VERSION 5.8 ;
BUSBITCHARS "[]" ;
DIVIDERCHAR "/" ;
UNITS
    DATABASE MICRONS 1000 ;
END UNITS

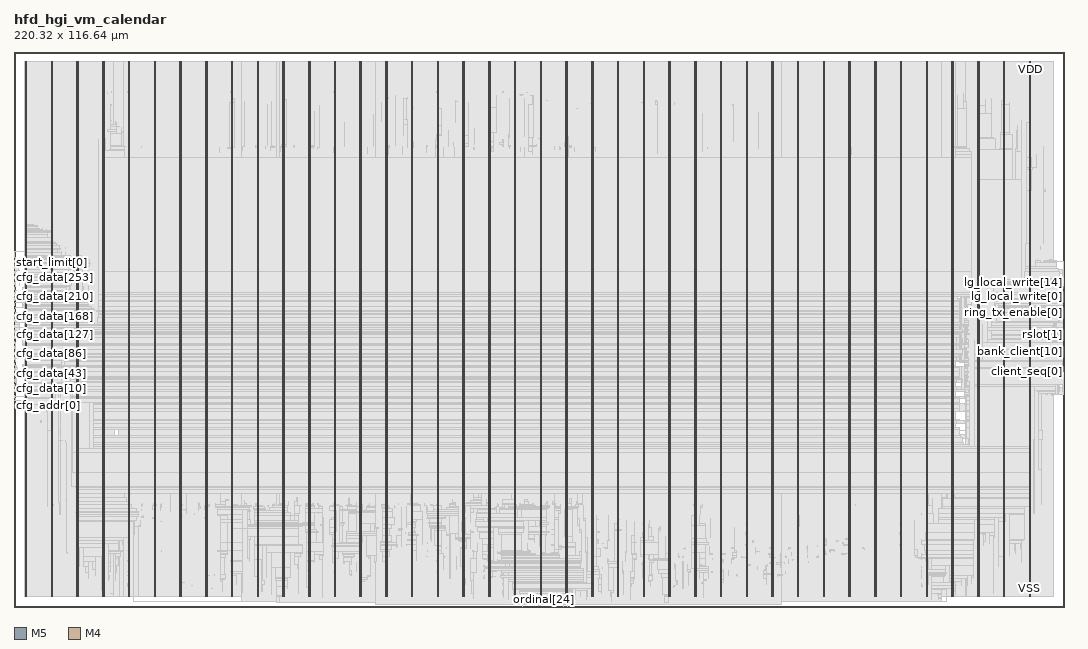
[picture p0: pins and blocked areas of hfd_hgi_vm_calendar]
MACRO hfd_hgi_vm_calendar
  FOREIGN hfd_hgi_vm_calendar 0 0 ;
  CLASS BLOCK ;
  SIZE 220.32 BY 116.64 ;
  PIN active
    DIRECTION OUTPUT ;
    USE SIGNAL ;
    PORT
      LAYER M5 ;
        RECT  108.576 0 108.6 0.084 ;
    END
  END active
  PIN bank_client[0]
    DIRECTION OUTPUT ;
    USE SIGNAL ;
    PORT
      LAYER M4 ;
        RECT  220.236 52.56 220.32 52.584 ;
    END
  END bank_client[0]
  PIN bank_client[10]
    DIRECTION OUTPUT ;
    USE SIGNAL ;
    PORT
      LAYER M4 ;
        RECT  220.236 53.52 220.32 53.544 ;
    END
  END bank_client[10]
  PIN bank_client[11]
    DIRECTION OUTPUT ;
    USE SIGNAL ;
    PORT
      LAYER M4 ;
        RECT  220.236 53.616 220.32 53.64 ;
    END
  END bank_client[11]
  PIN bank_client[12]
    DIRECTION OUTPUT ;
    USE SIGNAL ;
    PORT
      LAYER M4 ;
        RECT  220.236 53.712 220.32 53.736 ;
    END
  END bank_client[12]
  PIN bank_client[13]
    DIRECTION OUTPUT ;
    USE SIGNAL ;
    PORT
      LAYER M4 ;
        RECT  220.236 53.808 220.32 53.832 ;
    END
  END bank_client[13]
  PIN bank_client[14]
    DIRECTION OUTPUT ;
    USE SIGNAL ;
    PORT
      LAYER M4 ;
        RECT  220.236 53.904 220.32 53.928 ;
    END
  END bank_client[14]
  PIN bank_client[15]
    DIRECTION OUTPUT ;
    USE SIGNAL ;
    PORT
      LAYER M4 ;
        RECT  220.236 54 220.32 54.024 ;
    END
  END bank_client[15]
  PIN bank_client[16]
    DIRECTION OUTPUT ;
    USE SIGNAL ;
    PORT
      LAYER M4 ;
        RECT  220.236 54.096 220.32 54.12 ;
    END
  END bank_client[16]
  PIN bank_client[17]
    DIRECTION OUTPUT ;
    USE SIGNAL ;
    PORT
      LAYER M4 ;
        RECT  220.236 54.192 220.32 54.216 ;
    END
  END bank_client[17]
  PIN bank_client[18]
    DIRECTION OUTPUT ;
    USE SIGNAL ;
    PORT
      LAYER M4 ;
        RECT  220.236 54.288 220.32 54.312 ;
    END
  END bank_client[18]
  PIN bank_client[19]
    DIRECTION OUTPUT ;
    USE SIGNAL ;
    PORT
      LAYER M4 ;
        RECT  220.236 54.384 220.32 54.408 ;
    END
  END bank_client[19]
  PIN bank_client[1]
    DIRECTION OUTPUT ;
    USE SIGNAL ;
    PORT
      LAYER M4 ;
        RECT  220.236 52.656 220.32 52.68 ;
    END
  END bank_client[1]
  PIN bank_client[20]
    DIRECTION OUTPUT ;
    USE SIGNAL ;
    PORT
      LAYER M4 ;
        RECT  220.236 54.48 220.32 54.504 ;
    END
  END bank_client[20]
  PIN bank_client[21]
    DIRECTION OUTPUT ;
    USE SIGNAL ;
    PORT
      LAYER M4 ;
        RECT  220.236 54.576 220.32 54.6 ;
    END
  END bank_client[21]
  PIN bank_client[22]
    DIRECTION OUTPUT ;
    USE SIGNAL ;
    PORT
      LAYER M4 ;
        RECT  220.236 54.672 220.32 54.696 ;
    END
  END bank_client[22]
  PIN bank_client[23]
    DIRECTION OUTPUT ;
    USE SIGNAL ;
    PORT
      LAYER M4 ;
        RECT  220.236 54.768 220.32 54.792 ;
    END
  END bank_client[23]
  PIN bank_client[2]
    DIRECTION OUTPUT ;
    USE SIGNAL ;
    PORT
      LAYER M4 ;
        RECT  220.236 52.752 220.32 52.776 ;
    END
  END bank_client[2]
  PIN bank_client[3]
    DIRECTION OUTPUT ;
    USE SIGNAL ;
    PORT
      LAYER M4 ;
        RECT  220.236 52.848 220.32 52.872 ;
    END
  END bank_client[3]
  PIN bank_client[4]
    DIRECTION OUTPUT ;
    USE SIGNAL ;
    PORT
      LAYER M4 ;
        RECT  220.236 52.944 220.32 52.968 ;
    END
  END bank_client[4]
  PIN bank_client[5]
    DIRECTION OUTPUT ;
    USE SIGNAL ;
    PORT
      LAYER M4 ;
        RECT  220.236 53.04 220.32 53.064 ;
    END
  END bank_client[5]
  PIN bank_client[6]
    DIRECTION OUTPUT ;
    USE SIGNAL ;
    PORT
      LAYER M4 ;
        RECT  220.236 53.136 220.32 53.16 ;
    END
  END bank_client[6]
  PIN bank_client[7]
    DIRECTION OUTPUT ;
    USE SIGNAL ;
    PORT
      LAYER M4 ;
        RECT  220.236 53.232 220.32 53.256 ;
    END
  END bank_client[7]
  PIN bank_client[8]
    DIRECTION OUTPUT ;
    USE SIGNAL ;
    PORT
      LAYER M4 ;
        RECT  220.236 53.328 220.32 53.352 ;
    END
  END bank_client[8]
  PIN bank_client[9]
    DIRECTION OUTPUT ;
    USE SIGNAL ;
    PORT
      LAYER M4 ;
        RECT  220.236 53.424 220.32 53.448 ;
    END
  END bank_client[9]
  PIN bank_enable[0]
    DIRECTION OUTPUT ;
    USE SIGNAL ;
    PORT
      LAYER M4 ;
        RECT  220.236 51.792 220.32 51.816 ;
    END
  END bank_enable[0]
  PIN bank_enable[1]
    DIRECTION OUTPUT ;
    USE SIGNAL ;
    PORT
      LAYER M4 ;
        RECT  220.236 51.888 220.32 51.912 ;
    END
  END bank_enable[1]
  PIN bank_enable[2]
    DIRECTION OUTPUT ;
    USE SIGNAL ;
    PORT
      LAYER M4 ;
        RECT  220.236 51.984 220.32 52.008 ;
    END
  END bank_enable[2]
  PIN bank_enable[3]
    DIRECTION OUTPUT ;
    USE SIGNAL ;
    PORT
      LAYER M4 ;
        RECT  220.236 52.08 220.32 52.104 ;
    END
  END bank_enable[3]
  PIN bank_enable[4]
    DIRECTION OUTPUT ;
    USE SIGNAL ;
    PORT
      LAYER M4 ;
        RECT  220.236 52.176 220.32 52.2 ;
    END
  END bank_enable[4]
  PIN bank_enable[5]
    DIRECTION OUTPUT ;
    USE SIGNAL ;
    PORT
      LAYER M4 ;
        RECT  220.236 52.272 220.32 52.296 ;
    END
  END bank_enable[5]
  PIN bank_enable[6]
    DIRECTION OUTPUT ;
    USE SIGNAL ;
    PORT
      LAYER M4 ;
        RECT  220.236 52.368 220.32 52.392 ;
    END
  END bank_enable[6]
  PIN bank_enable[7]
    DIRECTION OUTPUT ;
    USE SIGNAL ;
    PORT
      LAYER M4 ;
        RECT  220.236 52.464 220.32 52.488 ;
    END
  END bank_enable[7]
  PIN calendar_v
    DIRECTION OUTPUT ;
    USE SIGNAL ;
    PORT
      LAYER M5 ;
        RECT  108.48 0 108.504 0.084 ;
    END
  END calendar_v
  PIN cfg_addr[0]
    DIRECTION INPUT ;
    USE SIGNAL ;
    PORT
      LAYER M4 ;
        RECT  0 43.92 0.084 43.944 ;
    END
  END cfg_addr[0]
  PIN cfg_addr[1]
    DIRECTION INPUT ;
    USE SIGNAL ;
    PORT
      LAYER M4 ;
        RECT  0 44.016 0.084 44.04 ;
    END
  END cfg_addr[1]
  PIN cfg_addr[2]
    DIRECTION INPUT ;
    USE SIGNAL ;
    PORT
      LAYER M4 ;
        RECT  0 44.112 0.084 44.136 ;
    END
  END cfg_addr[2]
  PIN cfg_addr[3]
    DIRECTION INPUT ;
    USE SIGNAL ;
    PORT
      LAYER M4 ;
        RECT  0 44.208 0.084 44.232 ;
    END
  END cfg_addr[3]
  PIN cfg_addr[4]
    DIRECTION INPUT ;
    USE SIGNAL ;
    PORT
      LAYER M4 ;
        RECT  0 44.304 0.084 44.328 ;
    END
  END cfg_addr[4]
  PIN cfg_addr[5]
    DIRECTION INPUT ;
    USE SIGNAL ;
    PORT
      LAYER M4 ;
        RECT  0 44.4 0.084 44.424 ;
    END
  END cfg_addr[5]
  PIN cfg_addr[6]
    DIRECTION INPUT ;
    USE SIGNAL ;
    PORT
      LAYER M4 ;
        RECT  0 44.496 0.084 44.52 ;
    END
  END cfg_addr[6]
  PIN cfg_addr[7]
    DIRECTION INPUT ;
    USE SIGNAL ;
    PORT
      LAYER M4 ;
        RECT  0 44.592 0.084 44.616 ;
    END
  END cfg_addr[7]
  PIN cfg_addr[8]
    DIRECTION INPUT ;
    USE SIGNAL ;
    PORT
      LAYER M4 ;
        RECT  0 44.688 0.084 44.712 ;
    END
  END cfg_addr[8]
  PIN cfg_addr[9]
    DIRECTION INPUT ;
    USE SIGNAL ;
    PORT
      LAYER M4 ;
        RECT  0 44.784 0.084 44.808 ;
    END
  END cfg_addr[9]
  PIN cfg_data[0]
    DIRECTION INPUT ;
    USE SIGNAL ;
    PORT
      LAYER M4 ;
        RECT  0 44.88 0.084 44.904 ;
    END
  END cfg_data[0]
  PIN cfg_data[100]
    DIRECTION INPUT ;
    USE SIGNAL ;
    PORT
      LAYER M4 ;
        RECT  0 54.48 0.084 54.504 ;
    END
  END cfg_data[100]
  PIN cfg_data[101]
    DIRECTION INPUT ;
    USE SIGNAL ;
    PORT
      LAYER M4 ;
        RECT  0 54.576 0.084 54.6 ;
    END
  END cfg_data[101]
  PIN cfg_data[102]
    DIRECTION INPUT ;
    USE SIGNAL ;
    PORT
      LAYER M4 ;
        RECT  0 54.672 0.084 54.696 ;
    END
  END cfg_data[102]
  PIN cfg_data[103]
    DIRECTION INPUT ;
    USE SIGNAL ;
    PORT
      LAYER M4 ;
        RECT  0 54.768 0.084 54.792 ;
    END
  END cfg_data[103]
  PIN cfg_data[104]
    DIRECTION INPUT ;
    USE SIGNAL ;
    PORT
      LAYER M4 ;
        RECT  0 54.864 0.084 54.888 ;
    END
  END cfg_data[104]
  PIN cfg_data[105]
    DIRECTION INPUT ;
    USE SIGNAL ;
    PORT
      LAYER M4 ;
        RECT  0 54.96 0.084 54.984 ;
    END
  END cfg_data[105]
  PIN cfg_data[106]
    DIRECTION INPUT ;
    USE SIGNAL ;
    PORT
      LAYER M4 ;
        RECT  0 55.056 0.084 55.08 ;
    END
  END cfg_data[106]
  PIN cfg_data[107]
    DIRECTION INPUT ;
    USE SIGNAL ;
    PORT
      LAYER M4 ;
        RECT  0 55.152 0.084 55.176 ;
    END
  END cfg_data[107]
  PIN cfg_data[108]
    DIRECTION INPUT ;
    USE SIGNAL ;
    PORT
      LAYER M4 ;
        RECT  0 55.248 0.084 55.272 ;
    END
  END cfg_data[108]
  PIN cfg_data[109]
    DIRECTION INPUT ;
    USE SIGNAL ;
    PORT
      LAYER M4 ;
        RECT  0 55.344 0.084 55.368 ;
    END
  END cfg_data[109]
  PIN cfg_data[10]
    DIRECTION INPUT ;
    USE SIGNAL ;
    PORT
      LAYER M4 ;
        RECT  0 45.84 0.084 45.864 ;
    END
  END cfg_data[10]
  PIN cfg_data[110]
    DIRECTION INPUT ;
    USE SIGNAL ;
    PORT
      LAYER M4 ;
        RECT  0 55.44 0.084 55.464 ;
    END
  END cfg_data[110]
  PIN cfg_data[111]
    DIRECTION INPUT ;
    USE SIGNAL ;
    PORT
      LAYER M4 ;
        RECT  0 55.536 0.084 55.56 ;
    END
  END cfg_data[111]
  PIN cfg_data[112]
    DIRECTION INPUT ;
    USE SIGNAL ;
    PORT
      LAYER M4 ;
        RECT  0 55.632 0.084 55.656 ;
    END
  END cfg_data[112]
  PIN cfg_data[113]
    DIRECTION INPUT ;
    USE SIGNAL ;
    PORT
      LAYER M4 ;
        RECT  0 55.728 0.084 55.752 ;
    END
  END cfg_data[113]
  PIN cfg_data[114]
    DIRECTION INPUT ;
    USE SIGNAL ;
    PORT
      LAYER M4 ;
        RECT  0 55.824 0.084 55.848 ;
    END
  END cfg_data[114]
  PIN cfg_data[115]
    DIRECTION INPUT ;
    USE SIGNAL ;
    PORT
      LAYER M4 ;
        RECT  0 55.92 0.084 55.944 ;
    END
  END cfg_data[115]
  PIN cfg_data[116]
    DIRECTION INPUT ;
    USE SIGNAL ;
    PORT
      LAYER M4 ;
        RECT  0 56.016 0.084 56.04 ;
    END
  END cfg_data[116]
  PIN cfg_data[117]
    DIRECTION INPUT ;
    USE SIGNAL ;
    PORT
      LAYER M4 ;
        RECT  0 56.112 0.084 56.136 ;
    END
  END cfg_data[117]
  PIN cfg_data[118]
    DIRECTION INPUT ;
    USE SIGNAL ;
    PORT
      LAYER M4 ;
        RECT  0 56.208 0.084 56.232 ;
    END
  END cfg_data[118]
  PIN cfg_data[119]
    DIRECTION INPUT ;
    USE SIGNAL ;
    PORT
      LAYER M4 ;
        RECT  0 56.304 0.084 56.328 ;
    END
  END cfg_data[119]
  PIN cfg_data[11]
    DIRECTION INPUT ;
    USE SIGNAL ;
    PORT
      LAYER M4 ;
        RECT  0 45.936 0.084 45.96 ;
    END
  END cfg_data[11]
  PIN cfg_data[120]
    DIRECTION INPUT ;
    USE SIGNAL ;
    PORT
      LAYER M4 ;
        RECT  0 56.4 0.084 56.424 ;
    END
  END cfg_data[120]
  PIN cfg_data[121]
    DIRECTION INPUT ;
    USE SIGNAL ;
    PORT
      LAYER M4 ;
        RECT  0 56.496 0.084 56.52 ;
    END
  END cfg_data[121]
  PIN cfg_data[122]
    DIRECTION INPUT ;
    USE SIGNAL ;
    PORT
      LAYER M4 ;
        RECT  0 56.592 0.084 56.616 ;
    END
  END cfg_data[122]
  PIN cfg_data[123]
    DIRECTION INPUT ;
    USE SIGNAL ;
    PORT
      LAYER M4 ;
        RECT  0 56.688 0.084 56.712 ;
    END
  END cfg_data[123]
  PIN cfg_data[124]
    DIRECTION INPUT ;
    USE SIGNAL ;
    PORT
      LAYER M4 ;
        RECT  0 56.784 0.084 56.808 ;
    END
  END cfg_data[124]
  PIN cfg_data[125]
    DIRECTION INPUT ;
    USE SIGNAL ;
    PORT
      LAYER M4 ;
        RECT  0 56.88 0.084 56.904 ;
    END
  END cfg_data[125]
  PIN cfg_data[126]
    DIRECTION INPUT ;
    USE SIGNAL ;
    PORT
      LAYER M4 ;
        RECT  0 56.976 0.084 57 ;
    END
  END cfg_data[126]
  PIN cfg_data[127]
    DIRECTION INPUT ;
    USE SIGNAL ;
    PORT
      LAYER M4 ;
        RECT  0 57.072 0.084 57.096 ;
    END
  END cfg_data[127]
  PIN cfg_data[128]
    DIRECTION INPUT ;
    USE SIGNAL ;
    PORT
      LAYER M4 ;
        RECT  0 57.168 0.084 57.192 ;
    END
  END cfg_data[128]
  PIN cfg_data[129]
    DIRECTION INPUT ;
    USE SIGNAL ;
    PORT
      LAYER M4 ;
        RECT  0 57.264 0.084 57.288 ;
    END
  END cfg_data[129]
  PIN cfg_data[12]
    DIRECTION INPUT ;
    USE SIGNAL ;
    PORT
      LAYER M4 ;
        RECT  0 46.032 0.084 46.056 ;
    END
  END cfg_data[12]
  PIN cfg_data[130]
    DIRECTION INPUT ;
    USE SIGNAL ;
    PORT
      LAYER M4 ;
        RECT  0 57.36 0.084 57.384 ;
    END
  END cfg_data[130]
  PIN cfg_data[131]
    DIRECTION INPUT ;
    USE SIGNAL ;
    PORT
      LAYER M4 ;
        RECT  0 57.456 0.084 57.48 ;
    END
  END cfg_data[131]
  PIN cfg_data[132]
    DIRECTION INPUT ;
    USE SIGNAL ;
    PORT
      LAYER M4 ;
        RECT  0 57.552 0.084 57.576 ;
    END
  END cfg_data[132]
  PIN cfg_data[133]
    DIRECTION INPUT ;
    USE SIGNAL ;
    PORT
      LAYER M4 ;
        RECT  0 57.648 0.084 57.672 ;
    END
  END cfg_data[133]
  PIN cfg_data[134]
    DIRECTION INPUT ;
    USE SIGNAL ;
    PORT
      LAYER M4 ;
        RECT  0 57.744 0.084 57.768 ;
    END
  END cfg_data[134]
  PIN cfg_data[135]
    DIRECTION INPUT ;
    USE SIGNAL ;
    PORT
      LAYER M4 ;
        RECT  0 57.84 0.084 57.864 ;
    END
  END cfg_data[135]
  PIN cfg_data[136]
    DIRECTION INPUT ;
    USE SIGNAL ;
    PORT
      LAYER M4 ;
        RECT  0 57.936 0.084 57.96 ;
    END
  END cfg_data[136]
  PIN cfg_data[137]
    DIRECTION INPUT ;
    USE SIGNAL ;
    PORT
      LAYER M4 ;
        RECT  0 58.032 0.084 58.056 ;
    END
  END cfg_data[137]
  PIN cfg_data[138]
    DIRECTION INPUT ;
    USE SIGNAL ;
    PORT
      LAYER M4 ;
        RECT  0 58.128 0.084 58.152 ;
    END
  END cfg_data[138]
  PIN cfg_data[139]
    DIRECTION INPUT ;
    USE SIGNAL ;
    PORT
      LAYER M4 ;
        RECT  0 58.224 0.084 58.248 ;
    END
  END cfg_data[139]
  PIN cfg_data[13]
    DIRECTION INPUT ;
    USE SIGNAL ;
    PORT
      LAYER M4 ;
        RECT  0 46.128 0.084 46.152 ;
    END
  END cfg_data[13]
  PIN cfg_data[140]
    DIRECTION INPUT ;
    USE SIGNAL ;
    PORT
      LAYER M4 ;
        RECT  0 58.32 0.084 58.344 ;
    END
  END cfg_data[140]
  PIN cfg_data[141]
    DIRECTION INPUT ;
    USE SIGNAL ;
    PORT
      LAYER M4 ;
        RECT  0 58.416 0.084 58.44 ;
    END
  END cfg_data[141]
  PIN cfg_data[142]
    DIRECTION INPUT ;
    USE SIGNAL ;
    PORT
      LAYER M4 ;
        RECT  0 58.512 0.084 58.536 ;
    END
  END cfg_data[142]
  PIN cfg_data[143]
    DIRECTION INPUT ;
    USE SIGNAL ;
    PORT
      LAYER M4 ;
        RECT  0 58.608 0.084 58.632 ;
    END
  END cfg_data[143]
  PIN cfg_data[144]
    DIRECTION INPUT ;
    USE SIGNAL ;
    PORT
      LAYER M4 ;
        RECT  0 58.704 0.084 58.728 ;
    END
  END cfg_data[144]
  PIN cfg_data[145]
    DIRECTION INPUT ;
    USE SIGNAL ;
    PORT
      LAYER M4 ;
        RECT  0 58.8 0.084 58.824 ;
    END
  END cfg_data[145]
  PIN cfg_data[146]
    DIRECTION INPUT ;
    USE SIGNAL ;
    PORT
      LAYER M4 ;
        RECT  0 58.896 0.084 58.92 ;
    END
  END cfg_data[146]
  PIN cfg_data[147]
    DIRECTION INPUT ;
    USE SIGNAL ;
    PORT
      LAYER M4 ;
        RECT  0 58.992 0.084 59.016 ;
    END
  END cfg_data[147]
  PIN cfg_data[148]
    DIRECTION INPUT ;
    USE SIGNAL ;
    PORT
      LAYER M4 ;
        RECT  0 59.088 0.084 59.112 ;
    END
  END cfg_data[148]
  PIN cfg_data[149]
    DIRECTION INPUT ;
    USE SIGNAL ;
    PORT
      LAYER M4 ;
        RECT  0 59.184 0.084 59.208 ;
    END
  END cfg_data[149]
  PIN cfg_data[14]
    DIRECTION INPUT ;
    USE SIGNAL ;
    PORT
      LAYER M4 ;
        RECT  0 46.224 0.084 46.248 ;
    END
  END cfg_data[14]
  PIN cfg_data[150]
    DIRECTION INPUT ;
    USE SIGNAL ;
    PORT
      LAYER M4 ;
        RECT  0 59.28 0.084 59.304 ;
    END
  END cfg_data[150]
  PIN cfg_data[151]
    DIRECTION INPUT ;
    USE SIGNAL ;
    PORT
      LAYER M4 ;
        RECT  0 59.376 0.084 59.4 ;
    END
  END cfg_data[151]
  PIN cfg_data[152]
    DIRECTION INPUT ;
    USE SIGNAL ;
    PORT
      LAYER M4 ;
        RECT  0 59.472 0.084 59.496 ;
    END
  END cfg_data[152]
  PIN cfg_data[153]
    DIRECTION INPUT ;
    USE SIGNAL ;
    PORT
      LAYER M4 ;
        RECT  0 59.568 0.084 59.592 ;
    END
  END cfg_data[153]
  PIN cfg_data[154]
    DIRECTION INPUT ;
    USE SIGNAL ;
    PORT
      LAYER M4 ;
        RECT  0 59.664 0.084 59.688 ;
    END
  END cfg_data[154]
  PIN cfg_data[155]
    DIRECTION INPUT ;
    USE SIGNAL ;
    PORT
      LAYER M4 ;
        RECT  0 59.76 0.084 59.784 ;
    END
  END cfg_data[155]
  PIN cfg_data[156]
    DIRECTION INPUT ;
    USE SIGNAL ;
    PORT
      LAYER M4 ;
        RECT  0 59.856 0.084 59.88 ;
    END
  END cfg_data[156]
  PIN cfg_data[157]
    DIRECTION INPUT ;
    USE SIGNAL ;
    PORT
      LAYER M4 ;
        RECT  0 59.952 0.084 59.976 ;
    END
  END cfg_data[157]
  PIN cfg_data[158]
    DIRECTION INPUT ;
    USE SIGNAL ;
    PORT
      LAYER M4 ;
        RECT  0 60.048 0.084 60.072 ;
    END
  END cfg_data[158]
  PIN cfg_data[159]
    DIRECTION INPUT ;
    USE SIGNAL ;
    PORT
      LAYER M4 ;
        RECT  0 60.144 0.084 60.168 ;
    END
  END cfg_data[159]
  PIN cfg_data[15]
    DIRECTION INPUT ;
    USE SIGNAL ;
    PORT
      LAYER M4 ;
        RECT  0 46.32 0.084 46.344 ;
    END
  END cfg_data[15]
  PIN cfg_data[160]
    DIRECTION INPUT ;
    USE SIGNAL ;
    PORT
      LAYER M4 ;
        RECT  0 60.24 0.084 60.264 ;
    END
  END cfg_data[160]
  PIN cfg_data[161]
    DIRECTION INPUT ;
    USE SIGNAL ;
    PORT
      LAYER M4 ;
        RECT  0 60.336 0.084 60.36 ;
    END
  END cfg_data[161]
  PIN cfg_data[162]
    DIRECTION INPUT ;
    USE SIGNAL ;
    PORT
      LAYER M4 ;
        RECT  0 60.432 0.084 60.456 ;
    END
  END cfg_data[162]
  PIN cfg_data[163]
    DIRECTION INPUT ;
    USE SIGNAL ;
    PORT
      LAYER M4 ;
        RECT  0 60.528 0.084 60.552 ;
    END
  END cfg_data[163]
  PIN cfg_data[164]
    DIRECTION INPUT ;
    USE SIGNAL ;
    PORT
      LAYER M4 ;
        RECT  0 60.624 0.084 60.648 ;
    END
  END cfg_data[164]
  PIN cfg_data[165]
    DIRECTION INPUT ;
    USE SIGNAL ;
    PORT
      LAYER M4 ;
        RECT  0 60.72 0.084 60.744 ;
    END
  END cfg_data[165]
  PIN cfg_data[166]
    DIRECTION INPUT ;
    USE SIGNAL ;
    PORT
      LAYER M4 ;
        RECT  0 60.816 0.084 60.84 ;
    END
  END cfg_data[166]
  PIN cfg_data[167]
    DIRECTION INPUT ;
    USE SIGNAL ;
    PORT
      LAYER M4 ;
        RECT  0 60.912 0.084 60.936 ;
    END
  END cfg_data[167]
  PIN cfg_data[168]
    DIRECTION INPUT ;
    USE SIGNAL ;
    PORT
      LAYER M4 ;
        RECT  0 61.008 0.084 61.032 ;
    END
  END cfg_data[168]
  PIN cfg_data[169]
    DIRECTION INPUT ;
    USE SIGNAL ;
    PORT
      LAYER M4 ;
        RECT  0 61.104 0.084 61.128 ;
    END
  END cfg_data[169]
  PIN cfg_data[16]
    DIRECTION INPUT ;
    USE SIGNAL ;
    PORT
      LAYER M4 ;
        RECT  0 46.416 0.084 46.44 ;
    END
  END cfg_data[16]
  PIN cfg_data[170]
    DIRECTION INPUT ;
    USE SIGNAL ;
    PORT
      LAYER M4 ;
        RECT  0 61.2 0.084 61.224 ;
    END
  END cfg_data[170]
  PIN cfg_data[171]
    DIRECTION INPUT ;
    USE SIGNAL ;
    PORT
      LAYER M4 ;
        RECT  0 61.296 0.084 61.32 ;
    END
  END cfg_data[171]
  PIN cfg_data[172]
    DIRECTION INPUT ;
    USE SIGNAL ;
    PORT
      LAYER M4 ;
        RECT  0 61.392 0.084 61.416 ;
    END
  END cfg_data[172]
  PIN cfg_data[173]
    DIRECTION INPUT ;
    USE SIGNAL ;
    PORT
      LAYER M4 ;
        RECT  0 61.488 0.084 61.512 ;
    END
  END cfg_data[173]
  PIN cfg_data[174]
    DIRECTION INPUT ;
    USE SIGNAL ;
    PORT
      LAYER M4 ;
        RECT  0 61.584 0.084 61.608 ;
    END
  END cfg_data[174]
  PIN cfg_data[175]
    DIRECTION INPUT ;
    USE SIGNAL ;
    PORT
      LAYER M4 ;
        RECT  0 61.68 0.084 61.704 ;
    END
  END cfg_data[175]
  PIN cfg_data[176]
    DIRECTION INPUT ;
    USE SIGNAL ;
    PORT
      LAYER M4 ;
        RECT  0 61.776 0.084 61.8 ;
    END
  END cfg_data[176]
  PIN cfg_data[177]
    DIRECTION INPUT ;
    USE SIGNAL ;
    PORT
      LAYER M4 ;
        RECT  0 61.872 0.084 61.896 ;
    END
  END cfg_data[177]
  PIN cfg_data[178]
    DIRECTION INPUT ;
    USE SIGNAL ;
    PORT
      LAYER M4 ;
        RECT  0 61.968 0.084 61.992 ;
    END
  END cfg_data[178]
  PIN cfg_data[179]
    DIRECTION INPUT ;
    USE SIGNAL ;
    PORT
      LAYER M4 ;
        RECT  0 62.064 0.084 62.088 ;
    END
  END cfg_data[179]
  PIN cfg_data[17]
    DIRECTION INPUT ;
    USE SIGNAL ;
    PORT
      LAYER M4 ;
        RECT  0 46.512 0.084 46.536 ;
    END
  END cfg_data[17]
  PIN cfg_data[180]
    DIRECTION INPUT ;
    USE SIGNAL ;
    PORT
      LAYER M4 ;
        RECT  0 62.16 0.084 62.184 ;
    END
  END cfg_data[180]
  PIN cfg_data[181]
    DIRECTION INPUT ;
    USE SIGNAL ;
    PORT
      LAYER M4 ;
        RECT  0 62.256 0.084 62.28 ;
    END
  END cfg_data[181]
  PIN cfg_data[182]
    DIRECTION INPUT ;
    USE SIGNAL ;
    PORT
      LAYER M4 ;
        RECT  0 62.352 0.084 62.376 ;
    END
  END cfg_data[182]
  PIN cfg_data[183]
    DIRECTION INPUT ;
    USE SIGNAL ;
    PORT
      LAYER M4 ;
        RECT  0 62.448 0.084 62.472 ;
    END
  END cfg_data[183]
  PIN cfg_data[184]
    DIRECTION INPUT ;
    USE SIGNAL ;
    PORT
      LAYER M4 ;
        RECT  0 62.544 0.084 62.568 ;
    END
  END cfg_data[184]
  PIN cfg_data[185]
    DIRECTION INPUT ;
    USE SIGNAL ;
    PORT
      LAYER M4 ;
        RECT  0 62.64 0.084 62.664 ;
    END
  END cfg_data[185]
  PIN cfg_data[186]
    DIRECTION INPUT ;
    USE SIGNAL ;
    PORT
      LAYER M4 ;
        RECT  0 62.736 0.084 62.76 ;
    END
  END cfg_data[186]
  PIN cfg_data[187]
    DIRECTION INPUT ;
    USE SIGNAL ;
    PORT
      LAYER M4 ;
        RECT  0 62.832 0.084 62.856 ;
    END
  END cfg_data[187]
  PIN cfg_data[188]
    DIRECTION INPUT ;
    USE SIGNAL ;
    PORT
      LAYER M4 ;
        RECT  0 62.928 0.084 62.952 ;
    END
  END cfg_data[188]
  PIN cfg_data[189]
    DIRECTION INPUT ;
    USE SIGNAL ;
    PORT
      LAYER M4 ;
        RECT  0 63.024 0.084 63.048 ;
    END
  END cfg_data[189]
  PIN cfg_data[18]
    DIRECTION INPUT ;
    USE SIGNAL ;
    PORT
      LAYER M4 ;
        RECT  0 46.608 0.084 46.632 ;
    END
  END cfg_data[18]
  PIN cfg_data[190]
    DIRECTION INPUT ;
    USE SIGNAL ;
    PORT
      LAYER M4 ;
        RECT  0 63.12 0.084 63.144 ;
    END
  END cfg_data[190]
  PIN cfg_data[191]
    DIRECTION INPUT ;
    USE SIGNAL ;
    PORT
      LAYER M4 ;
        RECT  0 63.216 0.084 63.24 ;
    END
  END cfg_data[191]
  PIN cfg_data[192]
    DIRECTION INPUT ;
    USE SIGNAL ;
    PORT
      LAYER M4 ;
        RECT  0 63.312 0.084 63.336 ;
    END
  END cfg_data[192]
  PIN cfg_data[193]
    DIRECTION INPUT ;
    USE SIGNAL ;
    PORT
      LAYER M4 ;
        RECT  0 63.408 0.084 63.432 ;
    END
  END cfg_data[193]
  PIN cfg_data[194]
    DIRECTION INPUT ;
    USE SIGNAL ;
    PORT
      LAYER M4 ;
        RECT  0 63.504 0.084 63.528 ;
    END
  END cfg_data[194]
  PIN cfg_data[195]
    DIRECTION INPUT ;
    USE SIGNAL ;
    PORT
      LAYER M4 ;
        RECT  0 63.6 0.084 63.624 ;
    END
  END cfg_data[195]
  PIN cfg_data[196]
    DIRECTION INPUT ;
    USE SIGNAL ;
    PORT
      LAYER M4 ;
        RECT  0 63.696 0.084 63.72 ;
    END
  END cfg_data[196]
  PIN cfg_data[197]
    DIRECTION INPUT ;
    USE SIGNAL ;
    PORT
      LAYER M4 ;
        RECT  0 63.792 0.084 63.816 ;
    END
  END cfg_data[197]
  PIN cfg_data[198]
    DIRECTION INPUT ;
    USE SIGNAL ;
    PORT
      LAYER M4 ;
        RECT  0 63.888 0.084 63.912 ;
    END
  END cfg_data[198]
  PIN cfg_data[199]
    DIRECTION INPUT ;
    USE SIGNAL ;
    PORT
      LAYER M4 ;
        RECT  0 63.984 0.084 64.008 ;
    END
  END cfg_data[199]
  PIN cfg_data[19]
    DIRECTION INPUT ;
    USE SIGNAL ;
    PORT
      LAYER M4 ;
        RECT  0 46.704 0.084 46.728 ;
    END
  END cfg_data[19]
  PIN cfg_data[1]
    DIRECTION INPUT ;
    USE SIGNAL ;
    PORT
      LAYER M4 ;
        RECT  0 44.976 0.084 45 ;
    END
  END cfg_data[1]
  PIN cfg_data[200]
    DIRECTION INPUT ;
    USE SIGNAL ;
    PORT
      LAYER M4 ;
        RECT  0 64.08 0.084 64.104 ;
    END
  END cfg_data[200]
  PIN cfg_data[201]
    DIRECTION INPUT ;
    USE SIGNAL ;
    PORT
      LAYER M4 ;
        RECT  0 64.176 0.084 64.2 ;
    END
  END cfg_data[201]
  PIN cfg_data[202]
    DIRECTION INPUT ;
    USE SIGNAL ;
    PORT
      LAYER M4 ;
        RECT  0 64.272 0.084 64.296 ;
    END
  END cfg_data[202]
  PIN cfg_data[203]
    DIRECTION INPUT ;
    USE SIGNAL ;
    PORT
      LAYER M4 ;
        RECT  0 64.368 0.084 64.392 ;
    END
  END cfg_data[203]
  PIN cfg_data[204]
    DIRECTION INPUT ;
    USE SIGNAL ;
    PORT
      LAYER M4 ;
        RECT  0 64.464 0.084 64.488 ;
    END
  END cfg_data[204]
  PIN cfg_data[205]
    DIRECTION INPUT ;
    USE SIGNAL ;
    PORT
      LAYER M4 ;
        RECT  0 64.56 0.084 64.584 ;
    END
  END cfg_data[205]
  PIN cfg_data[206]
    DIRECTION INPUT ;
    USE SIGNAL ;
    PORT
      LAYER M4 ;
        RECT  0 64.656 0.084 64.68 ;
    END
  END cfg_data[206]
  PIN cfg_data[207]
    DIRECTION INPUT ;
    USE SIGNAL ;
    PORT
      LAYER M4 ;
        RECT  0 64.752 0.084 64.776 ;
    END
  END cfg_data[207]
  PIN cfg_data[208]
    DIRECTION INPUT ;
    USE SIGNAL ;
    PORT
      LAYER M4 ;
        RECT  0 64.848 0.084 64.872 ;
    END
  END cfg_data[208]
  PIN cfg_data[209]
    DIRECTION INPUT ;
    USE SIGNAL ;
    PORT
      LAYER M4 ;
        RECT  0 64.944 0.084 64.968 ;
    END
  END cfg_data[209]
  PIN cfg_data[20]
    DIRECTION INPUT ;
    USE SIGNAL ;
    PORT
      LAYER M4 ;
        RECT  0 46.8 0.084 46.824 ;
    END
  END cfg_data[20]
  PIN cfg_data[210]
    DIRECTION INPUT ;
    USE SIGNAL ;
    PORT
      LAYER M4 ;
        RECT  0 65.04 0.084 65.064 ;
    END
  END cfg_data[210]
  PIN cfg_data[211]
    DIRECTION INPUT ;
    USE SIGNAL ;
    PORT
      LAYER M4 ;
        RECT  0 65.136 0.084 65.16 ;
    END
  END cfg_data[211]
  PIN cfg_data[212]
    DIRECTION INPUT ;
    USE SIGNAL ;
    PORT
      LAYER M4 ;
        RECT  0 65.232 0.084 65.256 ;
    END
  END cfg_data[212]
  PIN cfg_data[213]
    DIRECTION INPUT ;
    USE SIGNAL ;
    PORT
      LAYER M4 ;
        RECT  0 65.328 0.084 65.352 ;
    END
  END cfg_data[213]
  PIN cfg_data[214]
    DIRECTION INPUT ;
    USE SIGNAL ;
    PORT
      LAYER M4 ;
        RECT  0 65.424 0.084 65.448 ;
    END
  END cfg_data[214]
  PIN cfg_data[215]
    DIRECTION INPUT ;
    USE SIGNAL ;
    PORT
      LAYER M4 ;
        RECT  0 65.52 0.084 65.544 ;
    END
  END cfg_data[215]
  PIN cfg_data[216]
    DIRECTION INPUT ;
    USE SIGNAL ;
    PORT
      LAYER M4 ;
        RECT  0 65.616 0.084 65.64 ;
    END
  END cfg_data[216]
  PIN cfg_data[217]
    DIRECTION INPUT ;
    USE SIGNAL ;
    PORT
      LAYER M4 ;
        RECT  0 65.712 0.084 65.736 ;
    END
  END cfg_data[217]
  PIN cfg_data[218]
    DIRECTION INPUT ;
    USE SIGNAL ;
    PORT
      LAYER M4 ;
        RECT  0 65.808 0.084 65.832 ;
    END
  END cfg_data[218]
  PIN cfg_data[219]
    DIRECTION INPUT ;
    USE SIGNAL ;
    PORT
      LAYER M4 ;
        RECT  0 65.904 0.084 65.928 ;
    END
  END cfg_data[219]
  PIN cfg_data[21]
    DIRECTION INPUT ;
    USE SIGNAL ;
    PORT
      LAYER M4 ;
        RECT  0 46.896 0.084 46.92 ;
    END
  END cfg_data[21]
  PIN cfg_data[220]
    DIRECTION INPUT ;
    USE SIGNAL ;
    PORT
      LAYER M4 ;
        RECT  0 66 0.084 66.024 ;
    END
  END cfg_data[220]
  PIN cfg_data[221]
    DIRECTION INPUT ;
    USE SIGNAL ;
    PORT
      LAYER M4 ;
        RECT  0 66.096 0.084 66.12 ;
    END
  END cfg_data[221]
  PIN cfg_data[222]
    DIRECTION INPUT ;
    USE SIGNAL ;
    PORT
      LAYER M4 ;
        RECT  0 66.192 0.084 66.216 ;
    END
  END cfg_data[222]
  PIN cfg_data[223]
    DIRECTION INPUT ;
    USE SIGNAL ;
    PORT
      LAYER M4 ;
        RECT  0 66.288 0.084 66.312 ;
    END
  END cfg_data[223]
  PIN cfg_data[224]
    DIRECTION INPUT ;
    USE SIGNAL ;
    PORT
      LAYER M4 ;
        RECT  0 66.384 0.084 66.408 ;
    END
  END cfg_data[224]
  PIN cfg_data[225]
    DIRECTION INPUT ;
    USE SIGNAL ;
    PORT
      LAYER M4 ;
        RECT  0 66.48 0.084 66.504 ;
    END
  END cfg_data[225]
  PIN cfg_data[226]
    DIRECTION INPUT ;
    USE SIGNAL ;
    PORT
      LAYER M4 ;
        RECT  0 66.576 0.084 66.6 ;
    END
  END cfg_data[226]
  PIN cfg_data[227]
    DIRECTION INPUT ;
    USE SIGNAL ;
    PORT
      LAYER M4 ;
        RECT  0 66.672 0.084 66.696 ;
    END
  END cfg_data[227]
  PIN cfg_data[228]
    DIRECTION INPUT ;
    USE SIGNAL ;
    PORT
      LAYER M4 ;
        RECT  0 66.768 0.084 66.792 ;
    END
  END cfg_data[228]
  PIN cfg_data[229]
    DIRECTION INPUT ;
    USE SIGNAL ;
    PORT
      LAYER M4 ;
        RECT  0 66.864 0.084 66.888 ;
    END
  END cfg_data[229]
  PIN cfg_data[22]
    DIRECTION INPUT ;
    USE SIGNAL ;
    PORT
      LAYER M4 ;
        RECT  0 46.992 0.084 47.016 ;
    END
  END cfg_data[22]
  PIN cfg_data[230]
    DIRECTION INPUT ;
    USE SIGNAL ;
    PORT
      LAYER M4 ;
        RECT  0 66.96 0.084 66.984 ;
    END
  END cfg_data[230]
  PIN cfg_data[231]
    DIRECTION INPUT ;
    USE SIGNAL ;
    PORT
      LAYER M4 ;
        RECT  0 67.056 0.084 67.08 ;
    END
  END cfg_data[231]
  PIN cfg_data[232]
    DIRECTION INPUT ;
    USE SIGNAL ;
    PORT
      LAYER M4 ;
        RECT  0 67.152 0.084 67.176 ;
    END
  END cfg_data[232]
  PIN cfg_data[233]
    DIRECTION INPUT ;
    USE SIGNAL ;
    PORT
      LAYER M4 ;
        RECT  0 67.248 0.084 67.272 ;
    END
  END cfg_data[233]
  PIN cfg_data[234]
    DIRECTION INPUT ;
    USE SIGNAL ;
    PORT
      LAYER M4 ;
        RECT  0 67.344 0.084 67.368 ;
    END
  END cfg_data[234]
  PIN cfg_data[235]
    DIRECTION INPUT ;
    USE SIGNAL ;
    PORT
      LAYER M4 ;
        RECT  0 67.44 0.084 67.464 ;
    END
  END cfg_data[235]
  PIN cfg_data[236]
    DIRECTION INPUT ;
    USE SIGNAL ;
    PORT
      LAYER M4 ;
        RECT  0 67.536 0.084 67.56 ;
    END
  END cfg_data[236]
  PIN cfg_data[237]
    DIRECTION INPUT ;
    USE SIGNAL ;
    PORT
      LAYER M4 ;
        RECT  0 67.632 0.084 67.656 ;
    END
  END cfg_data[237]
  PIN cfg_data[238]
    DIRECTION INPUT ;
    USE SIGNAL ;
    PORT
      LAYER M4 ;
        RECT  0 67.728 0.084 67.752 ;
    END
  END cfg_data[238]
  PIN cfg_data[239]
    DIRECTION INPUT ;
    USE SIGNAL ;
    PORT
      LAYER M4 ;
        RECT  0 67.824 0.084 67.848 ;
    END
  END cfg_data[239]
  PIN cfg_data[23]
    DIRECTION INPUT ;
    USE SIGNAL ;
    PORT
      LAYER M4 ;
        RECT  0 47.088 0.084 47.112 ;
    END
  END cfg_data[23]
  PIN cfg_data[240]
    DIRECTION INPUT ;
    USE SIGNAL ;
    PORT
      LAYER M4 ;
        RECT  0 67.92 0.084 67.944 ;
    END
  END cfg_data[240]
  PIN cfg_data[241]
    DIRECTION INPUT ;
    USE SIGNAL ;
    PORT
      LAYER M4 ;
        RECT  0 68.016 0.084 68.04 ;
    END
  END cfg_data[241]
  PIN cfg_data[242]
    DIRECTION INPUT ;
    USE SIGNAL ;
    PORT
      LAYER M4 ;
        RECT  0 68.112 0.084 68.136 ;
    END
  END cfg_data[242]
  PIN cfg_data[243]
    DIRECTION INPUT ;
    USE SIGNAL ;
    PORT
      LAYER M4 ;
        RECT  0 68.208 0.084 68.232 ;
    END
  END cfg_data[243]
  PIN cfg_data[244]
    DIRECTION INPUT ;
    USE SIGNAL ;
    PORT
      LAYER M4 ;
        RECT  0 68.304 0.084 68.328 ;
    END
  END cfg_data[244]
  PIN cfg_data[245]
    DIRECTION INPUT ;
    USE SIGNAL ;
    PORT
      LAYER M4 ;
        RECT  0 68.4 0.084 68.424 ;
    END
  END cfg_data[245]
  PIN cfg_data[246]
    DIRECTION INPUT ;
    USE SIGNAL ;
    PORT
      LAYER M4 ;
        RECT  0 68.496 0.084 68.52 ;
    END
  END cfg_data[246]
  PIN cfg_data[247]
    DIRECTION INPUT ;
    USE SIGNAL ;
    PORT
      LAYER M4 ;
        RECT  0 68.592 0.084 68.616 ;
    END
  END cfg_data[247]
  PIN cfg_data[248]
    DIRECTION INPUT ;
    USE SIGNAL ;
    PORT
      LAYER M4 ;
        RECT  0 68.688 0.084 68.712 ;
    END
  END cfg_data[248]
  PIN cfg_data[249]
    DIRECTION INPUT ;
    USE SIGNAL ;
    PORT
      LAYER M4 ;
        RECT  0 68.784 0.084 68.808 ;
    END
  END cfg_data[249]
  PIN cfg_data[24]
    DIRECTION INPUT ;
    USE SIGNAL ;
    PORT
      LAYER M4 ;
        RECT  0 47.184 0.084 47.208 ;
    END
  END cfg_data[24]
  PIN cfg_data[250]
    DIRECTION INPUT ;
    USE SIGNAL ;
    PORT
      LAYER M4 ;
        RECT  0 68.88 0.084 68.904 ;
    END
  END cfg_data[250]
  PIN cfg_data[251]
    DIRECTION INPUT ;
    USE SIGNAL ;
    PORT
      LAYER M4 ;
        RECT  0 68.976 0.084 69 ;
    END
  END cfg_data[251]
  PIN cfg_data[252]
    DIRECTION INPUT ;
    USE SIGNAL ;
    PORT
      LAYER M4 ;
        RECT  0 69.072 0.084 69.096 ;
    END
  END cfg_data[252]
  PIN cfg_data[253]
    DIRECTION INPUT ;
    USE SIGNAL ;
    PORT
      LAYER M4 ;
        RECT  0 69.168 0.084 69.192 ;
    END
  END cfg_data[253]
  PIN cfg_data[254]
    DIRECTION INPUT ;
    USE SIGNAL ;
    PORT
      LAYER M4 ;
        RECT  0 69.264 0.084 69.288 ;
    END
  END cfg_data[254]
  PIN cfg_data[255]
    DIRECTION INPUT ;
    USE SIGNAL ;
    PORT
      LAYER M4 ;
        RECT  0 69.36 0.084 69.384 ;
    END
  END cfg_data[255]
  PIN cfg_data[25]
    DIRECTION INPUT ;
    USE SIGNAL ;
    PORT
      LAYER M4 ;
        RECT  0 47.28 0.084 47.304 ;
    END
  END cfg_data[25]
  PIN cfg_data[26]
    DIRECTION INPUT ;
    USE SIGNAL ;
    PORT
      LAYER M4 ;
        RECT  0 47.376 0.084 47.4 ;
    END
  END cfg_data[26]
  PIN cfg_data[27]
    DIRECTION INPUT ;
    USE SIGNAL ;
    PORT
      LAYER M4 ;
        RECT  0 47.472 0.084 47.496 ;
    END
  END cfg_data[27]
  PIN cfg_data[28]
    DIRECTION INPUT ;
    USE SIGNAL ;
    PORT
      LAYER M4 ;
        RECT  0 47.568 0.084 47.592 ;
    END
  END cfg_data[28]
  PIN cfg_data[29]
    DIRECTION INPUT ;
    USE SIGNAL ;
    PORT
      LAYER M4 ;
        RECT  0 47.664 0.084 47.688 ;
    END
  END cfg_data[29]
  PIN cfg_data[2]
    DIRECTION INPUT ;
    USE SIGNAL ;
    PORT
      LAYER M4 ;
        RECT  0 45.072 0.084 45.096 ;
    END
  END cfg_data[2]
  PIN cfg_data[30]
    DIRECTION INPUT ;
    USE SIGNAL ;
    PORT
      LAYER M4 ;
        RECT  0 47.76 0.084 47.784 ;
    END
  END cfg_data[30]
  PIN cfg_data[31]
    DIRECTION INPUT ;
    USE SIGNAL ;
    PORT
      LAYER M4 ;
        RECT  0 47.856 0.084 47.88 ;
    END
  END cfg_data[31]
  PIN cfg_data[32]
    DIRECTION INPUT ;
    USE SIGNAL ;
    PORT
      LAYER M4 ;
        RECT  0 47.952 0.084 47.976 ;
    END
  END cfg_data[32]
  PIN cfg_data[33]
    DIRECTION INPUT ;
    USE SIGNAL ;
    PORT
      LAYER M4 ;
        RECT  0 48.048 0.084 48.072 ;
    END
  END cfg_data[33]
  PIN cfg_data[34]
    DIRECTION INPUT ;
    USE SIGNAL ;
    PORT
      LAYER M4 ;
        RECT  0 48.144 0.084 48.168 ;
    END
  END cfg_data[34]
  PIN cfg_data[35]
    DIRECTION INPUT ;
    USE SIGNAL ;
    PORT
      LAYER M4 ;
        RECT  0 48.24 0.084 48.264 ;
    END
  END cfg_data[35]
  PIN cfg_data[36]
    DIRECTION INPUT ;
    USE SIGNAL ;
    PORT
      LAYER M4 ;
        RECT  0 48.336 0.084 48.36 ;
    END
  END cfg_data[36]
  PIN cfg_data[37]
    DIRECTION INPUT ;
    USE SIGNAL ;
    PORT
      LAYER M4 ;
        RECT  0 48.432 0.084 48.456 ;
    END
  END cfg_data[37]
  PIN cfg_data[38]
    DIRECTION INPUT ;
    USE SIGNAL ;
    PORT
      LAYER M4 ;
        RECT  0 48.528 0.084 48.552 ;
    END
  END cfg_data[38]
  PIN cfg_data[39]
    DIRECTION INPUT ;
    USE SIGNAL ;
    PORT
      LAYER M4 ;
        RECT  0 48.624 0.084 48.648 ;
    END
  END cfg_data[39]
  PIN cfg_data[3]
    DIRECTION INPUT ;
    USE SIGNAL ;
    PORT
      LAYER M4 ;
        RECT  0 45.168 0.084 45.192 ;
    END
  END cfg_data[3]
  PIN cfg_data[40]
    DIRECTION INPUT ;
    USE SIGNAL ;
    PORT
      LAYER M4 ;
        RECT  0 48.72 0.084 48.744 ;
    END
  END cfg_data[40]
  PIN cfg_data[41]
    DIRECTION INPUT ;
    USE SIGNAL ;
    PORT
      LAYER M4 ;
        RECT  0 48.816 0.084 48.84 ;
    END
  END cfg_data[41]
  PIN cfg_data[42]
    DIRECTION INPUT ;
    USE SIGNAL ;
    PORT
      LAYER M4 ;
        RECT  0 48.912 0.084 48.936 ;
    END
  END cfg_data[42]
  PIN cfg_data[43]
    DIRECTION INPUT ;
    USE SIGNAL ;
    PORT
      LAYER M4 ;
        RECT  0 49.008 0.084 49.032 ;
    END
  END cfg_data[43]
  PIN cfg_data[44]
    DIRECTION INPUT ;
    USE SIGNAL ;
    PORT
      LAYER M4 ;
        RECT  0 49.104 0.084 49.128 ;
    END
  END cfg_data[44]
  PIN cfg_data[45]
    DIRECTION INPUT ;
    USE SIGNAL ;
    PORT
      LAYER M4 ;
        RECT  0 49.2 0.084 49.224 ;
    END
  END cfg_data[45]
  PIN cfg_data[46]
    DIRECTION INPUT ;
    USE SIGNAL ;
    PORT
      LAYER M4 ;
        RECT  0 49.296 0.084 49.32 ;
    END
  END cfg_data[46]
  PIN cfg_data[47]
    DIRECTION INPUT ;
    USE SIGNAL ;
    PORT
      LAYER M4 ;
        RECT  0 49.392 0.084 49.416 ;
    END
  END cfg_data[47]
  PIN cfg_data[48]
    DIRECTION INPUT ;
    USE SIGNAL ;
    PORT
      LAYER M4 ;
        RECT  0 49.488 0.084 49.512 ;
    END
  END cfg_data[48]
  PIN cfg_data[49]
    DIRECTION INPUT ;
    USE SIGNAL ;
    PORT
      LAYER M4 ;
        RECT  0 49.584 0.084 49.608 ;
    END
  END cfg_data[49]
  PIN cfg_data[4]
    DIRECTION INPUT ;
    USE SIGNAL ;
    PORT
      LAYER M4 ;
        RECT  0 45.264 0.084 45.288 ;
    END
  END cfg_data[4]
  PIN cfg_data[50]
    DIRECTION INPUT ;
    USE SIGNAL ;
    PORT
      LAYER M4 ;
        RECT  0 49.68 0.084 49.704 ;
    END
  END cfg_data[50]
  PIN cfg_data[51]
    DIRECTION INPUT ;
    USE SIGNAL ;
    PORT
      LAYER M4 ;
        RECT  0 49.776 0.084 49.8 ;
    END
  END cfg_data[51]
  PIN cfg_data[52]
    DIRECTION INPUT ;
    USE SIGNAL ;
    PORT
      LAYER M4 ;
        RECT  0 49.872 0.084 49.896 ;
    END
  END cfg_data[52]
  PIN cfg_data[53]
    DIRECTION INPUT ;
    USE SIGNAL ;
    PORT
      LAYER M4 ;
        RECT  0 49.968 0.084 49.992 ;
    END
  END cfg_data[53]
  PIN cfg_data[54]
    DIRECTION INPUT ;
    USE SIGNAL ;
    PORT
      LAYER M4 ;
        RECT  0 50.064 0.084 50.088 ;
    END
  END cfg_data[54]
  PIN cfg_data[55]
    DIRECTION INPUT ;
    USE SIGNAL ;
    PORT
      LAYER M4 ;
        RECT  0 50.16 0.084 50.184 ;
    END
  END cfg_data[55]
  PIN cfg_data[56]
    DIRECTION INPUT ;
    USE SIGNAL ;
    PORT
      LAYER M4 ;
        RECT  0 50.256 0.084 50.28 ;
    END
  END cfg_data[56]
  PIN cfg_data[57]
    DIRECTION INPUT ;
    USE SIGNAL ;
    PORT
      LAYER M4 ;
        RECT  0 50.352 0.084 50.376 ;
    END
  END cfg_data[57]
  PIN cfg_data[58]
    DIRECTION INPUT ;
    USE SIGNAL ;
    PORT
      LAYER M4 ;
        RECT  0 50.448 0.084 50.472 ;
    END
  END cfg_data[58]
  PIN cfg_data[59]
    DIRECTION INPUT ;
    USE SIGNAL ;
    PORT
      LAYER M4 ;
        RECT  0 50.544 0.084 50.568 ;
    END
  END cfg_data[59]
  PIN cfg_data[5]
    DIRECTION INPUT ;
    USE SIGNAL ;
    PORT
      LAYER M4 ;
        RECT  0 45.36 0.084 45.384 ;
    END
  END cfg_data[5]
  PIN cfg_data[60]
    DIRECTION INPUT ;
    USE SIGNAL ;
    PORT
      LAYER M4 ;
        RECT  0 50.64 0.084 50.664 ;
    END
  END cfg_data[60]
  PIN cfg_data[61]
    DIRECTION INPUT ;
    USE SIGNAL ;
    PORT
      LAYER M4 ;
        RECT  0 50.736 0.084 50.76 ;
    END
  END cfg_data[61]
  PIN cfg_data[62]
    DIRECTION INPUT ;
    USE SIGNAL ;
    PORT
      LAYER M4 ;
        RECT  0 50.832 0.084 50.856 ;
    END
  END cfg_data[62]
  PIN cfg_data[63]
    DIRECTION INPUT ;
    USE SIGNAL ;
    PORT
      LAYER M4 ;
        RECT  0 50.928 0.084 50.952 ;
    END
  END cfg_data[63]
  PIN cfg_data[64]
    DIRECTION INPUT ;
    USE SIGNAL ;
    PORT
      LAYER M4 ;
        RECT  0 51.024 0.084 51.048 ;
    END
  END cfg_data[64]
  PIN cfg_data[65]
    DIRECTION INPUT ;
    USE SIGNAL ;
    PORT
      LAYER M4 ;
        RECT  0 51.12 0.084 51.144 ;
    END
  END cfg_data[65]
  PIN cfg_data[66]
    DIRECTION INPUT ;
    USE SIGNAL ;
    PORT
      LAYER M4 ;
        RECT  0 51.216 0.084 51.24 ;
    END
  END cfg_data[66]
  PIN cfg_data[67]
    DIRECTION INPUT ;
    USE SIGNAL ;
    PORT
      LAYER M4 ;
        RECT  0 51.312 0.084 51.336 ;
    END
  END cfg_data[67]
  PIN cfg_data[68]
    DIRECTION INPUT ;
    USE SIGNAL ;
    PORT
      LAYER M4 ;
        RECT  0 51.408 0.084 51.432 ;
    END
  END cfg_data[68]
  PIN cfg_data[69]
    DIRECTION INPUT ;
    USE SIGNAL ;
    PORT
      LAYER M4 ;
        RECT  0 51.504 0.084 51.528 ;
    END
  END cfg_data[69]
  PIN cfg_data[6]
    DIRECTION INPUT ;
    USE SIGNAL ;
    PORT
      LAYER M4 ;
        RECT  0 45.456 0.084 45.48 ;
    END
  END cfg_data[6]
  PIN cfg_data[70]
    DIRECTION INPUT ;
    USE SIGNAL ;
    PORT
      LAYER M4 ;
        RECT  0 51.6 0.084 51.624 ;
    END
  END cfg_data[70]
  PIN cfg_data[71]
    DIRECTION INPUT ;
    USE SIGNAL ;
    PORT
      LAYER M4 ;
        RECT  0 51.696 0.084 51.72 ;
    END
  END cfg_data[71]
  PIN cfg_data[72]
    DIRECTION INPUT ;
    USE SIGNAL ;
    PORT
      LAYER M4 ;
        RECT  0 51.792 0.084 51.816 ;
    END
  END cfg_data[72]
  PIN cfg_data[73]
    DIRECTION INPUT ;
    USE SIGNAL ;
    PORT
      LAYER M4 ;
        RECT  0 51.888 0.084 51.912 ;
    END
  END cfg_data[73]
  PIN cfg_data[74]
    DIRECTION INPUT ;
    USE SIGNAL ;
    PORT
      LAYER M4 ;
        RECT  0 51.984 0.084 52.008 ;
    END
  END cfg_data[74]
  PIN cfg_data[75]
    DIRECTION INPUT ;
    USE SIGNAL ;
    PORT
      LAYER M4 ;
        RECT  0 52.08 0.084 52.104 ;
    END
  END cfg_data[75]
  PIN cfg_data[76]
    DIRECTION INPUT ;
    USE SIGNAL ;
    PORT
      LAYER M4 ;
        RECT  0 52.176 0.084 52.2 ;
    END
  END cfg_data[76]
  PIN cfg_data[77]
    DIRECTION INPUT ;
    USE SIGNAL ;
    PORT
      LAYER M4 ;
        RECT  0 52.272 0.084 52.296 ;
    END
  END cfg_data[77]
  PIN cfg_data[78]
    DIRECTION INPUT ;
    USE SIGNAL ;
    PORT
      LAYER M4 ;
        RECT  0 52.368 0.084 52.392 ;
    END
  END cfg_data[78]
  PIN cfg_data[79]
    DIRECTION INPUT ;
    USE SIGNAL ;
    PORT
      LAYER M4 ;
        RECT  0 52.464 0.084 52.488 ;
    END
  END cfg_data[79]
  PIN cfg_data[7]
    DIRECTION INPUT ;
    USE SIGNAL ;
    PORT
      LAYER M4 ;
        RECT  0 45.552 0.084 45.576 ;
    END
  END cfg_data[7]
  PIN cfg_data[80]
    DIRECTION INPUT ;
    USE SIGNAL ;
    PORT
      LAYER M4 ;
        RECT  0 52.56 0.084 52.584 ;
    END
  END cfg_data[80]
  PIN cfg_data[81]
    DIRECTION INPUT ;
    USE SIGNAL ;
    PORT
      LAYER M4 ;
        RECT  0 52.656 0.084 52.68 ;
    END
  END cfg_data[81]
  PIN cfg_data[82]
    DIRECTION INPUT ;
    USE SIGNAL ;
    PORT
      LAYER M4 ;
        RECT  0 52.752 0.084 52.776 ;
    END
  END cfg_data[82]
  PIN cfg_data[83]
    DIRECTION INPUT ;
    USE SIGNAL ;
    PORT
      LAYER M4 ;
        RECT  0 52.848 0.084 52.872 ;
    END
  END cfg_data[83]
  PIN cfg_data[84]
    DIRECTION INPUT ;
    USE SIGNAL ;
    PORT
      LAYER M4 ;
        RECT  0 52.944 0.084 52.968 ;
    END
  END cfg_data[84]
  PIN cfg_data[85]
    DIRECTION INPUT ;
    USE SIGNAL ;
    PORT
      LAYER M4 ;
        RECT  0 53.04 0.084 53.064 ;
    END
  END cfg_data[85]
  PIN cfg_data[86]
    DIRECTION INPUT ;
    USE SIGNAL ;
    PORT
      LAYER M4 ;
        RECT  0 53.136 0.084 53.16 ;
    END
  END cfg_data[86]
  PIN cfg_data[87]
    DIRECTION INPUT ;
    USE SIGNAL ;
    PORT
      LAYER M4 ;
        RECT  0 53.232 0.084 53.256 ;
    END
  END cfg_data[87]
  PIN cfg_data[88]
    DIRECTION INPUT ;
    USE SIGNAL ;
    PORT
      LAYER M4 ;
        RECT  0 53.328 0.084 53.352 ;
    END
  END cfg_data[88]
  PIN cfg_data[89]
    DIRECTION INPUT ;
    USE SIGNAL ;
    PORT
      LAYER M4 ;
        RECT  0 53.424 0.084 53.448 ;
    END
  END cfg_data[89]
  PIN cfg_data[8]
    DIRECTION INPUT ;
    USE SIGNAL ;
    PORT
      LAYER M4 ;
        RECT  0 45.648 0.084 45.672 ;
    END
  END cfg_data[8]
  PIN cfg_data[90]
    DIRECTION INPUT ;
    USE SIGNAL ;
    PORT
      LAYER M4 ;
        RECT  0 53.52 0.084 53.544 ;
    END
  END cfg_data[90]
  PIN cfg_data[91]
    DIRECTION INPUT ;
    USE SIGNAL ;
    PORT
      LAYER M4 ;
        RECT  0 53.616 0.084 53.64 ;
    END
  END cfg_data[91]
  PIN cfg_data[92]
    DIRECTION INPUT ;
    USE SIGNAL ;
    PORT
      LAYER M4 ;
        RECT  0 53.712 0.084 53.736 ;
    END
  END cfg_data[92]
  PIN cfg_data[93]
    DIRECTION INPUT ;
    USE SIGNAL ;
    PORT
      LAYER M4 ;
        RECT  0 53.808 0.084 53.832 ;
    END
  END cfg_data[93]
  PIN cfg_data[94]
    DIRECTION INPUT ;
    USE SIGNAL ;
    PORT
      LAYER M4 ;
        RECT  0 53.904 0.084 53.928 ;
    END
  END cfg_data[94]
  PIN cfg_data[95]
    DIRECTION INPUT ;
    USE SIGNAL ;
    PORT
      LAYER M4 ;
        RECT  0 54 0.084 54.024 ;
    END
  END cfg_data[95]
  PIN cfg_data[96]
    DIRECTION INPUT ;
    USE SIGNAL ;
    PORT
      LAYER M4 ;
        RECT  0 54.096 0.084 54.12 ;
    END
  END cfg_data[96]
  PIN cfg_data[97]
    DIRECTION INPUT ;
    USE SIGNAL ;
    PORT
      LAYER M4 ;
        RECT  0 54.192 0.084 54.216 ;
    END
  END cfg_data[97]
  PIN cfg_data[98]
    DIRECTION INPUT ;
    USE SIGNAL ;
    PORT
      LAYER M4 ;
        RECT  0 54.288 0.084 54.312 ;
    END
  END cfg_data[98]
  PIN cfg_data[99]
    DIRECTION INPUT ;
    USE SIGNAL ;
    PORT
      LAYER M4 ;
        RECT  0 54.384 0.084 54.408 ;
    END
  END cfg_data[99]
  PIN cfg_data[9]
    DIRECTION INPUT ;
    USE SIGNAL ;
    PORT
      LAYER M4 ;
        RECT  0 45.744 0.084 45.768 ;
    END
  END cfg_data[9]
  PIN cfg_we
    DIRECTION INPUT ;
    USE SIGNAL ;
    PORT
      LAYER M4 ;
        RECT  0 43.824 0.084 43.848 ;
    END
  END cfg_we
  PIN client_seq[0]
    DIRECTION OUTPUT ;
    USE SIGNAL ;
    PORT
      LAYER M4 ;
        RECT  220.236 49.392 220.32 49.416 ;
    END
  END client_seq[0]
  PIN client_seq[1]
    DIRECTION OUTPUT ;
    USE SIGNAL ;
    PORT
      LAYER M4 ;
        RECT  220.236 49.488 220.32 49.512 ;
    END
  END client_seq[1]
  PIN client_seq[2]
    DIRECTION OUTPUT ;
    USE SIGNAL ;
    PORT
      LAYER M4 ;
        RECT  220.236 49.584 220.32 49.608 ;
    END
  END client_seq[2]
  PIN client_seq[3]
    DIRECTION OUTPUT ;
    USE SIGNAL ;
    PORT
      LAYER M4 ;
        RECT  220.236 49.68 220.32 49.704 ;
    END
  END client_seq[3]
  PIN client_seq[4]
    DIRECTION OUTPUT ;
    USE SIGNAL ;
    PORT
      LAYER M4 ;
        RECT  220.236 49.776 220.32 49.8 ;
    END
  END client_seq[4]
  PIN client_seq[5]
    DIRECTION OUTPUT ;
    USE SIGNAL ;
    PORT
      LAYER M4 ;
        RECT  220.236 49.872 220.32 49.896 ;
    END
  END client_seq[5]
  PIN client_seq[6]
    DIRECTION OUTPUT ;
    USE SIGNAL ;
    PORT
      LAYER M4 ;
        RECT  220.236 49.968 220.32 49.992 ;
    END
  END client_seq[6]
  PIN client_seq[7]
    DIRECTION OUTPUT ;
    USE SIGNAL ;
    PORT
      LAYER M4 ;
        RECT  220.236 50.064 220.32 50.088 ;
    END
  END client_seq[7]
  PIN client_seq[8]
    DIRECTION OUTPUT ;
    USE SIGNAL ;
    PORT
      LAYER M4 ;
        RECT  220.236 50.16 220.32 50.184 ;
    END
  END client_seq[8]
  PIN client_seq[9]
    DIRECTION OUTPUT ;
    USE SIGNAL ;
    PORT
      LAYER M4 ;
        RECT  220.236 50.256 220.32 50.28 ;
    END
  END client_seq[9]
  PIN clk
    DIRECTION INPUT ;
    USE SIGNAL ;
    PORT
      LAYER M4 ;
        RECT  0 43.632 0.084 43.656 ;
    END
  END clk
  PIN done
    DIRECTION OUTPUT ;
    USE SIGNAL ;
    PORT
      LAYER M5 ;
        RECT  108.672 0 108.696 0.084 ;
    END
  END done
  PIN fault
    DIRECTION OUTPUT ;
    USE SIGNAL ;
    PORT
      LAYER M5 ;
        RECT  108.768 0 108.792 0.084 ;
    END
  END fault
  PIN hub_ring_client[0]
    DIRECTION OUTPUT ;
    USE SIGNAL ;
    PORT
      LAYER M4 ;
        RECT  220.236 55.056 220.32 55.08 ;
    END
  END hub_ring_client[0]
  PIN hub_ring_client[1]
    DIRECTION OUTPUT ;
    USE SIGNAL ;
    PORT
      LAYER M4 ;
        RECT  220.236 55.152 220.32 55.176 ;
    END
  END hub_ring_client[1]
  PIN hub_ring_client[2]
    DIRECTION OUTPUT ;
    USE SIGNAL ;
    PORT
      LAYER M4 ;
        RECT  220.236 55.248 220.32 55.272 ;
    END
  END hub_ring_client[2]
  PIN hub_ring_client[3]
    DIRECTION OUTPUT ;
    USE SIGNAL ;
    PORT
      LAYER M4 ;
        RECT  220.236 55.344 220.32 55.368 ;
    END
  END hub_ring_client[3]
  PIN hub_ring_client[4]
    DIRECTION OUTPUT ;
    USE SIGNAL ;
    PORT
      LAYER M4 ;
        RECT  220.236 55.44 220.32 55.464 ;
    END
  END hub_ring_client[4]
  PIN hub_ring_client[5]
    DIRECTION OUTPUT ;
    USE SIGNAL ;
    PORT
      LAYER M4 ;
        RECT  220.236 55.536 220.32 55.56 ;
    END
  END hub_ring_client[5]
  PIN hub_ring_enable[0]
    DIRECTION OUTPUT ;
    USE SIGNAL ;
    PORT
      LAYER M4 ;
        RECT  220.236 54.864 220.32 54.888 ;
    END
  END hub_ring_enable[0]
  PIN hub_ring_enable[1]
    DIRECTION OUTPUT ;
    USE SIGNAL ;
    PORT
      LAYER M4 ;
        RECT  220.236 54.96 220.32 54.984 ;
    END
  END hub_ring_enable[1]
  PIN lg_local_read[0]
    DIRECTION OUTPUT ;
    USE SIGNAL ;
    PORT
      LAYER M4 ;
        RECT  220.236 62.736 220.32 62.76 ;
    END
  END lg_local_read[0]
  PIN lg_local_read[10]
    DIRECTION OUTPUT ;
    USE SIGNAL ;
    PORT
      LAYER M4 ;
        RECT  220.236 63.696 220.32 63.72 ;
    END
  END lg_local_read[10]
  PIN lg_local_read[11]
    DIRECTION OUTPUT ;
    USE SIGNAL ;
    PORT
      LAYER M4 ;
        RECT  220.236 63.792 220.32 63.816 ;
    END
  END lg_local_read[11]
  PIN lg_local_read[12]
    DIRECTION OUTPUT ;
    USE SIGNAL ;
    PORT
      LAYER M4 ;
        RECT  220.236 63.888 220.32 63.912 ;
    END
  END lg_local_read[12]
  PIN lg_local_read[13]
    DIRECTION OUTPUT ;
    USE SIGNAL ;
    PORT
      LAYER M4 ;
        RECT  220.236 63.984 220.32 64.008 ;
    END
  END lg_local_read[13]
  PIN lg_local_read[14]
    DIRECTION OUTPUT ;
    USE SIGNAL ;
    PORT
      LAYER M4 ;
        RECT  220.236 64.08 220.32 64.104 ;
    END
  END lg_local_read[14]
  PIN lg_local_read[15]
    DIRECTION OUTPUT ;
    USE SIGNAL ;
    PORT
      LAYER M4 ;
        RECT  220.236 64.176 220.32 64.2 ;
    END
  END lg_local_read[15]
  PIN lg_local_read[16]
    DIRECTION OUTPUT ;
    USE SIGNAL ;
    PORT
      LAYER M4 ;
        RECT  220.236 64.272 220.32 64.296 ;
    END
  END lg_local_read[16]
  PIN lg_local_read[17]
    DIRECTION OUTPUT ;
    USE SIGNAL ;
    PORT
      LAYER M4 ;
        RECT  220.236 64.368 220.32 64.392 ;
    END
  END lg_local_read[17]
  PIN lg_local_read[18]
    DIRECTION OUTPUT ;
    USE SIGNAL ;
    PORT
      LAYER M4 ;
        RECT  220.236 64.464 220.32 64.488 ;
    END
  END lg_local_read[18]
  PIN lg_local_read[19]
    DIRECTION OUTPUT ;
    USE SIGNAL ;
    PORT
      LAYER M4 ;
        RECT  220.236 64.56 220.32 64.584 ;
    END
  END lg_local_read[19]
  PIN lg_local_read[1]
    DIRECTION OUTPUT ;
    USE SIGNAL ;
    PORT
      LAYER M4 ;
        RECT  220.236 62.832 220.32 62.856 ;
    END
  END lg_local_read[1]
  PIN lg_local_read[20]
    DIRECTION OUTPUT ;
    USE SIGNAL ;
    PORT
      LAYER M4 ;
        RECT  220.236 64.656 220.32 64.68 ;
    END
  END lg_local_read[20]
  PIN lg_local_read[21]
    DIRECTION OUTPUT ;
    USE SIGNAL ;
    PORT
      LAYER M4 ;
        RECT  220.236 64.752 220.32 64.776 ;
    END
  END lg_local_read[21]
  PIN lg_local_read[22]
    DIRECTION OUTPUT ;
    USE SIGNAL ;
    PORT
      LAYER M4 ;
        RECT  220.236 64.848 220.32 64.872 ;
    END
  END lg_local_read[22]
  PIN lg_local_read[23]
    DIRECTION OUTPUT ;
    USE SIGNAL ;
    PORT
      LAYER M4 ;
        RECT  220.236 64.944 220.32 64.968 ;
    END
  END lg_local_read[23]
  PIN lg_local_read[2]
    DIRECTION OUTPUT ;
    USE SIGNAL ;
    PORT
      LAYER M4 ;
        RECT  220.236 62.928 220.32 62.952 ;
    END
  END lg_local_read[2]
  PIN lg_local_read[3]
    DIRECTION OUTPUT ;
    USE SIGNAL ;
    PORT
      LAYER M4 ;
        RECT  220.236 63.024 220.32 63.048 ;
    END
  END lg_local_read[3]
  PIN lg_local_read[4]
    DIRECTION OUTPUT ;
    USE SIGNAL ;
    PORT
      LAYER M4 ;
        RECT  220.236 63.12 220.32 63.144 ;
    END
  END lg_local_read[4]
  PIN lg_local_read[5]
    DIRECTION OUTPUT ;
    USE SIGNAL ;
    PORT
      LAYER M4 ;
        RECT  220.236 63.216 220.32 63.24 ;
    END
  END lg_local_read[5]
  PIN lg_local_read[6]
    DIRECTION OUTPUT ;
    USE SIGNAL ;
    PORT
      LAYER M4 ;
        RECT  220.236 63.312 220.32 63.336 ;
    END
  END lg_local_read[6]
  PIN lg_local_read[7]
    DIRECTION OUTPUT ;
    USE SIGNAL ;
    PORT
      LAYER M4 ;
        RECT  220.236 63.408 220.32 63.432 ;
    END
  END lg_local_read[7]
  PIN lg_local_read[8]
    DIRECTION OUTPUT ;
    USE SIGNAL ;
    PORT
      LAYER M4 ;
        RECT  220.236 63.504 220.32 63.528 ;
    END
  END lg_local_read[8]
  PIN lg_local_read[9]
    DIRECTION OUTPUT ;
    USE SIGNAL ;
    PORT
      LAYER M4 ;
        RECT  220.236 63.6 220.32 63.624 ;
    END
  END lg_local_read[9]
  PIN lg_local_write[0]
    DIRECTION OUTPUT ;
    USE SIGNAL ;
    PORT
      LAYER M4 ;
        RECT  220.236 65.04 220.32 65.064 ;
    END
  END lg_local_write[0]
  PIN lg_local_write[10]
    DIRECTION OUTPUT ;
    USE SIGNAL ;
    PORT
      LAYER M4 ;
        RECT  220.236 66 220.32 66.024 ;
    END
  END lg_local_write[10]
  PIN lg_local_write[11]
    DIRECTION OUTPUT ;
    USE SIGNAL ;
    PORT
      LAYER M4 ;
        RECT  220.236 66.096 220.32 66.12 ;
    END
  END lg_local_write[11]
  PIN lg_local_write[12]
    DIRECTION OUTPUT ;
    USE SIGNAL ;
    PORT
      LAYER M4 ;
        RECT  220.236 66.192 220.32 66.216 ;
    END
  END lg_local_write[12]
  PIN lg_local_write[13]
    DIRECTION OUTPUT ;
    USE SIGNAL ;
    PORT
      LAYER M4 ;
        RECT  220.236 66.288 220.32 66.312 ;
    END
  END lg_local_write[13]
  PIN lg_local_write[14]
    DIRECTION OUTPUT ;
    USE SIGNAL ;
    PORT
      LAYER M4 ;
        RECT  220.236 66.384 220.32 66.408 ;
    END
  END lg_local_write[14]
  PIN lg_local_write[15]
    DIRECTION OUTPUT ;
    USE SIGNAL ;
    PORT
      LAYER M4 ;
        RECT  220.236 66.48 220.32 66.504 ;
    END
  END lg_local_write[15]
  PIN lg_local_write[16]
    DIRECTION OUTPUT ;
    USE SIGNAL ;
    PORT
      LAYER M4 ;
        RECT  220.236 66.576 220.32 66.6 ;
    END
  END lg_local_write[16]
  PIN lg_local_write[17]
    DIRECTION OUTPUT ;
    USE SIGNAL ;
    PORT
      LAYER M4 ;
        RECT  220.236 66.672 220.32 66.696 ;
    END
  END lg_local_write[17]
  PIN lg_local_write[18]
    DIRECTION OUTPUT ;
    USE SIGNAL ;
    PORT
      LAYER M4 ;
        RECT  220.236 66.768 220.32 66.792 ;
    END
  END lg_local_write[18]
  PIN lg_local_write[19]
    DIRECTION OUTPUT ;
    USE SIGNAL ;
    PORT
      LAYER M4 ;
        RECT  220.236 66.864 220.32 66.888 ;
    END
  END lg_local_write[19]
  PIN lg_local_write[1]
    DIRECTION OUTPUT ;
    USE SIGNAL ;
    PORT
      LAYER M4 ;
        RECT  220.236 65.136 220.32 65.16 ;
    END
  END lg_local_write[1]
  PIN lg_local_write[20]
    DIRECTION OUTPUT ;
    USE SIGNAL ;
    PORT
      LAYER M4 ;
        RECT  220.236 66.96 220.32 66.984 ;
    END
  END lg_local_write[20]
  PIN lg_local_write[21]
    DIRECTION OUTPUT ;
    USE SIGNAL ;
    PORT
      LAYER M4 ;
        RECT  220.236 67.056 220.32 67.08 ;
    END
  END lg_local_write[21]
  PIN lg_local_write[22]
    DIRECTION OUTPUT ;
    USE SIGNAL ;
    PORT
      LAYER M4 ;
        RECT  220.236 67.152 220.32 67.176 ;
    END
  END lg_local_write[22]
  PIN lg_local_write[23]
    DIRECTION OUTPUT ;
    USE SIGNAL ;
    PORT
      LAYER M4 ;
        RECT  220.236 67.248 220.32 67.272 ;
    END
  END lg_local_write[23]
  PIN lg_local_write[2]
    DIRECTION OUTPUT ;
    USE SIGNAL ;
    PORT
      LAYER M4 ;
        RECT  220.236 65.232 220.32 65.256 ;
    END
  END lg_local_write[2]
  PIN lg_local_write[3]
    DIRECTION OUTPUT ;
    USE SIGNAL ;
    PORT
      LAYER M4 ;
        RECT  220.236 65.328 220.32 65.352 ;
    END
  END lg_local_write[3]
  PIN lg_local_write[4]
    DIRECTION OUTPUT ;
    USE SIGNAL ;
    PORT
      LAYER M4 ;
        RECT  220.236 65.424 220.32 65.448 ;
    END
  END lg_local_write[4]
  PIN lg_local_write[5]
    DIRECTION OUTPUT ;
    USE SIGNAL ;
    PORT
      LAYER M4 ;
        RECT  220.236 65.52 220.32 65.544 ;
    END
  END lg_local_write[5]
  PIN lg_local_write[6]
    DIRECTION OUTPUT ;
    USE SIGNAL ;
    PORT
      LAYER M4 ;
        RECT  220.236 65.616 220.32 65.64 ;
    END
  END lg_local_write[6]
  PIN lg_local_write[7]
    DIRECTION OUTPUT ;
    USE SIGNAL ;
    PORT
      LAYER M4 ;
        RECT  220.236 65.712 220.32 65.736 ;
    END
  END lg_local_write[7]
  PIN lg_local_write[8]
    DIRECTION OUTPUT ;
    USE SIGNAL ;
    PORT
      LAYER M4 ;
        RECT  220.236 65.808 220.32 65.832 ;
    END
  END lg_local_write[8]
  PIN lg_local_write[9]
    DIRECTION OUTPUT ;
    USE SIGNAL ;
    PORT
      LAYER M4 ;
        RECT  220.236 65.904 220.32 65.928 ;
    END
  END lg_local_write[9]
  PIN ordinal[0]
    DIRECTION OUTPUT ;
    USE SIGNAL ;
    PORT
      LAYER M5 ;
        RECT  108.864 0 108.888 0.084 ;
    END
  END ordinal[0]
  PIN ordinal[10]
    DIRECTION OUTPUT ;
    USE SIGNAL ;
    PORT
      LAYER M5 ;
        RECT  109.824 0 109.848 0.084 ;
    END
  END ordinal[10]
  PIN ordinal[11]
    DIRECTION OUTPUT ;
    USE SIGNAL ;
    PORT
      LAYER M5 ;
        RECT  109.92 0 109.944 0.084 ;
    END
  END ordinal[11]
  PIN ordinal[12]
    DIRECTION OUTPUT ;
    USE SIGNAL ;
    PORT
      LAYER M5 ;
        RECT  110.016 0 110.04 0.084 ;
    END
  END ordinal[12]
  PIN ordinal[13]
    DIRECTION OUTPUT ;
    USE SIGNAL ;
    PORT
      LAYER M5 ;
        RECT  110.112 0 110.136 0.084 ;
    END
  END ordinal[13]
  PIN ordinal[14]
    DIRECTION OUTPUT ;
    USE SIGNAL ;
    PORT
      LAYER M5 ;
        RECT  110.208 0 110.232 0.084 ;
    END
  END ordinal[14]
  PIN ordinal[15]
    DIRECTION OUTPUT ;
    USE SIGNAL ;
    PORT
      LAYER M5 ;
        RECT  110.304 0 110.328 0.084 ;
    END
  END ordinal[15]
  PIN ordinal[16]
    DIRECTION OUTPUT ;
    USE SIGNAL ;
    PORT
      LAYER M5 ;
        RECT  110.4 0 110.424 0.084 ;
    END
  END ordinal[16]
  PIN ordinal[17]
    DIRECTION OUTPUT ;
    USE SIGNAL ;
    PORT
      LAYER M5 ;
        RECT  110.496 0 110.52 0.084 ;
    END
  END ordinal[17]
  PIN ordinal[18]
    DIRECTION OUTPUT ;
    USE SIGNAL ;
    PORT
      LAYER M5 ;
        RECT  110.592 0 110.616 0.084 ;
    END
  END ordinal[18]
  PIN ordinal[19]
    DIRECTION OUTPUT ;
    USE SIGNAL ;
    PORT
      LAYER M5 ;
        RECT  110.688 0 110.712 0.084 ;
    END
  END ordinal[19]
  PIN ordinal[1]
    DIRECTION OUTPUT ;
    USE SIGNAL ;
    PORT
      LAYER M5 ;
        RECT  108.96 0 108.984 0.084 ;
    END
  END ordinal[1]
  PIN ordinal[20]
    DIRECTION OUTPUT ;
    USE SIGNAL ;
    PORT
      LAYER M5 ;
        RECT  110.784 0 110.808 0.084 ;
    END
  END ordinal[20]
  PIN ordinal[21]
    DIRECTION OUTPUT ;
    USE SIGNAL ;
    PORT
      LAYER M5 ;
        RECT  110.88 0 110.904 0.084 ;
    END
  END ordinal[21]
  PIN ordinal[22]
    DIRECTION OUTPUT ;
    USE SIGNAL ;
    PORT
      LAYER M5 ;
        RECT  110.976 0 111 0.084 ;
    END
  END ordinal[22]
  PIN ordinal[23]
    DIRECTION OUTPUT ;
    USE SIGNAL ;
    PORT
      LAYER M5 ;
        RECT  111.072 0 111.096 0.084 ;
    END
  END ordinal[23]
  PIN ordinal[24]
    DIRECTION OUTPUT ;
    USE SIGNAL ;
    PORT
      LAYER M5 ;
        RECT  111.168 0 111.192 0.084 ;
    END
  END ordinal[24]
  PIN ordinal[25]
    DIRECTION OUTPUT ;
    USE SIGNAL ;
    PORT
      LAYER M5 ;
        RECT  111.264 0 111.288 0.084 ;
    END
  END ordinal[25]
  PIN ordinal[26]
    DIRECTION OUTPUT ;
    USE SIGNAL ;
    PORT
      LAYER M5 ;
        RECT  111.36 0 111.384 0.084 ;
    END
  END ordinal[26]
  PIN ordinal[27]
    DIRECTION OUTPUT ;
    USE SIGNAL ;
    PORT
      LAYER M5 ;
        RECT  111.456 0 111.48 0.084 ;
    END
  END ordinal[27]
  PIN ordinal[28]
    DIRECTION OUTPUT ;
    USE SIGNAL ;
    PORT
      LAYER M5 ;
        RECT  111.552 0 111.576 0.084 ;
    END
  END ordinal[28]
  PIN ordinal[29]
    DIRECTION OUTPUT ;
    USE SIGNAL ;
    PORT
      LAYER M5 ;
        RECT  111.648 0 111.672 0.084 ;
    END
  END ordinal[29]
  PIN ordinal[2]
    DIRECTION OUTPUT ;
    USE SIGNAL ;
    PORT
      LAYER M5 ;
        RECT  109.056 0 109.08 0.084 ;
    END
  END ordinal[2]
  PIN ordinal[30]
    DIRECTION OUTPUT ;
    USE SIGNAL ;
    PORT
      LAYER M5 ;
        RECT  111.744 0 111.768 0.084 ;
    END
  END ordinal[30]
  PIN ordinal[31]
    DIRECTION OUTPUT ;
    USE SIGNAL ;
    PORT
      LAYER M5 ;
        RECT  111.84 0 111.864 0.084 ;
    END
  END ordinal[31]
  PIN ordinal[3]
    DIRECTION OUTPUT ;
    USE SIGNAL ;
    PORT
      LAYER M5 ;
        RECT  109.152 0 109.176 0.084 ;
    END
  END ordinal[3]
  PIN ordinal[4]
    DIRECTION OUTPUT ;
    USE SIGNAL ;
    PORT
      LAYER M5 ;
        RECT  109.248 0 109.272 0.084 ;
    END
  END ordinal[4]
  PIN ordinal[5]
    DIRECTION OUTPUT ;
    USE SIGNAL ;
    PORT
      LAYER M5 ;
        RECT  109.344 0 109.368 0.084 ;
    END
  END ordinal[5]
  PIN ordinal[6]
    DIRECTION OUTPUT ;
    USE SIGNAL ;
    PORT
      LAYER M5 ;
        RECT  109.44 0 109.464 0.084 ;
    END
  END ordinal[6]
  PIN ordinal[7]
    DIRECTION OUTPUT ;
    USE SIGNAL ;
    PORT
      LAYER M5 ;
        RECT  109.536 0 109.56 0.084 ;
    END
  END ordinal[7]
  PIN ordinal[8]
    DIRECTION OUTPUT ;
    USE SIGNAL ;
    PORT
      LAYER M5 ;
        RECT  109.632 0 109.656 0.084 ;
    END
  END ordinal[8]
  PIN ordinal[9]
    DIRECTION OUTPUT ;
    USE SIGNAL ;
    PORT
      LAYER M5 ;
        RECT  109.728 0 109.752 0.084 ;
    END
  END ordinal[9]
  PIN replay_enable
    DIRECTION OUTPUT ;
    USE SIGNAL ;
    PORT
      LAYER M4 ;
        RECT  220.236 62.544 220.32 62.568 ;
    END
  END replay_enable
  PIN replay_source
    DIRECTION OUTPUT ;
    USE SIGNAL ;
    PORT
      LAYER M4 ;
        RECT  220.236 62.64 220.32 62.664 ;
    END
  END replay_source
  PIN response_enable[0]
    DIRECTION OUTPUT ;
    USE SIGNAL ;
    PORT
      LAYER M4 ;
        RECT  220.236 50.352 220.32 50.376 ;
    END
  END response_enable[0]
  PIN response_enable[1]
    DIRECTION OUTPUT ;
    USE SIGNAL ;
    PORT
      LAYER M4 ;
        RECT  220.236 50.448 220.32 50.472 ;
    END
  END response_enable[1]
  PIN response_enable[2]
    DIRECTION OUTPUT ;
    USE SIGNAL ;
    PORT
      LAYER M4 ;
        RECT  220.236 50.544 220.32 50.568 ;
    END
  END response_enable[2]
  PIN response_enable[3]
    DIRECTION OUTPUT ;
    USE SIGNAL ;
    PORT
      LAYER M4 ;
        RECT  220.236 50.64 220.32 50.664 ;
    END
  END response_enable[3]
  PIN response_enable[4]
    DIRECTION OUTPUT ;
    USE SIGNAL ;
    PORT
      LAYER M4 ;
        RECT  220.236 50.736 220.32 50.76 ;
    END
  END response_enable[4]
  PIN response_seq[0]
    DIRECTION OUTPUT ;
    USE SIGNAL ;
    PORT
      LAYER M4 ;
        RECT  220.236 50.832 220.32 50.856 ;
    END
  END response_seq[0]
  PIN response_seq[1]
    DIRECTION OUTPUT ;
    USE SIGNAL ;
    PORT
      LAYER M4 ;
        RECT  220.236 50.928 220.32 50.952 ;
    END
  END response_seq[1]
  PIN response_seq[2]
    DIRECTION OUTPUT ;
    USE SIGNAL ;
    PORT
      LAYER M4 ;
        RECT  220.236 51.024 220.32 51.048 ;
    END
  END response_seq[2]
  PIN response_seq[3]
    DIRECTION OUTPUT ;
    USE SIGNAL ;
    PORT
      LAYER M4 ;
        RECT  220.236 51.12 220.32 51.144 ;
    END
  END response_seq[3]
  PIN response_seq[4]
    DIRECTION OUTPUT ;
    USE SIGNAL ;
    PORT
      LAYER M4 ;
        RECT  220.236 51.216 220.32 51.24 ;
    END
  END response_seq[4]
  PIN response_seq[5]
    DIRECTION OUTPUT ;
    USE SIGNAL ;
    PORT
      LAYER M4 ;
        RECT  220.236 51.312 220.32 51.336 ;
    END
  END response_seq[5]
  PIN response_seq[6]
    DIRECTION OUTPUT ;
    USE SIGNAL ;
    PORT
      LAYER M4 ;
        RECT  220.236 51.408 220.32 51.432 ;
    END
  END response_seq[6]
  PIN response_seq[7]
    DIRECTION OUTPUT ;
    USE SIGNAL ;
    PORT
      LAYER M4 ;
        RECT  220.236 51.504 220.32 51.528 ;
    END
  END response_seq[7]
  PIN response_seq[8]
    DIRECTION OUTPUT ;
    USE SIGNAL ;
    PORT
      LAYER M4 ;
        RECT  220.236 51.6 220.32 51.624 ;
    END
  END response_seq[8]
  PIN response_seq[9]
    DIRECTION OUTPUT ;
    USE SIGNAL ;
    PORT
      LAYER M4 ;
        RECT  220.236 51.696 220.32 51.72 ;
    END
  END response_seq[9]
  PIN ring_tx_enable[0]
    DIRECTION OUTPUT ;
    USE SIGNAL ;
    PORT
      LAYER M4 ;
        RECT  220.236 61.776 220.32 61.8 ;
    END
  END ring_tx_enable[0]
  PIN ring_tx_enable[1]
    DIRECTION OUTPUT ;
    USE SIGNAL ;
    PORT
      LAYER M4 ;
        RECT  220.236 61.872 220.32 61.896 ;
    END
  END ring_tx_enable[1]
  PIN ring_tx_source[0]
    DIRECTION OUTPUT ;
    USE SIGNAL ;
    PORT
      LAYER M4 ;
        RECT  220.236 61.968 220.32 61.992 ;
    END
  END ring_tx_source[0]
  PIN ring_tx_source[1]
    DIRECTION OUTPUT ;
    USE SIGNAL ;
    PORT
      LAYER M4 ;
        RECT  220.236 62.064 220.32 62.088 ;
    END
  END ring_tx_source[1]
  PIN ring_tx_source[2]
    DIRECTION OUTPUT ;
    USE SIGNAL ;
    PORT
      LAYER M4 ;
        RECT  220.236 62.16 220.32 62.184 ;
    END
  END ring_tx_source[2]
  PIN ring_tx_source[3]
    DIRECTION OUTPUT ;
    USE SIGNAL ;
    PORT
      LAYER M4 ;
        RECT  220.236 62.256 220.32 62.28 ;
    END
  END ring_tx_source[3]
  PIN ring_tx_source[4]
    DIRECTION OUTPUT ;
    USE SIGNAL ;
    PORT
      LAYER M4 ;
        RECT  220.236 62.352 220.32 62.376 ;
    END
  END ring_tx_source[4]
  PIN ring_tx_source[5]
    DIRECTION OUTPUT ;
    USE SIGNAL ;
    PORT
      LAYER M4 ;
        RECT  220.236 62.448 220.32 62.472 ;
    END
  END ring_tx_source[5]
  PIN rslot[0]
    DIRECTION OUTPUT ;
    USE SIGNAL ;
    PORT
      LAYER M4 ;
        RECT  220.236 57.168 220.32 57.192 ;
    END
  END rslot[0]
  PIN rslot[10]
    DIRECTION OUTPUT ;
    USE SIGNAL ;
    PORT
      LAYER M4 ;
        RECT  220.236 58.128 220.32 58.152 ;
    END
  END rslot[10]
  PIN rslot[11]
    DIRECTION OUTPUT ;
    USE SIGNAL ;
    PORT
      LAYER M4 ;
        RECT  220.236 58.224 220.32 58.248 ;
    END
  END rslot[11]
  PIN rslot[12]
    DIRECTION OUTPUT ;
    USE SIGNAL ;
    PORT
      LAYER M4 ;
        RECT  220.236 58.32 220.32 58.344 ;
    END
  END rslot[12]
  PIN rslot[13]
    DIRECTION OUTPUT ;
    USE SIGNAL ;
    PORT
      LAYER M4 ;
        RECT  220.236 58.416 220.32 58.44 ;
    END
  END rslot[13]
  PIN rslot[14]
    DIRECTION OUTPUT ;
    USE SIGNAL ;
    PORT
      LAYER M4 ;
        RECT  220.236 58.512 220.32 58.536 ;
    END
  END rslot[14]
  PIN rslot[15]
    DIRECTION OUTPUT ;
    USE SIGNAL ;
    PORT
      LAYER M4 ;
        RECT  220.236 58.608 220.32 58.632 ;
    END
  END rslot[15]
  PIN rslot[16]
    DIRECTION OUTPUT ;
    USE SIGNAL ;
    PORT
      LAYER M4 ;
        RECT  220.236 58.704 220.32 58.728 ;
    END
  END rslot[16]
  PIN rslot[17]
    DIRECTION OUTPUT ;
    USE SIGNAL ;
    PORT
      LAYER M4 ;
        RECT  220.236 58.8 220.32 58.824 ;
    END
  END rslot[17]
  PIN rslot[18]
    DIRECTION OUTPUT ;
    USE SIGNAL ;
    PORT
      LAYER M4 ;
        RECT  220.236 58.896 220.32 58.92 ;
    END
  END rslot[18]
  PIN rslot[19]
    DIRECTION OUTPUT ;
    USE SIGNAL ;
    PORT
      LAYER M4 ;
        RECT  220.236 58.992 220.32 59.016 ;
    END
  END rslot[19]
  PIN rslot[1]
    DIRECTION OUTPUT ;
    USE SIGNAL ;
    PORT
      LAYER M4 ;
        RECT  220.236 57.264 220.32 57.288 ;
    END
  END rslot[1]
  PIN rslot[20]
    DIRECTION OUTPUT ;
    USE SIGNAL ;
    PORT
      LAYER M4 ;
        RECT  220.236 59.088 220.32 59.112 ;
    END
  END rslot[20]
  PIN rslot[21]
    DIRECTION OUTPUT ;
    USE SIGNAL ;
    PORT
      LAYER M4 ;
        RECT  220.236 59.184 220.32 59.208 ;
    END
  END rslot[21]
  PIN rslot[22]
    DIRECTION OUTPUT ;
    USE SIGNAL ;
    PORT
      LAYER M4 ;
        RECT  220.236 59.28 220.32 59.304 ;
    END
  END rslot[22]
  PIN rslot[23]
    DIRECTION OUTPUT ;
    USE SIGNAL ;
    PORT
      LAYER M4 ;
        RECT  220.236 59.376 220.32 59.4 ;
    END
  END rslot[23]
  PIN rslot[2]
    DIRECTION OUTPUT ;
    USE SIGNAL ;
    PORT
      LAYER M4 ;
        RECT  220.236 57.36 220.32 57.384 ;
    END
  END rslot[2]
  PIN rslot[3]
    DIRECTION OUTPUT ;
    USE SIGNAL ;
    PORT
      LAYER M4 ;
        RECT  220.236 57.456 220.32 57.48 ;
    END
  END rslot[3]
  PIN rslot[4]
    DIRECTION OUTPUT ;
    USE SIGNAL ;
    PORT
      LAYER M4 ;
        RECT  220.236 57.552 220.32 57.576 ;
    END
  END rslot[4]
  PIN rslot[5]
    DIRECTION OUTPUT ;
    USE SIGNAL ;
    PORT
      LAYER M4 ;
        RECT  220.236 57.648 220.32 57.672 ;
    END
  END rslot[5]
  PIN rslot[6]
    DIRECTION OUTPUT ;
    USE SIGNAL ;
    PORT
      LAYER M4 ;
        RECT  220.236 57.744 220.32 57.768 ;
    END
  END rslot[6]
  PIN rslot[7]
    DIRECTION OUTPUT ;
    USE SIGNAL ;
    PORT
      LAYER M4 ;
        RECT  220.236 57.84 220.32 57.864 ;
    END
  END rslot[7]
  PIN rslot[8]
    DIRECTION OUTPUT ;
    USE SIGNAL ;
    PORT
      LAYER M4 ;
        RECT  220.236 57.936 220.32 57.96 ;
    END
  END rslot[8]
  PIN rslot[9]
    DIRECTION OUTPUT ;
    USE SIGNAL ;
    PORT
      LAYER M4 ;
        RECT  220.236 58.032 220.32 58.056 ;
    END
  END rslot[9]
  PIN rslot_v[0]
    DIRECTION OUTPUT ;
    USE SIGNAL ;
    PORT
      LAYER M4 ;
        RECT  220.236 55.632 220.32 55.656 ;
    END
  END rslot_v[0]
  PIN rslot_v[1]
    DIRECTION OUTPUT ;
    USE SIGNAL ;
    PORT
      LAYER M4 ;
        RECT  220.236 55.728 220.32 55.752 ;
    END
  END rslot_v[1]
  PIN rslot_v[2]
    DIRECTION OUTPUT ;
    USE SIGNAL ;
    PORT
      LAYER M4 ;
        RECT  220.236 55.824 220.32 55.848 ;
    END
  END rslot_v[2]
  PIN rslot_v[3]
    DIRECTION OUTPUT ;
    USE SIGNAL ;
    PORT
      LAYER M4 ;
        RECT  220.236 55.92 220.32 55.944 ;
    END
  END rslot_v[3]
  PIN rslot_v[4]
    DIRECTION OUTPUT ;
    USE SIGNAL ;
    PORT
      LAYER M4 ;
        RECT  220.236 56.016 220.32 56.04 ;
    END
  END rslot_v[4]
  PIN rslot_v[5]
    DIRECTION OUTPUT ;
    USE SIGNAL ;
    PORT
      LAYER M4 ;
        RECT  220.236 56.112 220.32 56.136 ;
    END
  END rslot_v[5]
  PIN rslot_v[6]
    DIRECTION OUTPUT ;
    USE SIGNAL ;
    PORT
      LAYER M4 ;
        RECT  220.236 56.208 220.32 56.232 ;
    END
  END rslot_v[6]
  PIN rslot_v[7]
    DIRECTION OUTPUT ;
    USE SIGNAL ;
    PORT
      LAYER M4 ;
        RECT  220.236 56.304 220.32 56.328 ;
    END
  END rslot_v[7]
  PIN rst_n
    DIRECTION INPUT ;
    USE SIGNAL ;
    PORT
      LAYER M4 ;
        RECT  0 43.728 0.084 43.752 ;
    END
  END rst_n
  PIN start_base[0]
    DIRECTION INPUT ;
    USE SIGNAL ;
    PORT
      LAYER M4 ;
        RECT  0 69.552 0.084 69.576 ;
    END
  END start_base[0]
  PIN start_base[1]
    DIRECTION INPUT ;
    USE SIGNAL ;
    PORT
      LAYER M4 ;
        RECT  0 69.648 0.084 69.672 ;
    END
  END start_base[1]
  PIN start_base[2]
    DIRECTION INPUT ;
    USE SIGNAL ;
    PORT
      LAYER M4 ;
        RECT  0 69.744 0.084 69.768 ;
    END
  END start_base[2]
  PIN start_base[3]
    DIRECTION INPUT ;
    USE SIGNAL ;
    PORT
      LAYER M4 ;
        RECT  0 69.84 0.084 69.864 ;
    END
  END start_base[3]
  PIN start_base[4]
    DIRECTION INPUT ;
    USE SIGNAL ;
    PORT
      LAYER M4 ;
        RECT  0 69.936 0.084 69.96 ;
    END
  END start_base[4]
  PIN start_base[5]
    DIRECTION INPUT ;
    USE SIGNAL ;
    PORT
      LAYER M4 ;
        RECT  0 70.032 0.084 70.056 ;
    END
  END start_base[5]
  PIN start_base[6]
    DIRECTION INPUT ;
    USE SIGNAL ;
    PORT
      LAYER M4 ;
        RECT  0 70.128 0.084 70.152 ;
    END
  END start_base[6]
  PIN start_base[7]
    DIRECTION INPUT ;
    USE SIGNAL ;
    PORT
      LAYER M4 ;
        RECT  0 70.224 0.084 70.248 ;
    END
  END start_base[7]
  PIN start_base[8]
    DIRECTION INPUT ;
    USE SIGNAL ;
    PORT
      LAYER M4 ;
        RECT  0 70.32 0.084 70.344 ;
    END
  END start_base[8]
  PIN start_base[9]
    DIRECTION INPUT ;
    USE SIGNAL ;
    PORT
      LAYER M4 ;
        RECT  0 70.416 0.084 70.44 ;
    END
  END start_base[9]
  PIN start_limit[0]
    DIRECTION INPUT ;
    USE SIGNAL ;
    PORT
      LAYER M4 ;
        RECT  0 70.512 0.084 70.536 ;
    END
  END start_limit[0]
  PIN start_limit[10]
    DIRECTION INPUT ;
    USE SIGNAL ;
    PORT
      LAYER M4 ;
        RECT  0 71.472 0.084 71.496 ;
    END
  END start_limit[10]
  PIN start_limit[1]
    DIRECTION INPUT ;
    USE SIGNAL ;
    PORT
      LAYER M4 ;
        RECT  0 70.608 0.084 70.632 ;
    END
  END start_limit[1]
  PIN start_limit[2]
    DIRECTION INPUT ;
    USE SIGNAL ;
    PORT
      LAYER M4 ;
        RECT  0 70.704 0.084 70.728 ;
    END
  END start_limit[2]
  PIN start_limit[3]
    DIRECTION INPUT ;
    USE SIGNAL ;
    PORT
      LAYER M4 ;
        RECT  0 70.8 0.084 70.824 ;
    END
  END start_limit[3]
  PIN start_limit[4]
    DIRECTION INPUT ;
    USE SIGNAL ;
    PORT
      LAYER M4 ;
        RECT  0 70.896 0.084 70.92 ;
    END
  END start_limit[4]
  PIN start_limit[5]
    DIRECTION INPUT ;
    USE SIGNAL ;
    PORT
      LAYER M4 ;
        RECT  0 70.992 0.084 71.016 ;
    END
  END start_limit[5]
  PIN start_limit[6]
    DIRECTION INPUT ;
    USE SIGNAL ;
    PORT
      LAYER M4 ;
        RECT  0 71.088 0.084 71.112 ;
    END
  END start_limit[6]
  PIN start_limit[7]
    DIRECTION INPUT ;
    USE SIGNAL ;
    PORT
      LAYER M4 ;
        RECT  0 71.184 0.084 71.208 ;
    END
  END start_limit[7]
  PIN start_limit[8]
    DIRECTION INPUT ;
    USE SIGNAL ;
    PORT
      LAYER M4 ;
        RECT  0 71.28 0.084 71.304 ;
    END
  END start_limit[8]
  PIN start_limit[9]
    DIRECTION INPUT ;
    USE SIGNAL ;
    PORT
      LAYER M4 ;
        RECT  0 71.376 0.084 71.4 ;
    END
  END start_limit[9]
  PIN start_loops[0]
    DIRECTION INPUT ;
    USE SIGNAL ;
    PORT
      LAYER M4 ;
        RECT  0 71.568 0.084 71.592 ;
    END
  END start_loops[0]
  PIN start_loops[10]
    DIRECTION INPUT ;
    USE SIGNAL ;
    PORT
      LAYER M4 ;
        RECT  0 72.528 0.084 72.552 ;
    END
  END start_loops[10]
  PIN start_loops[11]
    DIRECTION INPUT ;
    USE SIGNAL ;
    PORT
      LAYER M4 ;
        RECT  0 72.624 0.084 72.648 ;
    END
  END start_loops[11]
  PIN start_loops[12]
    DIRECTION INPUT ;
    USE SIGNAL ;
    PORT
      LAYER M4 ;
        RECT  0 72.72 0.084 72.744 ;
    END
  END start_loops[12]
  PIN start_loops[13]
    DIRECTION INPUT ;
    USE SIGNAL ;
    PORT
      LAYER M4 ;
        RECT  0 72.816 0.084 72.84 ;
    END
  END start_loops[13]
  PIN start_loops[14]
    DIRECTION INPUT ;
    USE SIGNAL ;
    PORT
      LAYER M4 ;
        RECT  0 72.912 0.084 72.936 ;
    END
  END start_loops[14]
  PIN start_loops[15]
    DIRECTION INPUT ;
    USE SIGNAL ;
    PORT
      LAYER M4 ;
        RECT  0 73.008 0.084 73.032 ;
    END
  END start_loops[15]
  PIN start_loops[1]
    DIRECTION INPUT ;
    USE SIGNAL ;
    PORT
      LAYER M4 ;
        RECT  0 71.664 0.084 71.688 ;
    END
  END start_loops[1]
  PIN start_loops[2]
    DIRECTION INPUT ;
    USE SIGNAL ;
    PORT
      LAYER M4 ;
        RECT  0 71.76 0.084 71.784 ;
    END
  END start_loops[2]
  PIN start_loops[3]
    DIRECTION INPUT ;
    USE SIGNAL ;
    PORT
      LAYER M4 ;
        RECT  0 71.856 0.084 71.88 ;
    END
  END start_loops[3]
  PIN start_loops[4]
    DIRECTION INPUT ;
    USE SIGNAL ;
    PORT
      LAYER M4 ;
        RECT  0 71.952 0.084 71.976 ;
    END
  END start_loops[4]
  PIN start_loops[5]
    DIRECTION INPUT ;
    USE SIGNAL ;
    PORT
      LAYER M4 ;
        RECT  0 72.048 0.084 72.072 ;
    END
  END start_loops[5]
  PIN start_loops[6]
    DIRECTION INPUT ;
    USE SIGNAL ;
    PORT
      LAYER M4 ;
        RECT  0 72.144 0.084 72.168 ;
    END
  END start_loops[6]
  PIN start_loops[7]
    DIRECTION INPUT ;
    USE SIGNAL ;
    PORT
      LAYER M4 ;
        RECT  0 72.24 0.084 72.264 ;
    END
  END start_loops[7]
  PIN start_loops[8]
    DIRECTION INPUT ;
    USE SIGNAL ;
    PORT
      LAYER M4 ;
        RECT  0 72.336 0.084 72.36 ;
    END
  END start_loops[8]
  PIN start_loops[9]
    DIRECTION INPUT ;
    USE SIGNAL ;
    PORT
      LAYER M4 ;
        RECT  0 72.432 0.084 72.456 ;
    END
  END start_loops[9]
  PIN start_v
    DIRECTION INPUT ;
    USE SIGNAL ;
    PORT
      LAYER M4 ;
        RECT  0 69.456 0.084 69.48 ;
    END
  END start_v
  PIN wslot[0]
    DIRECTION OUTPUT ;
    USE SIGNAL ;
    PORT
      LAYER M4 ;
        RECT  220.236 59.472 220.32 59.496 ;
    END
  END wslot[0]
  PIN wslot[10]
    DIRECTION OUTPUT ;
    USE SIGNAL ;
    PORT
      LAYER M4 ;
        RECT  220.236 60.432 220.32 60.456 ;
    END
  END wslot[10]
  PIN wslot[11]
    DIRECTION OUTPUT ;
    USE SIGNAL ;
    PORT
      LAYER M4 ;
        RECT  220.236 60.528 220.32 60.552 ;
    END
  END wslot[11]
  PIN wslot[12]
    DIRECTION OUTPUT ;
    USE SIGNAL ;
    PORT
      LAYER M4 ;
        RECT  220.236 60.624 220.32 60.648 ;
    END
  END wslot[12]
  PIN wslot[13]
    DIRECTION OUTPUT ;
    USE SIGNAL ;
    PORT
      LAYER M4 ;
        RECT  220.236 60.72 220.32 60.744 ;
    END
  END wslot[13]
  PIN wslot[14]
    DIRECTION OUTPUT ;
    USE SIGNAL ;
    PORT
      LAYER M4 ;
        RECT  220.236 60.816 220.32 60.84 ;
    END
  END wslot[14]
  PIN wslot[15]
    DIRECTION OUTPUT ;
    USE SIGNAL ;
    PORT
      LAYER M4 ;
        RECT  220.236 60.912 220.32 60.936 ;
    END
  END wslot[15]
  PIN wslot[16]
    DIRECTION OUTPUT ;
    USE SIGNAL ;
    PORT
      LAYER M4 ;
        RECT  220.236 61.008 220.32 61.032 ;
    END
  END wslot[16]
  PIN wslot[17]
    DIRECTION OUTPUT ;
    USE SIGNAL ;
    PORT
      LAYER M4 ;
        RECT  220.236 61.104 220.32 61.128 ;
    END
  END wslot[17]
  PIN wslot[18]
    DIRECTION OUTPUT ;
    USE SIGNAL ;
    PORT
      LAYER M4 ;
        RECT  220.236 61.2 220.32 61.224 ;
    END
  END wslot[18]
  PIN wslot[19]
    DIRECTION OUTPUT ;
    USE SIGNAL ;
    PORT
      LAYER M4 ;
        RECT  220.236 61.296 220.32 61.32 ;
    END
  END wslot[19]
  PIN wslot[1]
    DIRECTION OUTPUT ;
    USE SIGNAL ;
    PORT
      LAYER M4 ;
        RECT  220.236 59.568 220.32 59.592 ;
    END
  END wslot[1]
  PIN wslot[20]
    DIRECTION OUTPUT ;
    USE SIGNAL ;
    PORT
      LAYER M4 ;
        RECT  220.236 61.392 220.32 61.416 ;
    END
  END wslot[20]
  PIN wslot[21]
    DIRECTION OUTPUT ;
    USE SIGNAL ;
    PORT
      LAYER M4 ;
        RECT  220.236 61.488 220.32 61.512 ;
    END
  END wslot[21]
  PIN wslot[22]
    DIRECTION OUTPUT ;
    USE SIGNAL ;
    PORT
      LAYER M4 ;
        RECT  220.236 61.584 220.32 61.608 ;
    END
  END wslot[22]
  PIN wslot[23]
    DIRECTION OUTPUT ;
    USE SIGNAL ;
    PORT
      LAYER M4 ;
        RECT  220.236 61.68 220.32 61.704 ;
    END
  END wslot[23]
  PIN wslot[2]
    DIRECTION OUTPUT ;
    USE SIGNAL ;
    PORT
      LAYER M4 ;
        RECT  220.236 59.664 220.32 59.688 ;
    END
  END wslot[2]
  PIN wslot[3]
    DIRECTION OUTPUT ;
    USE SIGNAL ;
    PORT
      LAYER M4 ;
        RECT  220.236 59.76 220.32 59.784 ;
    END
  END wslot[3]
  PIN wslot[4]
    DIRECTION OUTPUT ;
    USE SIGNAL ;
    PORT
      LAYER M4 ;
        RECT  220.236 59.856 220.32 59.88 ;
    END
  END wslot[4]
  PIN wslot[5]
    DIRECTION OUTPUT ;
    USE SIGNAL ;
    PORT
      LAYER M4 ;
        RECT  220.236 59.952 220.32 59.976 ;
    END
  END wslot[5]
  PIN wslot[6]
    DIRECTION OUTPUT ;
    USE SIGNAL ;
    PORT
      LAYER M4 ;
        RECT  220.236 60.048 220.32 60.072 ;
    END
  END wslot[6]
  PIN wslot[7]
    DIRECTION OUTPUT ;
    USE SIGNAL ;
    PORT
      LAYER M4 ;
        RECT  220.236 60.144 220.32 60.168 ;
    END
  END wslot[7]
  PIN wslot[8]
    DIRECTION OUTPUT ;
    USE SIGNAL ;
    PORT
      LAYER M4 ;
        RECT  220.236 60.24 220.32 60.264 ;
    END
  END wslot[8]
  PIN wslot[9]
    DIRECTION OUTPUT ;
    USE SIGNAL ;
    PORT
      LAYER M4 ;
        RECT  220.236 60.336 220.32 60.36 ;
    END
  END wslot[9]
  PIN wslot_v[0]
    DIRECTION OUTPUT ;
    USE SIGNAL ;
    PORT
      LAYER M4 ;
        RECT  220.236 56.4 220.32 56.424 ;
    END
  END wslot_v[0]
  PIN wslot_v[1]
    DIRECTION OUTPUT ;
    USE SIGNAL ;
    PORT
      LAYER M4 ;
        RECT  220.236 56.496 220.32 56.52 ;
    END
  END wslot_v[1]
  PIN wslot_v[2]
    DIRECTION OUTPUT ;
    USE SIGNAL ;
    PORT
      LAYER M4 ;
        RECT  220.236 56.592 220.32 56.616 ;
    END
  END wslot_v[2]
  PIN wslot_v[3]
    DIRECTION OUTPUT ;
    USE SIGNAL ;
    PORT
      LAYER M4 ;
        RECT  220.236 56.688 220.32 56.712 ;
    END
  END wslot_v[3]
  PIN wslot_v[4]
    DIRECTION OUTPUT ;
    USE SIGNAL ;
    PORT
      LAYER M4 ;
        RECT  220.236 56.784 220.32 56.808 ;
    END
  END wslot_v[4]
  PIN wslot_v[5]
    DIRECTION OUTPUT ;
    USE SIGNAL ;
    PORT
      LAYER M4 ;
        RECT  220.236 56.88 220.32 56.904 ;
    END
  END wslot_v[5]
  PIN wslot_v[6]
    DIRECTION OUTPUT ;
    USE SIGNAL ;
    PORT
      LAYER M4 ;
        RECT  220.236 56.976 220.32 57 ;
    END
  END wslot_v[6]
  PIN wslot_v[7]
    DIRECTION OUTPUT ;
    USE SIGNAL ;
    PORT
      LAYER M4 ;
        RECT  220.236 57.072 220.32 57.096 ;
    END
  END wslot_v[7]
  PIN VDD
    DIRECTION INOUT ;
    USE POWER ;
    PORT
      LAYER M5 ;
        RECT  213.192 2.151 213.312 114.489 ;
        RECT  207.792 2.151 207.912 114.489 ;
        RECT  202.392 2.151 202.512 114.489 ;
        RECT  196.992 2.151 197.112 114.489 ;
        RECT  191.592 2.151 191.712 114.489 ;
        RECT  186.192 2.151 186.312 114.489 ;
        RECT  180.792 2.151 180.912 114.489 ;
        RECT  175.392 2.151 175.512 114.489 ;
        RECT  169.992 2.151 170.112 114.489 ;
        RECT  164.592 2.151 164.712 114.489 ;
        RECT  159.192 2.151 159.312 114.489 ;
        RECT  153.792 2.151 153.912 114.489 ;
        RECT  148.392 2.151 148.512 114.489 ;
        RECT  142.992 2.151 143.112 114.489 ;
        RECT  137.592 2.151 137.712 114.489 ;
        RECT  132.192 2.151 132.312 114.489 ;
        RECT  126.792 2.151 126.912 114.489 ;
        RECT  121.392 2.151 121.512 114.489 ;
        RECT  115.992 2.151 116.112 114.489 ;
        RECT  110.592 2.151 110.712 114.489 ;
        RECT  105.192 2.151 105.312 114.489 ;
        RECT  99.792 2.151 99.912 114.489 ;
        RECT  94.392 2.151 94.512 114.489 ;
        RECT  88.992 2.151 89.112 114.489 ;
        RECT  83.592 2.151 83.712 114.489 ;
        RECT  78.192 2.151 78.312 114.489 ;
        RECT  72.792 2.151 72.912 114.489 ;
        RECT  67.392 2.151 67.512 114.489 ;
        RECT  61.992 2.151 62.112 114.489 ;
        RECT  56.592 2.151 56.712 114.489 ;
        RECT  51.192 2.151 51.312 114.489 ;
        RECT  45.792 2.151 45.912 114.489 ;
        RECT  40.392 2.151 40.512 114.489 ;
        RECT  34.992 2.151 35.112 114.489 ;
        RECT  29.592 2.151 29.712 114.489 ;
        RECT  24.192 2.151 24.312 114.489 ;
        RECT  18.792 2.151 18.912 114.489 ;
        RECT  13.392 2.151 13.512 114.489 ;
        RECT  7.992 2.151 8.112 114.489 ;
        RECT  2.592 2.151 2.712 114.489 ;
    END
  END VDD
  PIN VSS
    DIRECTION INOUT ;
    USE GROUND ;
    PORT
      LAYER M5 ;
        RECT  213 2.137 213.12 114.503 ;
        RECT  207.6 2.137 207.72 114.503 ;
        RECT  202.2 2.137 202.32 114.503 ;
        RECT  196.8 2.137 196.92 114.503 ;
        RECT  191.4 2.137 191.52 114.503 ;
        RECT  186 2.137 186.12 114.503 ;
        RECT  180.6 2.137 180.72 114.503 ;
        RECT  175.2 2.137 175.32 114.503 ;
        RECT  169.8 2.137 169.92 114.503 ;
        RECT  164.4 2.137 164.52 114.503 ;
        RECT  159 2.137 159.12 114.503 ;
        RECT  153.6 2.137 153.72 114.503 ;
        RECT  148.2 2.137 148.32 114.503 ;
        RECT  142.8 2.137 142.92 114.503 ;
        RECT  137.4 2.137 137.52 114.503 ;
        RECT  132 2.137 132.12 114.503 ;
        RECT  126.6 2.137 126.72 114.503 ;
        RECT  121.2 2.137 121.32 114.503 ;
        RECT  115.8 2.137 115.92 114.503 ;
        RECT  110.4 2.137 110.52 114.503 ;
        RECT  105 2.137 105.12 114.503 ;
        RECT  99.6 2.137 99.72 114.503 ;
        RECT  94.2 2.137 94.32 114.503 ;
        RECT  88.8 2.137 88.92 114.503 ;
        RECT  83.4 2.137 83.52 114.503 ;
        RECT  78 2.137 78.12 114.503 ;
        RECT  72.6 2.137 72.72 114.503 ;
        RECT  67.2 2.137 67.32 114.503 ;
        RECT  61.8 2.137 61.92 114.503 ;
        RECT  56.4 2.137 56.52 114.503 ;
        RECT  51 2.137 51.12 114.503 ;
        RECT  45.6 2.137 45.72 114.503 ;
        RECT  40.2 2.137 40.32 114.503 ;
        RECT  34.8 2.137 34.92 114.503 ;
        RECT  29.4 2.137 29.52 114.503 ;
        RECT  24 2.137 24.12 114.503 ;
        RECT  18.6 2.137 18.72 114.503 ;
        RECT  13.2 2.137 13.32 114.503 ;
        RECT  7.8 2.137 7.92 114.503 ;
        RECT  2.4 2.137 2.52 114.503 ;
    END
  END VSS
  # OT_OBS_CLOSED layer=M5 d_um=1.536 added=171
  OBS
    LAYER RVTN ;
     RECT  2.16 2.16 218.16 2.295 ;
     RECT  2.16 2.565 218.16 2.835 ;
     RECT  2.16 3.105 218.16 3.375 ;
     RECT  2.16 3.645 218.16 3.915 ;
     RECT  2.16 4.185 218.16 4.455 ;
     RECT  2.16 4.725 218.16 4.995 ;
     RECT  2.16 5.265 218.16 5.535 ;
     RECT  2.16 5.805 218.16 6.075 ;
     RECT  2.16 6.345 218.16 6.615 ;
     RECT  2.16 6.885 218.16 7.155 ;
     RECT  2.16 7.425 218.16 7.695 ;
     RECT  2.16 7.965 218.16 8.235 ;
     RECT  2.16 8.505 218.16 8.775 ;
     RECT  2.16 9.045 218.16 9.315 ;
     RECT  2.16 9.585 218.16 9.855 ;
     RECT  2.16 10.125 218.16 10.395 ;
     RECT  2.16 10.665 218.16 10.935 ;
     RECT  2.16 11.205 218.16 11.475 ;
     RECT  2.16 11.745 218.16 12.015 ;
     RECT  2.16 12.285 218.16 12.555 ;
     RECT  2.16 12.825 218.16 13.095 ;
     RECT  2.16 13.365 218.16 13.635 ;
     RECT  2.16 13.905 218.16 14.175 ;
     RECT  2.16 14.445 218.16 14.715 ;
     RECT  2.16 14.985 218.16 15.255 ;
     RECT  2.16 15.525 218.16 15.795 ;
     RECT  2.16 16.065 218.16 16.335 ;
     RECT  2.16 16.605 218.16 16.875 ;
     RECT  2.16 17.145 218.16 17.415 ;
     RECT  2.16 17.685 218.16 17.955 ;
     RECT  2.16 18.225 218.16 18.495 ;
     RECT  2.16 18.765 218.16 19.035 ;
     RECT  2.16 19.305 218.16 19.575 ;
     RECT  2.16 19.845 218.16 20.115 ;
     RECT  2.16 20.385 218.16 20.655 ;
     RECT  2.16 20.925 218.16 21.195 ;
     RECT  2.16 21.465 218.16 21.6 ;
     RECT  2.16 21.6 20.844 21.735 ;
     RECT  199.692 21.6 218.16 21.735 ;
     RECT  2.16 22.005 20.844 22.275 ;
     RECT  199.692 22.005 218.16 22.275 ;
     RECT  2.16 22.545 20.844 22.815 ;
     RECT  199.692 22.545 218.16 22.815 ;
     RECT  2.16 23.085 20.844 23.355 ;
     RECT  199.692 23.085 218.16 23.355 ;
     RECT  2.16 23.625 20.844 23.895 ;
     RECT  199.692 23.625 218.16 23.895 ;
     RECT  2.16 24.165 20.844 24.435 ;
     RECT  199.692 24.165 218.16 24.435 ;
     RECT  2.16 24.705 20.844 24.975 ;
     RECT  199.692 24.705 218.16 24.975 ;
     RECT  2.16 25.245 20.844 25.515 ;
     RECT  199.692 25.245 218.16 25.515 ;
     RECT  2.16 25.785 20.844 26.055 ;
     RECT  199.692 25.785 218.16 26.055 ;
     RECT  2.16 26.325 20.844 26.595 ;
     RECT  199.692 26.325 218.16 26.595 ;
     RECT  2.16 26.865 20.844 27.135 ;
     RECT  199.692 26.865 218.16 27.135 ;
     RECT  2.16 27.405 20.844 27.675 ;
     RECT  199.692 27.405 218.16 27.675 ;
     RECT  2.16 27.945 20.844 28.215 ;
     RECT  199.692 27.945 218.16 28.215 ;
     RECT  2.16 28.485 20.844 28.755 ;
     RECT  199.692 28.485 218.16 28.755 ;
     RECT  2.16 29.025 20.844 29.295 ;
     RECT  199.692 29.025 218.16 29.295 ;
     RECT  2.16 29.565 20.844 29.835 ;
     RECT  199.692 29.565 218.16 29.835 ;
     RECT  2.16 30.105 20.844 30.375 ;
     RECT  199.692 30.105 218.16 30.375 ;
     RECT  2.16 30.645 20.844 30.915 ;
     RECT  199.692 30.645 218.16 30.915 ;
     RECT  2.16 31.185 20.844 31.455 ;
     RECT  199.692 31.185 218.16 31.455 ;
     RECT  2.16 31.725 20.844 31.995 ;
     RECT  199.692 31.725 218.16 31.995 ;
     RECT  2.16 32.265 20.844 32.535 ;
     RECT  199.692 32.265 218.16 32.535 ;
     RECT  2.16 32.805 20.844 33.075 ;
     RECT  199.692 32.805 218.16 33.075 ;
     RECT  2.16 33.345 20.844 33.615 ;
     RECT  199.692 33.345 218.16 33.615 ;
     RECT  2.16 33.885 20.844 34.155 ;
     RECT  199.692 33.885 218.16 34.155 ;
     RECT  2.16 34.425 20.844 34.695 ;
     RECT  199.692 34.425 218.16 34.695 ;
     RECT  2.16 34.965 20.844 35.235 ;
     RECT  199.692 34.965 218.16 35.235 ;
     RECT  2.16 35.505 20.844 35.775 ;
     RECT  199.692 35.505 218.16 35.775 ;
     RECT  2.16 36.045 20.844 36.315 ;
     RECT  199.692 36.045 218.16 36.315 ;
     RECT  2.16 36.585 20.844 36.855 ;
     RECT  199.692 36.585 218.16 36.855 ;
     RECT  2.16 37.125 20.844 37.395 ;
     RECT  199.692 37.125 218.16 37.395 ;
     RECT  2.16 37.665 20.844 37.935 ;
     RECT  199.692 37.665 218.16 37.935 ;
     RECT  2.16 38.205 20.844 38.475 ;
     RECT  199.692 38.205 218.16 38.475 ;
     RECT  2.16 38.745 20.844 39.015 ;
     RECT  199.692 38.745 218.16 39.015 ;
     RECT  2.16 39.285 20.844 39.555 ;
     RECT  199.692 39.285 218.16 39.555 ;
     RECT  2.16 39.825 20.844 40.095 ;
     RECT  199.692 39.825 218.16 40.095 ;
     RECT  2.16 40.365 20.844 40.635 ;
     RECT  199.692 40.365 218.16 40.635 ;
     RECT  2.16 40.905 20.844 41.175 ;
     RECT  199.692 40.905 218.16 41.175 ;
     RECT  2.16 41.445 20.844 41.715 ;
     RECT  199.692 41.445 218.16 41.715 ;
     RECT  2.16 41.985 20.844 42.255 ;
     RECT  199.692 41.985 218.16 42.255 ;
     RECT  2.16 42.525 20.844 42.795 ;
     RECT  199.692 42.525 218.16 42.795 ;
     RECT  2.16 43.065 20.844 43.335 ;
     RECT  199.692 43.065 218.16 43.335 ;
     RECT  2.16 43.605 20.844 43.875 ;
     RECT  199.692 43.605 218.16 43.875 ;
     RECT  2.16 44.145 20.844 44.415 ;
     RECT  199.692 44.145 218.16 44.415 ;
     RECT  2.16 44.685 20.844 44.955 ;
     RECT  199.692 44.685 218.16 44.955 ;
     RECT  2.16 45.225 20.844 45.495 ;
     RECT  199.692 45.225 218.16 45.495 ;
     RECT  2.16 45.765 20.844 46.035 ;
     RECT  199.692 45.765 218.16 46.035 ;
     RECT  2.16 46.305 20.844 46.575 ;
     RECT  199.692 46.305 218.16 46.575 ;
     RECT  2.16 46.845 20.844 47.115 ;
     RECT  199.692 46.845 218.16 47.115 ;
     RECT  2.16 47.385 20.844 47.655 ;
     RECT  199.692 47.385 218.16 47.655 ;
     RECT  2.16 47.925 20.844 48.195 ;
     RECT  199.692 47.925 218.16 48.195 ;
     RECT  2.16 48.465 20.844 48.735 ;
     RECT  199.692 48.465 218.16 48.735 ;
     RECT  2.16 49.005 20.844 49.275 ;
     RECT  199.692 49.005 218.16 49.275 ;
     RECT  2.16 49.545 20.844 49.815 ;
     RECT  199.692 49.545 218.16 49.815 ;
     RECT  2.16 50.085 20.844 50.355 ;
     RECT  199.692 50.085 218.16 50.355 ;
     RECT  2.16 50.625 20.844 50.895 ;
     RECT  199.692 50.625 218.16 50.895 ;
     RECT  2.16 51.165 20.844 51.435 ;
     RECT  199.692 51.165 218.16 51.435 ;
     RECT  2.16 51.705 20.844 51.975 ;
     RECT  199.692 51.705 218.16 51.975 ;
     RECT  2.16 52.245 20.844 52.515 ;
     RECT  199.692 52.245 218.16 52.515 ;
     RECT  2.16 52.785 20.844 53.055 ;
     RECT  199.692 52.785 218.16 53.055 ;
     RECT  2.16 53.325 20.844 53.595 ;
     RECT  199.692 53.325 218.16 53.595 ;
     RECT  2.16 53.865 20.844 54.135 ;
     RECT  199.692 53.865 218.16 54.135 ;
     RECT  2.16 54.405 20.844 54.675 ;
     RECT  199.692 54.405 218.16 54.675 ;
     RECT  2.16 54.945 20.844 55.215 ;
     RECT  199.692 54.945 218.16 55.215 ;
     RECT  2.16 55.485 20.844 55.755 ;
     RECT  199.692 55.485 218.16 55.755 ;
     RECT  2.16 56.025 20.844 56.295 ;
     RECT  199.692 56.025 218.16 56.295 ;
     RECT  2.16 56.565 20.844 56.835 ;
     RECT  199.692 56.565 218.16 56.835 ;
     RECT  2.16 57.105 20.844 57.375 ;
     RECT  199.692 57.105 218.16 57.375 ;
     RECT  2.16 57.645 20.844 57.915 ;
     RECT  199.692 57.645 218.16 57.915 ;
     RECT  2.16 58.185 20.844 58.455 ;
     RECT  199.692 58.185 218.16 58.455 ;
     RECT  2.16 58.725 20.844 58.995 ;
     RECT  199.692 58.725 218.16 58.995 ;
     RECT  2.16 59.265 20.844 59.535 ;
     RECT  199.692 59.265 218.16 59.535 ;
     RECT  2.16 59.805 20.844 60.075 ;
     RECT  199.692 59.805 218.16 60.075 ;
     RECT  2.16 60.345 20.844 60.615 ;
     RECT  199.692 60.345 218.16 60.615 ;
     RECT  2.16 60.885 20.844 61.155 ;
     RECT  199.692 60.885 218.16 61.155 ;
     RECT  2.16 61.425 20.844 61.695 ;
     RECT  199.692 61.425 218.16 61.695 ;
     RECT  2.16 61.965 20.844 62.235 ;
     RECT  199.692 61.965 218.16 62.235 ;
     RECT  2.16 62.505 20.844 62.775 ;
     RECT  199.692 62.505 218.16 62.775 ;
     RECT  2.16 63.045 20.844 63.315 ;
     RECT  199.692 63.045 218.16 63.315 ;
     RECT  2.16 63.585 20.844 63.855 ;
     RECT  199.692 63.585 218.16 63.855 ;
     RECT  2.16 64.125 20.844 64.395 ;
     RECT  199.692 64.125 218.16 64.395 ;
     RECT  2.16 64.665 20.844 64.935 ;
     RECT  199.692 64.665 218.16 64.935 ;
     RECT  2.16 65.205 20.844 65.475 ;
     RECT  199.692 65.205 218.16 65.475 ;
     RECT  2.16 65.745 20.844 66.015 ;
     RECT  199.692 65.745 218.16 66.015 ;
     RECT  2.16 66.285 20.844 66.555 ;
     RECT  199.692 66.285 218.16 66.555 ;
     RECT  2.16 66.825 20.844 67.095 ;
     RECT  199.692 66.825 218.16 67.095 ;
     RECT  2.16 67.365 20.844 67.635 ;
     RECT  199.692 67.365 218.16 67.635 ;
     RECT  2.16 67.905 20.844 68.175 ;
     RECT  199.692 67.905 218.16 68.175 ;
     RECT  2.16 68.445 20.844 68.715 ;
     RECT  199.692 68.445 218.16 68.715 ;
     RECT  2.16 68.985 20.844 69.255 ;
     RECT  199.692 68.985 218.16 69.255 ;
     RECT  2.16 69.525 20.844 69.795 ;
     RECT  199.692 69.525 218.16 69.795 ;
     RECT  2.16 70.065 20.844 70.335 ;
     RECT  199.692 70.065 218.16 70.335 ;
     RECT  2.16 70.605 20.844 70.875 ;
     RECT  199.692 70.605 218.16 70.875 ;
     RECT  2.16 71.145 20.844 71.415 ;
     RECT  199.692 71.145 218.16 71.415 ;
     RECT  2.16 71.685 20.844 71.955 ;
     RECT  199.692 71.685 218.16 71.955 ;
     RECT  2.16 72.225 20.844 72.495 ;
     RECT  199.692 72.225 218.16 72.495 ;
     RECT  2.16 72.765 20.844 73.035 ;
     RECT  199.692 72.765 218.16 73.035 ;
     RECT  2.16 73.305 20.844 73.575 ;
     RECT  199.692 73.305 218.16 73.575 ;
     RECT  2.16 73.845 20.844 74.115 ;
     RECT  199.692 73.845 218.16 74.115 ;
     RECT  2.16 74.385 20.844 74.655 ;
     RECT  199.692 74.385 218.16 74.655 ;
     RECT  2.16 74.925 20.844 75.195 ;
     RECT  199.692 74.925 218.16 75.195 ;
     RECT  2.16 75.465 20.844 75.735 ;
     RECT  199.692 75.465 218.16 75.735 ;
     RECT  2.16 76.005 20.844 76.275 ;
     RECT  199.692 76.005 218.16 76.275 ;
     RECT  2.16 76.545 20.844 76.815 ;
     RECT  199.692 76.545 218.16 76.815 ;
     RECT  2.16 77.085 20.844 77.355 ;
     RECT  199.692 77.085 218.16 77.355 ;
     RECT  2.16 77.625 20.844 77.895 ;
     RECT  199.692 77.625 218.16 77.895 ;
     RECT  2.16 78.165 20.844 78.435 ;
     RECT  199.692 78.165 218.16 78.435 ;
     RECT  2.16 78.705 20.844 78.975 ;
     RECT  199.692 78.705 218.16 78.975 ;
     RECT  2.16 79.245 20.844 79.515 ;
     RECT  199.692 79.245 218.16 79.515 ;
     RECT  2.16 79.785 20.844 80.055 ;
     RECT  199.692 79.785 218.16 80.055 ;
     RECT  2.16 80.325 20.844 80.595 ;
     RECT  199.692 80.325 218.16 80.595 ;
     RECT  2.16 80.865 20.844 81.135 ;
     RECT  199.692 80.865 218.16 81.135 ;
     RECT  2.16 81.405 20.844 81.675 ;
     RECT  199.692 81.405 218.16 81.675 ;
     RECT  2.16 81.945 20.844 82.215 ;
     RECT  199.692 81.945 218.16 82.215 ;
     RECT  2.16 82.485 20.844 82.755 ;
     RECT  199.692 82.485 218.16 82.755 ;
     RECT  2.16 83.025 20.844 83.295 ;
     RECT  199.692 83.025 218.16 83.295 ;
     RECT  2.16 83.565 20.844 83.835 ;
     RECT  199.692 83.565 218.16 83.835 ;
     RECT  2.16 84.105 20.844 84.375 ;
     RECT  199.692 84.105 218.16 84.375 ;
     RECT  2.16 84.645 20.844 84.915 ;
     RECT  199.692 84.645 218.16 84.915 ;
     RECT  2.16 85.185 20.844 85.455 ;
     RECT  199.692 85.185 218.16 85.455 ;
     RECT  2.16 85.725 20.844 85.995 ;
     RECT  199.692 85.725 218.16 85.995 ;
     RECT  2.16 86.265 20.844 86.535 ;
     RECT  199.692 86.265 218.16 86.535 ;
     RECT  2.16 86.805 20.844 87.075 ;
     RECT  199.692 86.805 218.16 87.075 ;
     RECT  2.16 87.345 20.844 87.615 ;
     RECT  199.692 87.345 218.16 87.615 ;
     RECT  2.16 87.885 20.844 88.155 ;
     RECT  199.692 87.885 218.16 88.155 ;
     RECT  2.16 88.425 20.844 88.695 ;
     RECT  199.692 88.425 218.16 88.695 ;
     RECT  2.16 88.965 20.844 89.235 ;
     RECT  199.692 88.965 218.16 89.235 ;
     RECT  2.16 89.505 20.844 89.775 ;
     RECT  199.692 89.505 218.16 89.775 ;
     RECT  2.16 90.045 20.844 90.315 ;
     RECT  199.692 90.045 218.16 90.315 ;
     RECT  2.16 90.585 20.844 90.855 ;
     RECT  199.692 90.585 218.16 90.855 ;
     RECT  2.16 91.125 20.844 91.395 ;
     RECT  199.692 91.125 218.16 91.395 ;
     RECT  2.16 91.665 20.844 91.935 ;
     RECT  199.692 91.665 218.16 91.935 ;
     RECT  2.16 92.205 20.844 92.475 ;
     RECT  199.692 92.205 218.16 92.475 ;
     RECT  2.16 92.745 20.844 93.015 ;
     RECT  199.692 92.745 218.16 93.015 ;
     RECT  2.16 93.285 20.844 93.555 ;
     RECT  199.692 93.285 218.16 93.555 ;
     RECT  2.16 93.825 20.844 94.095 ;
     RECT  199.692 93.825 218.16 94.095 ;
     RECT  2.16 94.365 20.844 94.635 ;
     RECT  199.692 94.365 218.16 94.635 ;
     RECT  2.16 94.905 20.844 95.175 ;
     RECT  199.692 94.905 218.16 95.175 ;
     RECT  2.16 95.445 20.844 95.715 ;
     RECT  199.692 95.445 218.16 95.715 ;
     RECT  2.16 95.985 20.844 96.255 ;
     RECT  199.692 95.985 218.16 96.255 ;
     RECT  2.16 96.525 218.16 96.795 ;
     RECT  2.16 97.065 218.16 97.335 ;
     RECT  2.16 97.605 218.16 97.875 ;
     RECT  2.16 98.145 218.16 98.415 ;
     RECT  2.16 98.685 218.16 98.955 ;
     RECT  2.16 99.225 218.16 99.495 ;
     RECT  2.16 99.765 218.16 100.035 ;
     RECT  2.16 100.305 218.16 100.575 ;
     RECT  2.16 100.845 218.16 101.115 ;
     RECT  2.16 101.385 218.16 101.655 ;
     RECT  2.16 101.925 218.16 102.195 ;
     RECT  2.16 102.465 218.16 102.735 ;
     RECT  2.16 103.005 218.16 103.275 ;
     RECT  2.16 103.545 218.16 103.815 ;
     RECT  2.16 104.085 218.16 104.355 ;
     RECT  2.16 104.625 218.16 104.895 ;
     RECT  2.16 105.165 218.16 105.435 ;
     RECT  2.16 105.705 218.16 105.975 ;
     RECT  2.16 106.245 218.16 106.515 ;
     RECT  2.16 106.785 218.16 107.055 ;
     RECT  2.16 107.325 218.16 107.595 ;
     RECT  2.16 107.865 218.16 108.135 ;
     RECT  2.16 108.405 218.16 108.675 ;
     RECT  2.16 108.945 218.16 109.215 ;
     RECT  2.16 109.485 218.16 109.755 ;
     RECT  2.16 110.025 218.16 110.295 ;
     RECT  2.16 110.565 218.16 110.835 ;
     RECT  2.16 111.105 218.16 111.375 ;
     RECT  2.16 111.645 218.16 111.915 ;
     RECT  2.16 112.185 218.16 112.455 ;
     RECT  2.16 112.725 218.16 112.995 ;
     RECT  2.16 113.265 218.16 113.535 ;
     RECT  2.16 113.805 218.16 114.075 ;
     RECT  2.16 114.345 218.16 114.48 ;
    LAYER RVTP ;
     RECT  2.16 2.295 218.16 2.565 ;
     RECT  2.16 2.835 218.16 3.105 ;
     RECT  2.16 3.375 218.16 3.645 ;
     RECT  2.16 3.915 218.16 4.185 ;
     RECT  2.16 4.455 218.16 4.725 ;
     RECT  2.16 4.995 218.16 5.265 ;
     RECT  2.16 5.535 218.16 5.805 ;
     RECT  2.16 6.075 218.16 6.345 ;
     RECT  2.16 6.615 218.16 6.885 ;
     RECT  2.16 7.155 218.16 7.425 ;
     RECT  2.16 7.695 218.16 7.965 ;
     RECT  2.16 8.235 218.16 8.505 ;
     RECT  2.16 8.775 218.16 9.045 ;
     RECT  2.16 9.315 218.16 9.585 ;
     RECT  2.16 9.855 218.16 10.125 ;
     RECT  2.16 10.395 218.16 10.665 ;
     RECT  2.16 10.935 218.16 11.205 ;
     RECT  2.16 11.475 218.16 11.745 ;
     RECT  2.16 12.015 218.16 12.285 ;
     RECT  2.16 12.555 218.16 12.825 ;
     RECT  2.16 13.095 218.16 13.365 ;
     RECT  2.16 13.635 218.16 13.905 ;
     RECT  2.16 14.175 218.16 14.445 ;
     RECT  2.16 14.715 218.16 14.985 ;
     RECT  2.16 15.255 218.16 15.525 ;
     RECT  2.16 15.795 218.16 16.065 ;
     RECT  2.16 16.335 218.16 16.605 ;
     RECT  2.16 16.875 218.16 17.145 ;
     RECT  2.16 17.415 218.16 17.685 ;
     RECT  2.16 17.955 218.16 18.225 ;
     RECT  2.16 18.495 218.16 18.765 ;
     RECT  2.16 19.035 218.16 19.305 ;
     RECT  2.16 19.575 218.16 19.845 ;
     RECT  2.16 20.115 218.16 20.385 ;
     RECT  2.16 20.655 218.16 20.925 ;
     RECT  2.16 21.195 218.16 21.465 ;
     RECT  2.16 21.735 20.844 22.005 ;
     RECT  199.692 21.735 218.16 22.005 ;
     RECT  2.16 22.275 20.844 22.545 ;
     RECT  199.692 22.275 218.16 22.545 ;
     RECT  2.16 22.815 20.844 23.085 ;
     RECT  199.692 22.815 218.16 23.085 ;
     RECT  2.16 23.355 20.844 23.625 ;
     RECT  199.692 23.355 218.16 23.625 ;
     RECT  2.16 23.895 20.844 24.165 ;
     RECT  199.692 23.895 218.16 24.165 ;
     RECT  2.16 24.435 20.844 24.705 ;
     RECT  199.692 24.435 218.16 24.705 ;
     RECT  2.16 24.975 20.844 25.245 ;
     RECT  199.692 24.975 218.16 25.245 ;
     RECT  2.16 25.515 20.844 25.785 ;
     RECT  199.692 25.515 218.16 25.785 ;
     RECT  2.16 26.055 20.844 26.325 ;
     RECT  199.692 26.055 218.16 26.325 ;
     RECT  2.16 26.595 20.844 26.865 ;
     RECT  199.692 26.595 218.16 26.865 ;
     RECT  2.16 27.135 20.844 27.405 ;
     RECT  199.692 27.135 218.16 27.405 ;
     RECT  2.16 27.675 20.844 27.945 ;
     RECT  199.692 27.675 218.16 27.945 ;
     RECT  2.16 28.215 20.844 28.485 ;
     RECT  199.692 28.215 218.16 28.485 ;
     RECT  2.16 28.755 20.844 29.025 ;
     RECT  199.692 28.755 218.16 29.025 ;
     RECT  2.16 29.295 20.844 29.565 ;
     RECT  199.692 29.295 218.16 29.565 ;
     RECT  2.16 29.835 20.844 30.105 ;
     RECT  199.692 29.835 218.16 30.105 ;
     RECT  2.16 30.375 20.844 30.645 ;
     RECT  199.692 30.375 218.16 30.645 ;
     RECT  2.16 30.915 20.844 31.185 ;
     RECT  199.692 30.915 218.16 31.185 ;
     RECT  2.16 31.455 20.844 31.725 ;
     RECT  199.692 31.455 218.16 31.725 ;
     RECT  2.16 31.995 20.844 32.265 ;
     RECT  199.692 31.995 218.16 32.265 ;
     RECT  2.16 32.535 20.844 32.805 ;
     RECT  199.692 32.535 218.16 32.805 ;
     RECT  2.16 33.075 20.844 33.345 ;
     RECT  199.692 33.075 218.16 33.345 ;
     RECT  2.16 33.615 20.844 33.885 ;
     RECT  199.692 33.615 218.16 33.885 ;
     RECT  2.16 34.155 20.844 34.425 ;
     RECT  199.692 34.155 218.16 34.425 ;
     RECT  2.16 34.695 20.844 34.965 ;
     RECT  199.692 34.695 218.16 34.965 ;
     RECT  2.16 35.235 20.844 35.505 ;
     RECT  199.692 35.235 218.16 35.505 ;
     RECT  2.16 35.775 20.844 36.045 ;
     RECT  199.692 35.775 218.16 36.045 ;
     RECT  2.16 36.315 20.844 36.585 ;
     RECT  199.692 36.315 218.16 36.585 ;
     RECT  2.16 36.855 20.844 37.125 ;
     RECT  199.692 36.855 218.16 37.125 ;
     RECT  2.16 37.395 20.844 37.665 ;
     RECT  199.692 37.395 218.16 37.665 ;
     RECT  2.16 37.935 20.844 38.205 ;
     RECT  199.692 37.935 218.16 38.205 ;
     RECT  2.16 38.475 20.844 38.745 ;
     RECT  199.692 38.475 218.16 38.745 ;
     RECT  2.16 39.015 20.844 39.285 ;
     RECT  199.692 39.015 218.16 39.285 ;
     RECT  2.16 39.555 20.844 39.825 ;
     RECT  199.692 39.555 218.16 39.825 ;
     RECT  2.16 40.095 20.844 40.365 ;
     RECT  199.692 40.095 218.16 40.365 ;
     RECT  2.16 40.635 20.844 40.905 ;
     RECT  199.692 40.635 218.16 40.905 ;
     RECT  2.16 41.175 20.844 41.445 ;
     RECT  199.692 41.175 218.16 41.445 ;
     RECT  2.16 41.715 20.844 41.985 ;
     RECT  199.692 41.715 218.16 41.985 ;
     RECT  2.16 42.255 20.844 42.525 ;
     RECT  199.692 42.255 218.16 42.525 ;
     RECT  2.16 42.795 20.844 43.065 ;
     RECT  199.692 42.795 218.16 43.065 ;
     RECT  2.16 43.335 20.844 43.605 ;
     RECT  199.692 43.335 218.16 43.605 ;
     RECT  2.16 43.875 20.844 44.145 ;
     RECT  199.692 43.875 218.16 44.145 ;
     RECT  2.16 44.415 20.844 44.685 ;
     RECT  199.692 44.415 218.16 44.685 ;
     RECT  2.16 44.955 20.844 45.225 ;
     RECT  199.692 44.955 218.16 45.225 ;
     RECT  2.16 45.495 20.844 45.765 ;
     RECT  199.692 45.495 218.16 45.765 ;
     RECT  2.16 46.035 20.844 46.305 ;
     RECT  199.692 46.035 218.16 46.305 ;
     RECT  2.16 46.575 20.844 46.845 ;
     RECT  199.692 46.575 218.16 46.845 ;
     RECT  2.16 47.115 20.844 47.385 ;
     RECT  199.692 47.115 218.16 47.385 ;
     RECT  2.16 47.655 20.844 47.925 ;
     RECT  199.692 47.655 218.16 47.925 ;
     RECT  2.16 48.195 20.844 48.465 ;
     RECT  199.692 48.195 218.16 48.465 ;
     RECT  2.16 48.735 20.844 49.005 ;
     RECT  199.692 48.735 218.16 49.005 ;
     RECT  2.16 49.275 20.844 49.545 ;
     RECT  199.692 49.275 218.16 49.545 ;
     RECT  2.16 49.815 20.844 50.085 ;
     RECT  199.692 49.815 218.16 50.085 ;
     RECT  2.16 50.355 20.844 50.625 ;
     RECT  199.692 50.355 218.16 50.625 ;
     RECT  2.16 50.895 20.844 51.165 ;
     RECT  199.692 50.895 218.16 51.165 ;
     RECT  2.16 51.435 20.844 51.705 ;
     RECT  199.692 51.435 218.16 51.705 ;
     RECT  2.16 51.975 20.844 52.245 ;
     RECT  199.692 51.975 218.16 52.245 ;
     RECT  2.16 52.515 20.844 52.785 ;
     RECT  199.692 52.515 218.16 52.785 ;
     RECT  2.16 53.055 20.844 53.325 ;
     RECT  199.692 53.055 218.16 53.325 ;
     RECT  2.16 53.595 20.844 53.865 ;
     RECT  199.692 53.595 218.16 53.865 ;
     RECT  2.16 54.135 20.844 54.405 ;
     RECT  199.692 54.135 218.16 54.405 ;
     RECT  2.16 54.675 20.844 54.945 ;
     RECT  199.692 54.675 218.16 54.945 ;
     RECT  2.16 55.215 20.844 55.485 ;
     RECT  199.692 55.215 218.16 55.485 ;
     RECT  2.16 55.755 20.844 56.025 ;
     RECT  199.692 55.755 218.16 56.025 ;
     RECT  2.16 56.295 20.844 56.565 ;
     RECT  199.692 56.295 218.16 56.565 ;
     RECT  2.16 56.835 20.844 57.105 ;
     RECT  199.692 56.835 218.16 57.105 ;
     RECT  2.16 57.375 20.844 57.645 ;
     RECT  199.692 57.375 218.16 57.645 ;
     RECT  2.16 57.915 20.844 58.185 ;
     RECT  199.692 57.915 218.16 58.185 ;
     RECT  2.16 58.455 20.844 58.725 ;
     RECT  199.692 58.455 218.16 58.725 ;
     RECT  2.16 58.995 20.844 59.265 ;
     RECT  199.692 58.995 218.16 59.265 ;
     RECT  2.16 59.535 20.844 59.805 ;
     RECT  199.692 59.535 218.16 59.805 ;
     RECT  2.16 60.075 20.844 60.345 ;
     RECT  199.692 60.075 218.16 60.345 ;
     RECT  2.16 60.615 20.844 60.885 ;
     RECT  199.692 60.615 218.16 60.885 ;
     RECT  2.16 61.155 20.844 61.425 ;
     RECT  199.692 61.155 218.16 61.425 ;
     RECT  2.16 61.695 20.844 61.965 ;
     RECT  199.692 61.695 218.16 61.965 ;
     RECT  2.16 62.235 20.844 62.505 ;
     RECT  199.692 62.235 218.16 62.505 ;
     RECT  2.16 62.775 20.844 63.045 ;
     RECT  199.692 62.775 218.16 63.045 ;
     RECT  2.16 63.315 20.844 63.585 ;
     RECT  199.692 63.315 218.16 63.585 ;
     RECT  2.16 63.855 20.844 64.125 ;
     RECT  199.692 63.855 218.16 64.125 ;
     RECT  2.16 64.395 20.844 64.665 ;
     RECT  199.692 64.395 218.16 64.665 ;
     RECT  2.16 64.935 20.844 65.205 ;
     RECT  199.692 64.935 218.16 65.205 ;
     RECT  2.16 65.475 20.844 65.745 ;
     RECT  199.692 65.475 218.16 65.745 ;
     RECT  2.16 66.015 20.844 66.285 ;
     RECT  199.692 66.015 218.16 66.285 ;
     RECT  2.16 66.555 20.844 66.825 ;
     RECT  199.692 66.555 218.16 66.825 ;
     RECT  2.16 67.095 20.844 67.365 ;
     RECT  199.692 67.095 218.16 67.365 ;
     RECT  2.16 67.635 20.844 67.905 ;
     RECT  199.692 67.635 218.16 67.905 ;
     RECT  2.16 68.175 20.844 68.445 ;
     RECT  199.692 68.175 218.16 68.445 ;
     RECT  2.16 68.715 20.844 68.985 ;
     RECT  199.692 68.715 218.16 68.985 ;
     RECT  2.16 69.255 20.844 69.525 ;
     RECT  199.692 69.255 218.16 69.525 ;
     RECT  2.16 69.795 20.844 70.065 ;
     RECT  199.692 69.795 218.16 70.065 ;
     RECT  2.16 70.335 20.844 70.605 ;
     RECT  199.692 70.335 218.16 70.605 ;
     RECT  2.16 70.875 20.844 71.145 ;
     RECT  199.692 70.875 218.16 71.145 ;
     RECT  2.16 71.415 20.844 71.685 ;
     RECT  199.692 71.415 218.16 71.685 ;
     RECT  2.16 71.955 20.844 72.225 ;
     RECT  199.692 71.955 218.16 72.225 ;
     RECT  2.16 72.495 20.844 72.765 ;
     RECT  199.692 72.495 218.16 72.765 ;
     RECT  2.16 73.035 20.844 73.305 ;
     RECT  199.692 73.035 218.16 73.305 ;
     RECT  2.16 73.575 20.844 73.845 ;
     RECT  199.692 73.575 218.16 73.845 ;
     RECT  2.16 74.115 20.844 74.385 ;
     RECT  199.692 74.115 218.16 74.385 ;
     RECT  2.16 74.655 20.844 74.925 ;
     RECT  199.692 74.655 218.16 74.925 ;
     RECT  2.16 75.195 20.844 75.465 ;
     RECT  199.692 75.195 218.16 75.465 ;
     RECT  2.16 75.735 20.844 76.005 ;
     RECT  199.692 75.735 218.16 76.005 ;
     RECT  2.16 76.275 20.844 76.545 ;
     RECT  199.692 76.275 218.16 76.545 ;
     RECT  2.16 76.815 20.844 77.085 ;
     RECT  199.692 76.815 218.16 77.085 ;
     RECT  2.16 77.355 20.844 77.625 ;
     RECT  199.692 77.355 218.16 77.625 ;
     RECT  2.16 77.895 20.844 78.165 ;
     RECT  199.692 77.895 218.16 78.165 ;
     RECT  2.16 78.435 20.844 78.705 ;
     RECT  199.692 78.435 218.16 78.705 ;
     RECT  2.16 78.975 20.844 79.245 ;
     RECT  199.692 78.975 218.16 79.245 ;
     RECT  2.16 79.515 20.844 79.785 ;
     RECT  199.692 79.515 218.16 79.785 ;
     RECT  2.16 80.055 20.844 80.325 ;
     RECT  199.692 80.055 218.16 80.325 ;
     RECT  2.16 80.595 20.844 80.865 ;
     RECT  199.692 80.595 218.16 80.865 ;
     RECT  2.16 81.135 20.844 81.405 ;
     RECT  199.692 81.135 218.16 81.405 ;
     RECT  2.16 81.675 20.844 81.945 ;
     RECT  199.692 81.675 218.16 81.945 ;
     RECT  2.16 82.215 20.844 82.485 ;
     RECT  199.692 82.215 218.16 82.485 ;
     RECT  2.16 82.755 20.844 83.025 ;
     RECT  199.692 82.755 218.16 83.025 ;
     RECT  2.16 83.295 20.844 83.565 ;
     RECT  199.692 83.295 218.16 83.565 ;
     RECT  2.16 83.835 20.844 84.105 ;
     RECT  199.692 83.835 218.16 84.105 ;
     RECT  2.16 84.375 20.844 84.645 ;
     RECT  199.692 84.375 218.16 84.645 ;
     RECT  2.16 84.915 20.844 85.185 ;
     RECT  199.692 84.915 218.16 85.185 ;
     RECT  2.16 85.455 20.844 85.725 ;
     RECT  199.692 85.455 218.16 85.725 ;
     RECT  2.16 85.995 20.844 86.265 ;
     RECT  199.692 85.995 218.16 86.265 ;
     RECT  2.16 86.535 20.844 86.805 ;
     RECT  199.692 86.535 218.16 86.805 ;
     RECT  2.16 87.075 20.844 87.345 ;
     RECT  199.692 87.075 218.16 87.345 ;
     RECT  2.16 87.615 20.844 87.885 ;
     RECT  199.692 87.615 218.16 87.885 ;
     RECT  2.16 88.155 20.844 88.425 ;
     RECT  199.692 88.155 218.16 88.425 ;
     RECT  2.16 88.695 20.844 88.965 ;
     RECT  199.692 88.695 218.16 88.965 ;
     RECT  2.16 89.235 20.844 89.505 ;
     RECT  199.692 89.235 218.16 89.505 ;
     RECT  2.16 89.775 20.844 90.045 ;
     RECT  199.692 89.775 218.16 90.045 ;
     RECT  2.16 90.315 20.844 90.585 ;
     RECT  199.692 90.315 218.16 90.585 ;
     RECT  2.16 90.855 20.844 91.125 ;
     RECT  199.692 90.855 218.16 91.125 ;
     RECT  2.16 91.395 20.844 91.665 ;
     RECT  199.692 91.395 218.16 91.665 ;
     RECT  2.16 91.935 20.844 92.205 ;
     RECT  199.692 91.935 218.16 92.205 ;
     RECT  2.16 92.475 20.844 92.745 ;
     RECT  199.692 92.475 218.16 92.745 ;
     RECT  2.16 93.015 20.844 93.285 ;
     RECT  199.692 93.015 218.16 93.285 ;
     RECT  2.16 93.555 20.844 93.825 ;
     RECT  199.692 93.555 218.16 93.825 ;
     RECT  2.16 94.095 20.844 94.365 ;
     RECT  199.692 94.095 218.16 94.365 ;
     RECT  2.16 94.635 20.844 94.905 ;
     RECT  199.692 94.635 218.16 94.905 ;
     RECT  2.16 95.175 20.844 95.445 ;
     RECT  199.692 95.175 218.16 95.445 ;
     RECT  2.16 95.715 20.844 95.985 ;
     RECT  199.692 95.715 218.16 95.985 ;
     RECT  2.16 96.255 20.844 96.39 ;
     RECT  199.692 96.255 218.16 96.39 ;
     RECT  2.16 96.39 218.16 96.525 ;
     RECT  2.16 96.795 218.16 97.065 ;
     RECT  2.16 97.335 218.16 97.605 ;
     RECT  2.16 97.875 218.16 98.145 ;
     RECT  2.16 98.415 218.16 98.685 ;
     RECT  2.16 98.955 218.16 99.225 ;
     RECT  2.16 99.495 218.16 99.765 ;
     RECT  2.16 100.035 218.16 100.305 ;
     RECT  2.16 100.575 218.16 100.845 ;
     RECT  2.16 101.115 218.16 101.385 ;
     RECT  2.16 101.655 218.16 101.925 ;
     RECT  2.16 102.195 218.16 102.465 ;
     RECT  2.16 102.735 218.16 103.005 ;
     RECT  2.16 103.275 218.16 103.545 ;
     RECT  2.16 103.815 218.16 104.085 ;
     RECT  2.16 104.355 218.16 104.625 ;
     RECT  2.16 104.895 218.16 105.165 ;
     RECT  2.16 105.435 218.16 105.705 ;
     RECT  2.16 105.975 218.16 106.245 ;
     RECT  2.16 106.515 218.16 106.785 ;
     RECT  2.16 107.055 218.16 107.325 ;
     RECT  2.16 107.595 218.16 107.865 ;
     RECT  2.16 108.135 218.16 108.405 ;
     RECT  2.16 108.675 218.16 108.945 ;
     RECT  2.16 109.215 218.16 109.485 ;
     RECT  2.16 109.755 218.16 110.025 ;
     RECT  2.16 110.295 218.16 110.565 ;
     RECT  2.16 110.835 218.16 111.105 ;
     RECT  2.16 111.375 218.16 111.645 ;
     RECT  2.16 111.915 218.16 112.185 ;
     RECT  2.16 112.455 218.16 112.725 ;
     RECT  2.16 112.995 218.16 113.265 ;
     RECT  2.16 113.535 218.16 113.805 ;
     RECT  2.16 114.075 218.16 114.345 ;
    LAYER M1 ;
     RECT  2.16 2.151 218.16 21.609 ;
     RECT  22.896 23.76 197.64 94.248 ;
     RECT  2.16 21.609 20.844 96.381 ;
     RECT  199.692 21.609 218.16 96.381 ;
     RECT  2.16 96.381 218.16 114.489 ;
    LAYER M2 ;
     RECT  0.103 45.54 0.139 45.828 ;
     RECT  0.103 57.69 0.139 57.708 ;
     RECT  0.139 47.592 0.175 47.61 ;
     RECT  0.139 56.502 0.175 56.52 ;
     RECT  0.103 69.336 0.211 69.354 ;
     RECT  0.139 45.54 0.239 46.026 ;
     RECT  0.175 56.502 0.239 56.826 ;
     RECT  0.175 47.592 0.275 47.718 ;
     RECT  0.275 47.592 0.347 47.61 ;
     RECT  0.103 68.076 0.347 68.319 ;
     RECT  0.139 70.506 0.455 70.524 ;
     RECT  0.499 72 0.535 72.018 ;
     RECT  0.103 66.492 0.563 66.51 ;
     RECT  0.103 65.52 0.599 65.538 ;
     RECT  0.499 61.596 0.851 61.614 ;
     RECT  0.103 49.32 1.147 49.338 ;
     RECT  0.139 57.654 1.147 57.708 ;
     RECT  0.535 59.814 1.147 59.832 ;
     RECT  0.211 69.336 1.147 69.75 ;
     RECT  1.075 70.65 1.211 70.668 ;
     RECT  0.239 56.808 1.723 56.826 ;
     RECT  1.147 57.654 1.723 57.744 ;
     RECT  0.103 62.748 1.723 62.766 ;
     RECT  0.103 63.828 1.723 63.846 ;
     RECT  0.139 74.592 2.155 74.61 ;
     RECT  0.103 43.272 2.16 43.29 ;
     RECT  0.139 44.19 2.16 44.208 ;
     RECT  0.239 45.81 2.16 46.026 ;
     RECT  1.507 47.934 2.16 47.952 ;
     RECT  1.147 48.978 2.16 49.338 ;
     RECT  1.723 50.4 2.16 50.418 ;
     RECT  0.103 52.182 2.16 52.2 ;
     RECT  0.103 53.532 2.16 53.55 ;
     RECT  1.723 54.918 2.16 54.936 ;
     RECT  1.723 56.808 2.16 57.744 ;
     RECT  0.103 58.662 2.16 58.68 ;
     RECT  1.147 59.616 2.16 59.832 ;
     RECT  1.723 62.748 2.16 63.846 ;
     RECT  1.687 67.104 2.16 67.122 ;
     RECT  1.147 69.336 2.16 69.858 ;
     RECT  0.535 72 2.16 72.522 ;
     RECT  2.155 73.386 2.16 73.404 ;
     RECT  2.155 74.592 2.16 75.114 ;
     RECT  2.16 2.151 20.844 114.489 ;
     RECT  20.844 66.636 20.867 68.976 ;
     RECT  20.844 39.87 20.903 40.554 ;
     RECT  20.844 61.704 20.975 65.538 ;
     RECT  20.844 41.796 21.011 60.642 ;
     RECT  20.867 66.636 21.011 66.744 ;
     RECT  20.975 61.704 21.047 62.964 ;
     RECT  21.011 42.426 21.119 60.642 ;
     RECT  20.844 30.816 21.371 30.834 ;
     RECT  21.119 52.146 21.479 60.642 ;
     RECT  21.119 43.65 21.551 51.264 ;
     RECT  20.975 64.206 21.587 65.538 ;
     RECT  21.119 42.426 21.623 42.75 ;
     RECT  21.479 53.802 21.623 60.642 ;
     RECT  20.867 67.536 21.623 68.976 ;
     RECT  21.479 52.146 21.659 52.884 ;
     RECT  21.551 45.27 21.695 51.264 ;
     RECT  21.659 52.146 21.695 52.848 ;
     RECT  21.623 54.036 21.695 60.642 ;
     RECT  21.551 43.65 21.731 44.514 ;
     RECT  21.623 67.536 21.875 68.274 ;
     RECT  20.903 39.87 21.983 40.284 ;
     RECT  21.695 54.216 21.983 60.642 ;
     RECT  21.695 45.27 22.019 49.572 ;
     RECT  21.983 54.414 22.019 55.044 ;
     RECT  20.844 2.151 22.055 29.484 ;
     RECT  21.983 55.962 22.055 60.642 ;
     RECT  21.983 40.266 22.091 40.284 ;
     RECT  21.695 50.481 22.099 51.264 ;
     RECT  22.055 2.151 22.127 29.394 ;
     RECT  22.099 50.481 22.127 51.426 ;
     RECT  22.055 57.69 22.127 60.642 ;
     RECT  21.875 67.716 22.127 68.274 ;
     RECT  22.127 2.151 22.163 24.804 ;
     RECT  22.127 25.83 22.163 29.394 ;
     RECT  22.127 59.976 22.243 60.642 ;
     RECT  21.047 61.704 22.243 61.794 ;
     RECT  22.243 59.976 22.639 61.794 ;
     RECT  21.047 62.586 22.639 62.964 ;
     RECT  22.351 30.618 22.711 30.636 ;
     RECT  22.163 2.151 22.896 23.688 ;
     RECT  22.163 24.75 22.896 24.804 ;
     RECT  22.163 25.83 22.896 28.944 ;
     RECT  22.711 30.618 22.896 30.708 ;
     RECT  21.623 42.426 22.896 42.624 ;
     RECT  21.731 43.776 22.896 44.514 ;
     RECT  22.019 45.27 22.896 48.456 ;
     RECT  22.019 49.212 22.896 49.572 ;
     RECT  22.127 50.526 22.896 51.426 ;
     RECT  21.695 52.641 22.896 52.848 ;
     RECT  22.019 54.414 22.896 54.819 ;
     RECT  22.055 55.962 22.896 56.664 ;
     RECT  22.127 57.69 22.896 59.184 ;
     RECT  22.639 59.976 22.896 62.964 ;
     RECT  21.587 64.368 22.896 65.538 ;
     RECT  21.011 66.636 22.896 66.654 ;
     RECT  22.127 67.716 22.896 68.094 ;
     RECT  22.639 90.63 22.896 90.648 ;
     RECT  20.844 94.338 22.896 114.489 ;
     RECT  25.015 1.116 47.803 1.134 ;
     RECT  22.896 2.151 47.803 114.489 ;
     RECT  47.803 1.116 55.147 114.489 ;
     RECT  55.147 1.026 55.687 114.489 ;
     RECT  55.687 0.99 75.775 114.489 ;
     RECT  75.775 0.531 161.015 114.489 ;
     RECT  161.015 1.071 194.603 114.489 ;
     RECT  194.603 1.071 195.683 1.089 ;
     RECT  194.603 2.151 197.64 114.489 ;
     RECT  197.64 24.876 198.383 25.434 ;
     RECT  197.64 51.516 198.391 64.656 ;
     RECT  198.383 25.056 198.607 25.434 ;
     RECT  197.64 68.688 198.607 68.706 ;
     RECT  198.391 51.372 198.643 64.656 ;
     RECT  198.607 68.148 198.679 68.706 ;
     RECT  198.715 26.766 198.787 26.784 ;
     RECT  197.64 45.27 198.859 46.26 ;
     RECT  197.64 47.124 198.859 50.454 ;
     RECT  198.607 25.056 198.887 25.506 ;
     RECT  198.859 45.27 198.895 50.454 ;
     RECT  198.643 51.372 198.895 65.268 ;
     RECT  198.895 45.198 199.471 50.454 ;
     RECT  197.64 43.812 199.507 44.136 ;
     RECT  199.471 45.036 199.507 50.454 ;
     RECT  198.895 51.21 199.507 65.268 ;
     RECT  198.787 26.766 199.579 27.234 ;
     RECT  197.64 2.151 199.692 23.724 ;
     RECT  198.887 25.056 199.692 25.344 ;
     RECT  199.579 26.676 199.692 27.234 ;
     RECT  197.64 35.406 199.692 36.144 ;
     RECT  197.64 37.026 199.692 37.044 ;
     RECT  197.64 38.556 199.692 39.204 ;
     RECT  197.64 41.112 199.692 42.75 ;
     RECT  199.507 43.812 199.692 65.268 ;
     RECT  199.219 66.222 199.692 66.24 ;
     RECT  198.679 68.148 199.692 68.742 ;
     RECT  197.64 75.672 199.692 75.69 ;
     RECT  198.715 83.502 199.692 83.52 ;
     RECT  197.64 87.552 199.692 87.57 ;
     RECT  197.64 88.362 199.692 88.38 ;
     RECT  197.64 89.748 199.692 90 ;
     RECT  197.64 94.338 199.692 114.489 ;
     RECT  199.692 2.151 218.16 114.489 ;
     RECT  218.16 44.496 218.255 72.792 ;
     RECT  218.255 69.156 218.291 72.792 ;
     RECT  218.291 71.856 218.327 72.792 ;
     RECT  218.255 44.496 218.363 68.364 ;
     RECT  218.363 44.496 218.471 64.314 ;
     RECT  218.327 72.504 218.651 72.792 ;
     RECT  218.363 65.106 218.759 68.364 ;
     RECT  218.471 50.976 218.831 64.314 ;
     RECT  218.471 44.586 218.867 49.914 ;
     RECT  218.831 55.386 218.867 64.314 ;
     RECT  218.759 65.106 218.867 66.699 ;
     RECT  218.291 69.156 218.867 70.974 ;
     RECT  218.867 55.566 218.903 64.314 ;
     RECT  218.867 44.586 218.939 49.806 ;
     RECT  218.759 67.446 218.939 68.364 ;
     RECT  218.831 50.976 219.047 54.126 ;
     RECT  218.939 44.586 219.155 46.944 ;
     RECT  218.939 67.806 219.155 68.364 ;
     RECT  218.903 58.356 219.191 64.314 ;
     RECT  218.867 69.966 219.227 70.974 ;
     RECT  218.939 47.7 219.299 49.806 ;
     RECT  219.299 47.7 219.371 49.374 ;
     RECT  218.867 65.106 219.407 66.474 ;
     RECT  219.371 47.7 219.443 48.834 ;
     RECT  219.047 52.056 219.443 54.126 ;
     RECT  218.903 55.566 219.443 57.564 ;
     RECT  219.191 58.356 219.443 64.224 ;
     RECT  219.407 65.214 219.443 66.474 ;
     RECT  219.443 48.168 219.479 48.834 ;
     RECT  219.443 52.056 219.479 53.01 ;
     RECT  219.443 53.766 219.479 54.126 ;
     RECT  219.443 62.514 219.479 64.116 ;
     RECT  219.047 50.976 219.515 50.994 ;
     RECT  219.479 54.036 219.515 54.126 ;
     RECT  219.155 67.914 219.803 68.364 ;
     RECT  219.443 65.826 219.811 66.474 ;
     RECT  219.515 54.108 219.919 54.126 ;
     RECT  219.803 67.914 219.947 68.274 ;
     RECT  219.479 48.402 220.019 48.834 ;
     RECT  219.811 65.826 220.019 66.654 ;
     RECT  219.947 67.914 220.019 67.932 ;
     RECT  220.019 66.024 220.027 66.654 ;
     RECT  220.019 48.402 220.091 48.42 ;
     RECT  219.479 52.218 220.091 53.01 ;
     RECT  219.227 69.966 220.091 70.866 ;
     RECT  219.155 44.586 220.127 45.954 ;
     RECT  220.127 44.586 220.163 44.946 ;
     RECT  219.919 54.108 220.163 54.396 ;
     RECT  220.027 66.024 220.163 66.816 ;
     RECT  220.091 69.966 220.163 70.83 ;
     RECT  220.027 46.746 220.171 46.764 ;
     RECT  220.127 45.81 220.199 45.954 ;
     RECT  220.171 46.746 220.199 46.836 ;
     RECT  219.443 58.896 220.199 61.254 ;
     RECT  220.163 69.966 220.199 70.704 ;
     RECT  220.135 49.554 220.207 49.572 ;
     RECT  219.443 56.916 220.207 57.024 ;
     RECT  220.163 44.73 220.235 44.946 ;
     RECT  220.207 49.554 220.235 49.959 ;
     RECT  220.091 52.218 220.235 52.974 ;
     RECT  219.443 55.566 220.235 56.088 ;
     RECT  220.207 56.916 220.235 57.636 ;
     RECT  220.199 59.436 220.235 59.454 ;
     RECT  220.199 60.552 220.235 60.57 ;
     RECT  219.479 62.514 220.235 62.532 ;
     RECT  219.479 63.666 220.235 63.684 ;
     RECT  218.867 69.156 220.235 69.174 ;
     RECT  220.199 45.81 220.271 45.828 ;
     RECT  220.199 46.818 220.271 46.836 ;
     RECT  220.163 66.024 220.271 66.744 ;
     RECT  220.199 70.686 220.271 70.704 ;
     RECT  220.235 44.928 220.307 44.946 ;
     RECT  220.235 49.941 220.307 49.959 ;
     RECT  220.163 54.108 220.307 54.126 ;
     RECT  220.235 57.618 220.307 57.636 ;
     RECT  220.271 66.024 220.307 66.042 ;
     RECT  218.651 72.504 220.307 72.522 ;
    LAYER M3 ;
     RECT  110.628 0.043 110.646 0.091 ;
     RECT  110.052 0.091 110.646 0.173 ;
     RECT  106.668 0.091 106.686 0.523 ;
     RECT  110.052 0.173 110.394 0.523 ;
     RECT  106.668 0.523 107.046 0.571 ;
     RECT  55.692 0.985 55.71 1.021 ;
     RECT  136.584 0.985 136.602 1.021 ;
     RECT  106.668 0.571 107.19 1.066 ;
     RECT  108.288 0.619 108.306 1.147 ;
     RECT  109.548 0.523 110.394 1.147 ;
     RECT  106.668 1.066 107.37 1.195 ;
     RECT  108.288 1.147 110.394 1.195 ;
     RECT  114.012 1.147 114.03 1.195 ;
     RECT  114.012 1.195 114.102 1.243 ;
     RECT  106.668 1.195 110.394 1.531 ;
     RECT  116.172 0.091 116.19 1.579 ;
     RECT  194.004 1.606 194.022 1.687 ;
     RECT  114.012 1.243 114.498 1.723 ;
     RECT  113.292 1.723 114.498 1.771 ;
     RECT  115.38 0.043 115.398 1.831 ;
     RECT  116.172 1.579 116.298 1.831 ;
     RECT  115.38 1.831 116.298 1.876 ;
     RECT  113.22 1.771 114.498 1.921 ;
     RECT  115.272 1.876 116.298 1.921 ;
     RECT  106.668 1.531 110.754 1.993 ;
     RECT  111.888 1.876 111.906 1.993 ;
     RECT  194.004 1.687 194.598 2.029 ;
     RECT  102.744 2.029 102.762 2.101 ;
     RECT  55.152 1.021 55.71 2.143 ;
     RECT  136.584 1.021 137.322 2.143 ;
     RECT  24.015 2.143 24.105 2.191 ;
     RECT  23.904 2.191 24.21 2.237 ;
     RECT  32.688 2.191 33.03 2.237 ;
     RECT  125.424 1.111 125.442 2.251 ;
     RECT  106.668 1.993 111.906 2.263 ;
     RECT  112.68 1.921 116.298 2.263 ;
     RECT  120.024 1.627 120.042 2.263 ;
     RECT  2.415 2.143 2.505 2.413 ;
     RECT  7.815 2.143 7.905 2.413 ;
     RECT  13.215 2.143 13.305 2.413 ;
     RECT  18.615 2.143 18.705 2.413 ;
     RECT  24.015 2.237 24.21 2.413 ;
     RECT  29.415 2.143 29.505 2.413 ;
     RECT  34.815 2.143 34.905 2.413 ;
     RECT  40.215 2.143 40.305 2.413 ;
     RECT  45.615 2.143 45.705 2.413 ;
     RECT  51.015 2.143 51.105 2.413 ;
     RECT  55.152 2.143 56.505 2.413 ;
     RECT  61.815 2.143 61.905 2.413 ;
     RECT  67.215 2.143 67.305 2.413 ;
     RECT  72.615 2.143 72.705 2.413 ;
     RECT  78.015 2.143 78.105 2.413 ;
     RECT  83.415 2.143 83.505 2.413 ;
     RECT  88.815 2.143 88.905 2.413 ;
     RECT  94.215 2.143 94.305 2.413 ;
     RECT  99.615 2.143 99.705 2.413 ;
     RECT  105.015 2.143 105.105 2.413 ;
     RECT  121.215 2.143 121.305 2.413 ;
     RECT  126.615 2.143 126.705 2.413 ;
     RECT  132.015 2.143 132.105 2.413 ;
     RECT  136.584 2.143 137.505 2.413 ;
     RECT  142.815 2.143 142.905 2.413 ;
     RECT  148.215 2.143 148.305 2.413 ;
     RECT  153.615 2.143 153.705 2.413 ;
     RECT  159.015 2.143 159.105 2.413 ;
     RECT  164.415 2.143 164.505 2.413 ;
     RECT  169.815 2.143 169.905 2.413 ;
     RECT  175.215 2.143 175.305 2.413 ;
     RECT  180.615 2.143 180.705 2.413 ;
     RECT  186.015 2.143 186.105 2.413 ;
     RECT  191.415 2.143 191.505 2.413 ;
     RECT  196.815 2.143 196.905 2.413 ;
     RECT  202.215 2.143 202.305 2.413 ;
     RECT  207.615 2.143 207.705 2.413 ;
     RECT  213.015 2.143 213.105 2.413 ;
     RECT  106.56 2.263 116.298 2.497 ;
     RECT  105.015 2.413 105.297 2.569 ;
     RECT  136.584 2.413 137.697 2.605 ;
     RECT  102.672 2.101 102.762 2.641 ;
     RECT  193.932 2.029 194.598 2.641 ;
     RECT  192.6 1.651 192.618 2.731 ;
     RECT  193.716 2.641 194.598 2.731 ;
     RECT  20.592 2.731 20.61 2.803 ;
     RECT  142.815 2.413 143.097 2.803 ;
     RECT  96.444 1.687 96.462 2.827 ;
     RECT  20.268 2.803 20.61 2.861 ;
     RECT  106.344 2.497 116.298 2.875 ;
     RECT  47.808 1.561 47.826 3.145 ;
     RECT  117.036 2.875 117.054 3.145 ;
     RECT  125.244 2.251 125.442 3.145 ;
     RECT  104.904 2.569 105.297 3.181 ;
     RECT  123.3 2.731 123.318 3.181 ;
     RECT  106.128 2.875 116.298 3.271 ;
     RECT  117.036 3.145 117.09 3.271 ;
     RECT  196.815 2.413 197.097 3.271 ;
     RECT  122.544 3.181 123.318 3.335 ;
     RECT  18.615 2.413 18.897 3.343 ;
     RECT  102.6 2.641 102.762 3.371 ;
     RECT  117.864 1.675 117.882 3.379 ;
     RECT  118.836 2.263 118.854 3.379 ;
     RECT  125.244 3.145 125.802 3.379 ;
     RECT  196.815 3.271 197.514 3.379 ;
     RECT  106.128 3.271 117.09 3.415 ;
     RECT  18.576 3.343 18.897 3.451 ;
     RECT  117.864 3.379 118.854 3.451 ;
     RECT  120.024 2.263 120.294 3.451 ;
     RECT  106.092 3.415 117.09 3.613 ;
     RECT  104.724 3.181 105.297 3.649 ;
     RECT  106.02 3.613 117.09 3.649 ;
     RECT  104.724 3.649 117.09 3.721 ;
     RECT  192.6 2.731 194.598 3.721 ;
     RECT  195.66 1.066 195.678 3.721 ;
     RECT  192.6 3.721 195.678 3.811 ;
     RECT  196.815 3.379 197.586 3.811 ;
     RECT  41.544 3.883 41.562 3.92 ;
     RECT  104.652 3.721 117.09 3.931 ;
     RECT  117.864 3.451 120.294 3.931 ;
     RECT  104.652 3.931 120.294 3.955 ;
     RECT  121.215 2.413 121.497 3.955 ;
     RECT  61.815 2.413 62.097 3.991 ;
     RECT  55.152 2.413 56.697 4.261 ;
     RECT  57.42 3.883 57.438 4.261 ;
     RECT  24.015 2.413 24.297 4.351 ;
     RECT  34.815 2.413 35.097 4.351 ;
     RECT  129.312 1.561 129.33 4.351 ;
     RECT  138.42 3.991 138.438 4.387 ;
     RECT  190.404 4.261 190.422 4.387 ;
     RECT  190.404 4.387 190.53 4.388 ;
     RECT  138.42 4.387 138.654 4.415 ;
     RECT  199.836 2.263 199.854 4.423 ;
     RECT  37.332 4.411 37.35 4.451 ;
     RECT  192.6 3.811 197.586 4.459 ;
     RECT  190.44 4.388 190.53 4.487 ;
     RECT  138.564 4.415 138.654 4.507 ;
     RECT  37.692 4.459 37.71 4.559 ;
     RECT  138.564 4.507 138.726 4.559 ;
     RECT  192.6 4.459 197.73 4.559 ;
     RECT  198.828 4.459 198.846 4.621 ;
     RECT  122.688 3.335 123.318 4.649 ;
     RECT  52.02 3.181 52.038 4.765 ;
     RECT  94.215 2.413 94.497 4.801 ;
     RECT  102.744 3.371 102.762 4.801 ;
     RECT  191.415 2.413 191.697 4.801 ;
     RECT  102.6 4.801 102.762 4.919 ;
     RECT  104.652 3.955 121.497 4.919 ;
     RECT  34.704 4.351 35.097 4.925 ;
     RECT  144.756 2.065 144.774 4.927 ;
     RECT  23.904 4.351 24.297 4.928 ;
     RECT  104.652 4.919 120.474 4.955 ;
     RECT  129.312 4.351 129.582 4.963 ;
     RECT  199.836 4.423 200.106 4.963 ;
     RECT  190.44 4.487 190.458 5.027 ;
     RECT  34.815 4.925 35.097 5.071 ;
     RECT  72.615 2.413 72.897 5.071 ;
     RECT  157.896 4.657 157.914 5.071 ;
     RECT  34.815 5.071 35.73 5.117 ;
     RECT  148.215 2.413 148.497 5.161 ;
     RECT  200.952 4.891 200.97 5.161 ;
     RECT  104.652 4.955 120.294 5.189 ;
     RECT  144.216 4.927 144.774 5.189 ;
     RECT  192.6 4.559 197.658 5.189 ;
     RECT  104.652 5.189 120.186 5.225 ;
     RECT  72.615 5.071 72.99 5.269 ;
     RECT  103.788 1.651 103.806 5.305 ;
     RECT  104.652 5.225 119.394 5.305 ;
     RECT  133.524 4.261 133.542 5.341 ;
     RECT  43.812 3.271 43.83 5.431 ;
     RECT  196.344 5.189 197.658 5.431 ;
     RECT  198.792 4.621 198.846 5.431 ;
     RECT  52.02 4.765 52.47 5.459 ;
     RECT  139.104 4.621 139.122 5.467 ;
     RECT  157.86 5.071 157.914 5.531 ;
     RECT  96.084 2.827 96.462 5.539 ;
     RECT  126.615 2.413 126.897 5.539 ;
     RECT  129.312 4.963 129.978 5.539 ;
     RECT  133.092 5.341 133.542 5.539 ;
     RECT  138.78 5.467 139.122 5.567 ;
     RECT  55.152 4.261 57.438 5.611 ;
     RECT  144.756 5.189 144.774 5.611 ;
     RECT  126.54 5.539 126.897 5.639 ;
     RECT  144.756 5.611 145.386 5.729 ;
     RECT  103.788 5.305 119.394 5.737 ;
     RECT  148.215 5.161 148.806 5.737 ;
     RECT  102.744 4.919 102.762 5.773 ;
     RECT  72.615 5.269 73.566 5.809 ;
     RECT  43.272 5.431 43.83 5.845 ;
     RECT  43.272 5.845 44.19 5.881 ;
     RECT  122.688 4.649 123.246 5.881 ;
     RECT  132.015 2.413 132.297 5.881 ;
     RECT  19.8 5.563 19.818 6.007 ;
     RECT  122.436 5.881 123.246 6.035 ;
     RECT  129.312 5.539 130.05 6.043 ;
     RECT  157.86 5.531 157.878 6.043 ;
     RECT  94.215 4.801 94.662 6.071 ;
     RECT  54.828 5.611 57.438 6.079 ;
     RECT  196.344 5.431 198.846 6.079 ;
     RECT  199.836 4.963 200.142 6.079 ;
     RECT  72.615 5.809 74.142 6.107 ;
     RECT  54.828 6.079 57.474 6.115 ;
     RECT  102.6 5.773 102.762 6.115 ;
     RECT  103.716 5.737 119.394 6.115 ;
     RECT  120.168 5.225 120.186 6.115 ;
     RECT  121.215 4.919 121.497 6.115 ;
     RECT  98.604 6.043 98.622 6.143 ;
     RECT  129.312 6.043 130.122 6.151 ;
     RECT  190.404 6.007 190.422 6.151 ;
     RECT  200.952 5.161 201.006 6.151 ;
     RECT  99.615 2.413 99.897 6.241 ;
     RECT  102.6 6.115 119.394 6.241 ;
     RECT  136.116 2.605 137.697 6.277 ;
     RECT  192.6 5.189 195.138 6.349 ;
     RECT  99.615 6.241 100.458 6.376 ;
     RECT  74.124 6.107 74.142 6.385 ;
     RECT  99.615 6.376 100.962 6.413 ;
     RECT  51.015 2.413 51.297 6.421 ;
     RECT  24.015 4.928 24.297 6.511 ;
     RECT  34.815 5.117 35.097 6.511 ;
     RECT  102.096 6.241 119.394 6.539 ;
     RECT  45.615 2.413 45.897 6.547 ;
     RECT  46.62 4.729 46.638 6.547 ;
     RECT  160.992 0.526 161.01 6.547 ;
     RECT  190.404 6.151 190.458 6.547 ;
     RECT  196.344 6.079 200.142 6.547 ;
     RECT  200.952 6.151 201.402 6.547 ;
     RECT  23.904 6.511 24.297 6.557 ;
     RECT  34.704 6.511 35.097 6.557 ;
     RECT  19.8 6.007 19.962 6.575 ;
     RECT  74.124 6.385 74.79 6.575 ;
     RECT  102.096 6.539 102.762 6.575 ;
     RECT  133.092 5.539 134.01 6.575 ;
     RECT  138.78 5.567 138.798 6.583 ;
     RECT  103.644 6.539 119.394 6.611 ;
     RECT  40.215 2.413 40.497 6.619 ;
     RECT  98.676 6.385 98.694 6.647 ;
     RECT  190.404 6.547 190.494 6.647 ;
     RECT  38.772 6.523 38.79 6.653 ;
     RECT  192.6 6.349 195.21 6.655 ;
     RECT  40.215 6.619 41.058 6.656 ;
     RECT  151.812 6.313 151.83 6.691 ;
     RECT  160.2 6.385 160.218 6.691 ;
     RECT  160.992 6.547 161.262 6.691 ;
     RECT  191.415 4.801 191.79 6.691 ;
     RECT  192.6 6.655 195.354 6.691 ;
     RECT  191.415 6.691 195.354 6.763 ;
     RECT  122.796 6.035 123.246 6.809 ;
     RECT  133.344 6.575 134.01 6.809 ;
     RECT  151.56 6.691 151.83 6.809 ;
     RECT  160.2 6.691 161.262 6.809 ;
     RECT  42.084 6.691 42.102 6.845 ;
     RECT  43.272 5.881 44.478 6.845 ;
     RECT  74.7 6.575 74.79 6.845 ;
     RECT  102.204 6.575 102.762 6.845 ;
     RECT  122.796 6.809 122.994 6.845 ;
     RECT  151.56 6.809 151.578 6.845 ;
     RECT  160.2 6.809 160.218 6.845 ;
     RECT  160.992 6.809 161.082 6.845 ;
     RECT  70.704 6.691 70.722 6.853 ;
     RECT  120.168 6.115 121.497 6.853 ;
     RECT  122.796 6.845 122.814 6.853 ;
     RECT  157.32 6.043 157.878 6.853 ;
     RECT  159.015 2.413 159.297 6.853 ;
     RECT  157.32 6.853 159.297 6.953 ;
     RECT  161.064 6.845 161.082 6.953 ;
     RECT  45.615 6.547 46.638 6.961 ;
     RECT  47.808 3.145 48.042 6.961 ;
     RECT  135.936 6.277 137.697 7.051 ;
     RECT  191.415 6.763 195.462 7.051 ;
     RECT  191.415 7.051 195.498 7.087 ;
     RECT  127.944 2.641 127.962 7.123 ;
     RECT  15.66 6.043 15.678 7.159 ;
     RECT  191.415 7.087 195.57 7.229 ;
     RECT  141.588 4.423 141.606 7.231 ;
     RECT  144.756 5.729 144.774 7.231 ;
     RECT  145.656 6.043 145.674 7.231 ;
     RECT  21.384 5.539 21.402 7.321 ;
     RECT  95.832 5.539 96.462 7.321 ;
     RECT  102.24 6.845 102.762 7.321 ;
     RECT  143.892 6.079 143.91 7.321 ;
     RECT  144.756 7.231 145.674 7.321 ;
     RECT  102.24 7.321 102.978 7.339 ;
     RECT  103.824 6.611 119.394 7.339 ;
     RECT  120.168 6.853 122.814 7.349 ;
     RECT  146.448 7.231 146.466 7.349 ;
     RECT  99.615 6.413 100.458 7.357 ;
     RECT  129.312 6.151 130.266 7.385 ;
     RECT  141.588 7.231 142.002 7.429 ;
     RECT  98.604 7.429 98.622 7.465 ;
     RECT  148.215 5.737 148.842 7.465 ;
     RECT  19.8 6.575 19.818 7.483 ;
     RECT  24.015 6.557 24.297 7.483 ;
     RECT  34.815 6.557 35.097 7.483 ;
     RECT  45.615 6.961 48.042 7.483 ;
     RECT  67.215 2.413 67.497 7.483 ;
     RECT  78.015 2.413 78.297 7.483 ;
     RECT  88.815 2.413 89.097 7.483 ;
     RECT  99.615 7.357 100.71 7.501 ;
     RECT  23.904 7.483 24.297 7.529 ;
     RECT  34.704 7.483 35.097 7.529 ;
     RECT  45.504 7.483 48.042 7.529 ;
     RECT  67.104 7.483 67.497 7.529 ;
     RECT  77.904 7.483 78.297 7.529 ;
     RECT  88.704 7.483 89.097 7.529 ;
     RECT  161.892 7.123 161.91 7.529 ;
     RECT  98.604 7.465 98.694 7.619 ;
     RECT  127.656 7.123 127.962 7.619 ;
     RECT  99.615 7.501 101.25 7.627 ;
     RECT  102.24 7.339 119.394 7.627 ;
     RECT  142.776 2.803 143.097 7.627 ;
     RECT  143.892 7.321 145.674 7.627 ;
     RECT  98.64 7.619 98.694 7.661 ;
     RECT  61.416 3.991 62.097 7.675 ;
     RECT  70.38 6.853 70.722 7.691 ;
     RECT  140.364 3.883 140.382 7.699 ;
     RECT  149.904 6.619 149.922 7.727 ;
     RECT  98.676 7.661 98.694 7.763 ;
     RECT  157.32 6.953 157.878 7.763 ;
     RECT  127.656 7.619 127.71 7.799 ;
     RECT  191.415 7.229 195.498 7.799 ;
     RECT  121.215 7.349 122.814 7.889 ;
     RECT  148.14 7.465 148.842 7.889 ;
     RECT  190.404 6.647 190.422 7.889 ;
     RECT  141.336 7.429 142.002 7.925 ;
     RECT  148.14 7.889 148.554 7.925 ;
     RECT  157.536 7.763 157.878 7.925 ;
     RECT  17.1 6.547 17.118 7.933 ;
     RECT  135.216 7.051 137.697 7.933 ;
     RECT  59.688 2.803 59.706 8.005 ;
     RECT  142.776 7.627 145.674 8.041 ;
     RECT  99.615 7.627 119.394 8.069 ;
     RECT  98.784 7.963 98.802 8.155 ;
     RECT  99.615 8.069 118.962 8.155 ;
     RECT  142.128 8.041 145.674 8.159 ;
     RECT  138.78 6.583 138.906 8.167 ;
     RECT  123.408 8.041 123.426 8.195 ;
     RECT  124.704 3.379 125.802 8.239 ;
     RECT  126.615 5.639 126.897 8.239 ;
     RECT  54 2.605 54.018 8.311 ;
     RECT  54.828 6.115 58.086 8.311 ;
     RECT  98.784 8.155 118.962 8.339 ;
     RECT  121.215 7.889 122.562 8.429 ;
     RECT  143.892 8.159 145.674 8.429 ;
     RECT  190.44 8.239 190.494 8.429 ;
     RECT  94.215 6.071 94.497 8.437 ;
     RECT  143.892 8.429 145.422 8.465 ;
     RECT  155.988 7.969 156.006 8.465 ;
     RECT  15.048 7.159 15.678 8.473 ;
     RECT  35.928 8.437 35.946 8.477 ;
     RECT  37.116 8.437 37.134 8.477 ;
     RECT  98.784 8.339 118.89 8.477 ;
     RECT  94.068 8.437 94.59 8.491 ;
     RECT  13.215 2.413 13.497 8.509 ;
     RECT  98.784 8.477 103.194 8.537 ;
     RECT  103.968 8.477 118.89 8.537 ;
     RECT  190.44 8.429 190.458 8.537 ;
     RECT  19.8 7.483 20.214 8.545 ;
     RECT  21.384 7.321 21.474 8.671 ;
     RECT  157.788 7.925 157.878 8.671 ;
     RECT  157.788 8.671 158.13 8.699 ;
     RECT  153.615 2.413 153.897 8.707 ;
     RECT  157.86 8.699 158.13 8.707 ;
     RECT  192.6 7.799 195.498 8.707 ;
     RECT  196.344 6.547 201.402 8.707 ;
     RECT  157.86 8.707 158.202 8.735 ;
     RECT  98.604 8.545 98.622 8.771 ;
     RECT  158.112 8.735 158.202 8.771 ;
     RECT  143.892 8.465 145.062 8.807 ;
     RECT  59.58 8.005 59.706 8.851 ;
     RECT  143.892 8.807 144.234 8.879 ;
     RECT  153.615 8.707 154.566 8.879 ;
     RECT  158.184 8.771 158.202 8.879 ;
     RECT  131.868 5.881 132.297 8.941 ;
     RECT  138.636 8.167 138.906 8.969 ;
     RECT  141.336 7.925 141.354 8.969 ;
     RECT  70.38 7.691 70.398 8.977 ;
     RECT  138.636 8.969 138.762 9.005 ;
     RECT  160.74 8.239 160.758 9.013 ;
     RECT  18.288 3.451 18.897 9.049 ;
     RECT  124.704 8.239 126.897 9.067 ;
     RECT  131.652 8.941 132.297 9.077 ;
     RECT  138.564 9.013 138.582 9.113 ;
     RECT  140.364 7.699 140.526 9.121 ;
     RECT  159.015 6.953 159.297 9.121 ;
     RECT  99.54 8.537 103.194 9.211 ;
     RECT  103.968 8.537 118.854 9.211 ;
     RECT  158.472 9.121 159.297 9.239 ;
     RECT  161.604 9.121 161.622 9.239 ;
     RECT  160.02 9.013 160.758 9.247 ;
     RECT  133.344 6.809 133.794 9.283 ;
     RECT  75.78 0.526 75.798 9.307 ;
     RECT  160.02 9.247 161.298 9.341 ;
     RECT  71.82 7.465 71.838 9.383 ;
     RECT  160.02 9.341 160.758 9.383 ;
     RECT  19.8 8.545 20.25 9.391 ;
     RECT  67.176 7.529 67.497 9.391 ;
     RECT  99.54 9.211 118.854 9.391 ;
     RECT  148.215 7.925 148.497 9.391 ;
     RECT  78.015 7.529 78.297 9.481 ;
     RECT  99.54 9.391 119.178 9.509 ;
     RECT  127.656 7.799 127.674 9.509 ;
     RECT  131.868 9.077 132.297 9.509 ;
     RECT  140.256 9.121 140.526 9.509 ;
     RECT  166.716 9.391 166.734 9.509 ;
     RECT  14.544 8.473 15.678 9.517 ;
     RECT  16.488 7.933 17.118 9.517 ;
     RECT  75.744 9.307 75.798 9.517 ;
     RECT  124.452 9.067 126.897 9.545 ;
     RECT  140.256 9.509 140.274 9.545 ;
     RECT  61.308 7.675 62.097 9.553 ;
     RECT  63.036 9.355 63.054 9.553 ;
     RECT  69.228 9.085 69.246 9.553 ;
     RECT  70.38 8.977 70.794 9.553 ;
     RECT  24.015 7.529 24.297 9.625 ;
     RECT  34.815 7.529 35.097 9.625 ;
     RECT  45.615 7.529 48.042 9.625 ;
     RECT  166.464 9.517 166.482 9.629 ;
     RECT  88.815 7.529 89.097 9.643 ;
     RECT  99.54 9.509 100.638 9.643 ;
     RECT  61.308 9.553 63.054 9.653 ;
     RECT  101.484 9.509 119.178 9.653 ;
     RECT  148.215 9.391 148.842 9.661 ;
     RECT  23.904 9.625 24.297 9.677 ;
     RECT  34.704 9.625 35.097 9.677 ;
     RECT  45.504 9.625 48.042 9.677 ;
     RECT  88.704 9.643 89.097 9.689 ;
     RECT  99.288 9.643 100.638 9.689 ;
     RECT  101.484 9.653 119.106 9.779 ;
     RECT  133.344 9.283 134.226 9.787 ;
     RECT  135.072 7.933 137.697 9.787 ;
     RECT  191.415 7.799 191.826 9.787 ;
     RECT  150.552 9.049 150.57 9.815 ;
     RECT  191.268 9.787 191.826 9.859 ;
     RECT  64.764 2.065 64.782 9.895 ;
     RECT  99.288 9.689 99.897 9.895 ;
     RECT  129.78 7.385 130.266 9.895 ;
     RECT  133.344 9.787 137.697 9.895 ;
     RECT  50.4 6.421 51.297 9.931 ;
     RECT  52.02 5.459 52.038 9.931 ;
     RECT  129.78 9.895 130.554 9.931 ;
     RECT  163.332 9.859 163.35 9.931 ;
     RECT  148.176 9.661 148.842 9.959 ;
     RECT  163.332 9.931 163.458 9.959 ;
     RECT  101.484 9.779 101.502 9.965 ;
     RECT  124.452 9.545 124.722 10.049 ;
     RECT  133.056 9.895 137.697 10.049 ;
     RECT  148.176 9.959 148.806 10.049 ;
     RECT  162.468 9.121 162.486 10.049 ;
     RECT  163.44 9.959 163.458 10.049 ;
     RECT  146.484 9.931 146.502 10.057 ;
     RECT  98.604 9.895 99.897 10.075 ;
     RECT  190.44 9.895 190.458 10.084 ;
     RECT  95.832 7.321 96.966 10.085 ;
     RECT  124.452 10.049 124.47 10.085 ;
     RECT  129.78 9.931 130.626 10.085 ;
     RECT  134.208 10.049 137.697 10.085 ;
     RECT  148.176 10.049 148.554 10.085 ;
     RECT  146.484 10.057 146.574 10.093 ;
     RECT  102.348 9.779 119.106 10.109 ;
     RECT  115.308 10.109 119.106 10.121 ;
     RECT  49.428 9.625 49.446 10.123 ;
     RECT  21.384 8.671 21.906 10.129 ;
     RECT  74.7 6.845 74.718 10.129 ;
     RECT  190.404 10.084 190.458 10.129 ;
     RECT  191.196 9.859 191.826 10.129 ;
     RECT  192.6 8.707 201.402 10.129 ;
     RECT  98.316 10.075 99.897 10.157 ;
     RECT  134.208 10.085 135.702 10.157 ;
     RECT  150.588 10.057 151.002 10.165 ;
     RECT  74.7 10.129 74.898 10.171 ;
     RECT  146.484 10.093 146.646 10.193 ;
     RECT  66.816 9.391 67.497 10.201 ;
     RECT  143.892 8.879 143.91 10.201 ;
     RECT  145.044 8.807 145.062 10.201 ;
     RECT  150.588 10.165 151.182 10.205 ;
     RECT  102.348 10.109 114.57 10.229 ;
     RECT  136.476 10.085 137.697 10.229 ;
     RECT  153.615 8.879 153.897 10.291 ;
     RECT  159.015 9.239 159.297 10.291 ;
     RECT  150.84 10.205 151.182 10.327 ;
     RECT  152.928 10.291 153.897 10.327 ;
     RECT  162 10.291 162.018 10.327 ;
     RECT  102.348 10.229 114.426 10.355 ;
     RECT  43.272 6.845 44.262 10.363 ;
     RECT  168.408 10.327 168.426 10.363 ;
     RECT  189.828 10.129 201.402 10.391 ;
     RECT  90.144 7.933 90.162 10.399 ;
     RECT  152.748 10.327 153.897 10.427 ;
     RECT  158.508 10.291 159.858 10.463 ;
     RECT  69.228 9.553 70.794 10.471 ;
     RECT  139.572 10.399 139.59 10.471 ;
     RECT  92.916 7.969 92.934 10.499 ;
     RECT  139.5 10.471 139.59 10.499 ;
     RECT  152.748 10.427 152.766 10.499 ;
     RECT  161.928 10.327 162.018 10.499 ;
     RECT  168.408 10.363 168.786 10.499 ;
     RECT  77.292 9.481 78.297 10.561 ;
     RECT  132.015 9.509 132.297 10.561 ;
     RECT  166.572 10.471 166.59 10.561 ;
     RECT  168.516 10.499 168.786 10.561 ;
     RECT  206.604 8.545 206.622 10.561 ;
     RECT  207.615 2.413 207.897 10.561 ;
     RECT  166.5 10.561 166.59 10.589 ;
     RECT  168.516 10.561 168.858 10.589 ;
     RECT  14.544 9.517 17.118 10.597 ;
     RECT  18.288 9.049 18.99 10.597 ;
     RECT  69.228 10.471 71.19 10.597 ;
     RECT  90.144 10.399 90.414 10.597 ;
     RECT  121.215 8.429 122.166 10.597 ;
     RECT  21.348 10.129 21.906 10.651 ;
     RECT  74.376 10.171 74.898 10.669 ;
     RECT  121.215 10.597 122.31 10.669 ;
     RECT  121.215 10.669 122.994 10.685 ;
     RECT  86.652 10.597 86.67 10.697 ;
     RECT  90.144 10.597 90.486 10.697 ;
     RECT  140.364 10.459 140.382 10.697 ;
     RECT  58.932 8.851 59.706 10.699 ;
     RECT  73.944 10.669 74.898 10.705 ;
     RECT  75.744 9.517 76.086 10.705 ;
     RECT  161.928 10.499 161.946 10.733 ;
     RECT  166.5 10.589 166.518 10.733 ;
     RECT  168.84 10.589 168.858 10.733 ;
     RECT  150.84 10.327 151.686 10.769 ;
     RECT  102.348 10.355 114.39 10.829 ;
     RECT  64.116 9.895 64.782 10.831 ;
     RECT  102.348 10.829 109.458 10.859 ;
     RECT  148.176 10.085 148.497 10.859 ;
     RECT  189.252 10.399 189.522 10.867 ;
     RECT  110.304 10.829 114.39 10.895 ;
     RECT  115.668 10.121 119.106 10.895 ;
     RECT  98.316 10.157 98.334 10.939 ;
     RECT  99.288 10.157 99.897 10.939 ;
     RECT  43.272 10.363 44.478 10.975 ;
     RECT  131.544 10.561 132.297 10.975 ;
     RECT  133.056 10.049 133.362 10.975 ;
     RECT  158.508 10.463 159.297 10.975 ;
     RECT  163.116 10.867 163.134 10.975 ;
     RECT  110.415 10.895 114.39 11.003 ;
     RECT  63.036 9.653 63.054 11.011 ;
     RECT  64.116 10.831 64.854 11.011 ;
     RECT  69.228 10.597 71.478 11.011 ;
     RECT  129.78 10.085 130.554 11.011 ;
     RECT  131.544 10.975 133.362 11.011 ;
     RECT  134.208 10.157 135.234 11.011 ;
     RECT  146.484 10.939 146.502 11.011 ;
     RECT  148.215 10.859 148.497 11.011 ;
     RECT  149.256 10.939 149.274 11.011 ;
     RECT  169.815 2.413 170.097 11.011 ;
     RECT  148.215 11.011 149.274 11.039 ;
     RECT  163.044 10.975 163.134 11.039 ;
     RECT  166.428 10.903 166.446 11.039 ;
     RECT  190.404 10.391 201.402 11.039 ;
     RECT  102.348 10.859 109.386 11.101 ;
     RECT  146.484 11.011 146.574 11.101 ;
     RECT  110.415 11.003 114.318 11.129 ;
     RECT  129.636 11.011 130.626 11.129 ;
     RECT  136.62 10.229 137.697 11.129 ;
     RECT  145.944 11.101 146.574 11.129 ;
     RECT  148.215 11.039 149.202 11.129 ;
     RECT  173.7 11.011 174.438 11.129 ;
     RECT  43.272 10.975 44.694 11.137 ;
     RECT  169.815 11.011 170.514 11.137 ;
     RECT  174.42 11.129 174.438 11.137 ;
     RECT  175.215 2.413 175.497 11.137 ;
     RECT  160.74 9.383 160.758 11.165 ;
     RECT  19.764 9.391 20.25 11.173 ;
     RECT  21.348 10.651 22.266 11.173 ;
     RECT  58.932 10.699 60.138 11.173 ;
     RECT  174.42 11.137 175.497 11.201 ;
     RECT  61.308 9.653 62.097 11.209 ;
     RECT  102.168 11.101 109.386 11.213 ;
     RECT  102.168 11.213 109.314 11.237 ;
     RECT  112.284 11.129 114.318 11.237 ;
     RECT  190.404 11.039 190.458 11.237 ;
     RECT  88.815 9.689 89.097 11.245 ;
     RECT  90.036 10.867 90.054 11.245 ;
     RECT  120.168 7.349 120.366 11.272 ;
     RECT  88.815 11.245 90.054 11.273 ;
     RECT  112.68 11.237 114.318 11.273 ;
     RECT  139.5 10.499 139.518 11.273 ;
     RECT  120.168 11.272 120.474 11.275 ;
     RECT  68.868 11.011 71.478 11.281 ;
     RECT  72.615 6.107 72.99 11.281 ;
     RECT  102.168 11.237 108.954 11.281 ;
     RECT  101.556 11.281 108.954 11.309 ;
     RECT  120.096 11.275 120.474 11.309 ;
     RECT  158.292 10.975 159.297 11.309 ;
     RECT  169.815 11.137 170.586 11.309 ;
     RECT  174.492 11.201 175.497 11.309 ;
     RECT  190.44 11.237 190.458 11.309 ;
     RECT  101.556 11.309 108.594 11.315 ;
     RECT  52.992 6.151 53.01 11.371 ;
     RECT  54 8.311 58.086 11.371 ;
     RECT  58.932 11.173 60.462 11.371 ;
     RECT  142.128 8.159 143.097 11.371 ;
     RECT  143.892 10.201 145.062 11.371 ;
     RECT  11.232 11.245 11.25 11.399 ;
     RECT  101.556 11.315 108.45 11.399 ;
     RECT  110.415 11.129 111.438 11.399 ;
     RECT  112.716 11.273 114.318 11.399 ;
     RECT  163.044 11.039 163.062 11.399 ;
     RECT  120.096 11.309 120.366 11.407 ;
     RECT  150.84 10.769 151.65 11.507 ;
     RECT  128.268 9.553 128.286 11.515 ;
     RECT  102.168 11.399 108.45 11.543 ;
     RECT  101.376 11.509 101.394 11.549 ;
     RECT  66.816 10.201 68.094 11.551 ;
     RECT  68.868 11.281 72.99 11.551 ;
     RECT  155.628 11.209 155.646 11.551 ;
     RECT  96.444 10.085 96.966 11.641 ;
     RECT  98.316 10.939 99.897 11.669 ;
     RECT  119.952 11.407 120.366 11.669 ;
     RECT  128.268 11.515 128.538 11.669 ;
     RECT  155.628 11.551 156.402 11.669 ;
     RECT  77.292 10.561 78.894 11.677 ;
     RECT  96.444 11.641 97.218 11.705 ;
     RECT  102.348 11.543 108.45 11.705 ;
     RECT  155.628 11.669 156.15 11.705 ;
     RECT  118.62 10.895 119.106 11.741 ;
     RECT  19.764 11.173 22.266 11.749 ;
     RECT  43.272 11.137 44.802 11.749 ;
     RECT  61.308 11.209 62.154 11.749 ;
     RECT  63.036 11.011 64.854 11.749 ;
     RECT  171.36 11.443 171.378 11.749 ;
     RECT  210.204 11.137 210.222 11.785 ;
     RECT  24.015 9.677 24.297 11.803 ;
     RECT  34.815 9.677 35.097 11.803 ;
     RECT  42.804 11.749 44.802 11.803 ;
     RECT  45.615 9.677 48.042 11.803 ;
     RECT  88.815 11.273 89.622 11.803 ;
     RECT  148.215 11.129 148.497 11.821 ;
     RECT  171.108 11.749 171.378 11.821 ;
     RECT  172.152 11.749 172.17 11.821 ;
     RECT  191.196 11.039 201.402 11.821 ;
     RECT  96.3 11.749 96.318 11.837 ;
     RECT  19.764 11.749 22.878 11.849 ;
     RECT  23.904 11.803 24.297 11.849 ;
     RECT  30.852 11.749 30.87 11.849 ;
     RECT  34.704 11.803 35.097 11.849 ;
     RECT  42.804 11.803 48.042 11.849 ;
     RECT  86.688 11.749 86.706 11.849 ;
     RECT  88.704 11.803 89.622 11.849 ;
     RECT  107.748 11.705 108.45 11.849 ;
     RECT  151.164 11.507 151.65 11.849 ;
     RECT  83.415 2.413 83.697 11.911 ;
     RECT  84.492 9.661 84.51 11.911 ;
     RECT  19.764 11.849 22.266 11.933 ;
     RECT  102.348 11.705 106.686 11.939 ;
     RECT  107.748 11.849 108.378 11.939 ;
     RECT  169.815 11.309 170.19 11.939 ;
     RECT  113.364 11.399 114.318 11.975 ;
     RECT  148.14 11.821 148.497 11.975 ;
     RECT  166.464 11.515 166.59 11.975 ;
     RECT  171.108 11.821 172.17 11.975 ;
     RECT  107.748 11.939 107.982 11.984 ;
     RECT  114.264 11.975 114.318 12.019 ;
     RECT  76.932 11.677 78.894 12.055 ;
     RECT  172.152 11.975 172.17 12.083 ;
     RECT  188.928 10.867 189.522 12.083 ;
     RECT  140.688 12.091 140.706 12.187 ;
     RECT  122.256 10.685 122.994 12.209 ;
     RECT  178.38 12.091 178.398 12.209 ;
     RECT  159.015 11.309 159.297 12.217 ;
     RECT  166.464 11.975 166.518 12.217 ;
     RECT  140.436 12.187 140.706 12.245 ;
     RECT  122.256 12.209 122.742 12.269 ;
     RECT  151.164 11.849 151.182 12.289 ;
     RECT  211.356 9.355 211.374 12.289 ;
     RECT  155.628 11.705 155.646 12.317 ;
     RECT  93.672 8.491 94.59 12.361 ;
     RECT  124.56 12.331 124.578 12.361 ;
     RECT  150.588 12.289 151.182 12.361 ;
     RECT  162.576 12.055 162.594 12.361 ;
     RECT  166.428 12.217 166.518 12.361 ;
     RECT  114.264 12.019 114.894 12.451 ;
     RECT  115.668 10.895 117.81 12.451 ;
     RECT  124.056 12.361 124.578 12.475 ;
     RECT  90.648 12.361 90.666 12.479 ;
     RECT  123.768 12.475 124.578 12.479 ;
     RECT  150.552 12.361 151.182 12.479 ;
     RECT  155.556 12.361 155.574 12.479 ;
     RECT  162.576 12.361 162.918 12.479 ;
     RECT  93.672 12.361 94.95 12.487 ;
     RECT  93.672 12.487 95.022 12.515 ;
     RECT  158.472 12.217 159.297 12.515 ;
     RECT  162.576 12.479 162.594 12.515 ;
     RECT  166.356 12.361 166.518 12.515 ;
     RECT  178.128 12.325 178.146 12.515 ;
     RECT  13.215 8.509 13.77 12.523 ;
     RECT  14.544 10.597 18.99 12.523 ;
     RECT  99.288 11.669 99.897 12.523 ;
     RECT  100.62 9.689 100.638 12.523 ;
     RECT  150.588 12.479 151.182 12.551 ;
     RECT  123.768 12.479 123.786 12.587 ;
     RECT  140.796 12.361 140.814 12.587 ;
     RECT  114.264 12.451 117.81 12.623 ;
     RECT  145.944 11.129 145.962 12.623 ;
     RECT  80.28 12.487 80.298 12.631 ;
     RECT  110.415 11.399 110.697 12.631 ;
     RECT  168.588 12.631 168.606 12.749 ;
     RECT  176.976 12.595 176.994 12.749 ;
     RECT  88.815 11.849 89.622 12.757 ;
     RECT  66.816 11.551 72.99 12.793 ;
     RECT  114.264 12.623 114.894 12.845 ;
     RECT  50.4 9.931 52.038 12.865 ;
     RECT  52.992 11.371 60.462 12.865 ;
     RECT  66.708 12.793 72.99 12.893 ;
     RECT  166.5 12.515 166.518 12.893 ;
     RECT  168.66 12.757 168.678 12.893 ;
     RECT  88.815 12.757 89.766 12.901 ;
     RECT  169.815 11.939 170.097 12.901 ;
     RECT  94.215 12.515 95.022 12.929 ;
     RECT  76.932 12.055 79.254 12.991 ;
     RECT  80.28 12.631 80.442 12.991 ;
     RECT  113.364 11.975 113.418 12.991 ;
     RECT  114.264 12.845 114.282 12.991 ;
     RECT  121.215 10.685 121.497 12.991 ;
     RECT  153.615 10.427 153.897 12.991 ;
     RECT  174.168 12.901 174.438 12.991 ;
     RECT  174.096 12.991 174.438 13.003 ;
     RECT  175.215 11.309 175.497 13.003 ;
     RECT  186.015 2.413 186.297 13.003 ;
     RECT  50.4 12.865 60.462 13.019 ;
     RECT  76.932 12.991 80.442 13.019 ;
     RECT  169.815 12.901 170.514 13.019 ;
     RECT  121.104 12.991 121.497 13.037 ;
     RECT  153.504 12.991 153.897 13.037 ;
     RECT  82.44 12.901 82.458 13.051 ;
     RECT  83.415 11.911 84.51 13.051 ;
     RECT  82.44 13.051 84.51 13.055 ;
     RECT  174.096 13.003 175.497 13.055 ;
     RECT  185.904 13.003 186.297 13.055 ;
     RECT  114.192 12.991 114.282 13.085 ;
     RECT  82.692 13.055 84.51 13.091 ;
     RECT  174.096 13.055 174.438 13.091 ;
     RECT  98.316 11.669 98.334 13.099 ;
     RECT  99.288 12.523 100.638 13.099 ;
     RECT  190.944 11.821 201.402 13.099 ;
     RECT  142.128 11.371 145.062 13.171 ;
     RECT  112.86 12.991 113.418 13.199 ;
     RECT  174.096 13.091 174.114 13.261 ;
     RECT  66.816 12.893 72.99 13.289 ;
     RECT  97.2 11.705 97.218 13.325 ;
     RECT  209.916 11.785 210.222 13.333 ;
     RECT  211.284 12.289 211.374 13.333 ;
     RECT  22.824 13.027 22.842 13.369 ;
     RECT  122.256 12.269 122.274 13.369 ;
     RECT  208.944 10.903 208.962 13.369 ;
     RECT  209.916 13.333 211.374 13.369 ;
     RECT  123.588 13.297 123.606 13.373 ;
     RECT  107.748 11.984 107.766 13.397 ;
     RECT  13.215 12.523 18.99 13.405 ;
     RECT  19.764 11.933 21.906 13.405 ;
     RECT  24.015 11.849 24.297 13.432 ;
     RECT  34.815 11.849 35.097 13.432 ;
     RECT  43.272 11.849 44.802 13.432 ;
     RECT  45.615 11.849 48.042 13.432 ;
     RECT  68.328 13.289 72.99 13.433 ;
     RECT  129.636 11.129 130.266 13.435 ;
     RECT  131.544 11.011 135.234 13.469 ;
     RECT  142.128 13.171 145.71 13.559 ;
     RECT  34.704 13.432 35.097 13.565 ;
     RECT  23.904 13.432 24.297 13.568 ;
     RECT  43.272 13.432 48.042 13.568 ;
     RECT  61.308 11.749 64.854 13.595 ;
     RECT  76.932 13.019 80.298 13.595 ;
     RECT  86.688 13.261 86.706 13.595 ;
     RECT  142.128 13.559 145.458 13.595 ;
     RECT  173.844 13.261 174.114 13.595 ;
     RECT  69.804 13.433 72.99 13.603 ;
     RECT  129.636 13.435 130.554 13.613 ;
     RECT  115.668 12.623 117.81 13.631 ;
     RECT  174.096 13.595 174.114 13.631 ;
     RECT  94.215 12.929 94.878 13.639 ;
     RECT  76.932 13.595 79.254 13.661 ;
     RECT  203.436 12.829 203.454 13.675 ;
     RECT  122.256 13.369 122.562 13.801 ;
     RECT  169.815 13.019 170.442 13.837 ;
     RECT  172.512 13.711 172.782 13.837 ;
     RECT  172.512 13.837 172.854 13.865 ;
     RECT  169.815 13.837 170.514 13.873 ;
     RECT  172.836 13.865 172.854 13.873 ;
     RECT  122.256 13.801 122.634 13.901 ;
     RECT  13.215 13.405 21.906 13.909 ;
     RECT  22.824 13.369 22.95 13.909 ;
     RECT  93.492 13.639 94.878 13.909 ;
     RECT  172.836 13.873 172.926 13.937 ;
     RECT  124.56 12.479 124.578 13.945 ;
     RECT  208.944 13.369 211.374 13.945 ;
     RECT  124.56 13.945 124.902 13.973 ;
     RECT  131.544 13.469 134.226 13.973 ;
     RECT  155.052 13.603 155.07 13.973 ;
     RECT  83.34 13.091 84.51 13.981 ;
     RECT  175.215 13.055 175.497 13.981 ;
     RECT  169.815 13.873 170.586 14.009 ;
     RECT  172.908 13.937 172.926 14.009 ;
     RECT  190.404 13.099 201.402 14.009 ;
     RECT  82.656 13.981 84.51 14.099 ;
     RECT  122.256 13.901 122.562 14.099 ;
     RECT  124.812 13.973 124.902 14.099 ;
     RECT  175.215 13.981 175.626 14.099 ;
     RECT  190.404 14.009 190.422 14.099 ;
     RECT  66.816 13.289 67.497 14.107 ;
     RECT  93.168 13.909 94.878 14.107 ;
     RECT  191.196 14.009 201.402 14.107 ;
     RECT  87.552 13.801 87.57 14.143 ;
     RECT  48.996 10.123 49.446 14.179 ;
     RECT  108.072 14.071 108.09 14.179 ;
     RECT  66.744 14.107 67.497 14.207 ;
     RECT  108 14.179 108.09 14.215 ;
     RECT  109.116 13.531 109.134 14.215 ;
     RECT  175.215 14.099 175.497 14.215 ;
     RECT  208.944 13.945 211.77 14.215 ;
     RECT  83.304 14.099 84.51 14.237 ;
     RECT  108 14.215 109.134 14.341 ;
     RECT  69.804 13.603 73.098 14.369 ;
     RECT  142.128 13.595 145.278 14.369 ;
     RECT  169.815 14.009 170.442 14.369 ;
     RECT  174.492 14.215 175.497 14.369 ;
     RECT  98.316 13.099 100.638 14.413 ;
     RECT  92.592 14.107 94.878 14.449 ;
     RECT  95.76 12.181 95.778 14.449 ;
     RECT  13.215 13.909 22.95 14.485 ;
     RECT  24.015 13.568 24.297 14.485 ;
     RECT  131.544 13.973 132.297 14.513 ;
     RECT  205.452 2.827 205.47 14.521 ;
     RECT  92.592 14.449 95.778 14.525 ;
     RECT  119.952 11.669 120.33 14.639 ;
     RECT  133.056 13.973 134.226 14.711 ;
     RECT  136.62 11.129 136.638 14.711 ;
     RECT  48.996 14.179 49.626 14.719 ;
     RECT  50.4 13.019 59.778 14.719 ;
     RECT  64.836 13.595 64.854 14.719 ;
     RECT  115.668 13.631 117.27 14.791 ;
     RECT  80.28 13.595 80.298 14.917 ;
     RECT  81.216 12.793 81.234 14.917 ;
     RECT  111.42 11.399 111.438 14.923 ;
     RECT  80.28 14.917 81.234 14.945 ;
     RECT  80.532 14.945 81.234 14.957 ;
     RECT  83.34 14.237 84.51 14.989 ;
     RECT  129.636 13.613 130.266 15.053 ;
     RECT  69.84 14.369 73.098 15.061 ;
     RECT  73.944 10.705 76.086 15.061 ;
     RECT  83.34 14.989 84.618 15.061 ;
     RECT  91.476 6.043 91.494 15.061 ;
     RECT  204.588 13.405 204.606 15.061 ;
     RECT  205.452 14.521 205.65 15.061 ;
     RECT  77.292 13.661 79.254 15.089 ;
     RECT  108 14.341 109.206 15.151 ;
     RECT  110.268 12.631 110.697 15.151 ;
     RECT  111.42 14.923 111.726 15.151 ;
     RECT  121.215 13.037 121.497 15.151 ;
     RECT  153.615 13.037 153.897 15.151 ;
     RECT  164.415 2.413 164.697 15.151 ;
     RECT  175.215 14.369 175.497 15.151 ;
     RECT  186.015 13.055 186.297 15.151 ;
     RECT  82.728 15.061 84.942 15.179 ;
     RECT  94.215 14.525 95.778 15.179 ;
     RECT  203.436 13.675 203.778 15.187 ;
     RECT  82.836 15.179 84.87 15.197 ;
     RECT  113.4 13.199 113.418 15.211 ;
     RECT  82.836 15.197 84.618 15.215 ;
     RECT  90.756 15.061 91.494 15.223 ;
     RECT  112.824 15.211 113.418 15.251 ;
     RECT  25.02 1.111 25.038 15.259 ;
     RECT  66.816 14.207 67.497 15.259 ;
     RECT  102.348 11.939 106.506 15.259 ;
     RECT  90.684 15.223 91.494 15.287 ;
     RECT  94.215 15.179 94.95 15.359 ;
     RECT  91.476 15.287 91.494 15.457 ;
     RECT  92.592 14.525 93.186 15.457 ;
     RECT  202.215 2.413 202.497 15.457 ;
     RECT  203.22 15.187 203.778 15.457 ;
     RECT  69.84 15.061 76.086 15.521 ;
     RECT  101.736 15.259 106.506 15.529 ;
     RECT  82.836 15.215 84.258 15.557 ;
     RECT  95.76 15.179 95.778 15.565 ;
     RECT  122.256 14.099 122.274 15.565 ;
     RECT  97.74 14.413 100.638 15.593 ;
     RECT  61.308 13.595 63.558 15.601 ;
     RECT  82.08 15.331 82.098 15.629 ;
     RECT  191.196 14.107 201.438 15.629 ;
     RECT  61.308 15.601 63.846 15.691 ;
     RECT  108 15.151 111.726 15.691 ;
     RECT  66.132 15.259 67.497 15.719 ;
     RECT  119.088 11.741 119.106 15.727 ;
     RECT  122.256 15.565 122.562 15.727 ;
     RECT  202.215 15.457 203.778 15.727 ;
     RECT  204.588 15.061 205.65 15.727 ;
     RECT  121.104 15.151 121.497 15.728 ;
     RECT  131.904 14.513 132.297 15.728 ;
     RECT  153.504 15.151 153.897 15.728 ;
     RECT  164.304 15.151 164.697 15.728 ;
     RECT  175.104 15.151 175.497 15.728 ;
     RECT  185.904 15.151 186.297 15.728 ;
     RECT  83.34 15.557 84.258 15.755 ;
     RECT  95.76 15.565 96.426 15.755 ;
     RECT  94.215 15.359 94.698 15.763 ;
     RECT  90.684 15.287 90.738 15.827 ;
     RECT  94.176 15.763 94.698 15.827 ;
     RECT  108 15.691 112.374 15.827 ;
     RECT  122.256 15.727 122.778 15.827 ;
     RECT  67.176 15.719 67.497 15.835 ;
     RECT  94.176 15.827 94.662 15.835 ;
     RECT  69.84 15.521 71.874 15.863 ;
     RECT  97.74 15.593 100.602 15.871 ;
     RECT  61.236 15.691 63.846 15.899 ;
     RECT  72.615 15.521 76.086 15.899 ;
     RECT  90.684 15.827 90.702 15.899 ;
     RECT  72.615 15.899 74.79 15.917 ;
     RECT  135.216 13.469 135.234 15.961 ;
     RECT  81.216 14.957 81.234 15.997 ;
     RECT  127.728 15.961 127.746 16.013 ;
     RECT  86.616 15.961 86.634 16.061 ;
     RECT  135.216 15.961 135.666 16.061 ;
     RECT  88.308 12.901 89.766 16.141 ;
     RECT  125.928 9.545 126.897 16.141 ;
     RECT  61.236 15.899 63.558 16.169 ;
     RECT  125.928 16.141 127.422 16.205 ;
     RECT  118.62 15.727 119.106 16.295 ;
     RECT  113.4 15.251 113.418 16.303 ;
     RECT  95.76 15.755 95.778 16.331 ;
     RECT  112.824 16.303 113.418 16.349 ;
     RECT  80.748 15.997 81.234 16.363 ;
     RECT  45.615 13.568 48.042 16.375 ;
     RECT  48.996 14.719 59.778 16.375 ;
     RECT  77.292 15.089 78.894 16.375 ;
     RECT  101.736 15.529 106.866 16.375 ;
     RECT  87.48 14.143 87.57 16.411 ;
     RECT  88.308 16.141 90.558 16.411 ;
     RECT  75.564 15.899 76.086 16.501 ;
     RECT  80.748 16.363 81.486 16.529 ;
     RECT  80.748 16.529 81.234 16.541 ;
     RECT  45.615 16.375 59.778 16.565 ;
     RECT  135.216 16.061 135.558 16.565 ;
     RECT  151.164 12.551 151.182 16.601 ;
     RECT  133.056 14.711 133.722 16.637 ;
     RECT  135.396 16.565 135.558 16.637 ;
     RECT  83.34 15.755 84.078 16.645 ;
     RECT  75.564 16.501 76.41 16.673 ;
     RECT  26.064 2.263 26.082 16.681 ;
     RECT  66.132 15.719 66.15 16.681 ;
     RECT  67.176 15.835 67.59 16.681 ;
     RECT  97.164 15.871 100.602 16.681 ;
     RECT  101.736 16.375 107.19 16.681 ;
     RECT  87.48 16.411 90.558 16.771 ;
     RECT  25.02 15.259 25.254 16.807 ;
     RECT  26.064 16.681 26.226 16.807 ;
     RECT  48.996 16.565 59.778 16.807 ;
     RECT  164.415 15.728 164.697 16.807 ;
     RECT  108 15.827 111.834 16.835 ;
     RECT  135.396 16.637 135.486 16.835 ;
     RECT  25.02 16.807 26.226 16.843 ;
     RECT  135.396 16.835 135.414 16.871 ;
     RECT  25.02 16.843 26.55 16.877 ;
     RECT  87.264 16.771 90.558 16.891 ;
     RECT  97.164 16.681 107.19 16.907 ;
     RECT  97.164 16.907 106.866 16.951 ;
     RECT  25.02 16.877 25.326 17.069 ;
     RECT  26.064 16.877 26.55 17.069 ;
     RECT  118.62 16.295 118.638 17.077 ;
     RECT  87.264 16.891 90.63 17.078 ;
     RECT  26.136 17.069 26.55 17.105 ;
     RECT  87.264 17.078 90.594 17.117 ;
     RECT  142.128 14.369 145.062 17.141 ;
     RECT  48.996 16.807 60.462 17.149 ;
     RECT  61.236 16.169 63.054 17.149 ;
     RECT  64.656 14.719 64.854 17.185 ;
     RECT  68.328 13.433 68.886 17.185 ;
     RECT  48.996 17.149 63.054 17.213 ;
     RECT  77.292 16.375 79.146 17.221 ;
     RECT  133.056 16.637 133.362 17.249 ;
     RECT  34.815 13.565 35.097 17.311 ;
     RECT  77.292 17.221 79.254 17.311 ;
     RECT  82.26 16.645 82.278 17.311 ;
     RECT  83.34 16.645 84.258 17.311 ;
     RECT  110.268 16.835 111.834 17.311 ;
     RECT  113.4 16.349 113.418 17.311 ;
     RECT  121.215 15.728 121.497 17.311 ;
     RECT  132.015 15.728 132.297 17.311 ;
     RECT  153.615 15.728 153.897 17.311 ;
     RECT  164.415 16.807 164.754 17.311 ;
     RECT  175.215 15.728 175.497 17.311 ;
     RECT  186.015 15.728 186.297 17.311 ;
     RECT  113.256 17.311 113.418 17.357 ;
     RECT  121.104 17.311 121.497 17.357 ;
     RECT  131.904 17.311 132.297 17.357 ;
     RECT  153.504 17.311 153.897 17.357 ;
     RECT  164.304 17.311 164.754 17.357 ;
     RECT  175.104 17.311 175.497 17.357 ;
     RECT  185.904 17.311 186.297 17.357 ;
     RECT  64.332 17.185 64.854 17.375 ;
     RECT  202.215 15.727 205.65 17.383 ;
     RECT  87.264 17.117 89.766 17.419 ;
     RECT  125.928 16.205 126.897 17.447 ;
     RECT  191.415 15.629 201.438 17.453 ;
     RECT  143.892 17.141 145.062 17.483 ;
     RECT  68.328 17.185 69.21 17.491 ;
     RECT  72.615 15.917 74.718 17.491 ;
     RECT  75.564 16.673 75.798 17.491 ;
     RECT  143.892 17.483 144.486 17.519 ;
     RECT  50.4 17.213 63.054 17.609 ;
     RECT  50.4 17.609 59.778 17.645 ;
     RECT  60.516 17.609 63.054 17.645 ;
     RECT  68.328 17.491 69.282 17.645 ;
     RECT  82.26 17.311 84.258 17.645 ;
     RECT  87.012 17.419 89.766 17.645 ;
     RECT  110.268 17.311 112.158 17.645 ;
     RECT  68.328 17.645 69.03 17.681 ;
     RECT  43.272 13.568 44.802 17.752 ;
     RECT  45.615 16.565 48.042 17.752 ;
     RECT  13.215 14.485 24.297 17.851 ;
     RECT  13.104 17.851 24.297 17.888 ;
     RECT  13.215 17.888 24.297 17.923 ;
     RECT  25.02 17.069 25.254 17.923 ;
     RECT  30.852 17.851 30.87 17.923 ;
     RECT  34.704 17.311 35.097 17.923 ;
     RECT  206.604 10.561 207.897 17.923 ;
     RECT  30.78 17.923 30.87 17.951 ;
     RECT  93.996 15.835 94.662 17.951 ;
     RECT  96.912 16.951 106.866 17.951 ;
     RECT  30.78 17.951 30.798 18.023 ;
     RECT  130.248 15.053 130.266 18.023 ;
     RECT  83.34 17.645 84.258 18.031 ;
     RECT  50.4 17.645 59.706 18.059 ;
     RECT  128.52 11.669 128.538 18.059 ;
     RECT  133.344 17.249 133.362 18.059 ;
     RECT  13.215 17.923 25.254 18.091 ;
     RECT  13.215 18.091 25.542 18.121 ;
     RECT  99.432 17.951 106.866 18.121 ;
     RECT  108 16.835 109.494 18.121 ;
     RECT  26.532 17.105 26.55 18.149 ;
     RECT  188.928 12.083 188.946 18.149 ;
     RECT  119.952 14.639 119.97 18.187 ;
     RECT  99.432 18.121 109.494 18.193 ;
     RECT  110.268 17.645 111.834 18.193 ;
     RECT  113.4 17.357 113.418 18.265 ;
     RECT  114.264 13.085 114.282 18.265 ;
     RECT  66.132 16.681 67.59 18.293 ;
     RECT  122.256 15.827 122.274 18.301 ;
     RECT  126.615 17.447 126.897 18.301 ;
     RECT  34.704 17.923 35.154 18.329 ;
     RECT  43.272 17.752 48.042 18.329 ;
     RECT  96.912 17.951 98.442 18.329 ;
     RECT  83.34 18.031 84.546 18.391 ;
     RECT  85.752 13.027 85.77 18.391 ;
     RECT  122.256 18.301 122.562 18.419 ;
     RECT  126.615 18.301 126.954 18.419 ;
     RECT  48.996 17.213 49.626 18.455 ;
     RECT  194.076 17.453 201.438 18.463 ;
     RECT  202.215 17.383 205.83 18.463 ;
     RECT  87.264 17.645 89.766 18.499 ;
     RECT  146.196 14.647 146.214 18.509 ;
     RECT  118.26 17.077 118.638 18.563 ;
     RECT  86.652 18.499 89.766 18.571 ;
     RECT  90.54 18.499 90.558 18.571 ;
     RECT  86.652 18.571 90.558 18.599 ;
     RECT  119.448 18.187 119.97 18.599 ;
     RECT  29.415 2.413 29.697 18.619 ;
     RECT  34.815 18.329 35.154 18.619 ;
     RECT  40.215 6.656 40.497 18.619 ;
     RECT  29.088 18.619 29.79 18.689 ;
     RECT  39.924 18.619 40.59 18.689 ;
     RECT  66.672 18.293 67.59 18.689 ;
     RECT  94.215 17.951 94.662 18.689 ;
     RECT  113.4 18.265 114.282 18.725 ;
     RECT  97.02 18.329 98.442 18.733 ;
     RECT  99.432 18.193 111.834 18.733 ;
     RECT  194.076 18.463 205.83 18.733 ;
     RECT  206.604 17.923 208.098 18.733 ;
     RECT  64.656 17.375 64.854 18.761 ;
     RECT  77.292 17.311 79.83 18.761 ;
     RECT  86.724 18.599 90.558 18.761 ;
     RECT  97.02 18.733 111.834 18.833 ;
     RECT  26.784 18.811 27.27 18.941 ;
     RECT  26.784 18.941 27.162 18.989 ;
     RECT  13.215 18.121 25.686 19.039 ;
     RECT  50.4 18.059 58.086 19.099 ;
     RECT  58.932 18.059 59.706 19.099 ;
     RECT  122.256 18.419 122.274 19.103 ;
     RECT  124.812 14.099 124.83 19.103 ;
     RECT  43.272 18.329 44.802 19.111 ;
     RECT  86.76 18.761 90.558 19.111 ;
     RECT  91.476 15.457 93.186 19.111 ;
     RECT  164.415 17.357 164.754 19.139 ;
     RECT  34.815 18.619 35.19 19.201 ;
     RECT  40.215 18.689 40.59 19.201 ;
     RECT  27.144 18.989 27.162 19.265 ;
     RECT  142.128 17.141 143.097 19.265 ;
     RECT  50.4 19.099 59.706 19.277 ;
     RECT  34.815 19.201 35.262 19.301 ;
     RECT  38.772 19.201 38.79 19.301 ;
     RECT  40.215 19.201 40.662 19.301 ;
     RECT  143.892 17.519 143.91 19.301 ;
     RECT  208.944 14.215 211.986 19.345 ;
     RECT  34.815 19.301 35.19 19.381 ;
     RECT  13.215 19.039 26.226 19.471 ;
     RECT  37.944 19.381 37.962 19.471 ;
     RECT  34.776 19.381 35.19 19.483 ;
     RECT  42.768 19.111 44.802 19.483 ;
     RECT  45.615 18.329 48.042 19.483 ;
     RECT  37.836 19.471 37.962 19.499 ;
     RECT  70.272 15.863 71.874 19.543 ;
     RECT  37.836 19.499 37.854 19.571 ;
     RECT  97.02 18.833 105.75 19.571 ;
     RECT  190.44 19.471 190.458 19.571 ;
     RECT  86.76 19.111 93.186 19.579 ;
     RECT  58.932 19.277 59.706 19.615 ;
     RECT  114.264 18.725 114.282 19.615 ;
     RECT  194.076 18.733 208.098 19.615 ;
     RECT  208.944 19.345 212.13 19.615 ;
     RECT  101.16 19.571 105.75 19.643 ;
     RECT  191.415 17.453 192.978 19.679 ;
     RECT  50.4 19.277 58.086 19.769 ;
     RECT  97.02 19.571 100.026 19.769 ;
     RECT  94.215 18.689 94.497 19.777 ;
     RECT  13.104 19.471 26.226 19.813 ;
     RECT  70.092 19.543 71.874 19.849 ;
     RECT  72.615 17.491 75.798 19.849 ;
     RECT  12.888 19.813 26.226 19.853 ;
     RECT  61.236 17.645 63.054 19.921 ;
     RECT  63.864 19.543 63.882 19.921 ;
     RECT  64.656 18.761 64.782 19.921 ;
     RECT  95.76 17.761 95.778 19.921 ;
     RECT  70.092 19.849 75.798 19.949 ;
     RECT  48.996 18.455 49.446 19.963 ;
     RECT  67.176 18.689 67.59 20.011 ;
     RECT  86.652 19.579 93.186 20.011 ;
     RECT  13.215 19.853 26.226 20.039 ;
     RECT  83.34 18.391 85.77 20.039 ;
     RECT  86.616 20.011 93.186 20.039 ;
     RECT  77.292 18.761 79.506 20.111 ;
     RECT  67.104 20.011 67.59 20.155 ;
     RECT  68.328 17.681 68.886 20.155 ;
     RECT  70.092 19.949 71.838 20.155 ;
     RECT  94.215 19.777 94.77 20.219 ;
     RECT  66.708 20.155 67.59 20.299 ;
     RECT  48.996 19.963 49.662 20.309 ;
     RECT  50.4 19.769 57.474 20.309 ;
     RECT  66.132 20.299 67.59 20.309 ;
     RECT  72.615 19.949 75.798 20.309 ;
     RECT  66.132 20.309 67.497 20.345 ;
     RECT  36.18 19.615 36.198 20.353 ;
     RECT  113.4 18.725 113.418 20.353 ;
     RECT  114.264 19.615 114.642 20.353 ;
     RECT  72.615 20.309 73.206 20.381 ;
     RECT  42.768 19.483 48.042 20.389 ;
     RECT  48.996 20.309 49.446 20.389 ;
     RECT  115.416 14.791 117.27 20.417 ;
     RECT  29.415 18.689 29.79 20.443 ;
     RECT  34.704 19.483 35.19 20.443 ;
     RECT  35.964 20.353 36.198 20.443 ;
     RECT  40.215 19.301 40.59 20.443 ;
     RECT  26.784 20.353 26.802 20.489 ;
     RECT  34.704 20.443 36.198 20.489 ;
     RECT  68.328 20.155 71.838 20.489 ;
     RECT  87.948 20.039 93.186 20.489 ;
     RECT  50.4 20.309 52.794 20.539 ;
     RECT  97.164 19.769 100.026 20.539 ;
     RECT  101.16 19.643 101.178 20.539 ;
     RECT  101.916 19.643 105.75 20.551 ;
     RECT  106.488 18.833 111.834 20.551 ;
     RECT  61.236 19.921 64.782 20.579 ;
     RECT  95.76 19.921 96.354 20.587 ;
     RECT  97.164 20.539 101.178 20.587 ;
     RECT  38.772 20.353 38.79 20.635 ;
     RECT  95.76 20.587 101.178 20.651 ;
     RECT  113.4 20.353 114.642 20.659 ;
     RECT  13.215 20.039 25.686 20.687 ;
     RECT  50.184 20.539 52.794 20.687 ;
     RECT  101.916 20.551 111.834 20.695 ;
     RECT  194.076 19.615 212.13 20.717 ;
     RECT  25.668 20.687 25.686 20.723 ;
     RECT  101.916 20.695 112.05 20.723 ;
     RECT  82.26 17.645 82.278 20.731 ;
     RECT  115.704 20.417 117.27 20.731 ;
     RECT  118.26 18.563 118.278 20.731 ;
     RECT  77.292 20.111 79.398 20.759 ;
     RECT  42.768 20.389 49.446 20.821 ;
     RECT  103.716 20.723 112.05 20.821 ;
     RECT  113.364 20.659 114.642 20.821 ;
     RECT  115.704 20.731 118.278 20.821 ;
     RECT  144.072 19.309 144.09 20.821 ;
     RECT  74.052 20.309 75.798 20.849 ;
     RECT  77.292 20.759 78.714 20.849 ;
     RECT  81.216 16.541 81.234 20.849 ;
     RECT  86.616 20.039 86.814 20.849 ;
     RECT  77.292 20.849 78.678 20.857 ;
     RECT  103.716 20.821 112.086 20.857 ;
     RECT  90.684 20.489 93.186 20.885 ;
     RECT  101.916 20.723 102.834 20.885 ;
     RECT  42.192 20.821 49.446 20.909 ;
     RECT  77.076 20.857 78.678 20.909 ;
     RECT  90.9 20.885 93.186 20.921 ;
     RECT  100.872 20.651 101.178 20.921 ;
     RECT  30.78 20.353 30.798 20.929 ;
     RECT  53.676 20.309 57.474 20.957 ;
     RECT  79.812 20.92 80.118 20.957 ;
     RECT  113.364 20.821 114.75 20.957 ;
     RECT  30.78 20.929 30.906 20.971 ;
     RECT  61.236 20.579 63.054 21.001 ;
     RECT  194.724 20.717 212.13 21.001 ;
     RECT  213.015 2.413 213.297 21.001 ;
     RECT  38.772 20.635 39.078 21.005 ;
     RECT  50.184 20.687 52.542 21.029 ;
     RECT  101.16 20.921 101.178 21.029 ;
     RECT  103.716 20.857 112.302 21.029 ;
     RECT  113.364 20.957 114.714 21.029 ;
     RECT  38.772 21.005 39.006 21.053 ;
     RECT  61.092 21.001 63.054 21.053 ;
     RECT  91.296 20.921 93.186 21.053 ;
     RECT  115.704 20.821 118.35 21.053 ;
     RECT  69.948 20.489 71.838 21.067 ;
     RECT  72.615 20.381 73.098 21.067 ;
     RECT  42.336 20.909 49.446 21.115 ;
     RECT  42.336 21.115 49.842 21.119 ;
     RECT  50.724 21.029 52.542 21.119 ;
     RECT  63.864 20.579 64.782 21.119 ;
     RECT  66.24 20.345 67.497 21.119 ;
     RECT  68.328 20.489 68.886 21.119 ;
     RECT  69.948 21.067 73.098 21.119 ;
     RECT  74.052 20.849 75.582 21.119 ;
     RECT  82.26 20.731 82.422 21.119 ;
     RECT  103.716 21.029 109.494 21.119 ;
     RECT  113.364 21.029 114.678 21.119 ;
     RECT  115.815 21.053 118.35 21.119 ;
     RECT  50.724 21.119 52.146 21.155 ;
     RECT  39.924 20.443 40.59 21.163 ;
     RECT  91.44 21.053 93.186 21.191 ;
     RECT  66.312 21.119 67.497 21.199 ;
     RECT  68.328 21.119 68.562 21.199 ;
     RECT  87.948 20.489 89.766 21.199 ;
     RECT  94.215 20.219 94.698 21.199 ;
     RECT  26.748 21.127 26.766 21.227 ;
     RECT  38.772 21.053 38.97 21.235 ;
     RECT  191.415 19.679 192.654 21.245 ;
     RECT  29.088 20.443 29.79 21.259 ;
     RECT  34.704 20.489 35.226 21.259 ;
     RECT  87.372 21.199 89.766 21.263 ;
     RECT  54.18 20.957 57.474 21.271 ;
     RECT  58.932 19.615 59.922 21.271 ;
     RECT  69.948 21.119 71.874 21.271 ;
     RECT  72.615 21.119 73.098 21.271 ;
     RECT  83.34 20.039 85.194 21.271 ;
     RECT  86.616 20.849 86.634 21.271 ;
     RECT  94.215 21.199 94.734 21.271 ;
     RECT  95.76 20.651 100.026 21.271 ;
     RECT  142.815 19.265 143.097 21.271 ;
     RECT  175.215 17.357 175.497 21.271 ;
     RECT  29.088 21.259 29.862 21.299 ;
     RECT  39.924 21.163 41.058 21.299 ;
     RECT  50.724 21.155 52.038 21.299 ;
     RECT  69.516 21.271 71.874 21.299 ;
     RECT  77.184 20.909 78.678 21.299 ;
     RECT  86.04 21.271 86.634 21.299 ;
     RECT  94.215 21.271 100.026 21.299 ;
     RECT  110.415 21.029 112.302 21.299 ;
     RECT  113.364 21.119 113.598 21.299 ;
     RECT  114.588 21.119 114.678 21.299 ;
     RECT  30.78 20.971 30.942 21.307 ;
     RECT  83.268 21.271 85.302 21.307 ;
     RECT  58.788 21.271 60.39 21.341 ;
     RECT  65.34 21.271 65.358 21.341 ;
     RECT  66.312 21.199 68.562 21.341 ;
     RECT  69.516 21.299 71.838 21.341 ;
     RECT  72.615 21.271 73.134 21.341 ;
     RECT  74.124 21.119 74.682 21.341 ;
     RECT  80.964 21.271 80.982 21.341 ;
     RECT  86.04 21.299 86.274 21.341 ;
     RECT  50.724 21.299 51.297 21.347 ;
     RECT  77.184 21.299 78.297 21.347 ;
     RECT  88.704 21.263 89.766 21.347 ;
     RECT  94.215 21.299 99.897 21.347 ;
     RECT  121.215 17.357 121.497 21.347 ;
     RECT  126.615 18.419 126.897 21.347 ;
     RECT  132.015 17.357 132.297 21.347 ;
     RECT  137.415 11.129 137.697 21.347 ;
     RECT  142.524 21.271 143.097 21.347 ;
     RECT  148.215 11.975 148.497 21.347 ;
     RECT  153.615 17.357 153.897 21.347 ;
     RECT  159.015 12.515 159.297 21.347 ;
     RECT  164.415 19.139 164.697 21.347 ;
     RECT  169.815 14.369 170.097 21.347 ;
     RECT  175.212 21.271 175.497 21.347 ;
     RECT  180.615 2.413 180.897 21.347 ;
     RECT  186.015 17.357 186.297 21.347 ;
     RECT  7.815 2.413 8.097 21.355 ;
     RECT  26.784 21.307 26.91 21.355 ;
     RECT  34.704 21.259 35.262 21.355 ;
     RECT  175.212 21.347 175.305 21.361 ;
     RECT  38.736 21.235 38.97 21.389 ;
     RECT  45.615 21.119 49.842 21.389 ;
     RECT  52.02 21.299 52.038 21.389 ;
     RECT  53.28 21.115 53.298 21.389 ;
     RECT  54.18 21.271 57.582 21.389 ;
     RECT  58.788 21.341 59.706 21.389 ;
     RECT  61.236 21.053 63.054 21.389 ;
     RECT  63.864 21.119 64.386 21.389 ;
     RECT  67.032 21.341 68.346 21.389 ;
     RECT  70.056 21.341 71.838 21.389 ;
     RECT  74.628 21.341 74.682 21.389 ;
     RECT  75.564 21.119 75.582 21.389 ;
     RECT  79.812 20.957 79.83 21.389 ;
     RECT  89.748 21.347 89.766 21.389 ;
     RECT  94.215 21.347 99.705 21.389 ;
     RECT  106.092 21.119 109.494 21.389 ;
     RECT  119.448 18.599 119.466 21.389 ;
     RECT  144.072 20.821 144.522 21.389 ;
     RECT  110.415 21.299 111.978 21.395 ;
     RECT  29.304 21.299 29.862 21.403 ;
     RECT  142.524 21.347 142.905 21.425 ;
     RECT  30.78 21.307 30.978 21.437 ;
     RECT  38.772 21.389 38.97 21.437 ;
     RECT  45.615 21.389 46.962 21.437 ;
     RECT  55.476 21.389 56.682 21.437 ;
     RECT  72.615 21.341 73.098 21.437 ;
     RECT  83.232 21.307 85.302 21.437 ;
     RECT  87.372 21.263 87.822 21.437 ;
     RECT  117.864 21.119 118.35 21.437 ;
     RECT  142.704 21.425 142.905 21.437 ;
     RECT  144.504 21.389 144.522 21.437 ;
     RECT  175.104 21.361 175.305 21.437 ;
     RECT  176.652 21.397 176.67 21.437 ;
     RECT  113.364 21.299 113.562 21.469 ;
     RECT  7.815 21.355 8.19 21.485 ;
     RECT  30.78 21.437 30.906 21.485 ;
     RECT  87.372 21.437 87.39 21.485 ;
     RECT  30.816 21.485 30.906 21.497 ;
     RECT  45.615 21.437 46.818 21.497 ;
     RECT  54.18 21.389 54.738 21.497 ;
     RECT  101.448 21.163 101.61 21.497 ;
     RECT  103.716 21.119 105.354 21.497 ;
     RECT  13.215 20.687 24.57 21.499 ;
     RECT  34.704 21.355 35.37 21.499 ;
     RECT  102.564 20.885 102.834 21.505 ;
     RECT  103.716 21.497 105.105 21.505 ;
     RECT  117.972 21.437 118.35 21.505 ;
     RECT  29.304 21.403 29.898 21.533 ;
     RECT  38.772 21.437 38.934 21.533 ;
     RECT  42.336 21.119 44.478 21.533 ;
     RECT  45.615 21.497 46.206 21.533 ;
     RECT  50.724 21.347 51.282 21.533 ;
     RECT  70.056 21.389 70.758 21.533 ;
     RECT  72.615 21.437 73.026 21.533 ;
     RECT  77.184 21.347 78.282 21.533 ;
     RECT  89.82 21.451 89.838 21.533 ;
     RECT  101.448 21.497 101.538 21.533 ;
     RECT  114.588 21.299 114.606 21.533 ;
     RECT  34.704 21.499 35.442 21.541 ;
     RECT  63.864 21.389 63.882 21.541 ;
     RECT  83.232 21.437 84.618 21.541 ;
     RECT  113.328 21.469 113.562 21.541 ;
     RECT  13.215 21.499 24.642 21.569 ;
     RECT  26.784 21.355 26.982 21.569 ;
     RECT  34.632 21.541 35.442 21.569 ;
     RECT  40.104 21.299 41.058 21.569 ;
     RECT  54.252 21.497 54.738 21.569 ;
     RECT  91.44 21.191 92.61 21.569 ;
     RECT  106.092 21.389 108.954 21.569 ;
     RECT  50.724 21.533 51.21 21.581 ;
     RECT  55.584 21.437 56.682 21.581 ;
     RECT  61.236 21.389 62.802 21.581 ;
     RECT  67.104 21.389 68.022 21.581 ;
     RECT  70.056 21.533 70.434 21.581 ;
     RECT  88.704 21.347 88.905 21.581 ;
     RECT  45.615 21.533 45.918 21.617 ;
     RECT  50.724 21.581 51.105 21.617 ;
     RECT  61.236 21.581 61.905 21.617 ;
     RECT  72.615 21.533 72.81 21.617 ;
     RECT  82.656 21.541 84.618 21.617 ;
     RECT  88.815 21.581 88.905 21.617 ;
     RECT  94.215 21.389 98.082 21.617 ;
     RECT  99.108 21.389 99.705 21.617 ;
     RECT  102.564 21.505 105.105 21.617 ;
     RECT  110.415 21.395 110.505 21.617 ;
     RECT  115.815 21.119 116.946 21.617 ;
     RECT  121.215 21.347 121.305 21.617 ;
     RECT  126.615 21.347 126.705 21.617 ;
     RECT  132.015 21.347 132.105 21.617 ;
     RECT  137.415 21.347 137.505 21.617 ;
     RECT  142.815 21.437 142.905 21.617 ;
     RECT  148.215 21.347 148.305 21.617 ;
     RECT  153.615 21.347 153.705 21.617 ;
     RECT  159.015 21.347 159.105 21.617 ;
     RECT  164.415 21.347 164.505 21.617 ;
     RECT  169.815 21.347 169.905 21.617 ;
     RECT  175.215 21.437 175.305 21.617 ;
     RECT  180.615 21.347 180.705 21.617 ;
     RECT  186.015 21.347 186.105 21.617 ;
     RECT  191.415 21.245 191.79 21.617 ;
     RECT  34.632 21.569 35.082 21.629 ;
     RECT  55.656 21.581 56.682 21.629 ;
     RECT  62.712 21.581 62.802 21.629 ;
     RECT  63.684 21.541 63.882 21.629 ;
     RECT  72.792 21.617 72.81 21.629 ;
     RECT  26.964 21.569 26.982 21.659 ;
     RECT  29.304 21.533 29.682 21.659 ;
     RECT  30.888 21.497 30.906 21.659 ;
     RECT  34.704 21.629 35.082 21.659 ;
     RECT  40.104 21.569 40.482 21.659 ;
     RECT  48.42 21.389 48.762 21.659 ;
     RECT  50.724 21.617 50.742 21.659 ;
     RECT  54.72 21.569 54.738 21.659 ;
     RECT  56.304 21.629 56.682 21.659 ;
     RECT  62.784 21.629 62.802 21.659 ;
     RECT  67.104 21.581 67.482 21.659 ;
     RECT  74.664 21.389 74.682 21.659 ;
     RECT  77.904 21.533 78.282 21.659 ;
     RECT  82.656 21.617 83.322 21.659 ;
     RECT  84.204 21.617 84.618 21.659 ;
     RECT  91.44 21.569 92.538 21.659 ;
     RECT  101.448 21.533 101.466 21.659 ;
     RECT  108.864 21.569 108.954 21.659 ;
     RECT  112.932 21.541 113.562 21.659 ;
     RECT  34.704 21.659 35.01 21.677 ;
     RECT  56.304 21.659 56.61 21.677 ;
     RECT  67.104 21.659 67.41 21.677 ;
     RECT  77.904 21.659 78.21 21.677 ;
     RECT  83.268 21.659 83.322 21.677 ;
     RECT  106.092 21.569 106.254 21.677 ;
     RECT  117.972 21.505 119.322 21.677 ;
     RECT  61.236 21.617 61.254 21.695 ;
     RECT  106.092 21.677 106.11 21.695 ;
     RECT  42.336 21.533 42.354 21.725 ;
     RECT  80.748 21.541 80.766 21.731 ;
     RECT  63.864 21.629 63.882 21.767 ;
     RECT  94.896 21.617 98.082 21.767 ;
     RECT  38.772 21.533 38.898 21.773 ;
     RECT  45.792 21.617 45.918 21.773 ;
     RECT  86.04 21.341 86.058 21.803 ;
     RECT  111.42 21.395 111.978 21.803 ;
     RECT  71.82 21.389 71.838 21.839 ;
     RECT  95.004 21.767 98.082 21.839 ;
     RECT  91.908 21.659 92.538 21.965 ;
     RECT  95.688 21.839 98.082 21.965 ;
     RECT  99.108 21.617 99.522 21.965 ;
     RECT  84.6 21.659 84.618 22.001 ;
     RECT  9.648 19.309 9.666 22.009 ;
     RECT  38.772 21.773 38.79 22.013 ;
     RECT  45.9 21.773 45.918 22.013 ;
     RECT  57.564 21.389 57.582 22.037 ;
     RECT  107.208 21.569 107.874 22.037 ;
     RECT  111.708 21.803 111.978 22.061 ;
     RECT  13.215 21.569 24.282 22.073 ;
     RECT  58.788 21.389 59.382 22.073 ;
     RECT  111.708 22.061 111.726 22.073 ;
     RECT  43.344 21.533 44.478 22.109 ;
     RECT  112.932 21.659 113.418 22.109 ;
     RECT  117.972 21.677 118.278 22.109 ;
     RECT  13.215 22.073 23.958 22.154 ;
     RECT  95.76 21.965 98.082 22.271 ;
     RECT  48.42 21.659 48.438 22.307 ;
     RECT  44.46 22.109 44.478 22.363 ;
     RECT  102.564 21.617 104.922 22.493 ;
     RECT  10.98 11.515 10.998 22.507 ;
     RECT  44.46 22.363 45.018 22.541 ;
     RECT  96.336 22.271 98.082 22.541 ;
     RECT  107.208 22.037 107.766 22.541 ;
     RECT  91.908 21.965 91.926 22.577 ;
     RECT  102.564 22.493 102.582 22.613 ;
     RECT  10.836 22.507 10.998 22.637 ;
     RECT  99.108 21.965 99.126 22.637 ;
     RECT  107.208 22.541 107.226 22.649 ;
     RECT  192.636 21.245 192.654 22.733 ;
     RECT  116.532 21.617 116.946 22.739 ;
     RECT  194.724 21.001 213.297 22.781 ;
     RECT  70.092 21.581 70.434 22.847 ;
     RECT  116.532 22.739 116.55 22.847 ;
     RECT  194.724 22.781 195.858 22.877 ;
     RECT  70.416 22.847 70.434 22.883 ;
     RECT  96.408 22.541 98.082 22.883 ;
     RECT  196.74 22.781 213.297 22.925 ;
     RECT  194.796 22.877 195.858 22.973 ;
     RECT  13.215 22.154 23.634 23.009 ;
     RECT  59.364 22.073 59.382 23.021 ;
     RECT  194.796 22.973 194.814 23.021 ;
     RECT  13.215 23.009 23.166 23.76 ;
     RECT  24.516 23.515 24.534 23.76 ;
     RECT  32.76 20.119 32.778 23.76 ;
     RECT  36.18 20.489 36.198 23.76 ;
     RECT  43.344 22.109 43.362 23.76 ;
     RECT  83.268 21.677 83.286 23.76 ;
     RECT  96.408 22.883 96.426 23.76 ;
     RECT  97.452 22.883 98.082 23.76 ;
     RECT  104.436 22.493 104.922 23.76 ;
     RECT  113.4 22.109 113.418 23.76 ;
     RECT  118.26 22.109 118.278 23.76 ;
     RECT  119.304 21.677 119.322 23.76 ;
     RECT  191.772 21.617 191.79 23.76 ;
     RECT  195.768 22.973 195.858 23.76 ;
     RECT  197.244 22.925 213.297 23.76 ;
     RECT  13.215 23.76 213.297 24.745 ;
     RECT  13.176 24.745 213.297 25.051 ;
     RECT  12.096 25.195 12.114 25.243 ;
     RECT  12.852 25.051 213.297 25.243 ;
     RECT  12.096 25.243 213.297 28.175 ;
     RECT  215.604 21.469 215.622 28.759 ;
     RECT  12.096 28.175 12.294 32.431 ;
     RECT  13.032 28.175 213.297 32.431 ;
     RECT  12.096 32.431 213.297 32.477 ;
     RECT  13.032 32.477 213.297 33.341 ;
     RECT  16.74 33.341 213.297 33.677 ;
     RECT  201.42 33.677 213.297 33.773 ;
     RECT  16.74 33.677 200.394 34.061 ;
     RECT  10.98 22.637 10.998 34.493 ;
     RECT  16.74 34.061 199.242 34.541 ;
     RECT  10.8 34.795 10.818 34.889 ;
     RECT  9.36 22.009 9.666 34.969 ;
     RECT  9.36 34.969 10.242 35.021 ;
     RECT  214.02 19.579 214.038 35.041 ;
     RECT  214.992 28.759 215.622 35.131 ;
     RECT  214.02 35.041 214.11 35.159 ;
     RECT  200.376 34.061 200.394 35.311 ;
     RECT  16.74 34.541 199.026 35.597 ;
     RECT  16.74 35.597 198.63 35.981 ;
     RECT  9.36 35.021 9.666 36.475 ;
     RECT  7.02 21.001 7.038 37.003 ;
     RECT  7.815 21.485 8.097 37.003 ;
     RECT  7.02 37.003 8.097 37.049 ;
     RECT  9.252 36.475 9.666 37.049 ;
     RECT  214.992 35.131 215.874 37.085 ;
     RECT  16.74 35.981 21.006 37.195 ;
     RECT  21.924 35.981 198.342 37.195 ;
     RECT  199.908 35.311 200.394 37.561 ;
     RECT  16.74 37.195 198.342 37.613 ;
     RECT  16.74 37.613 197.64 38.539 ;
     RECT  199.872 37.561 200.394 39.019 ;
     RECT  199.512 39.019 200.394 39.119 ;
     RECT  16.74 38.539 197.73 39.181 ;
     RECT  5.652 38.779 5.67 39.209 ;
     RECT  5.148 39.289 5.166 39.341 ;
     RECT  199.872 39.119 200.394 39.341 ;
     RECT  16.74 39.181 198.342 39.437 ;
     RECT  199.908 39.341 200.394 40.013 ;
     RECT  4.284 40.639 4.302 40.675 ;
     RECT  2.415 2.413 2.697 40.711 ;
     RECT  4.14 40.675 4.302 40.711 ;
     RECT  2.415 40.711 4.302 40.939 ;
     RECT  199.944 40.013 200.394 40.945 ;
     RECT  2.415 40.939 4.338 40.981 ;
     RECT  5.112 40.555 5.13 40.981 ;
     RECT  7.02 37.049 7.038 41.083 ;
     RECT  16.74 39.437 197.64 41.107 ;
     RECT  199.872 40.945 200.394 41.131 ;
     RECT  2.376 40.981 5.274 41.179 ;
     RECT  2.376 41.179 5.67 41.215 ;
     RECT  2.376 41.215 5.922 41.251 ;
     RECT  6.84 41.083 7.038 41.251 ;
     RECT  199.512 41.131 200.394 41.279 ;
     RECT  2.376 41.251 7.038 41.485 ;
     RECT  16.74 41.107 198.342 41.645 ;
     RECT  16.74 41.645 198.306 42.421 ;
     RECT  199.872 41.279 200.394 42.475 ;
     RECT  2.304 41.485 7.038 42.52 ;
     RECT  7.815 37.049 8.097 42.52 ;
     RECT  10.8 42.427 10.818 42.557 ;
     RECT  199.512 42.475 200.394 42.593 ;
     RECT  16.74 42.421 198.342 42.691 ;
     RECT  13.032 33.341 15.894 42.835 ;
     RECT  16.704 42.691 198.342 42.835 ;
     RECT  13.032 42.835 198.342 42.893 ;
     RECT  12.096 32.477 12.294 43.141 ;
     RECT  199.872 42.593 200.394 43.373 ;
     RECT  0.108 43.267 0.126 43.435 ;
     RECT  0.108 43.435 0.27 43.757 ;
     RECT  13.032 42.893 198.306 43.807 ;
     RECT  2.304 42.52 8.097 43.843 ;
     RECT  2.304 43.843 8.262 43.915 ;
     RECT  11.772 43.141 12.294 43.915 ;
     RECT  13.032 43.807 198.342 43.915 ;
     RECT  11.772 43.915 198.342 44.045 ;
     RECT  11.772 44.045 197.73 44.069 ;
     RECT  199.944 43.373 200.394 44.113 ;
     RECT  13.032 44.069 197.73 44.141 ;
     RECT  199.872 44.113 200.394 44.299 ;
     RECT  199.872 44.299 200.43 44.375 ;
     RECT  0.108 43.757 0.162 44.429 ;
     RECT  217.764 44.419 218.034 44.491 ;
     RECT  216.828 44.491 216.846 44.581 ;
     RECT  216.828 44.581 216.918 44.653 ;
     RECT  199.872 44.375 200.394 44.68 ;
     RECT  216.756 44.653 216.918 44.689 ;
     RECT  220.14 44.581 220.158 44.725 ;
     RECT  2.304 43.915 8.622 44.761 ;
     RECT  9.36 37.049 9.666 44.761 ;
     RECT  216.504 44.689 216.918 44.761 ;
     RECT  217.764 44.491 218.466 44.761 ;
     RECT  2.304 44.761 9.666 44.813 ;
     RECT  214.992 37.085 215.622 44.851 ;
     RECT  216.504 44.761 218.466 44.851 ;
     RECT  199.512 44.68 200.394 44.909 ;
     RECT  220.14 44.725 220.23 44.923 ;
     RECT  199.512 44.909 199.566 45.031 ;
     RECT  220.14 44.923 220.302 45.121 ;
     RECT  199.476 45.031 199.566 45.193 ;
     RECT  13.032 44.141 197.64 45.256 ;
     RECT  198.9 45.193 199.566 45.256 ;
     RECT  2.304 44.813 8.442 45.265 ;
     RECT  11.772 44.069 12.294 45.301 ;
     RECT  13.032 45.256 199.566 45.301 ;
     RECT  214.992 44.851 218.466 45.301 ;
     RECT  219.204 45.265 219.222 45.301 ;
     RECT  2.268 45.265 8.442 45.341 ;
     RECT  214.092 35.159 214.11 45.391 ;
     RECT  214.848 45.301 218.466 45.391 ;
     RECT  0.144 44.429 0.162 45.403 ;
     RECT  2.304 45.341 8.442 45.455 ;
     RECT  0.144 45.403 0.234 45.535 ;
     RECT  2.34 45.455 8.442 45.535 ;
     RECT  9.36 44.813 9.666 45.535 ;
     RECT  0.108 45.535 0.234 45.563 ;
     RECT  2.34 45.535 9.666 45.571 ;
     RECT  11.772 45.301 199.566 45.581 ;
     RECT  198.9 45.581 199.566 45.599 ;
     RECT  199.512 45.599 199.566 45.643 ;
     RECT  200.376 44.909 200.394 45.643 ;
     RECT  219.204 45.301 219.294 45.841 ;
     RECT  0.108 45.563 0.162 45.965 ;
     RECT  0.144 45.965 0.162 46.031 ;
     RECT  199.512 45.643 200.394 46.157 ;
     RECT  10.836 45.301 10.854 46.219 ;
     RECT  2.34 45.571 9.99 46.229 ;
     RECT  11.772 45.581 197.73 46.265 ;
     RECT  201.456 33.773 213.297 46.309 ;
     RECT  214.092 45.391 218.466 46.309 ;
     RECT  2.34 46.229 9.702 46.345 ;
     RECT  199.872 46.157 200.394 46.345 ;
     RECT  199.872 46.345 200.502 46.373 ;
     RECT  0.54 46.315 0.81 46.459 ;
     RECT  199.908 46.373 200.502 46.541 ;
     RECT  0.54 46.459 0.882 46.637 ;
     RECT  201.456 46.309 218.466 46.651 ;
     RECT  219.204 45.841 219.33 46.651 ;
     RECT  201.456 46.651 219.33 46.741 ;
     RECT  220.104 45.121 220.302 46.741 ;
     RECT  2.304 46.345 9.702 46.813 ;
     RECT  0.54 46.637 0.558 46.843 ;
     RECT  10.8 46.219 10.854 46.921 ;
     RECT  2.232 46.813 9.702 46.987 ;
     RECT  2.232 46.987 9.99 47.011 ;
     RECT  10.8 46.921 11.034 47.011 ;
     RECT  0.468 46.843 0.558 47.035 ;
     RECT  198.864 46.813 198.882 47.047 ;
     RECT  2.232 47.011 11.034 47.069 ;
     RECT  11.772 46.265 197.64 47.083 ;
     RECT  10.836 47.069 11.034 47.119 ;
     RECT  11.772 47.083 197.73 47.119 ;
     RECT  198.864 47.047 198.918 47.155 ;
     RECT  0.396 47.035 0.558 47.165 ;
     RECT  10.836 47.119 197.73 47.219 ;
     RECT  199.908 46.541 200.466 47.281 ;
     RECT  10.836 47.219 11.034 47.309 ;
     RECT  199.836 47.281 200.466 47.309 ;
     RECT  199.836 47.309 200.106 47.453 ;
     RECT  0.396 47.165 0.522 47.515 ;
     RECT  0.216 47.515 0.522 47.563 ;
     RECT  0.144 47.563 0.522 47.615 ;
     RECT  0.18 47.615 0.522 47.723 ;
     RECT  198.792 47.155 198.918 47.731 ;
     RECT  198.792 47.731 198.954 47.789 ;
     RECT  11.772 47.219 197.73 47.821 ;
     RECT  198.792 47.789 198.81 47.821 ;
     RECT  2.232 47.069 10.062 47.851 ;
     RECT  11.772 47.821 198.81 47.885 ;
     RECT  10.836 47.309 10.962 47.947 ;
     RECT  1.512 47.851 10.062 47.957 ;
     RECT  0.216 47.723 0.522 48.029 ;
     RECT  1.692 47.957 10.062 48.077 ;
     RECT  10.8 47.947 10.962 48.091 ;
     RECT  11.772 47.885 198.378 48.091 ;
     RECT  199.908 47.453 200.106 48.235 ;
     RECT  2.232 48.077 10.062 48.271 ;
     RECT  10.8 48.091 198.378 48.271 ;
     RECT  199.908 48.235 200.214 48.272 ;
     RECT  2.232 48.271 198.378 48.317 ;
     RECT  2.232 48.317 9.702 48.389 ;
     RECT  10.836 48.317 198.378 48.389 ;
     RECT  199.908 48.272 200.106 48.667 ;
     RECT  199.872 48.667 200.106 48.811 ;
     RECT  0.504 48.029 0.522 48.973 ;
     RECT  0.504 48.973 1.17 49.037 ;
     RECT  199.512 48.811 200.106 49.195 ;
     RECT  2.232 48.389 9.666 49.207 ;
     RECT  199.512 49.195 200.322 49.235 ;
     RECT  0.504 49.037 0.522 49.315 ;
     RECT  2.232 49.207 9.702 49.441 ;
     RECT  10.836 48.389 198.342 49.441 ;
     RECT  199.512 49.235 200.214 49.469 ;
     RECT  0.108 49.315 0.522 49.517 ;
     RECT  0.324 49.517 0.522 49.819 ;
     RECT  0.324 49.819 0.558 49.867 ;
     RECT  201.456 46.741 220.302 49.964 ;
     RECT  201.456 49.964 220.23 49.997 ;
     RECT  199.512 49.469 200.106 50.093 ;
     RECT  0.324 49.867 0.738 50.189 ;
     RECT  2.232 49.441 198.342 50.189 ;
     RECT  201.456 49.997 220.194 50.189 ;
     RECT  199.872 50.093 200.106 50.284 ;
     RECT  2.232 50.189 197.766 50.395 ;
     RECT  1.728 50.395 197.766 50.477 ;
     RECT  0.324 50.189 0.558 50.491 ;
     RECT  199.872 50.284 200.142 50.521 ;
     RECT  199.872 50.521 200.25 50.635 ;
     RECT  0.144 50.491 0.558 50.669 ;
     RECT  199.872 50.635 200.394 50.693 ;
     RECT  1.728 50.477 197.64 50.729 ;
     RECT  199.872 50.693 200.286 50.827 ;
     RECT  1.728 50.729 9.918 50.861 ;
     RECT  199.548 50.827 200.286 50.923 ;
     RECT  199.512 50.923 200.286 51.205 ;
     RECT  198.9 51.205 200.286 51.367 ;
     RECT  10.692 50.729 197.64 51.499 ;
     RECT  198.396 51.367 200.286 51.499 ;
     RECT  10.692 51.499 200.286 51.511 ;
     RECT  201.456 50.189 220.086 51.595 ;
     RECT  201.456 51.595 220.23 51.665 ;
     RECT  2.304 50.861 9.918 51.691 ;
     RECT  10.692 51.511 200.358 51.701 ;
     RECT  10.692 51.701 200.322 51.725 ;
     RECT  2.232 51.691 9.918 51.781 ;
     RECT  10.692 51.725 197.766 51.781 ;
     RECT  198.9 51.725 200.322 51.821 ;
     RECT  199.476 51.821 200.322 52.109 ;
     RECT  0.324 51.451 0.342 52.177 ;
     RECT  199.476 52.109 200.286 52.205 ;
     RECT  199.872 52.205 200.286 52.313 ;
     RECT  2.232 51.781 197.766 52.447 ;
     RECT  2.232 52.447 198.414 52.555 ;
     RECT  2.196 52.555 198.414 52.925 ;
     RECT  199.872 52.313 200.07 52.973 ;
     RECT  201.456 51.665 202.497 52.979 ;
     RECT  203.256 51.665 220.23 52.979 ;
     RECT  0.108 52.177 0.342 52.987 ;
     RECT  2.232 52.925 198.414 52.987 ;
     RECT  0.108 52.987 0.378 53.117 ;
     RECT  2.232 52.987 198.954 53.165 ;
     RECT  199.908 52.973 200.07 53.323 ;
     RECT  199.908 53.323 200.322 53.393 ;
     RECT  199.908 53.393 200.178 53.549 ;
     RECT  199.908 53.549 200.034 53.699 ;
     RECT  0.108 53.117 0.342 53.933 ;
     RECT  2.232 53.165 198.918 54.029 ;
     RECT  198.9 54.029 198.918 54.067 ;
     RECT  198.9 54.067 198.954 54.103 ;
     RECT  199.872 53.833 199.89 54.103 ;
     RECT  203.256 52.979 220.122 54.103 ;
     RECT  198.9 54.103 199.89 54.317 ;
     RECT  199.44 54.317 199.89 54.413 ;
     RECT  199.512 54.413 199.89 54.445 ;
     RECT  0.108 53.933 0.306 54.605 ;
     RECT  2.232 54.029 197.802 54.841 ;
     RECT  2.232 54.841 198.378 54.913 ;
     RECT  1.728 54.913 198.378 55.147 ;
     RECT  199.512 54.445 200.178 55.147 ;
     RECT  1.728 55.147 200.322 55.211 ;
     RECT  198.9 55.211 200.322 55.373 ;
     RECT  203.256 54.103 220.302 55.409 ;
     RECT  198.9 55.373 198.954 55.469 ;
     RECT  203.256 55.409 218.286 55.469 ;
     RECT  0.288 54.605 0.306 55.517 ;
     RECT  203.256 55.469 218.25 55.553 ;
     RECT  199.872 55.373 200.322 55.565 ;
     RECT  204.264 55.553 218.25 55.565 ;
     RECT  219.456 55.409 220.302 55.955 ;
     RECT  201.456 52.979 201.474 55.985 ;
     RECT  199.872 55.565 200.25 56.129 ;
     RECT  204.264 55.565 217.998 56.129 ;
     RECT  198.9 55.469 198.918 56.237 ;
     RECT  219.456 55.955 219.474 56.299 ;
     RECT  199.872 56.129 200.07 56.335 ;
     RECT  205.2 56.129 217.998 56.371 ;
     RECT  0.108 56.203 0.126 56.395 ;
     RECT  199.476 56.335 200.07 56.399 ;
     RECT  199.476 56.399 199.926 56.525 ;
     RECT  1.728 55.211 197.766 56.533 ;
     RECT  1.728 56.533 198.486 56.635 ;
     RECT  0.108 56.395 0.306 56.779 ;
     RECT  219.42 56.299 219.474 56.875 ;
     RECT  205.2 56.371 218.034 57.037 ;
     RECT  219.384 56.875 219.474 57.037 ;
     RECT  199.872 56.525 199.926 57.145 ;
     RECT  1.152 56.635 198.486 57.149 ;
     RECT  205.2 57.037 219.474 57.209 ;
     RECT  16.632 57.149 198.486 57.307 ;
     RECT  199.872 57.145 200.394 57.335 ;
     RECT  16.632 57.307 198.522 57.442 ;
     RECT  218.88 57.209 219.474 57.485 ;
     RECT  16.632 57.442 198.558 57.541 ;
     RECT  218.88 57.485 219.438 57.569 ;
     RECT  220.212 55.955 220.302 57.641 ;
     RECT  16.632 57.541 198.954 57.685 ;
     RECT  199.872 57.335 200.106 57.685 ;
     RECT  0.108 56.779 0.342 57.713 ;
     RECT  16.632 57.685 200.106 57.773 ;
     RECT  0.144 57.713 0.342 57.835 ;
     RECT  1.152 57.149 15.822 57.835 ;
     RECT  16.632 57.773 198.954 57.869 ;
     RECT  204.336 56.129 204.354 57.979 ;
     RECT  205.2 57.209 217.962 57.979 ;
     RECT  0.144 57.835 15.822 58.061 ;
     RECT  199.872 57.773 200.106 58.081 ;
     RECT  199.872 58.081 200.25 58.157 ;
     RECT  218.88 57.569 218.898 58.219 ;
     RECT  16.776 57.869 198.954 58.253 ;
     RECT  218.844 58.219 218.898 58.315 ;
     RECT  2.304 58.061 15.822 58.495 ;
     RECT  203.256 55.553 203.31 58.559 ;
     RECT  204.336 57.979 217.962 58.559 ;
     RECT  220.212 57.641 220.23 58.603 ;
     RECT  199.872 58.157 200.034 58.651 ;
     RECT  0.144 58.061 1.17 58.657 ;
     RECT  2.304 58.495 15.858 58.699 ;
     RECT  16.776 58.253 198.486 58.699 ;
     RECT  218.844 58.315 219.438 58.699 ;
     RECT  220.176 58.603 220.23 58.699 ;
     RECT  199.332 58.651 200.034 58.927 ;
     RECT  205.2 58.559 217.962 59.071 ;
     RECT  2.304 58.699 198.486 59.161 ;
     RECT  199.332 58.927 200.214 59.161 ;
     RECT  2.304 59.161 200.25 59.213 ;
     RECT  203.292 58.559 203.31 59.225 ;
     RECT  0.108 58.657 1.17 59.309 ;
     RECT  17.568 59.213 200.25 59.309 ;
     RECT  199.476 59.309 200.25 59.341 ;
     RECT  205.2 59.071 218.034 59.611 ;
     RECT  218.844 58.699 220.23 59.611 ;
     RECT  0.144 59.309 1.17 59.639 ;
     RECT  205.2 59.611 220.23 59.639 ;
     RECT  17.568 59.309 198.522 59.684 ;
     RECT  199.476 59.341 200.358 59.729 ;
     RECT  206.1 59.639 220.23 59.729 ;
     RECT  2.304 59.213 16.794 59.789 ;
     RECT  0.144 59.639 0.558 59.837 ;
     RECT  205.2 59.639 205.218 59.837 ;
     RECT  206.1 59.729 219.402 59.999 ;
     RECT  199.476 59.729 200.322 60.107 ;
     RECT  0.144 59.837 0.342 60.125 ;
     RECT  199.476 60.107 199.962 60.461 ;
     RECT  204.336 58.559 204.354 60.523 ;
     RECT  204.336 60.523 204.642 60.653 ;
     RECT  2.304 59.789 16.182 60.655 ;
     RECT  17.568 59.684 198.45 60.701 ;
     RECT  206.1 59.999 219.186 60.781 ;
     RECT  220.14 59.729 220.23 60.781 ;
     RECT  204.336 60.653 204.354 60.845 ;
     RECT  206.1 60.781 220.23 60.893 ;
     RECT  206.1 60.893 206.118 60.925 ;
     RECT  199.872 60.461 199.962 60.953 ;
     RECT  206.892 60.893 220.23 61.037 ;
     RECT  205.74 60.925 206.118 61.079 ;
     RECT  0.18 60.125 0.342 61.099 ;
     RECT  205.74 61.079 205.938 61.147 ;
     RECT  205.488 61.147 205.938 61.187 ;
     RECT  2.268 60.655 16.182 61.231 ;
     RECT  200.232 61.051 200.25 61.259 ;
     RECT  220.176 61.037 220.23 61.259 ;
     RECT  2.268 61.231 16.506 61.277 ;
     RECT  205.704 61.187 205.938 61.349 ;
     RECT  17.784 60.701 198.45 61.357 ;
     RECT  2.304 61.277 16.506 61.421 ;
     RECT  205.74 61.349 205.938 61.457 ;
     RECT  17.784 61.357 198.522 61.574 ;
     RECT  0.18 61.099 0.486 61.579 ;
     RECT  0.18 61.579 0.522 61.591 ;
     RECT  199.476 61.465 199.494 61.699 ;
     RECT  0.18 61.591 0.846 61.709 ;
     RECT  199.476 61.699 200.106 61.709 ;
     RECT  0.18 61.709 0.198 61.757 ;
     RECT  206.892 61.037 219.366 61.771 ;
     RECT  206.892 61.771 219.438 61.799 ;
     RECT  208.8 61.799 219.438 61.889 ;
     RECT  17.784 61.574 198.45 62.005 ;
     RECT  17.28 62.005 198.45 62.159 ;
     RECT  2.304 61.421 16.254 62.239 ;
     RECT  206.892 61.799 207.897 62.311 ;
     RECT  2.304 62.239 16.974 62.429 ;
     RECT  199.98 61.709 200.106 62.473 ;
     RECT  205.74 61.457 205.758 62.545 ;
     RECT  206.64 62.311 207.897 62.545 ;
     RECT  199.98 62.473 200.358 62.671 ;
     RECT  205.74 62.545 207.897 62.671 ;
     RECT  208.8 61.889 219.366 62.671 ;
     RECT  0.144 62.155 0.162 62.683 ;
     RECT  2.304 62.429 16.65 62.699 ;
     RECT  199.476 62.671 200.358 62.699 ;
     RECT  205.74 62.671 219.366 62.699 ;
     RECT  0.144 62.683 0.27 62.743 ;
     RECT  199.476 62.699 200.106 62.765 ;
     RECT  0.108 62.743 0.27 62.813 ;
     RECT  206.64 62.699 219.366 62.923 ;
     RECT  2.304 62.699 16.218 62.969 ;
     RECT  17.784 62.159 198.45 63.041 ;
     RECT  206.64 62.923 219.438 63.049 ;
     RECT  205.74 62.699 205.866 63.113 ;
     RECT  0.108 62.813 0.198 63.245 ;
     RECT  2.304 62.969 15.714 63.247 ;
     RECT  206.64 63.049 219.474 63.307 ;
     RECT  220.212 61.259 220.23 63.307 ;
     RECT  1.728 63.247 15.714 63.437 ;
     RECT  199.8 62.765 200.106 63.517 ;
     RECT  200.916 63.247 200.934 63.517 ;
     RECT  205.812 63.113 205.866 63.589 ;
     RECT  206.64 63.307 220.23 63.589 ;
     RECT  205.812 63.589 220.23 63.653 ;
     RECT  2.232 63.437 15.714 63.821 ;
     RECT  0.108 63.245 0.126 63.851 ;
     RECT  18.54 63.041 198.45 64.193 ;
     RECT  205.812 63.653 209.034 64.201 ;
     RECT  17.784 63.041 17.802 64.267 ;
     RECT  18.54 64.193 198.378 64.267 ;
     RECT  205.704 64.201 209.034 64.291 ;
     RECT  17.784 64.267 198.378 64.319 ;
     RECT  2.232 63.821 14.526 64.349 ;
     RECT  205.452 64.291 209.034 64.349 ;
     RECT  205.812 64.349 209.034 64.391 ;
     RECT  2.232 64.349 13.518 64.427 ;
     RECT  2.232 64.427 13.497 64.589 ;
     RECT  210.06 63.653 220.23 64.597 ;
     RECT  2.232 64.589 12.114 64.637 ;
     RECT  205.884 64.391 209.034 64.669 ;
     RECT  209.844 64.597 220.23 64.669 ;
     RECT  13.104 64.589 13.497 64.877 ;
     RECT  199.8 63.517 200.934 64.939 ;
     RECT  2.232 64.637 12.078 65.129 ;
     RECT  18.54 64.319 198.054 65.245 ;
     RECT  199.188 64.939 200.934 65.245 ;
     RECT  2.304 65.129 12.078 65.501 ;
     RECT  0.144 64.459 0.162 65.509 ;
     RECT  0.144 65.509 0.594 65.515 ;
     RECT  205.884 64.669 220.23 65.515 ;
     RECT  0.108 65.515 0.594 65.549 ;
     RECT  2.304 65.501 11.322 65.549 ;
     RECT  0.108 65.549 0.342 65.552 ;
     RECT  17.784 64.319 17.802 65.563 ;
     RECT  18.54 65.245 200.934 65.563 ;
     RECT  17.784 65.563 200.934 65.669 ;
     RECT  13.215 64.877 13.497 65.755 ;
     RECT  12.168 65.659 12.186 65.939 ;
     RECT  18.54 65.669 200.934 65.983 ;
     RECT  205.632 65.515 220.23 66.019 ;
     RECT  205.632 66.019 220.302 66.055 ;
     RECT  13.032 65.755 13.497 66.077 ;
     RECT  2.304 65.549 11.25 66.091 ;
     RECT  14.364 64.349 14.526 66.187 ;
     RECT  1.692 66.091 11.25 66.283 ;
     RECT  14.364 66.187 14.814 66.317 ;
     RECT  1.692 66.283 11.862 66.389 ;
     RECT  0.144 65.552 0.342 66.475 ;
     RECT  1.692 66.389 11.754 66.479 ;
     RECT  0.108 66.475 0.558 66.515 ;
     RECT  14.364 66.317 14.526 67.019 ;
     RECT  1.692 66.479 10.962 67.127 ;
     RECT  14.436 67.019 14.526 67.135 ;
     RECT  14.436 67.135 14.598 67.181 ;
     RECT  0.144 66.515 0.198 67.243 ;
     RECT  2.304 67.127 10.962 67.261 ;
     RECT  11.736 66.479 11.754 67.261 ;
     RECT  202.215 52.979 202.497 67.333 ;
     RECT  13.215 66.077 13.497 67.369 ;
     RECT  15.696 63.821 15.714 67.397 ;
     RECT  202.215 67.333 203.202 67.405 ;
     RECT  204.336 63.661 204.354 67.405 ;
     RECT  2.304 67.261 11.754 67.483 ;
     RECT  205.452 66.055 220.302 67.675 ;
     RECT  0.144 67.243 0.342 67.915 ;
     RECT  205.416 67.675 220.302 67.981 ;
     RECT  0.144 67.915 0.414 68.045 ;
     RECT  2.304 67.483 12.006 68.059 ;
     RECT  0.144 68.045 0.378 68.071 ;
     RECT  202.215 67.405 204.354 68.179 ;
     RECT  205.308 67.981 220.302 68.179 ;
     RECT  0.108 68.071 0.378 68.333 ;
     RECT  2.304 68.059 12.258 68.341 ;
     RECT  13.068 67.369 13.497 68.341 ;
     RECT  202.215 68.179 220.302 68.369 ;
     RECT  2.304 68.341 13.497 68.381 ;
     RECT  2.304 68.381 11.466 68.405 ;
     RECT  0.18 68.333 0.378 68.717 ;
     RECT  202.215 68.369 219.294 68.819 ;
     RECT  212.076 68.819 219.294 68.945 ;
     RECT  0.18 68.717 0.198 69.067 ;
     RECT  2.304 68.405 11.43 69.211 ;
     RECT  2.304 69.211 11.79 69.215 ;
     RECT  2.34 69.215 11.79 69.295 ;
     RECT  12.636 68.381 13.497 69.295 ;
     RECT  2.34 69.295 13.497 69.307 ;
     RECT  2.34 69.307 13.554 69.331 ;
     RECT  14.436 67.181 14.454 69.331 ;
     RECT  0.108 69.067 0.198 69.359 ;
     RECT  2.34 69.331 14.454 69.719 ;
     RECT  0.144 69.359 0.198 69.727 ;
     RECT  12.42 69.719 14.454 69.799 ;
     RECT  1.152 67.435 1.17 69.863 ;
     RECT  12.42 69.799 14.526 69.997 ;
     RECT  15.624 69.871 15.642 69.997 ;
     RECT  2.34 69.719 11.466 70.123 ;
     RECT  12.42 69.997 15.642 70.295 ;
     RECT  212.112 68.945 219.294 70.331 ;
     RECT  0.144 69.727 0.234 70.411 ;
     RECT  18.54 65.983 200.97 70.439 ;
     RECT  212.256 70.331 219.294 70.439 ;
     RECT  0.144 70.411 0.45 70.603 ;
     RECT  15.84 70.363 15.858 70.637 ;
     RECT  0.144 70.603 0.882 70.645 ;
     RECT  0.144 70.645 1.206 70.685 ;
     RECT  12.42 70.295 14.454 70.843 ;
     RECT  220.068 68.369 220.302 70.871 ;
     RECT  2.304 70.123 11.466 70.891 ;
     RECT  12.348 70.843 14.454 70.891 ;
     RECT  212.256 70.439 219.222 70.979 ;
     RECT  2.304 70.891 14.454 71.221 ;
     RECT  0.144 70.685 0.882 71.261 ;
     RECT  2.304 71.221 14.778 71.275 ;
     RECT  2.232 71.275 14.778 71.371 ;
     RECT  15.66 71.347 15.678 71.371 ;
     RECT  0.504 71.261 0.882 71.419 ;
     RECT  2.232 71.371 15.678 71.453 ;
     RECT  2.304 71.453 15.678 71.491 ;
     RECT  212.256 70.979 218.646 71.519 ;
     RECT  0.504 71.419 1.278 71.693 ;
     RECT  2.304 71.491 15.894 72.031 ;
     RECT  0.504 71.693 1.17 72.043 ;
     RECT  2.304 72.031 16.002 72.149 ;
     RECT  214.236 71.519 218.646 72.221 ;
     RECT  0.324 72.043 1.17 72.235 ;
     RECT  2.304 72.149 15.75 72.235 ;
     RECT  0.216 72.235 1.17 72.455 ;
     RECT  216.108 72.221 218.646 72.491 ;
     RECT  0.216 72.455 0.558 72.523 ;
     RECT  0.108 72.523 0.558 72.527 ;
     RECT  220.284 70.871 220.302 72.527 ;
     RECT  214.236 72.221 215.37 72.689 ;
     RECT  216.324 72.491 218.646 72.689 ;
     RECT  216.432 72.689 217.818 72.725 ;
     RECT  214.74 72.689 215.37 72.761 ;
     RECT  216.432 72.725 217.782 72.797 ;
     RECT  218.628 72.689 218.646 72.797 ;
     RECT  214.74 72.761 214.758 72.869 ;
     RECT  2.232 72.235 15.75 72.959 ;
     RECT  217.332 72.797 217.782 72.959 ;
     RECT  2.232 72.959 14.382 73.003 ;
     RECT  0.108 72.527 0.234 73.133 ;
     RECT  2.196 73.003 14.382 73.139 ;
     RECT  13.104 73.139 14.382 73.229 ;
     RECT  15.3 72.959 15.426 73.229 ;
     RECT  0.144 73.133 0.234 73.277 ;
     RECT  15.408 73.229 15.426 73.325 ;
     RECT  0.144 73.277 0.198 73.373 ;
     RECT  2.196 73.139 12.078 73.381 ;
     RECT  2.16 73.381 12.078 73.409 ;
     RECT  2.16 73.409 12.042 73.499 ;
     RECT  2.16 73.499 11.97 73.607 ;
     RECT  2.16 73.607 11.79 73.661 ;
     RECT  13.104 73.229 14.166 73.661 ;
     RECT  11.772 73.661 11.79 73.769 ;
     RECT  13.215 73.661 14.166 73.769 ;
     RECT  2.16 73.661 10.926 73.841 ;
     RECT  10.836 73.841 10.854 74.285 ;
     RECT  2.16 73.841 9.954 74.333 ;
     RECT  0.144 73.373 0.162 74.615 ;
     RECT  9.936 74.333 9.954 74.621 ;
     RECT  2.16 74.333 9.162 75.067 ;
     RECT  2.16 75.067 9.702 75.119 ;
     RECT  10.836 75.259 10.854 75.485 ;
     RECT  13.215 73.769 13.497 75.631 ;
     RECT  215.46 74.923 215.478 75.659 ;
     RECT  13.104 75.631 13.497 75.677 ;
     RECT  2.232 75.119 9.522 75.929 ;
     RECT  2.232 75.929 8.874 76.171 ;
     RECT  2.196 76.171 8.874 76.199 ;
     RECT  212.256 71.519 213.297 76.199 ;
     RECT  2.196 76.199 8.694 76.235 ;
     RECT  2.232 76.235 8.694 76.469 ;
     RECT  2.232 76.469 8.19 76.784 ;
     RECT  10.8 77.275 10.818 77.405 ;
     RECT  2.232 76.784 8.097 77.549 ;
     RECT  2.268 77.549 8.097 77.597 ;
     RECT  2.268 77.597 7.002 78.092 ;
     RECT  2.304 78.092 7.002 78.667 ;
     RECT  7.815 77.597 8.097 78.667 ;
     RECT  2.304 78.667 8.097 78.859 ;
     RECT  2.268 78.859 8.097 78.899 ;
     RECT  2.268 78.899 6.066 78.935 ;
     RECT  2.304 78.935 6.066 79.169 ;
     RECT  6.84 78.899 6.858 79.181 ;
     RECT  2.304 79.169 5.274 79.439 ;
     RECT  6.048 79.169 6.066 79.439 ;
     RECT  2.304 79.439 5.13 79.517 ;
     RECT  2.304 79.517 4.842 79.745 ;
     RECT  2.415 79.745 4.842 79.979 ;
     RECT  2.415 79.979 4.482 79.997 ;
     RECT  2.415 79.997 4.05 80.159 ;
     RECT  2.415 80.159 3.474 80.249 ;
     RECT  2.415 80.249 3.294 80.285 ;
     RECT  216.036 76.315 216.054 87.211 ;
     RECT  212.472 76.199 213.297 87.385 ;
     RECT  216.036 87.211 216.378 87.539 ;
     RECT  202.215 68.819 211.338 89.771 ;
     RECT  212.472 87.385 213.498 91.771 ;
     RECT  212.472 91.771 213.786 92.245 ;
     RECT  212.472 92.245 214.47 92.309 ;
     RECT  18.615 70.439 200.97 94.248 ;
     RECT  212.472 92.309 213.498 94.361 ;
     RECT  214.452 92.309 214.47 94.937 ;
     RECT  197.496 94.248 200.97 95.009 ;
     RECT  197.496 95.009 200.934 95.477 ;
     RECT  108.72 94.981 108.738 95.566 ;
     RECT  210.204 89.771 211.338 95.675 ;
     RECT  18.615 94.248 23.094 95.711 ;
     RECT  20.124 95.711 23.094 96.053 ;
     RECT  202.215 89.771 209.466 96.053 ;
     RECT  206.856 96.053 209.466 96.179 ;
     RECT  210.204 95.675 210.582 96.251 ;
     RECT  45.612 96.223 45.63 96.259 ;
     RECT  197.496 95.477 200.394 96.287 ;
     RECT  44.892 96.259 45.63 96.373 ;
     RECT  55.872 95.647 55.89 96.373 ;
     RECT  56.736 96.331 56.754 96.373 ;
     RECT  62.748 96.151 62.766 96.373 ;
     RECT  67.14 95.449 67.158 96.373 ;
     RECT  78.66 95.026 78.678 96.373 ;
     RECT  88.416 94.248 88.434 96.373 ;
     RECT  94.356 95.521 94.374 96.373 ;
     RECT  100.26 95.485 100.53 96.373 ;
     RECT  104.94 94.248 104.958 96.373 ;
     RECT  116.244 94.248 116.262 96.373 ;
     RECT  122.004 95.611 122.022 96.373 ;
     RECT  175.788 95.026 175.806 96.373 ;
     RECT  197.496 96.287 199.782 96.373 ;
     RECT  44.892 96.373 45.897 96.421 ;
     RECT  63.684 96.025 63.702 96.421 ;
     RECT  67.14 96.373 67.497 96.421 ;
     RECT  83.607 96.373 83.697 96.421 ;
     RECT  114.552 96.061 114.57 96.421 ;
     RECT  121.407 96.373 122.022 96.427 ;
     RECT  44.892 96.421 46.206 96.449 ;
     RECT  63.684 96.421 64.026 96.449 ;
     RECT  67.14 96.421 67.554 96.449 ;
     RECT  74.124 95.071 74.142 96.449 ;
     RECT  86.616 95.449 86.634 96.449 ;
     RECT  90.072 94.248 90.09 96.449 ;
     RECT  92.412 94.248 92.43 96.449 ;
     RECT  96.516 96.025 96.534 96.449 ;
     RECT  104.94 96.373 105.297 96.449 ;
     RECT  106.344 95.521 106.362 96.449 ;
     RECT  107.172 94.248 107.19 96.449 ;
     RECT  114.48 96.421 114.57 96.449 ;
     RECT  117.684 95.566 117.702 96.449 ;
     RECT  121.32 96.427 122.022 96.449 ;
     RECT  145.44 96.151 145.458 96.449 ;
     RECT  175.407 96.373 175.806 96.449 ;
     RECT  78.207 96.373 78.678 96.457 ;
     RECT  43.128 95.419 43.146 96.485 ;
     RECT  51.207 96.373 51.297 96.493 ;
     RECT  53.748 95.683 53.766 96.493 ;
     RECT  54.72 96.331 54.738 96.493 ;
     RECT  110.607 96.373 110.697 96.493 ;
     RECT  116.007 96.373 116.262 96.493 ;
     RECT  20.196 96.053 23.094 96.523 ;
     RECT  53.748 96.493 54.738 96.529 ;
     RECT  26.748 96.427 26.766 96.557 ;
     RECT  113.436 96.061 113.454 96.557 ;
     RECT  114.48 96.449 114.498 96.557 ;
     RECT  216.036 87.539 216.054 96.557 ;
     RECT  82.62 96.457 82.638 96.565 ;
     RECT  197.007 96.373 199.782 96.593 ;
     RECT  94.356 96.373 94.497 96.601 ;
     RECT  103.932 96.187 103.95 96.601 ;
     RECT  110.592 96.493 110.697 96.601 ;
     RECT  116.007 96.493 116.946 96.601 ;
     RECT  20.196 96.523 23.346 96.629 ;
     RECT  53.748 96.529 54.81 96.629 ;
     RECT  24.207 96.373 24.297 96.643 ;
     RECT  29.607 96.373 29.697 96.643 ;
     RECT  35.007 96.373 35.097 96.643 ;
     RECT  40.407 96.373 40.497 96.643 ;
     RECT  62.007 96.373 62.766 96.643 ;
     RECT  72.807 96.373 72.897 96.643 ;
     RECT  78.207 96.457 78.786 96.643 ;
     RECT  83.607 96.421 83.79 96.643 ;
     RECT  94.356 96.601 95.418 96.643 ;
     RECT  99.807 96.373 100.53 96.643 ;
     RECT  110.592 96.601 110.754 96.643 ;
     RECT  121.32 96.449 121.497 96.643 ;
     RECT  126.807 96.373 126.897 96.643 ;
     RECT  132.207 96.373 132.297 96.643 ;
     RECT  137.607 96.373 137.697 96.643 ;
     RECT  143.007 96.373 143.097 96.643 ;
     RECT  148.407 96.373 148.497 96.643 ;
     RECT  153.807 96.373 153.897 96.643 ;
     RECT  159.207 96.373 159.297 96.643 ;
     RECT  164.607 96.373 164.697 96.643 ;
     RECT  170.007 96.373 170.097 96.643 ;
     RECT  175.407 96.449 175.554 96.643 ;
     RECT  180.807 96.373 180.897 96.643 ;
     RECT  186.207 96.373 186.297 96.643 ;
     RECT  191.607 96.373 191.697 96.643 ;
     RECT  197.007 96.593 197.097 96.643 ;
     RECT  48.024 95.719 48.042 96.691 ;
     RECT  58.752 96.457 58.77 96.691 ;
     RECT  61.815 96.643 62.766 96.691 ;
     RECT  88.416 96.373 89.097 96.691 ;
     RECT  108.036 95.566 108.738 96.715 ;
     RECT  109.584 96.601 109.674 96.715 ;
     RECT  48.024 96.691 48.366 96.719 ;
     RECT  52.776 96.187 52.794 96.719 ;
     RECT  53.748 96.629 54.306 96.719 ;
     RECT  55.872 96.373 56.754 96.719 ;
     RECT  81.504 94.981 81.522 96.719 ;
     RECT  56.088 96.719 56.754 96.727 ;
     RECT  108.036 96.715 109.674 96.755 ;
     RECT  58.716 96.691 58.77 96.763 ;
     RECT  82.584 96.565 82.638 96.763 ;
     RECT  86.652 96.529 86.742 96.763 ;
     RECT  50.724 96.493 51.297 96.791 ;
     RECT  54.072 96.719 54.306 96.791 ;
     RECT  61.815 96.691 63.126 96.791 ;
     RECT  82.548 96.763 82.638 96.791 ;
     RECT  109.584 96.755 109.674 96.791 ;
     RECT  115.416 96.601 116.946 96.791 ;
     RECT  78.015 96.643 78.786 96.797 ;
     RECT  50.796 96.791 51.297 96.863 ;
     RECT  58.716 96.763 58.842 96.863 ;
     RECT  61.815 96.791 62.154 96.863 ;
     RECT  78.015 96.797 78.75 96.863 ;
     RECT  86.652 96.763 86.814 96.863 ;
     RECT  110.415 96.643 110.754 96.863 ;
     RECT  61.815 96.863 62.097 96.871 ;
     RECT  82.548 96.791 82.602 96.871 ;
     RECT  20.196 96.629 22.878 96.893 ;
     RECT  50.868 96.863 51.297 96.899 ;
     RECT  54.072 96.791 54.234 96.899 ;
     RECT  58.716 96.863 58.734 96.899 ;
     RECT  63.036 96.791 63.126 96.899 ;
     RECT  78.015 96.863 78.714 96.899 ;
     RECT  82.476 96.871 82.602 96.899 ;
     RECT  86.652 96.863 86.67 96.899 ;
     RECT  88.416 96.691 89.154 96.899 ;
     RECT  103.752 96.601 104.13 96.899 ;
     RECT  109.584 96.791 109.602 96.989 ;
     RECT  61.74 96.871 62.097 97.025 ;
     RECT  56.088 96.727 57.222 97.061 ;
     RECT  102.6 96.601 102.618 97.141 ;
     RECT  94.215 96.643 95.418 97.267 ;
     RECT  101.916 97.141 102.618 97.529 ;
     RECT  92.16 96.565 92.178 97.565 ;
     RECT  115.416 96.791 116.298 97.565 ;
     RECT  83.415 96.643 83.79 97.601 ;
     RECT  175.215 96.643 175.554 97.601 ;
     RECT  99.615 96.643 100.53 97.771 ;
     RECT  17.784 65.669 17.802 98.069 ;
     RECT  102.6 97.529 102.618 98.069 ;
     RECT  88.416 96.899 89.097 98.105 ;
     RECT  110.415 96.863 110.697 98.221 ;
     RECT  202.215 96.053 206.046 98.249 ;
     RECT  79.992 96.871 80.01 98.311 ;
     RECT  18.615 95.711 19.17 98.339 ;
     RECT  110.124 98.221 110.697 98.339 ;
     RECT  103.752 96.899 103.77 98.491 ;
     RECT  108.036 96.755 108.738 98.491 ;
     RECT  202.215 98.249 205.47 98.609 ;
     RECT  115.815 97.565 116.298 98.645 ;
     RECT  18.615 98.339 18.954 98.915 ;
     RECT  94.215 97.267 95.454 98.915 ;
     RECT  88.74 98.105 89.097 98.923 ;
     RECT  207.036 96.179 209.466 99.149 ;
     RECT  88.74 98.923 89.766 99.185 ;
     RECT  103.752 98.491 104.022 99.221 ;
     RECT  20.196 96.893 22.518 99.419 ;
     RECT  99.576 97.771 100.53 99.463 ;
     RECT  207.036 99.149 208.926 99.491 ;
     RECT  22.5 99.419 22.518 99.571 ;
     RECT  22.5 99.571 22.77 99.725 ;
     RECT  20.196 99.419 21.582 99.739 ;
     RECT  210.348 96.251 210.582 99.959 ;
     RECT  91.116 96.601 91.134 99.995 ;
     RECT  19.692 99.739 21.582 100.229 ;
     RECT  96.588 96.961 96.606 100.499 ;
     RECT  22.5 99.725 22.518 100.535 ;
     RECT  20.196 100.229 21.582 100.741 ;
     RECT  20.196 100.741 22.23 100.781 ;
     RECT  210.564 99.959 210.582 101.039 ;
     RECT  88.776 99.185 89.766 101.075 ;
     RECT  81.72 98.887 81.738 101.155 ;
     RECT  82.476 96.899 82.494 101.155 ;
     RECT  20.196 100.781 21.582 101.183 ;
     RECT  69.3 96.565 69.318 101.615 ;
     RECT  21.384 101.183 21.582 101.759 ;
     RECT  212.472 94.361 213.297 101.759 ;
     RECT  21.384 101.759 21.402 101.849 ;
     RECT  20.196 101.183 20.286 101.992 ;
     RECT  20.196 101.992 20.466 102.029 ;
     RECT  211.32 95.675 211.338 102.119 ;
     RECT  79.992 98.311 80.082 102.155 ;
     RECT  81.72 101.155 82.494 102.191 ;
     RECT  164.415 96.643 164.697 103.351 ;
     RECT  75.348 96.565 75.366 103.379 ;
     RECT  144.396 95.647 144.414 103.469 ;
     RECT  202.215 98.609 205.074 103.469 ;
     RECT  53.1 96.871 53.226 103.505 ;
     RECT  164.34 103.351 164.697 103.505 ;
     RECT  156.168 96.223 156.186 103.739 ;
     RECT  67.215 96.449 67.554 103.775 ;
     RECT  63.036 96.899 63.054 104.045 ;
     RECT  83.415 97.601 83.697 104.539 ;
     RECT  198.036 96.593 199.782 104.549 ;
     RECT  118.116 104.539 118.134 104.557 ;
     RECT  117 104.521 117.018 104.573 ;
     RECT  20.196 102.029 20.214 104.585 ;
     RECT  83.415 104.539 83.898 104.585 ;
     RECT  88.815 101.075 89.766 104.585 ;
     RECT  118.116 104.557 118.206 104.585 ;
     RECT  114.588 104.557 114.606 104.657 ;
     RECT  118.188 104.585 118.206 104.657 ;
     RECT  99.576 99.463 101.178 104.819 ;
     RECT  99.576 104.819 100.278 104.855 ;
     RECT  202.215 103.469 203.85 105.233 ;
     RECT  150.876 97.771 150.894 105.241 ;
     RECT  64.008 96.449 64.026 105.269 ;
     RECT  20.268 104.875 20.286 105.331 ;
     RECT  20.268 105.331 20.466 105.359 ;
     RECT  150.732 105.241 150.894 105.359 ;
     RECT  108.036 98.491 109.026 105.395 ;
     RECT  150.732 105.359 150.75 105.395 ;
     RECT  20.448 105.359 20.466 105.437 ;
     RECT  134.964 95.071 134.982 105.511 ;
     RECT  53.1 103.505 53.118 105.539 ;
     RECT  207.18 99.491 208.926 105.539 ;
     RECT  203.76 105.233 203.85 105.629 ;
     RECT  121.215 96.643 121.497 105.637 ;
     RECT  120.924 105.637 121.497 105.677 ;
     RECT  132.015 96.643 132.297 105.781 ;
     RECT  45.216 96.449 46.206 105.809 ;
     RECT  138.528 105.511 138.546 105.809 ;
     RECT  95.436 98.915 95.454 105.899 ;
     RECT  208.908 105.539 208.926 105.899 ;
     RECT  77.184 101.821 77.202 105.935 ;
     RECT  131.58 105.781 132.297 105.935 ;
     RECT  92.7 101.731 92.718 106.027 ;
     RECT  48.348 96.719 48.366 106.043 ;
     RECT  199.188 104.549 199.782 106.043 ;
     RECT  54.072 96.899 54.09 106.079 ;
     RECT  92.7 106.027 92.97 106.169 ;
     RECT  134.532 105.511 134.982 106.169 ;
     RECT  138.564 106.015 138.582 106.169 ;
     RECT  137.415 96.643 137.697 106.177 ;
     RECT  92.7 106.169 92.718 106.205 ;
     RECT  134.532 106.169 134.73 106.205 ;
     RECT  207.18 105.539 207.897 106.205 ;
     RECT  111.996 106.177 112.014 106.213 ;
     RECT  111.744 106.213 112.014 106.253 ;
     RECT  130.536 106.177 130.554 106.277 ;
     RECT  137.415 106.177 137.718 106.277 ;
     RECT  134.532 106.205 134.55 106.313 ;
     RECT  111.996 106.253 112.014 106.349 ;
     RECT  203.76 105.629 203.778 106.439 ;
     RECT  56.415 97.061 57.222 106.475 ;
     RECT  104.004 99.221 104.022 106.619 ;
     RECT  107.172 98.761 107.19 106.709 ;
     RECT  205.056 103.469 205.074 106.709 ;
     RECT  81.72 102.191 82.458 106.745 ;
     RECT  78.015 96.899 78.297 106.753 ;
     RECT  45.615 105.809 46.206 106.781 ;
     RECT  78.015 106.753 78.678 106.853 ;
     RECT  82.512 106.753 82.53 106.853 ;
     RECT  101.16 104.819 101.178 107.249 ;
     RECT  108.72 105.395 109.026 107.257 ;
     RECT  80.064 102.155 80.082 107.285 ;
     RECT  99.576 104.855 99.897 107.285 ;
     RECT  108.468 107.257 109.026 107.309 ;
     RECT  109.008 107.309 109.026 107.393 ;
     RECT  106.668 107.293 106.686 107.401 ;
     RECT  198.036 104.549 198.054 107.429 ;
     RECT  106.38 107.401 106.686 107.515 ;
     RECT  199.188 106.043 199.242 107.519 ;
     RECT  106.128 107.515 106.686 107.527 ;
     RECT  106.128 107.527 106.866 107.555 ;
     RECT  106.848 107.555 106.866 107.597 ;
     RECT  199.224 107.519 199.242 107.789 ;
     RECT  107.64 107.896 107.658 107.933 ;
     RECT  24.015 96.643 24.297 108.031 ;
     RECT  34.815 96.643 35.097 108.031 ;
     RECT  45.615 106.781 45.897 108.031 ;
     RECT  56.415 106.475 56.697 108.031 ;
     RECT  67.215 103.775 67.497 108.031 ;
     RECT  78.015 106.853 78.297 108.031 ;
     RECT  88.815 104.585 89.097 108.031 ;
     RECT  99.615 107.285 99.897 108.031 ;
     RECT  19.692 107.755 19.71 108.059 ;
     RECT  20.484 108.031 20.502 108.077 ;
     RECT  23.904 108.031 24.297 108.077 ;
     RECT  34.704 108.031 35.097 108.077 ;
     RECT  45.504 108.031 45.897 108.077 ;
     RECT  56.304 108.031 56.697 108.077 ;
     RECT  67.104 108.031 67.497 108.077 ;
     RECT  77.904 108.031 78.297 108.077 ;
     RECT  88.704 108.031 89.097 108.077 ;
     RECT  99.504 108.031 99.897 108.077 ;
     RECT  102.6 107.899 102.618 108.077 ;
     RECT  2.415 80.285 2.697 114.227 ;
     RECT  7.815 78.899 8.097 114.227 ;
     RECT  13.215 75.677 13.497 114.227 ;
     RECT  18.615 98.915 18.897 114.227 ;
     RECT  24.015 108.077 24.297 114.227 ;
     RECT  29.415 96.643 29.697 114.227 ;
     RECT  34.815 108.077 35.097 114.227 ;
     RECT  40.215 96.643 40.497 114.227 ;
     RECT  45.615 108.077 45.897 114.227 ;
     RECT  51.015 96.899 51.297 114.227 ;
     RECT  56.415 108.077 56.697 114.227 ;
     RECT  61.815 97.025 62.097 114.227 ;
     RECT  67.215 108.077 67.497 114.227 ;
     RECT  72.615 96.643 72.897 114.227 ;
     RECT  78.015 108.077 78.297 114.227 ;
     RECT  83.415 104.585 83.697 114.227 ;
     RECT  88.815 108.077 89.097 114.227 ;
     RECT  94.215 98.915 94.497 114.227 ;
     RECT  99.615 108.077 99.897 114.227 ;
     RECT  105.015 96.449 105.297 114.227 ;
     RECT  110.415 98.339 110.697 114.227 ;
     RECT  115.815 98.645 116.097 114.227 ;
     RECT  121.215 105.677 121.497 114.227 ;
     RECT  126.615 96.643 126.897 114.227 ;
     RECT  132.015 105.935 132.297 114.227 ;
     RECT  137.415 106.277 137.697 114.227 ;
     RECT  142.815 96.643 143.097 114.227 ;
     RECT  148.215 96.643 148.497 114.227 ;
     RECT  153.615 96.643 153.897 114.227 ;
     RECT  159.015 96.643 159.297 114.227 ;
     RECT  164.415 103.505 164.697 114.227 ;
     RECT  169.815 96.643 170.097 114.227 ;
     RECT  175.215 97.601 175.497 114.227 ;
     RECT  180.615 96.643 180.897 114.227 ;
     RECT  186.015 96.643 186.297 114.227 ;
     RECT  191.415 96.643 191.697 114.227 ;
     RECT  196.815 96.643 197.097 114.227 ;
     RECT  202.215 105.233 202.497 114.227 ;
     RECT  207.615 106.205 207.897 114.227 ;
     RECT  213.015 101.759 213.297 114.227 ;
     RECT  2.415 114.227 2.505 114.497 ;
     RECT  7.815 114.227 7.905 114.497 ;
     RECT  13.215 114.227 13.305 114.497 ;
     RECT  18.615 114.227 18.705 114.497 ;
     RECT  24.015 114.227 24.105 114.497 ;
     RECT  29.415 114.227 29.505 114.497 ;
     RECT  34.815 114.227 34.905 114.497 ;
     RECT  40.215 114.227 40.305 114.497 ;
     RECT  45.615 114.227 45.705 114.497 ;
     RECT  51.015 114.227 51.105 114.497 ;
     RECT  56.415 114.227 56.505 114.497 ;
     RECT  61.815 114.227 61.905 114.497 ;
     RECT  67.215 114.227 67.305 114.497 ;
     RECT  72.615 114.227 72.705 114.497 ;
     RECT  78.015 114.227 78.105 114.497 ;
     RECT  83.415 114.227 83.505 114.497 ;
     RECT  88.815 114.227 88.905 114.497 ;
     RECT  94.215 114.227 94.305 114.497 ;
     RECT  99.615 114.227 99.705 114.497 ;
     RECT  105.015 114.227 105.105 114.497 ;
     RECT  110.415 114.227 110.505 114.497 ;
     RECT  115.815 114.227 115.905 114.497 ;
     RECT  121.215 114.227 121.305 114.497 ;
     RECT  126.615 114.227 126.705 114.497 ;
     RECT  132.015 114.227 132.105 114.497 ;
     RECT  137.415 114.227 137.505 114.497 ;
     RECT  142.815 114.227 142.905 114.497 ;
     RECT  148.215 114.227 148.305 114.497 ;
     RECT  153.615 114.227 153.705 114.497 ;
     RECT  159.015 114.227 159.105 114.497 ;
     RECT  164.415 114.227 164.505 114.497 ;
     RECT  169.815 114.227 169.905 114.497 ;
     RECT  175.215 114.227 175.305 114.497 ;
     RECT  180.615 114.227 180.705 114.497 ;
     RECT  186.015 114.227 186.105 114.497 ;
     RECT  191.415 114.227 191.505 114.497 ;
     RECT  196.815 114.227 196.905 114.497 ;
     RECT  202.215 114.227 202.305 114.497 ;
     RECT  207.615 114.227 207.705 114.497 ;
     RECT  213.015 114.227 213.105 114.497 ;
    LAYER M4 ;
     RECT  0.037 73.344 0.06 73.368 ;
     RECT  0.084 43.632 0.133 43.656 ;
     RECT  0.06 43.656 0.133 43.728 ;
     RECT  0.084 43.728 0.133 43.752 ;
     RECT  0.06 43.752 0.133 43.824 ;
     RECT  0.084 43.824 0.133 43.848 ;
     RECT  0.06 43.848 0.133 43.92 ;
     RECT  0.084 43.92 0.133 43.944 ;
     RECT  0.06 43.944 0.133 44.016 ;
     RECT  0.084 44.016 0.133 44.04 ;
     RECT  0.06 44.04 0.133 44.112 ;
     RECT  0.084 44.112 0.133 44.136 ;
     RECT  0.06 44.136 0.133 44.208 ;
     RECT  0.084 44.208 0.133 44.232 ;
     RECT  0.06 44.232 0.133 44.304 ;
     RECT  0.084 44.304 0.133 44.328 ;
     RECT  0.06 44.328 0.133 44.4 ;
     RECT  0.084 44.4 0.133 44.424 ;
     RECT  0.06 44.424 0.133 44.496 ;
     RECT  0.084 44.496 0.133 44.52 ;
     RECT  0.06 44.52 0.133 44.592 ;
     RECT  0.084 44.592 0.133 44.616 ;
     RECT  0.06 44.616 0.133 44.688 ;
     RECT  0.084 44.688 0.133 44.712 ;
     RECT  0.06 44.712 0.133 44.784 ;
     RECT  0.084 44.784 0.133 44.808 ;
     RECT  0.06 44.808 0.133 44.88 ;
     RECT  0.084 44.88 0.133 44.904 ;
     RECT  0.06 44.904 0.133 44.976 ;
     RECT  0.084 44.976 0.133 45 ;
     RECT  0.06 45 0.133 45.072 ;
     RECT  0.084 45.072 0.133 45.096 ;
     RECT  0.06 45.096 0.133 45.168 ;
     RECT  0.084 45.168 0.133 45.192 ;
     RECT  0.06 45.192 0.133 45.264 ;
     RECT  0.084 45.264 0.133 45.288 ;
     RECT  0.06 45.288 0.133 45.36 ;
     RECT  0.084 45.36 0.133 45.384 ;
     RECT  0.06 45.384 0.133 45.456 ;
     RECT  0.084 45.456 0.133 45.48 ;
     RECT  0.06 45.48 0.133 45.552 ;
     RECT  0.084 45.552 0.133 45.576 ;
     RECT  0.06 45.576 0.133 45.648 ;
     RECT  0.084 45.648 0.133 45.672 ;
     RECT  0.06 45.672 0.133 45.744 ;
     RECT  0.084 45.744 0.133 45.768 ;
     RECT  0.06 45.768 0.133 45.84 ;
     RECT  0.084 45.84 0.133 45.864 ;
     RECT  0.06 45.864 0.133 45.936 ;
     RECT  0.084 45.936 0.133 45.96 ;
     RECT  0.06 45.96 0.133 46.032 ;
     RECT  0.084 46.032 0.133 46.056 ;
     RECT  0.06 46.056 0.133 46.128 ;
     RECT  0.084 46.128 0.133 46.152 ;
     RECT  0.06 46.152 0.133 46.224 ;
     RECT  0.084 46.224 0.133 46.248 ;
     RECT  0.06 46.248 0.133 46.32 ;
     RECT  0.084 46.32 0.133 46.344 ;
     RECT  0.06 46.344 0.133 46.416 ;
     RECT  0.084 46.416 0.133 46.44 ;
     RECT  0.06 46.44 0.133 46.512 ;
     RECT  0.084 46.512 0.133 46.536 ;
     RECT  0.06 46.536 0.133 46.608 ;
     RECT  0.084 46.608 0.133 46.632 ;
     RECT  0.06 46.632 0.133 46.704 ;
     RECT  0.084 46.704 0.133 46.728 ;
     RECT  0.06 46.728 0.133 46.8 ;
     RECT  0.084 46.8 0.133 46.824 ;
     RECT  0.06 46.824 0.133 46.896 ;
     RECT  0.084 46.896 0.133 46.92 ;
     RECT  0.06 46.92 0.133 46.992 ;
     RECT  0.084 46.992 0.133 47.016 ;
     RECT  0.06 47.016 0.133 47.088 ;
     RECT  0.084 47.088 0.133 47.112 ;
     RECT  0.06 47.112 0.133 47.184 ;
     RECT  0.084 47.184 0.133 47.208 ;
     RECT  0.06 47.208 0.133 47.28 ;
     RECT  0.084 47.28 0.133 47.304 ;
     RECT  0.06 47.304 0.133 47.376 ;
     RECT  0.084 47.376 0.133 47.4 ;
     RECT  0.06 47.4 0.133 47.472 ;
     RECT  0.084 47.472 0.133 47.496 ;
     RECT  0.06 47.496 0.133 47.568 ;
     RECT  0.084 47.568 0.133 47.592 ;
     RECT  0.06 47.592 0.133 47.664 ;
     RECT  0.084 47.664 0.133 47.688 ;
     RECT  0.06 47.688 0.133 47.76 ;
     RECT  0.084 47.76 0.133 47.784 ;
     RECT  0.06 47.784 0.133 47.856 ;
     RECT  0.084 47.856 0.133 47.88 ;
     RECT  0.06 47.88 0.133 47.952 ;
     RECT  0.084 47.952 0.133 47.976 ;
     RECT  0.06 47.976 0.133 48.048 ;
     RECT  0.084 48.048 0.133 48.072 ;
     RECT  0.06 48.072 0.133 48.144 ;
     RECT  0.084 48.144 0.133 48.168 ;
     RECT  0.06 48.168 0.133 48.24 ;
     RECT  0.084 48.24 0.133 48.264 ;
     RECT  0.06 48.264 0.133 48.336 ;
     RECT  0.084 48.336 0.133 48.36 ;
     RECT  0.06 48.36 0.133 48.432 ;
     RECT  0.084 48.432 0.133 48.456 ;
     RECT  0.06 48.456 0.133 48.528 ;
     RECT  0.084 48.528 0.133 48.552 ;
     RECT  0.06 48.552 0.133 48.624 ;
     RECT  0.084 48.624 0.133 48.648 ;
     RECT  0.06 48.648 0.133 48.72 ;
     RECT  0.084 48.72 0.133 48.744 ;
     RECT  0.06 48.744 0.133 48.816 ;
     RECT  0.084 48.816 0.133 48.84 ;
     RECT  0.06 48.84 0.133 48.912 ;
     RECT  0.084 48.912 0.133 48.936 ;
     RECT  0.06 48.936 0.133 49.008 ;
     RECT  0.084 49.008 0.133 49.032 ;
     RECT  0.06 49.032 0.133 49.104 ;
     RECT  0.084 49.104 0.133 49.128 ;
     RECT  0.06 49.128 0.133 49.2 ;
     RECT  0.084 49.2 0.133 49.224 ;
     RECT  0.06 49.224 0.133 49.296 ;
     RECT  0.084 49.296 0.133 49.32 ;
     RECT  0.06 49.32 0.133 49.392 ;
     RECT  0.084 49.392 0.133 49.416 ;
     RECT  0.06 49.416 0.133 49.488 ;
     RECT  0.084 49.488 0.133 49.512 ;
     RECT  0.06 49.512 0.133 49.584 ;
     RECT  0.084 49.584 0.133 49.608 ;
     RECT  0.06 49.608 0.133 49.68 ;
     RECT  0.084 49.68 0.133 49.704 ;
     RECT  0.06 49.704 0.133 49.776 ;
     RECT  0.084 49.776 0.133 49.8 ;
     RECT  0.06 49.8 0.133 49.872 ;
     RECT  0.084 49.872 0.133 49.896 ;
     RECT  0.06 49.896 0.133 49.968 ;
     RECT  0.084 49.968 0.133 49.992 ;
     RECT  0.06 49.992 0.133 50.064 ;
     RECT  0.084 50.064 0.133 50.088 ;
     RECT  0.06 50.088 0.133 50.16 ;
     RECT  0.084 50.16 0.133 50.184 ;
     RECT  0.06 50.184 0.133 50.256 ;
     RECT  0.084 50.256 0.133 50.28 ;
     RECT  0.06 50.28 0.133 50.352 ;
     RECT  0.084 50.352 0.133 50.376 ;
     RECT  0.06 50.376 0.133 50.448 ;
     RECT  0.084 50.448 0.133 50.472 ;
     RECT  0.06 50.472 0.133 50.544 ;
     RECT  0.084 50.544 0.133 50.568 ;
     RECT  0.06 50.568 0.133 50.64 ;
     RECT  0.084 50.64 0.133 50.664 ;
     RECT  0.06 50.664 0.133 50.736 ;
     RECT  0.084 50.736 0.133 50.76 ;
     RECT  0.06 50.76 0.133 50.832 ;
     RECT  0.084 50.832 0.133 50.856 ;
     RECT  0.06 50.856 0.133 50.928 ;
     RECT  0.084 50.928 0.133 50.952 ;
     RECT  0.06 50.952 0.133 51.024 ;
     RECT  0.084 51.024 0.133 51.048 ;
     RECT  0.06 51.048 0.133 51.12 ;
     RECT  0.084 51.12 0.133 51.144 ;
     RECT  0.06 51.144 0.133 51.216 ;
     RECT  0.084 51.216 0.133 51.24 ;
     RECT  0.06 51.24 0.133 51.312 ;
     RECT  0.084 51.312 0.133 51.336 ;
     RECT  0.06 51.336 0.133 51.408 ;
     RECT  0.084 51.408 0.133 51.432 ;
     RECT  0.06 51.432 0.133 51.504 ;
     RECT  0.084 51.504 0.133 51.528 ;
     RECT  0.06 51.528 0.133 51.6 ;
     RECT  0.084 51.6 0.133 51.624 ;
     RECT  0.06 51.624 0.133 51.696 ;
     RECT  0.084 51.696 0.133 51.72 ;
     RECT  0.06 51.72 0.133 51.792 ;
     RECT  0.084 51.792 0.133 51.816 ;
     RECT  0.06 51.816 0.133 51.888 ;
     RECT  0.084 51.888 0.133 51.912 ;
     RECT  0.06 51.912 0.133 51.984 ;
     RECT  0.084 51.984 0.133 52.008 ;
     RECT  0.06 52.008 0.133 52.08 ;
     RECT  0.084 52.08 0.133 52.104 ;
     RECT  0.06 52.104 0.133 52.176 ;
     RECT  0.084 52.176 0.133 52.2 ;
     RECT  0.06 52.2 0.133 52.272 ;
     RECT  0.084 52.272 0.133 52.296 ;
     RECT  0.06 52.296 0.133 52.368 ;
     RECT  0.084 52.368 0.133 52.392 ;
     RECT  0.06 52.392 0.133 52.464 ;
     RECT  0.084 52.464 0.133 52.488 ;
     RECT  0.06 52.488 0.133 52.56 ;
     RECT  0.084 52.56 0.133 52.584 ;
     RECT  0.06 52.584 0.133 52.656 ;
     RECT  0.084 52.656 0.133 52.68 ;
     RECT  0.06 52.68 0.133 52.752 ;
     RECT  0.084 52.752 0.133 52.776 ;
     RECT  0.06 52.776 0.133 52.848 ;
     RECT  0.084 52.848 0.133 52.872 ;
     RECT  0.06 52.872 0.133 52.944 ;
     RECT  0.084 52.944 0.133 52.968 ;
     RECT  0.06 52.968 0.133 53.04 ;
     RECT  0.084 53.04 0.133 53.064 ;
     RECT  0.06 53.064 0.133 53.136 ;
     RECT  0.084 53.136 0.133 53.16 ;
     RECT  0.06 53.16 0.133 53.232 ;
     RECT  0.084 53.232 0.133 53.256 ;
     RECT  0.06 53.256 0.133 53.328 ;
     RECT  0.084 53.328 0.133 53.352 ;
     RECT  0.06 53.352 0.133 53.424 ;
     RECT  0.084 53.424 0.133 53.448 ;
     RECT  0.06 53.448 0.133 53.52 ;
     RECT  0.084 53.52 0.133 53.544 ;
     RECT  0.06 53.544 0.133 53.616 ;
     RECT  0.084 53.616 0.133 53.64 ;
     RECT  0.06 53.64 0.133 53.712 ;
     RECT  0.084 53.712 0.133 53.736 ;
     RECT  0.06 53.736 0.133 53.808 ;
     RECT  0.084 53.808 0.133 53.832 ;
     RECT  0.06 53.832 0.133 53.904 ;
     RECT  0.084 53.904 0.133 53.928 ;
     RECT  0.06 53.928 0.133 54 ;
     RECT  0.084 54 0.133 54.024 ;
     RECT  0.06 54.024 0.133 54.096 ;
     RECT  0.084 54.096 0.133 54.12 ;
     RECT  0.06 54.12 0.133 54.192 ;
     RECT  0.084 54.192 0.133 54.216 ;
     RECT  0.06 54.216 0.133 54.288 ;
     RECT  0.084 54.288 0.133 54.312 ;
     RECT  0.06 54.312 0.133 54.384 ;
     RECT  0.084 54.384 0.133 54.408 ;
     RECT  0.06 54.408 0.133 54.48 ;
     RECT  0.084 54.48 0.133 54.504 ;
     RECT  0.06 54.504 0.133 54.576 ;
     RECT  0.084 54.576 0.133 54.6 ;
     RECT  0.06 54.6 0.133 54.672 ;
     RECT  0.084 54.672 0.133 54.696 ;
     RECT  0.06 54.696 0.133 54.768 ;
     RECT  0.084 54.768 0.133 54.792 ;
     RECT  0.06 54.792 0.133 54.864 ;
     RECT  0.084 54.864 0.133 54.888 ;
     RECT  0.06 54.888 0.133 54.96 ;
     RECT  0.084 54.96 0.133 54.984 ;
     RECT  0.06 54.984 0.133 55.056 ;
     RECT  0.084 55.056 0.133 55.08 ;
     RECT  0.06 55.08 0.133 55.152 ;
     RECT  0.084 55.152 0.133 55.176 ;
     RECT  0.06 55.176 0.133 55.248 ;
     RECT  0.084 55.248 0.133 55.272 ;
     RECT  0.06 55.272 0.133 55.344 ;
     RECT  0.084 55.344 0.133 55.368 ;
     RECT  0.06 55.368 0.133 55.44 ;
     RECT  0.084 55.44 0.133 55.464 ;
     RECT  0.06 55.464 0.133 55.536 ;
     RECT  0.084 55.536 0.133 55.56 ;
     RECT  0.06 55.56 0.133 55.632 ;
     RECT  0.084 55.632 0.133 55.656 ;
     RECT  0.06 55.656 0.133 55.728 ;
     RECT  0.084 55.728 0.133 55.752 ;
     RECT  0.06 55.752 0.133 55.824 ;
     RECT  0.084 55.824 0.133 55.848 ;
     RECT  0.06 55.848 0.133 55.92 ;
     RECT  0.084 55.92 0.133 55.944 ;
     RECT  0.06 55.944 0.133 56.016 ;
     RECT  0.084 56.016 0.133 56.04 ;
     RECT  0.06 56.04 0.133 56.112 ;
     RECT  0.084 56.112 0.133 56.136 ;
     RECT  0.06 56.136 0.133 56.208 ;
     RECT  0.084 56.208 0.133 56.232 ;
     RECT  0.06 56.232 0.133 56.304 ;
     RECT  0.084 56.304 0.133 56.328 ;
     RECT  0.06 56.328 0.133 56.4 ;
     RECT  0.084 56.4 0.133 56.424 ;
     RECT  0.06 56.424 0.133 56.496 ;
     RECT  0.084 56.496 0.133 56.52 ;
     RECT  0.06 56.52 0.133 56.592 ;
     RECT  0.084 56.592 0.133 56.616 ;
     RECT  0.06 56.616 0.133 56.688 ;
     RECT  0.084 56.688 0.133 56.712 ;
     RECT  0.06 56.712 0.133 56.784 ;
     RECT  0.084 56.784 0.133 56.808 ;
     RECT  0.06 56.808 0.133 56.88 ;
     RECT  0.084 56.88 0.133 56.904 ;
     RECT  0.06 56.904 0.133 56.976 ;
     RECT  0.084 56.976 0.133 57 ;
     RECT  0.06 57 0.133 57.072 ;
     RECT  0.084 57.072 0.133 57.096 ;
     RECT  0.06 57.096 0.133 57.168 ;
     RECT  0.084 57.168 0.133 57.192 ;
     RECT  0.06 57.192 0.133 57.264 ;
     RECT  0.084 57.264 0.133 57.288 ;
     RECT  0.06 57.288 0.133 57.36 ;
     RECT  0.084 57.36 0.133 57.384 ;
     RECT  0.06 57.384 0.133 57.456 ;
     RECT  0.084 57.456 0.133 57.48 ;
     RECT  0.06 57.48 0.133 57.552 ;
     RECT  0.084 57.552 0.133 57.576 ;
     RECT  0.06 57.576 0.133 57.648 ;
     RECT  0.084 57.648 0.133 57.672 ;
     RECT  0.06 57.672 0.133 57.744 ;
     RECT  0.084 57.744 0.133 57.768 ;
     RECT  0.06 57.768 0.133 57.84 ;
     RECT  0.084 57.84 0.133 57.864 ;
     RECT  0.06 57.864 0.133 57.936 ;
     RECT  0.084 57.936 0.133 57.96 ;
     RECT  0.06 57.96 0.133 58.032 ;
     RECT  0.084 58.032 0.133 58.056 ;
     RECT  0.06 58.056 0.133 58.128 ;
     RECT  0.084 58.128 0.133 58.152 ;
     RECT  0.06 58.152 0.133 58.224 ;
     RECT  0.084 58.224 0.133 58.248 ;
     RECT  0.06 58.248 0.133 58.32 ;
     RECT  0.084 58.32 0.133 58.344 ;
     RECT  0.06 58.344 0.133 58.416 ;
     RECT  0.084 58.416 0.133 58.44 ;
     RECT  0.06 58.44 0.133 58.512 ;
     RECT  0.084 58.512 0.133 58.536 ;
     RECT  0.06 58.536 0.133 58.608 ;
     RECT  0.084 58.608 0.133 58.632 ;
     RECT  0.06 58.632 0.133 58.704 ;
     RECT  0.084 58.704 0.133 58.728 ;
     RECT  0.06 58.728 0.133 58.8 ;
     RECT  0.084 58.8 0.133 58.824 ;
     RECT  0.06 58.824 0.133 58.896 ;
     RECT  0.084 58.896 0.133 58.92 ;
     RECT  0.06 58.92 0.133 58.992 ;
     RECT  0.084 58.992 0.133 59.016 ;
     RECT  0.06 59.016 0.133 59.088 ;
     RECT  0.084 59.088 0.133 59.112 ;
     RECT  0.06 59.112 0.133 59.184 ;
     RECT  0.084 59.184 0.133 59.208 ;
     RECT  0.06 59.208 0.133 59.28 ;
     RECT  0.084 59.28 0.133 59.304 ;
     RECT  0.06 59.304 0.133 59.376 ;
     RECT  0.084 59.376 0.133 59.4 ;
     RECT  0.06 59.4 0.133 59.472 ;
     RECT  0.084 59.472 0.133 59.496 ;
     RECT  0.06 59.496 0.133 59.568 ;
     RECT  0.084 59.568 0.133 59.592 ;
     RECT  0.06 59.592 0.133 59.664 ;
     RECT  0.084 59.664 0.133 59.688 ;
     RECT  0.06 59.688 0.133 59.76 ;
     RECT  0.084 59.76 0.133 59.784 ;
     RECT  0.06 59.784 0.133 59.856 ;
     RECT  0.084 59.856 0.133 59.88 ;
     RECT  0.06 59.88 0.133 59.952 ;
     RECT  0.084 59.952 0.133 59.976 ;
     RECT  0.06 59.976 0.133 60.048 ;
     RECT  0.084 60.048 0.133 60.072 ;
     RECT  0.06 60.072 0.133 60.144 ;
     RECT  0.084 60.144 0.133 60.168 ;
     RECT  0.06 60.168 0.133 60.24 ;
     RECT  0.084 60.24 0.133 60.264 ;
     RECT  0.06 60.264 0.133 60.336 ;
     RECT  0.084 60.336 0.133 60.36 ;
     RECT  0.06 60.36 0.133 60.432 ;
     RECT  0.084 60.432 0.133 60.456 ;
     RECT  0.06 60.456 0.133 60.528 ;
     RECT  0.084 60.528 0.133 60.552 ;
     RECT  0.06 60.552 0.133 60.624 ;
     RECT  0.084 60.624 0.133 60.648 ;
     RECT  0.06 60.648 0.133 60.72 ;
     RECT  0.084 60.72 0.133 60.744 ;
     RECT  0.06 60.744 0.133 60.816 ;
     RECT  0.084 60.816 0.133 60.84 ;
     RECT  0.06 60.84 0.133 60.912 ;
     RECT  0.084 60.912 0.133 60.936 ;
     RECT  0.06 60.936 0.133 61.008 ;
     RECT  0.084 61.008 0.133 61.032 ;
     RECT  0.06 61.032 0.133 61.104 ;
     RECT  0.084 61.104 0.133 61.128 ;
     RECT  0.06 61.128 0.133 61.2 ;
     RECT  0.084 61.2 0.133 61.224 ;
     RECT  0.06 61.224 0.133 61.296 ;
     RECT  0.084 61.296 0.133 61.32 ;
     RECT  0.06 61.32 0.133 61.392 ;
     RECT  0.084 61.392 0.133 61.416 ;
     RECT  0.06 61.416 0.133 61.488 ;
     RECT  0.084 61.488 0.133 61.512 ;
     RECT  0.06 61.512 0.133 61.584 ;
     RECT  0.084 61.584 0.133 61.608 ;
     RECT  0.06 61.608 0.133 61.68 ;
     RECT  0.084 61.68 0.133 61.704 ;
     RECT  0.06 61.704 0.133 61.776 ;
     RECT  0.084 61.776 0.133 61.8 ;
     RECT  0.06 61.8 0.133 61.872 ;
     RECT  0.084 61.872 0.133 61.896 ;
     RECT  0.06 61.896 0.133 61.968 ;
     RECT  0.084 61.968 0.133 61.992 ;
     RECT  0.06 61.992 0.133 62.064 ;
     RECT  0.084 62.064 0.133 62.088 ;
     RECT  0.06 62.088 0.133 62.16 ;
     RECT  0.084 62.16 0.133 62.184 ;
     RECT  0.06 62.184 0.133 62.256 ;
     RECT  0.084 62.256 0.133 62.28 ;
     RECT  0.06 62.28 0.133 62.352 ;
     RECT  0.084 62.352 0.133 62.376 ;
     RECT  0.06 62.376 0.133 62.448 ;
     RECT  0.084 62.448 0.133 62.472 ;
     RECT  0.06 62.472 0.133 62.544 ;
     RECT  0.084 62.544 0.133 62.568 ;
     RECT  0.06 62.568 0.133 62.64 ;
     RECT  0.084 62.64 0.133 62.664 ;
     RECT  0.06 62.664 0.133 62.736 ;
     RECT  0.084 62.736 0.133 62.76 ;
     RECT  0.06 62.76 0.133 62.832 ;
     RECT  0.084 62.832 0.133 62.856 ;
     RECT  0.06 62.856 0.133 62.928 ;
     RECT  0.084 62.928 0.133 62.952 ;
     RECT  0.06 62.952 0.133 63.024 ;
     RECT  0.084 63.024 0.133 63.048 ;
     RECT  0.06 63.048 0.133 63.12 ;
     RECT  0.084 63.12 0.133 63.144 ;
     RECT  0.06 63.144 0.133 63.216 ;
     RECT  0.084 63.216 0.133 63.24 ;
     RECT  0.06 63.24 0.133 63.312 ;
     RECT  0.084 63.312 0.133 63.336 ;
     RECT  0.06 63.336 0.133 63.408 ;
     RECT  0.084 63.408 0.133 63.432 ;
     RECT  0.06 63.432 0.133 63.504 ;
     RECT  0.084 63.504 0.133 63.528 ;
     RECT  0.06 63.528 0.133 63.6 ;
     RECT  0.084 63.6 0.133 63.624 ;
     RECT  0.06 63.624 0.133 63.696 ;
     RECT  0.084 63.696 0.133 63.72 ;
     RECT  0.06 63.72 0.133 63.792 ;
     RECT  0.084 63.792 0.133 63.816 ;
     RECT  0.06 63.816 0.133 63.888 ;
     RECT  0.084 63.888 0.133 63.912 ;
     RECT  0.06 63.912 0.133 63.984 ;
     RECT  0.084 63.984 0.133 64.008 ;
     RECT  0.06 64.008 0.133 64.08 ;
     RECT  0.084 64.08 0.133 64.104 ;
     RECT  0.06 64.104 0.133 64.176 ;
     RECT  0.084 64.176 0.133 64.2 ;
     RECT  0.06 64.2 0.133 64.272 ;
     RECT  0.084 64.272 0.133 64.296 ;
     RECT  0.06 64.296 0.133 64.368 ;
     RECT  0.084 64.368 0.133 64.392 ;
     RECT  0.06 64.392 0.133 64.464 ;
     RECT  0.084 64.464 0.133 64.488 ;
     RECT  0.06 64.488 0.133 64.56 ;
     RECT  0.084 64.56 0.133 64.584 ;
     RECT  0.06 64.584 0.133 64.656 ;
     RECT  0.084 64.656 0.133 64.68 ;
     RECT  0.06 64.68 0.133 64.752 ;
     RECT  0.084 64.752 0.133 64.776 ;
     RECT  0.06 64.776 0.133 64.848 ;
     RECT  0.084 64.848 0.133 64.872 ;
     RECT  0.06 64.872 0.133 64.944 ;
     RECT  0.084 64.944 0.133 64.968 ;
     RECT  0.06 64.968 0.133 65.04 ;
     RECT  0.084 65.04 0.133 65.064 ;
     RECT  0.06 65.064 0.133 65.136 ;
     RECT  0.084 65.136 0.133 65.16 ;
     RECT  0.06 65.16 0.133 65.232 ;
     RECT  0.084 65.232 0.133 65.256 ;
     RECT  0.06 65.256 0.133 65.328 ;
     RECT  0.084 65.328 0.133 65.352 ;
     RECT  0.06 65.352 0.133 65.424 ;
     RECT  0.084 65.424 0.133 65.448 ;
     RECT  0.06 65.448 0.133 65.52 ;
     RECT  0.084 65.52 0.133 65.544 ;
     RECT  0.06 65.544 0.133 65.616 ;
     RECT  0.084 65.616 0.133 65.64 ;
     RECT  0.06 65.64 0.133 65.712 ;
     RECT  0.084 65.712 0.133 65.736 ;
     RECT  0.06 65.736 0.133 65.808 ;
     RECT  0.084 65.808 0.133 65.832 ;
     RECT  0.06 65.832 0.133 65.904 ;
     RECT  0.084 65.904 0.133 65.928 ;
     RECT  0.06 65.928 0.133 66 ;
     RECT  0.084 66 0.133 66.024 ;
     RECT  0.06 66.024 0.133 66.096 ;
     RECT  0.084 66.096 0.133 66.12 ;
     RECT  0.06 66.12 0.133 66.192 ;
     RECT  0.084 66.192 0.133 66.216 ;
     RECT  0.06 66.216 0.133 66.288 ;
     RECT  0.084 66.288 0.133 66.312 ;
     RECT  0.06 66.312 0.133 66.384 ;
     RECT  0.084 66.384 0.133 66.408 ;
     RECT  0.06 66.408 0.133 66.48 ;
     RECT  0.084 66.48 0.133 66.504 ;
     RECT  0.06 66.504 0.133 66.576 ;
     RECT  0.084 66.576 0.133 66.6 ;
     RECT  0.06 66.6 0.133 66.672 ;
     RECT  0.084 66.672 0.133 66.696 ;
     RECT  0.06 66.696 0.133 66.768 ;
     RECT  0.084 66.768 0.133 66.792 ;
     RECT  0.06 66.792 0.133 66.864 ;
     RECT  0.084 66.864 0.133 66.888 ;
     RECT  0.06 66.888 0.133 66.96 ;
     RECT  0.084 66.96 0.133 66.984 ;
     RECT  0.06 66.984 0.133 67.056 ;
     RECT  0.084 67.056 0.133 67.08 ;
     RECT  0.06 67.08 0.133 67.152 ;
     RECT  0.084 67.152 0.133 67.176 ;
     RECT  0.06 67.176 0.133 67.248 ;
     RECT  0.084 67.248 0.133 67.272 ;
     RECT  0.06 67.272 0.133 67.344 ;
     RECT  0.084 67.344 0.133 67.368 ;
     RECT  0.06 67.368 0.133 67.44 ;
     RECT  0.084 67.44 0.133 67.464 ;
     RECT  0.06 67.464 0.133 67.536 ;
     RECT  0.084 67.536 0.133 67.56 ;
     RECT  0.06 67.56 0.133 67.632 ;
     RECT  0.084 67.632 0.133 67.656 ;
     RECT  0.06 67.656 0.133 67.728 ;
     RECT  0.084 67.728 0.133 67.752 ;
     RECT  0.06 67.752 0.133 67.824 ;
     RECT  0.084 67.824 0.133 67.848 ;
     RECT  0.06 67.848 0.133 67.92 ;
     RECT  0.084 67.92 0.133 67.944 ;
     RECT  0.06 67.944 0.133 68.016 ;
     RECT  0.084 68.016 0.133 68.04 ;
     RECT  0.06 68.04 0.133 68.112 ;
     RECT  0.084 68.112 0.133 68.136 ;
     RECT  0.06 68.136 0.133 68.208 ;
     RECT  0.084 68.208 0.133 68.232 ;
     RECT  0.06 68.232 0.133 68.304 ;
     RECT  0.084 68.304 0.133 68.328 ;
     RECT  0.06 68.328 0.133 68.4 ;
     RECT  0.084 68.4 0.133 68.424 ;
     RECT  0.06 68.424 0.133 68.496 ;
     RECT  0.084 68.496 0.133 68.52 ;
     RECT  0.06 68.52 0.133 68.592 ;
     RECT  0.084 68.592 0.133 68.616 ;
     RECT  0.06 68.616 0.133 68.688 ;
     RECT  0.084 68.688 0.133 68.712 ;
     RECT  0.06 68.712 0.133 68.784 ;
     RECT  0.084 68.784 0.133 68.808 ;
     RECT  0.06 68.808 0.133 68.88 ;
     RECT  0.084 68.88 0.133 68.904 ;
     RECT  0.06 68.904 0.133 68.976 ;
     RECT  0.084 68.976 0.133 69 ;
     RECT  0.06 69 0.133 69.072 ;
     RECT  0.084 69.072 0.133 69.096 ;
     RECT  0.06 69.096 0.133 69.168 ;
     RECT  0.084 69.168 0.133 69.192 ;
     RECT  0.06 69.192 0.133 69.264 ;
     RECT  0.084 69.264 0.133 69.288 ;
     RECT  0.06 69.288 0.133 69.36 ;
     RECT  0.084 69.36 0.133 69.384 ;
     RECT  0.06 69.384 0.133 69.456 ;
     RECT  0.084 69.456 0.133 69.48 ;
     RECT  0.06 69.48 0.133 69.552 ;
     RECT  0.084 69.552 0.133 69.576 ;
     RECT  0.06 69.576 0.133 69.648 ;
     RECT  0.084 69.648 0.133 69.672 ;
     RECT  0.06 69.672 0.133 69.744 ;
     RECT  0.084 69.744 0.133 69.768 ;
     RECT  0.06 69.768 0.133 69.84 ;
     RECT  0.084 69.84 0.133 69.864 ;
     RECT  0.06 69.864 0.133 69.936 ;
     RECT  0.084 69.936 0.133 69.96 ;
     RECT  0.06 69.96 0.133 70.032 ;
     RECT  0.084 70.032 0.133 70.056 ;
     RECT  0.06 70.056 0.133 70.128 ;
     RECT  0.084 70.128 0.133 70.152 ;
     RECT  0.06 70.152 0.133 70.224 ;
     RECT  0.084 70.224 0.133 70.248 ;
     RECT  0.06 70.248 0.133 70.32 ;
     RECT  0.084 70.32 0.133 70.344 ;
     RECT  0.06 70.344 0.133 70.416 ;
     RECT  0.084 70.416 0.133 70.44 ;
     RECT  0.06 70.44 0.133 70.512 ;
     RECT  0.084 70.512 0.133 70.536 ;
     RECT  0.06 70.536 0.133 70.608 ;
     RECT  0.084 70.608 0.133 70.632 ;
     RECT  0.06 70.632 0.133 70.704 ;
     RECT  0.084 70.704 0.133 70.728 ;
     RECT  0.06 70.728 0.133 70.8 ;
     RECT  0.084 70.8 0.133 70.824 ;
     RECT  0.06 70.824 0.133 70.896 ;
     RECT  0.084 70.896 0.133 70.92 ;
     RECT  0.06 70.92 0.133 70.992 ;
     RECT  0.084 70.992 0.133 71.016 ;
     RECT  0.06 71.016 0.133 71.088 ;
     RECT  0.084 71.088 0.133 71.112 ;
     RECT  0.06 71.112 0.133 71.184 ;
     RECT  0.084 71.184 0.133 71.208 ;
     RECT  0.06 71.208 0.133 71.28 ;
     RECT  0.084 71.28 0.133 71.304 ;
     RECT  0.06 71.304 0.133 71.376 ;
     RECT  0.084 71.376 0.133 71.4 ;
     RECT  0.06 71.4 0.133 71.472 ;
     RECT  0.084 71.472 0.133 71.496 ;
     RECT  0.06 71.496 0.133 71.568 ;
     RECT  0.084 71.568 0.133 71.592 ;
     RECT  0.06 71.592 0.133 71.664 ;
     RECT  0.084 71.664 0.133 71.688 ;
     RECT  0.06 71.688 0.133 71.76 ;
     RECT  0.084 71.76 0.133 71.784 ;
     RECT  0.06 71.784 0.133 71.856 ;
     RECT  0.084 71.856 0.133 71.88 ;
     RECT  0.06 71.88 0.133 71.952 ;
     RECT  0.084 71.952 0.133 71.976 ;
     RECT  0.06 71.976 0.133 72.048 ;
     RECT  0.084 72.048 0.133 72.072 ;
     RECT  0.06 72.072 0.133 72.144 ;
     RECT  0.084 72.144 0.133 72.168 ;
     RECT  0.06 72.168 0.133 72.24 ;
     RECT  0.084 72.24 0.133 72.264 ;
     RECT  0.06 72.264 0.133 72.336 ;
     RECT  0.084 72.336 0.133 72.36 ;
     RECT  0.06 72.36 0.133 72.432 ;
     RECT  0.084 72.432 0.133 72.456 ;
     RECT  0.06 72.456 0.133 72.528 ;
     RECT  0.084 72.528 0.133 72.552 ;
     RECT  0.06 72.552 0.133 72.624 ;
     RECT  0.084 72.624 0.133 72.648 ;
     RECT  0.06 72.648 0.133 72.72 ;
     RECT  0.084 72.72 0.133 72.744 ;
     RECT  0.06 72.744 0.133 72.816 ;
     RECT  0.084 72.816 0.133 72.84 ;
     RECT  0.06 72.84 0.133 72.912 ;
     RECT  0.084 72.912 0.133 72.936 ;
     RECT  0.06 72.936 0.133 73.008 ;
     RECT  0.084 73.008 0.133 73.032 ;
     RECT  0.06 73.032 0.133 73.368 ;
     RECT  0.037 79.536 0.133 79.56 ;
     RECT  0.133 42.912 0.181 73.368 ;
     RECT  0.133 78.624 0.181 79.56 ;
     RECT  0.133 41.232 0.229 41.256 ;
     RECT  0.181 42.48 0.229 73.368 ;
     RECT  0.229 75.936 0.325 75.96 ;
     RECT  0.229 41.232 0.373 73.368 ;
     RECT  0.133 74.784 0.373 74.808 ;
     RECT  0.373 41.232 0.613 74.808 ;
     RECT  0.325 75.936 0.613 76.056 ;
     RECT  0.613 41.232 0.757 76.056 ;
     RECT  0.181 78.192 0.805 79.56 ;
     RECT  0.757 41.232 0.949 76.2 ;
     RECT  0.805 78.096 1.381 79.56 ;
     RECT  0.949 41.232 1.957 76.584 ;
     RECT  1.381 78.096 1.957 80.136 ;
     RECT  1.957 41.232 2.408 80.136 ;
     RECT  2.408 2.148 2.512 114.492 ;
     RECT  2.512 2.418 2.704 114.222 ;
     RECT  2.704 40.752 3.305 80.136 ;
     RECT  3.305 40.752 4.273 80.088 ;
     RECT  4.273 40.704 4.307 80.088 ;
     RECT  4.307 40.704 4.493 79.992 ;
     RECT  4.493 40.704 4.814 79.944 ;
     RECT  4.814 40.704 4.897 79.896 ;
     RECT  4.897 40.704 5.101 79.848 ;
     RECT  2.704 39.312 5.177 39.336 ;
     RECT  5.641 38.784 5.725 38.808 ;
     RECT  5.101 40.56 5.987 79.848 ;
     RECT  6.517 17.616 6.565 17.64 ;
     RECT  6.325 19.344 6.901 19.368 ;
     RECT  2.704 22.032 6.997 22.056 ;
     RECT  6.565 16.848 7.285 17.64 ;
     RECT  7.285 16.848 7.808 18.264 ;
     RECT  6.901 19.344 7.808 19.608 ;
     RECT  6.997 21.456 7.808 22.056 ;
     RECT  7.669 23.616 7.808 23.64 ;
     RECT  5.653 37.008 7.808 37.032 ;
     RECT  5.987 40.56 7.808 79.464 ;
     RECT  7.808 2.148 7.912 114.492 ;
     RECT  7.912 2.418 8.104 114.222 ;
     RECT  8.104 40.56 8.435 79.464 ;
     RECT  8.435 40.56 8.915 79.32 ;
     RECT  8.915 79.296 9.155 79.32 ;
     RECT  8.104 21.36 9.301 22.632 ;
     RECT  8.104 23.616 9.301 23.64 ;
     RECT  9.241 36.48 9.349 36.504 ;
     RECT  8.915 40.56 9.395 78.168 ;
     RECT  9.301 30.816 9.443 30.84 ;
     RECT  9.301 38.736 9.443 38.76 ;
     RECT  9.301 21.36 9.541 23.64 ;
     RECT  9.349 34.8 9.635 34.824 ;
     RECT  9.349 36.48 9.635 36.6 ;
     RECT  9.635 36.48 9.683 36.504 ;
     RECT  9.395 45.552 9.827 78.168 ;
     RECT  9.827 45.552 9.971 77.64 ;
     RECT  9.971 76.752 10.163 77.64 ;
     RECT  9.637 34.992 10.253 35.016 ;
     RECT  9.395 40.56 10.547 44.088 ;
     RECT  10.547 42.432 10.595 44.088 ;
     RECT  10.645 34.896 10.748 34.92 ;
     RECT  8.104 16.848 10.789 20.376 ;
     RECT  9.541 21.36 10.789 23.928 ;
     RECT  10.645 32.352 10.789 32.376 ;
     RECT  10.595 42.432 10.829 42.552 ;
     RECT  10.789 32.352 10.835 32.472 ;
     RECT  10.748 34.8 10.835 34.92 ;
     RECT  10.595 44.064 11.219 44.088 ;
     RECT  10.829 42.432 11.267 42.456 ;
     RECT  10.163 76.752 11.411 77.592 ;
     RECT  9.971 45.552 11.845 75.672 ;
     RECT  12.085 25.2 12.265 25.224 ;
     RECT  12.265 25.2 12.841 25.272 ;
     RECT  12.841 25.056 13.021 25.272 ;
     RECT  10.789 16.848 13.208 23.928 ;
     RECT  13.021 25.056 13.208 25.56 ;
     RECT  12.409 27.072 13.208 27.096 ;
     RECT  10.835 32.448 13.208 32.472 ;
     RECT  10.547 40.56 13.208 41.256 ;
     RECT  12.949 43.296 13.208 43.944 ;
     RECT  11.845 45.168 13.208 75.672 ;
     RECT  11.411 76.752 13.208 77.304 ;
     RECT  13.208 2.148 13.312 114.492 ;
     RECT  13.312 2.418 13.504 114.222 ;
     RECT  13.504 27.072 13.565 27.096 ;
     RECT  13.504 46.224 14.393 75.672 ;
     RECT  13.504 31.92 14.401 32.568 ;
     RECT  14.401 32.544 14.497 32.568 ;
     RECT  13.504 45.168 14.497 45.192 ;
     RECT  14.393 46.224 14.497 71.496 ;
     RECT  13.504 42.72 14.533 44.088 ;
     RECT  14.497 45.168 14.533 71.496 ;
     RECT  14.749 28.32 14.821 28.344 ;
     RECT  14.821 27.936 14.893 28.344 ;
     RECT  13.504 30.432 15.001 30.456 ;
     RECT  13.504 76.752 15.107 76.776 ;
     RECT  14.893 27.936 15.217 29.304 ;
     RECT  13.504 16.848 15.253 25.608 ;
     RECT  14.533 42.72 15.257 71.496 ;
     RECT  15.253 16.848 15.445 26.232 ;
     RECT  15.217 27.888 15.545 29.304 ;
     RECT  13.504 40.56 15.635 40.584 ;
     RECT  15.445 16.848 15.637 26.76 ;
     RECT  15.361 34.944 15.721 34.968 ;
     RECT  15.637 16.848 15.733 26.808 ;
     RECT  15.001 30.432 15.733 30.696 ;
     RECT  15.733 30.384 15.793 30.696 ;
     RECT  14.393 72.528 15.875 75.672 ;
     RECT  15.793 30.384 15.893 31.176 ;
     RECT  15.545 27.936 16.189 29.304 ;
     RECT  15.893 30.288 16.189 31.176 ;
     RECT  14.497 32.544 16.225 33 ;
     RECT  15.875 74.16 16.451 75.672 ;
     RECT  16.225 32.544 16.477 33.336 ;
     RECT  15.733 16.848 16.513 26.904 ;
     RECT  16.189 27.936 16.513 31.176 ;
     RECT  15.257 42.72 16.643 69.288 ;
     RECT  16.643 42.72 16.693 67.896 ;
     RECT  15.721 34.368 16.801 34.968 ;
     RECT  16.693 42.672 16.835 67.896 ;
     RECT  16.801 34.368 16.909 35.016 ;
     RECT  16.451 74.304 16.931 75.672 ;
     RECT  16.931 74.976 17.027 75.672 ;
     RECT  16.513 16.848 17.161 31.176 ;
     RECT  16.477 32.304 17.161 33.336 ;
     RECT  17.161 16.848 17.377 33.336 ;
     RECT  17.027 75.648 17.555 75.672 ;
     RECT  17.521 38.448 17.665 38.472 ;
     RECT  17.377 16.848 17.737 33.384 ;
     RECT  16.909 34.368 17.737 35.496 ;
     RECT  17.701 40.896 17.845 40.92 ;
     RECT  17.665 37.68 17.953 38.472 ;
     RECT  17.845 40.08 17.953 40.92 ;
     RECT  17.953 37.68 17.989 40.92 ;
     RECT  16.261 11.952 18.133 11.976 ;
     RECT  17.557 3.84 18.181 3.864 ;
     RECT  17.989 37.68 18.385 41.16 ;
     RECT  17.737 16.848 18.421 35.496 ;
     RECT  18.205 36.624 18.421 36.648 ;
     RECT  18.385 37.68 18.421 41.736 ;
     RECT  16.835 42.72 18.421 67.896 ;
     RECT  18.133 11.952 18.469 12.264 ;
     RECT  18.421 16.848 18.493 36.648 ;
     RECT  18.421 37.68 18.493 67.896 ;
     RECT  18.181 3.84 18.608 4.488 ;
     RECT  17.797 7.728 18.608 7.752 ;
     RECT  18.421 9.072 18.608 9.096 ;
     RECT  17.701 10.08 18.608 10.104 ;
     RECT  18.469 11.952 18.608 12.888 ;
     RECT  18.493 16.848 18.608 67.896 ;
     RECT  16.643 69.024 18.608 69.24 ;
     RECT  15.257 70.368 18.608 71.496 ;
     RECT  15.875 72.528 18.608 72.552 ;
     RECT  18.608 2.148 18.712 114.492 ;
     RECT  18.712 2.148 18.904 114.222 ;
     RECT  18.904 66.48 19.091 67.896 ;
     RECT  18.904 2.148 19.189 2.856 ;
     RECT  19.091 66.48 19.331 67.32 ;
     RECT  19.189 1.68 19.669 2.856 ;
     RECT  18.904 68.928 19.715 69.24 ;
     RECT  18.904 99.744 19.721 100.344 ;
     RECT  19.715 68.928 19.756 69.048 ;
     RECT  18.904 16.848 19.955 65.016 ;
     RECT  18.904 10.08 19.957 10.104 ;
     RECT  18.904 72.528 20.243 72.552 ;
     RECT  18.904 101.472 20.297 101.496 ;
     RECT  18.904 104.88 20.297 104.904 ;
     RECT  19.756 69.024 20.387 69.048 ;
     RECT  18.904 107.76 20.389 107.784 ;
     RECT  20.389 105.408 20.437 105.432 ;
     RECT  20.389 107.568 20.473 107.784 ;
     RECT  20.437 105.408 20.477 106.248 ;
     RECT  20.473 107.568 20.485 108.072 ;
     RECT  20.437 102 20.521 102.024 ;
     RECT  19.721 100.272 20.557 100.344 ;
     RECT  19.669 1.584 20.665 2.856 ;
     RECT  19.331 66.48 20.689 66.504 ;
     RECT  20.725 96.384 20.773 96.408 ;
     RECT  18.904 3.84 20.821 9.096 ;
     RECT  19.957 10.08 20.821 10.728 ;
     RECT  20.689 66.096 20.915 66.504 ;
     RECT  20.915 66.48 21.059 66.504 ;
     RECT  20.557 100.32 21.449 100.344 ;
     RECT  18.904 70.368 21.971 70.392 ;
     RECT  20.821 99.168 21.989 99.192 ;
     RECT  18.904 11.808 22.501 13.656 ;
     RECT  20.773 95.424 22.565 96.408 ;
     RECT  22.501 11.76 22.597 13.656 ;
     RECT  20.485 107.52 22.741 108.072 ;
     RECT  22.7 99.696 22.787 99.72 ;
     RECT  20.245 97.536 22.849 97.56 ;
     RECT  20.477 106.224 22.885 106.248 ;
     RECT  22.849 96.528 22.933 97.56 ;
     RECT  19.955 16.848 22.968 64.296 ;
     RECT  20.665 1.584 24.008 2.28 ;
     RECT  20.821 3.84 24.008 10.728 ;
     RECT  22.597 11.712 24.008 13.656 ;
     RECT  22.968 16.848 24.008 94.248 ;
     RECT  22.933 96.528 24.008 96.552 ;
     RECT  22.933 97.536 24.008 97.56 ;
     RECT  22.201 100.752 24.008 100.776 ;
     RECT  22.885 105.648 24.008 106.248 ;
     RECT  22.741 107.28 24.008 108.072 ;
     RECT  24.008 96.528 24.112 114.492 ;
     RECT  22.565 95.424 24.2 95.448 ;
     RECT  24.112 96.528 24.2 114.222 ;
     RECT  24.008 1.584 24.304 94.248 ;
     RECT  24.2 95.424 24.304 114.222 ;
     RECT  24.304 16.848 25.877 94.248 ;
     RECT  24.304 96.528 26.737 96.552 ;
     RECT  26.737 96.432 26.777 96.552 ;
     RECT  24.304 1.584 29.408 2.28 ;
     RECT  24.304 3.84 29.408 10.728 ;
     RECT  24.304 11.712 29.408 13.656 ;
     RECT  25.877 17.088 29.408 94.248 ;
     RECT  26.777 96.432 29.408 96.456 ;
     RECT  24.304 97.536 29.408 97.56 ;
     RECT  24.304 100.752 29.408 100.776 ;
     RECT  24.304 105.648 29.408 106.248 ;
     RECT  24.304 107.28 29.408 108.072 ;
     RECT  29.408 96.432 29.512 114.492 ;
     RECT  24.304 95.424 29.6 95.448 ;
     RECT  29.512 96.432 29.6 114.222 ;
     RECT  29.408 1.584 29.704 94.248 ;
     RECT  29.6 95.424 29.704 114.222 ;
     RECT  29.704 1.584 34.808 2.28 ;
     RECT  29.704 3.84 34.808 10.728 ;
     RECT  29.704 11.712 34.808 13.656 ;
     RECT  29.704 17.088 34.808 94.248 ;
     RECT  29.704 96.432 34.808 96.456 ;
     RECT  29.704 97.536 34.808 97.56 ;
     RECT  29.704 100.752 34.808 100.776 ;
     RECT  29.704 105.648 34.808 106.248 ;
     RECT  29.704 107.28 34.808 108.072 ;
     RECT  34.808 96.432 34.912 114.492 ;
     RECT  29.704 95.424 35 95.448 ;
     RECT  34.912 96.432 35 114.222 ;
     RECT  34.808 1.584 35.104 94.248 ;
     RECT  35 95.424 35.104 114.222 ;
     RECT  35.104 3.84 35.785 10.728 ;
     RECT  35.104 11.712 37.141 13.656 ;
     RECT  35.104 1.584 40.208 2.28 ;
     RECT  35.785 3.84 40.208 4.536 ;
     RECT  35.785 5.568 40.208 10.728 ;
     RECT  37.141 11.712 40.208 14.424 ;
     RECT  35.104 17.088 40.208 94.248 ;
     RECT  35.104 96.432 40.208 96.456 ;
     RECT  35.104 97.536 40.208 97.56 ;
     RECT  35.104 100.752 40.208 100.776 ;
     RECT  35.104 105.648 40.208 106.248 ;
     RECT  35.104 107.28 40.208 108.072 ;
     RECT  40.208 96.432 40.312 114.492 ;
     RECT  35.104 95.424 40.4 95.448 ;
     RECT  40.312 96.432 40.4 114.222 ;
     RECT  40.208 1.584 40.504 94.248 ;
     RECT  40.4 95.424 40.504 114.222 ;
     RECT  40.504 3.936 41.533 4.536 ;
     RECT  41.533 3.888 41.617 4.536 ;
     RECT  40.504 95.424 43.157 95.448 ;
     RECT  40.504 1.584 45.608 2.28 ;
     RECT  41.617 3.936 45.608 4.536 ;
     RECT  40.504 5.568 45.608 10.728 ;
     RECT  40.504 11.712 45.608 14.424 ;
     RECT  40.504 17.088 45.608 94.248 ;
     RECT  40.504 96.432 45.608 96.456 ;
     RECT  40.504 97.536 45.608 97.56 ;
     RECT  40.504 100.752 45.608 100.776 ;
     RECT  40.504 105.648 45.608 106.248 ;
     RECT  40.504 107.28 45.608 108.072 ;
     RECT  45.608 96.432 45.712 114.492 ;
     RECT  45.712 96.432 45.8 114.222 ;
     RECT  45.608 1.584 45.904 94.248 ;
     RECT  45.8 96.378 45.904 114.222 ;
     RECT  45.904 17.088 46.979 94.248 ;
     RECT  45.904 11.712 49.597 14.424 ;
     RECT  45.904 1.584 51.008 2.28 ;
     RECT  45.904 3.936 51.008 4.536 ;
     RECT  45.904 5.568 51.008 10.728 ;
     RECT  49.597 11.712 51.008 14.472 ;
     RECT  46.979 17.136 51.008 94.248 ;
     RECT  45.904 96.432 51.008 96.456 ;
     RECT  45.904 97.536 51.008 97.56 ;
     RECT  45.904 100.752 51.008 100.776 ;
     RECT  45.904 105.648 51.008 106.248 ;
     RECT  45.904 107.28 51.008 108.072 ;
     RECT  51.008 96.432 51.112 114.492 ;
     RECT  51.112 96.432 51.2 114.222 ;
     RECT  51.008 1.584 51.304 94.248 ;
     RECT  51.2 96.378 51.304 114.222 ;
     RECT  51.304 11.712 51.401 14.472 ;
     RECT  51.304 17.136 52.883 94.248 ;
     RECT  52.883 17.184 54.419 94.248 ;
     RECT  51.304 1.584 56.408 2.28 ;
     RECT  51.304 3.936 56.408 4.536 ;
     RECT  51.304 5.568 56.408 10.728 ;
     RECT  51.401 11.712 56.408 14.424 ;
     RECT  54.419 17.664 56.408 94.248 ;
     RECT  51.304 96.432 56.408 96.456 ;
     RECT  51.304 97.536 56.408 97.56 ;
     RECT  51.304 100.752 56.408 100.776 ;
     RECT  51.304 105.648 56.408 106.248 ;
     RECT  51.304 107.28 56.408 108.072 ;
     RECT  56.408 96.432 56.512 114.492 ;
     RECT  56.512 96.432 56.6 114.222 ;
     RECT  56.408 1.584 56.704 94.248 ;
     RECT  56.6 96.378 56.704 114.222 ;
     RECT  56.704 17.664 58.705 94.248 ;
     RECT  58.705 17.472 58.925 94.248 ;
     RECT  56.704 5.568 60.149 10.728 ;
     RECT  56.704 1.584 61.808 2.28 ;
     RECT  56.704 3.936 61.808 4.536 ;
     RECT  60.149 5.568 61.808 10.68 ;
     RECT  56.704 11.712 61.808 14.424 ;
     RECT  58.925 17.664 61.808 94.248 ;
     RECT  56.704 96.432 61.808 96.456 ;
     RECT  56.704 97.536 61.808 97.56 ;
     RECT  56.704 100.752 61.808 100.776 ;
     RECT  56.704 105.648 61.808 106.248 ;
     RECT  56.704 107.28 61.808 108.072 ;
     RECT  61.808 96.432 61.912 114.492 ;
     RECT  61.912 96.432 62 114.222 ;
     RECT  61.808 1.584 62.104 94.248 ;
     RECT  62 96.378 62.104 114.222 ;
     RECT  62.104 17.664 66.697 94.248 ;
     RECT  62.104 1.584 67.208 2.28 ;
     RECT  62.104 3.936 67.208 4.536 ;
     RECT  62.104 5.568 67.208 10.68 ;
     RECT  62.104 11.712 67.208 14.424 ;
     RECT  66.697 17.616 67.208 94.248 ;
     RECT  62.104 96.432 67.208 96.456 ;
     RECT  62.104 97.536 67.208 97.56 ;
     RECT  62.104 100.752 67.208 100.776 ;
     RECT  62.104 105.648 67.208 106.248 ;
     RECT  62.104 107.28 67.208 108.072 ;
     RECT  67.208 96.432 67.312 114.492 ;
     RECT  67.312 96.432 67.4 114.222 ;
     RECT  67.208 1.584 67.504 94.248 ;
     RECT  67.4 96.378 67.504 114.222 ;
     RECT  67.504 17.664 70.547 94.248 ;
     RECT  71.269 15.792 71.453 15.816 ;
     RECT  67.504 11.712 71.809 14.424 ;
     RECT  67.504 1.584 72.608 2.28 ;
     RECT  67.504 3.936 72.608 4.536 ;
     RECT  67.504 5.568 72.608 10.68 ;
     RECT  71.809 11.712 72.608 15.288 ;
     RECT  70.547 18.144 72.608 94.248 ;
     RECT  67.504 96.432 72.608 96.456 ;
     RECT  67.504 97.536 72.608 97.56 ;
     RECT  67.504 100.752 72.608 100.776 ;
     RECT  67.504 105.648 72.608 106.248 ;
     RECT  67.504 107.28 72.608 108.072 ;
     RECT  72.608 96.432 72.712 114.492 ;
     RECT  72.712 96.432 72.8 114.222 ;
     RECT  72.608 1.584 72.904 94.248 ;
     RECT  72.8 96.378 72.904 114.222 ;
     RECT  72.904 18.144 73.235 94.248 ;
     RECT  73.235 18.432 74.675 94.248 ;
     RECT  74.732 15.888 74.773 15.912 ;
     RECT  74.773 15.888 74.819 16.296 ;
     RECT  72.904 1.584 78.008 2.28 ;
     RECT  72.904 3.936 78.008 4.536 ;
     RECT  72.904 5.568 78.008 10.68 ;
     RECT  72.904 11.712 78.008 14.424 ;
     RECT  74.819 16.272 78.008 16.296 ;
     RECT  74.675 18.72 78.008 94.248 ;
     RECT  72.904 96.432 78.008 96.456 ;
     RECT  72.904 97.536 78.008 97.56 ;
     RECT  72.904 100.752 78.008 100.776 ;
     RECT  72.904 105.648 78.008 106.248 ;
     RECT  72.904 107.28 78.008 108.072 ;
     RECT  78.008 96.432 78.112 114.492 ;
     RECT  78.112 96.432 78.2 114.222 ;
     RECT  78.008 1.584 78.304 94.248 ;
     RECT  78.2 96.378 78.304 114.222 ;
     RECT  78.304 96.432 78.797 97.56 ;
     RECT  78.304 11.712 80.521 14.424 ;
     RECT  78.304 16.272 80.737 16.296 ;
     RECT  80.737 16.272 80.821 16.536 ;
     RECT  78.304 18.72 81.203 94.248 ;
     RECT  80.521 11.712 83.005 14.952 ;
     RECT  80.821 16.272 83.005 16.392 ;
     RECT  83.005 11.712 83.269 16.392 ;
     RECT  78.304 1.584 83.408 2.28 ;
     RECT  78.304 3.936 83.408 4.536 ;
     RECT  78.304 5.568 83.408 10.68 ;
     RECT  83.269 11.712 83.408 16.68 ;
     RECT  81.203 18.768 83.408 94.248 ;
     RECT  78.797 96.432 83.408 96.456 ;
     RECT  78.797 97.536 83.408 97.56 ;
     RECT  78.304 100.752 83.408 100.776 ;
     RECT  78.304 105.648 83.408 106.248 ;
     RECT  78.304 107.28 83.408 108.072 ;
     RECT  83.408 96.432 83.512 114.492 ;
     RECT  83.512 96.432 83.6 114.222 ;
     RECT  83.408 1.584 83.704 94.248 ;
     RECT  83.6 96.378 83.704 114.222 ;
     RECT  83.704 18.768 84.371 94.248 ;
     RECT  84.371 19.344 86.099 94.248 ;
     RECT  83.704 11.712 87.145 16.68 ;
     RECT  86.099 20.064 87.829 94.248 ;
     RECT  83.704 1.584 88.808 2.28 ;
     RECT  83.704 3.936 88.808 4.536 ;
     RECT  83.704 5.568 88.808 10.68 ;
     RECT  87.145 11.712 88.808 17.64 ;
     RECT  87.829 19.776 88.808 94.248 ;
     RECT  83.704 96.432 88.808 96.456 ;
     RECT  83.704 97.536 88.808 97.56 ;
     RECT  83.704 100.752 88.808 100.776 ;
     RECT  83.704 104.544 88.808 104.568 ;
     RECT  83.704 105.648 88.808 106.248 ;
     RECT  83.704 107.28 88.808 108.072 ;
     RECT  88.808 96.432 88.912 114.492 ;
     RECT  88.912 96.432 89 114.222 ;
     RECT  88.808 1.584 89.104 94.248 ;
     RECT  89 96.378 89.104 114.222 ;
     RECT  89.104 19.536 90.661 94.248 ;
     RECT  90.661 19.344 91.101 94.248 ;
     RECT  89.104 97.536 92.189 97.56 ;
     RECT  89.104 96.432 92.965 96.456 ;
     RECT  89.104 1.584 94.208 2.28 ;
     RECT  89.104 3.936 94.208 4.536 ;
     RECT  89.104 5.568 94.208 10.68 ;
     RECT  89.104 11.712 94.208 17.64 ;
     RECT  91.101 20.064 94.208 94.248 ;
     RECT  92.965 96.432 94.208 96.744 ;
     RECT  89.104 100.752 94.208 100.776 ;
     RECT  89.104 104.544 94.208 104.568 ;
     RECT  89.104 105.648 94.208 106.248 ;
     RECT  89.104 107.28 94.208 108.072 ;
     RECT  94.208 96.432 94.312 114.492 ;
     RECT  94.312 96.432 94.4 114.222 ;
     RECT  94.208 1.584 94.504 94.248 ;
     RECT  94.4 96.378 94.504 114.222 ;
     RECT  94.504 1.584 96.073 2.28 ;
     RECT  94.504 5.568 98.773 7.752 ;
     RECT  94.504 8.784 98.773 10.68 ;
     RECT  96.073 1.584 99.608 2.856 ;
     RECT  94.504 3.936 99.608 4.536 ;
     RECT  98.773 5.568 99.608 10.68 ;
     RECT  94.504 11.712 99.608 17.64 ;
     RECT  94.504 20.064 99.608 94.248 ;
     RECT  94.504 96.432 99.608 96.744 ;
     RECT  94.504 100.752 99.608 100.776 ;
     RECT  94.504 104.544 99.608 104.568 ;
     RECT  94.504 105.648 99.608 106.248 ;
     RECT  94.504 107.28 99.608 108.072 ;
     RECT  99.608 96.432 99.712 114.492 ;
     RECT  99.712 96.432 99.8 114.222 ;
     RECT  99.608 1.584 99.904 94.248 ;
     RECT  99.8 96.378 99.904 114.222 ;
     RECT  99.904 20.304 101.905 94.248 ;
     RECT  99.904 107.28 102.629 108.072 ;
     RECT  99.904 3.936 104.012 4.536 ;
     RECT  99.904 5.568 104.012 17.64 ;
     RECT  99.904 1.584 105.008 2.856 ;
     RECT  104.012 3.936 105.008 17.64 ;
     RECT  101.905 19.344 105.008 94.248 ;
     RECT  99.904 96.432 105.008 96.744 ;
     RECT  99.904 100.752 105.008 100.776 ;
     RECT  99.904 104.544 105.008 104.568 ;
     RECT  99.904 105.648 105.008 106.248 ;
     RECT  102.629 107.28 105.008 107.928 ;
     RECT  105.008 96.432 105.112 114.492 ;
     RECT  105.112 96.432 105.2 114.222 ;
     RECT  105.008 1.584 105.304 94.248 ;
     RECT  105.2 96.378 105.304 114.222 ;
     RECT  105.304 1.584 106.693 17.64 ;
     RECT  106.657 0.096 107.017 0.12 ;
     RECT  106.693 1.248 107.017 17.64 ;
     RECT  105.304 107.28 107.669 107.928 ;
     RECT  105.304 96.432 108.173 96.744 ;
     RECT  107.669 107.28 108.497 107.304 ;
     RECT  108.173 96.432 109.249 96.456 ;
     RECT  107.017 0.096 109.859 17.64 ;
     RECT  109.859 1.152 110.408 17.64 ;
     RECT  105.304 19.344 110.408 94.248 ;
     RECT  109.249 96.432 110.408 96.744 ;
     RECT  105.304 100.752 110.408 100.776 ;
     RECT  105.304 104.544 110.408 104.568 ;
     RECT  105.304 105.648 110.408 106.248 ;
     RECT  110.408 96.432 110.512 114.492 ;
     RECT  110.512 96.432 110.6 114.222 ;
     RECT  109.859 0.096 110.617 0.168 ;
     RECT  110.617 0.048 110.668 0.168 ;
     RECT  110.408 1.152 110.704 94.248 ;
     RECT  110.6 96.378 110.704 114.222 ;
     RECT  110.704 3.84 111.377 17.64 ;
     RECT  111.377 3.888 111.665 17.64 ;
     RECT  110.704 105.648 111.773 106.248 ;
     RECT  110.704 1.152 111.829 2.856 ;
     RECT  111.829 1.152 111.917 2.904 ;
     RECT  111.665 3.936 112.169 17.64 ;
     RECT  112.169 3.936 112.705 17.4 ;
     RECT  111.917 1.152 113.065 2.856 ;
     RECT  112.705 3.84 113.065 17.4 ;
     RECT  113.065 1.152 113.465 17.4 ;
     RECT  113.465 1.152 114.041 10.68 ;
     RECT  114.041 1.2 114.113 10.68 ;
     RECT  114.113 1.248 114.509 10.68 ;
     RECT  110.668 0.048 115.409 0.12 ;
     RECT  114.509 1.584 115.808 10.68 ;
     RECT  113.465 11.712 115.808 17.4 ;
     RECT  110.704 19.344 115.808 94.248 ;
     RECT  110.704 96.432 115.808 96.744 ;
     RECT  110.704 104.544 115.808 104.568 ;
     RECT  111.773 105.648 115.808 105.672 ;
     RECT  115.808 96.432 115.912 114.492 ;
     RECT  115.912 96.432 116 114.222 ;
     RECT  115.808 1.584 116.104 94.248 ;
     RECT  116 96.378 116.104 114.222 ;
     RECT  115.409 0.096 116.201 0.12 ;
     RECT  116.104 1.584 116.309 4.536 ;
     RECT  116.309 1.632 116.849 4.536 ;
     RECT  116.104 104.544 117.029 104.568 ;
     RECT  116.849 3.936 117.389 4.536 ;
     RECT  116.104 5.568 117.713 10.68 ;
     RECT  117.713 6.672 118.577 10.68 ;
     RECT  116.104 11.712 119.437 17.4 ;
     RECT  116.849 1.632 120.053 2.856 ;
     RECT  118.577 8.784 120.085 10.68 ;
     RECT  119.437 11.712 120.085 18.216 ;
     RECT  117.713 5.568 120.197 5.592 ;
     RECT  120.053 2.256 121.208 2.856 ;
     RECT  117.389 4.512 121.208 4.536 ;
     RECT  118.577 6.672 121.208 7.704 ;
     RECT  120.085 8.784 121.208 18.216 ;
     RECT  116.104 19.344 121.208 94.248 ;
     RECT  116.104 96.432 121.208 96.744 ;
     RECT  118.105 104.544 121.208 104.568 ;
     RECT  116.104 105.648 121.208 105.672 ;
     RECT  121.208 2.148 121.312 94.248 ;
     RECT  121.208 96.432 121.312 114.492 ;
     RECT  121.312 96.432 121.4 114.222 ;
     RECT  121.312 2.256 121.504 94.248 ;
     RECT  121.4 96.378 121.504 114.222 ;
     RECT  121.504 8.784 121.925 10.68 ;
     RECT  121.504 6.672 122.573 7.704 ;
     RECT  122.573 6.672 123.005 6.696 ;
     RECT  121.504 4.512 125.237 4.536 ;
     RECT  121.504 2.256 125.273 2.856 ;
     RECT  125.273 2.832 126.608 2.856 ;
     RECT  122.573 7.68 126.608 7.704 ;
     RECT  121.925 8.784 126.608 10.488 ;
     RECT  121.504 11.712 126.608 18.216 ;
     RECT  121.504 19.344 126.608 94.248 ;
     RECT  121.504 96.72 126.608 96.744 ;
     RECT  121.504 104.544 126.608 104.568 ;
     RECT  126.608 2.148 126.712 94.248 ;
     RECT  126.608 96.648 126.712 114.492 ;
     RECT  126.712 96.648 126.8 114.222 ;
     RECT  126.712 2.418 126.904 94.248 ;
     RECT  126.8 96.378 126.904 114.222 ;
     RECT  126.904 2.832 132.008 2.856 ;
     RECT  126.904 7.68 132.008 7.704 ;
     RECT  126.904 8.784 132.008 10.488 ;
     RECT  126.904 12.048 132.008 18.216 ;
     RECT  126.904 19.344 132.008 94.248 ;
     RECT  126.904 96.72 132.008 96.744 ;
     RECT  126.904 104.544 132.008 104.568 ;
     RECT  132.008 2.148 132.112 94.248 ;
     RECT  132.008 96.648 132.112 114.492 ;
     RECT  132.112 96.648 132.2 114.222 ;
     RECT  132.112 2.418 132.304 94.248 ;
     RECT  132.2 96.378 132.304 114.222 ;
     RECT  132.304 8.784 135.173 10.488 ;
     RECT  132.304 2.832 137.408 2.856 ;
     RECT  132.304 7.68 137.408 7.704 ;
     RECT  135.173 9.312 137.408 10.488 ;
     RECT  132.304 12.048 137.408 18.216 ;
     RECT  132.304 19.344 137.408 94.248 ;
     RECT  132.304 96.72 137.408 96.744 ;
     RECT  132.304 104.544 137.408 104.568 ;
     RECT  137.408 2.148 137.512 94.248 ;
     RECT  137.408 96.648 137.512 114.492 ;
     RECT  137.512 96.648 137.6 114.222 ;
     RECT  137.512 2.418 137.704 94.248 ;
     RECT  137.6 96.378 137.704 114.222 ;
     RECT  137.704 4.512 138.737 4.536 ;
     RECT  137.704 9.312 140.393 10.488 ;
     RECT  137.704 2.832 142.808 2.856 ;
     RECT  137.704 7.68 142.808 7.704 ;
     RECT  140.393 9.312 142.808 10.2 ;
     RECT  137.704 12.048 142.808 13.416 ;
     RECT  137.704 14.4 142.808 18.216 ;
     RECT  137.704 19.344 142.808 94.248 ;
     RECT  137.704 96.72 142.808 96.744 ;
     RECT  137.704 104.544 142.808 104.568 ;
     RECT  142.808 2.148 142.912 94.248 ;
     RECT  142.808 96.648 142.912 114.492 ;
     RECT  142.912 96.648 143 114.222 ;
     RECT  142.912 2.418 143.104 94.248 ;
     RECT  143 96.378 143.104 114.222 ;
     RECT  143.104 11.376 143.309 13.416 ;
     RECT  143.309 12.048 143.633 13.416 ;
     RECT  143.104 14.4 145.037 18.216 ;
     RECT  143.633 13.008 145.469 13.416 ;
     RECT  145.037 14.496 146.185 18.216 ;
     RECT  143.104 19.344 146.185 94.248 ;
     RECT  143.104 2.832 148.208 2.856 ;
     RECT  143.104 7.68 148.208 7.704 ;
     RECT  143.104 9.312 148.208 10.2 ;
     RECT  145.469 13.008 148.208 13.032 ;
     RECT  146.185 14.496 148.208 94.248 ;
     RECT  143.104 96.72 148.208 96.744 ;
     RECT  143.104 104.544 148.208 104.568 ;
     RECT  148.208 2.148 148.312 94.248 ;
     RECT  148.208 96.648 148.312 114.492 ;
     RECT  148.312 96.648 148.4 114.222 ;
     RECT  148.312 2.418 148.504 94.248 ;
     RECT  148.4 96.378 148.504 114.222 ;
     RECT  148.504 7.68 148.565 7.704 ;
     RECT  148.504 9.312 150.617 10.2 ;
     RECT  148.504 2.832 153.608 2.856 ;
     RECT  150.617 9.312 153.608 9.624 ;
     RECT  148.504 13.008 153.608 13.032 ;
     RECT  148.504 14.496 153.608 94.248 ;
     RECT  148.504 96.72 153.608 96.744 ;
     RECT  148.504 104.544 153.608 104.568 ;
     RECT  153.608 2.148 153.712 94.248 ;
     RECT  153.608 96.648 153.712 114.492 ;
     RECT  153.712 96.648 153.8 114.222 ;
     RECT  153.712 2.418 153.904 94.248 ;
     RECT  153.8 96.378 153.904 114.222 ;
     RECT  153.904 2.832 159.008 2.856 ;
     RECT  153.904 9.312 159.008 9.624 ;
     RECT  153.904 13.008 159.008 13.032 ;
     RECT  153.904 14.496 159.008 94.248 ;
     RECT  153.904 96.72 159.008 96.744 ;
     RECT  153.904 104.544 159.008 104.568 ;
     RECT  159.008 2.148 159.112 94.248 ;
     RECT  159.008 96.648 159.112 114.492 ;
     RECT  159.112 96.648 159.2 114.222 ;
     RECT  159.112 2.418 159.304 94.248 ;
     RECT  159.2 96.378 159.304 114.222 ;
     RECT  159.304 9.312 161.309 9.624 ;
     RECT  159.304 2.832 164.408 2.856 ;
     RECT  161.309 9.6 164.408 9.624 ;
     RECT  159.304 13.008 164.408 13.032 ;
     RECT  159.304 14.496 164.408 94.248 ;
     RECT  159.304 96.72 164.408 96.744 ;
     RECT  159.304 104.544 164.408 104.568 ;
     RECT  164.408 2.148 164.512 94.248 ;
     RECT  164.408 96.648 164.512 114.492 ;
     RECT  164.512 96.648 164.6 114.222 ;
     RECT  164.512 2.418 164.704 94.248 ;
     RECT  164.6 96.378 164.704 114.222 ;
     RECT  164.704 9.6 166.493 9.624 ;
     RECT  164.704 2.832 169.808 2.856 ;
     RECT  164.704 13.008 169.808 13.032 ;
     RECT  164.704 14.496 169.808 94.248 ;
     RECT  164.704 96.72 169.808 96.744 ;
     RECT  164.704 104.544 169.808 104.568 ;
     RECT  169.808 2.148 169.912 94.248 ;
     RECT  169.808 96.648 169.912 114.492 ;
     RECT  169.912 96.648 170 114.222 ;
     RECT  169.912 2.418 170.104 94.248 ;
     RECT  170 96.378 170.104 114.222 ;
     RECT  170.104 2.832 175.208 2.856 ;
     RECT  170.104 13.008 175.208 13.032 ;
     RECT  170.104 14.496 175.208 94.248 ;
     RECT  170.104 96.72 175.208 96.744 ;
     RECT  170.104 104.544 175.208 104.568 ;
     RECT  175.208 2.148 175.312 94.248 ;
     RECT  175.208 96.648 175.312 114.492 ;
     RECT  175.312 96.648 175.4 114.222 ;
     RECT  175.312 2.418 175.504 94.248 ;
     RECT  175.4 96.378 175.504 114.222 ;
     RECT  175.504 2.832 180.608 2.856 ;
     RECT  175.504 13.008 180.608 13.032 ;
     RECT  175.504 14.496 180.608 94.248 ;
     RECT  175.504 96.72 180.608 96.744 ;
     RECT  175.504 104.544 180.608 104.568 ;
     RECT  180.608 2.148 180.712 94.248 ;
     RECT  180.608 96.648 180.712 114.492 ;
     RECT  180.712 96.648 180.8 114.222 ;
     RECT  180.712 2.418 180.904 94.248 ;
     RECT  180.8 96.378 180.904 114.222 ;
     RECT  180.904 2.832 186.008 2.856 ;
     RECT  180.904 13.008 186.008 13.032 ;
     RECT  180.904 14.496 186.008 94.248 ;
     RECT  180.904 96.72 186.008 96.744 ;
     RECT  180.904 104.544 186.008 104.568 ;
     RECT  186.008 2.148 186.112 94.248 ;
     RECT  186.008 96.648 186.112 114.492 ;
     RECT  186.112 96.648 186.2 114.222 ;
     RECT  186.112 2.418 186.304 94.248 ;
     RECT  186.2 96.378 186.304 114.222 ;
     RECT  186.304 2.832 191.408 2.856 ;
     RECT  186.304 13.008 191.408 13.032 ;
     RECT  186.304 14.496 191.408 94.248 ;
     RECT  186.304 96.72 191.408 96.744 ;
     RECT  186.304 104.544 191.408 104.568 ;
     RECT  191.408 2.148 191.512 94.248 ;
     RECT  191.408 96.648 191.512 114.492 ;
     RECT  191.512 96.648 191.6 114.222 ;
     RECT  191.512 2.418 191.704 94.248 ;
     RECT  191.6 96.378 191.704 114.222 ;
     RECT  193.885 6.768 194.029 6.792 ;
     RECT  194.029 6.768 194.101 6.84 ;
     RECT  194.101 6.768 194.353 7.128 ;
     RECT  194.353 6.768 195.001 7.224 ;
     RECT  195.001 6.72 195.113 7.224 ;
     RECT  195.113 6.768 195.473 7.224 ;
     RECT  195.473 7.2 195.581 7.224 ;
     RECT  191.704 2.832 196.808 2.856 ;
     RECT  191.704 13.008 196.808 13.032 ;
     RECT  191.704 14.496 196.808 94.248 ;
     RECT  191.704 96.72 196.808 96.744 ;
     RECT  191.704 104.544 196.808 104.568 ;
     RECT  196.808 2.148 196.912 94.248 ;
     RECT  196.808 96.648 196.912 114.492 ;
     RECT  196.912 96.648 197 114.222 ;
     RECT  196.912 2.418 197.104 94.248 ;
     RECT  197 96.378 197.104 114.222 ;
     RECT  197.104 14.496 197.568 94.248 ;
     RECT  197.104 104.544 197.747 104.568 ;
     RECT  197.568 14.496 197.777 64.344 ;
     RECT  197.104 96.72 197.795 96.744 ;
     RECT  197.777 14.496 197.813 60.456 ;
     RECT  197.813 14.496 198.821 56.52 ;
     RECT  197.813 57.648 198.965 60.456 ;
     RECT  198.821 35.568 199.037 56.52 ;
     RECT  198.821 14.496 199.253 34.536 ;
     RECT  197.104 13.008 199.501 13.032 ;
     RECT  199.253 14.496 199.501 34.056 ;
     RECT  199.037 35.856 199.505 56.52 ;
     RECT  198.965 57.744 199.505 60.456 ;
     RECT  197.777 61.68 199.505 61.704 ;
     RECT  197.777 62.736 199.505 62.76 ;
     RECT  199.505 35.856 199.571 56.088 ;
     RECT  199.501 13.008 199.829 34.056 ;
     RECT  199.829 13.008 199.909 33.768 ;
     RECT  199.571 36.048 199.937 56.088 ;
     RECT  197.777 63.984 199.973 64.344 ;
     RECT  199.909 13.008 200.009 26.76 ;
     RECT  199.937 36.432 200.045 56.088 ;
     RECT  199.505 58.128 200.045 59.256 ;
     RECT  200.045 36.432 200.081 44.808 ;
     RECT  200.045 45.84 200.081 56.088 ;
     RECT  200.009 13.008 200.099 25.992 ;
     RECT  200.081 36.432 200.117 44.424 ;
     RECT  200.081 46.32 200.117 56.088 ;
     RECT  200.117 37.488 200.153 44.424 ;
     RECT  200.117 46.32 200.153 46.728 ;
     RECT  200.153 37.488 200.189 42.984 ;
     RECT  200.153 44.304 200.189 44.424 ;
     RECT  200.117 48.24 200.189 56.088 ;
     RECT  200.117 36.432 200.225 36.456 ;
     RECT  200.189 37.488 200.225 38.376 ;
     RECT  200.189 42 200.225 42.984 ;
     RECT  200.153 46.32 200.225 46.536 ;
     RECT  200.189 48.24 200.225 53.352 ;
     RECT  200.045 58.128 200.261 58.152 ;
     RECT  200.189 39.504 200.297 40.872 ;
     RECT  200.225 42.576 200.297 42.984 ;
     RECT  200.225 37.488 200.333 37.512 ;
     RECT  200.297 40.464 200.333 40.872 ;
     RECT  200.225 49.2 200.333 53.352 ;
     RECT  200.189 54.912 200.333 56.088 ;
     RECT  200.333 40.752 200.369 40.776 ;
     RECT  200.333 49.824 200.405 51.384 ;
     RECT  199.909 27.984 200.441 33.768 ;
     RECT  200.189 44.304 200.441 44.328 ;
     RECT  200.099 14.496 200.483 25.992 ;
     RECT  200.225 46.512 200.513 46.536 ;
     RECT  200.441 28.512 200.837 33.768 ;
     RECT  199.717 61.92 200.869 61.944 ;
     RECT  200.837 28.512 200.873 29.256 ;
     RECT  200.837 30.288 200.909 33.768 ;
     RECT  200.483 14.496 200.963 19.368 ;
     RECT  200.483 20.832 201.017 25.992 ;
     RECT  200.873 28.512 201.025 28.536 ;
     RECT  200.909 32.112 201.053 33.768 ;
     RECT  201.017 25.68 201.109 25.992 ;
     RECT  200.333 52.752 201.349 53.016 ;
     RECT  200.869 61.152 201.445 61.944 ;
     RECT  200.333 54.912 201.493 54.936 ;
     RECT  200.333 56.064 201.493 56.088 ;
     RECT  201.445 60.864 201.541 61.944 ;
     RECT  200.405 51.36 201.589 51.384 ;
     RECT  201.397 48.768 201.637 48.792 ;
     RECT  201.637 48.672 201.685 48.792 ;
     RECT  200.405 49.824 201.685 49.848 ;
     RECT  201.685 48.672 201.733 49.848 ;
     RECT  201.589 51.36 201.733 51.672 ;
     RECT  201.733 48.672 201.829 51.672 ;
     RECT  201.829 48.432 201.925 51.672 ;
     RECT  201.349 52.704 201.925 53.016 ;
     RECT  197.104 2.832 202.208 2.856 ;
     RECT  200.099 13.008 202.208 13.032 ;
     RECT  200.963 14.496 202.208 18.504 ;
     RECT  201.017 20.832 202.208 24.696 ;
     RECT  201.109 25.68 202.208 26.376 ;
     RECT  200.909 30.288 202.208 31.08 ;
     RECT  201.053 32.112 202.208 32.616 ;
     RECT  201.053 33.744 202.208 33.768 ;
     RECT  201.925 48.432 202.208 53.016 ;
     RECT  201.493 54.912 202.208 56.088 ;
     RECT  202.021 58.224 202.208 58.248 ;
     RECT  200.045 59.232 202.208 59.256 ;
     RECT  201.541 60.624 202.208 61.944 ;
     RECT  199.973 64.32 202.208 64.344 ;
     RECT  197.568 67.008 202.208 67.032 ;
     RECT  202.208 2.148 202.312 114.492 ;
     RECT  202.312 2.418 202.504 114.222 ;
     RECT  202.504 20.976 202.643 24.696 ;
     RECT  202.504 16.848 202.787 17.448 ;
     RECT  202.787 16.848 202.835 17.4 ;
     RECT  202.643 21.408 202.883 24.696 ;
     RECT  202.504 48.432 202.961 53.016 ;
     RECT  202.961 51.648 203.969 53.016 ;
     RECT  202.961 48.432 204.509 50.616 ;
     RECT  202.504 60.528 204.653 61.944 ;
     RECT  203.969 52.272 204.977 53.016 ;
     RECT  204.509 48.672 205.045 50.616 ;
     RECT  202.883 23.616 205.157 24.696 ;
     RECT  205.045 48.672 205.157 50.76 ;
     RECT  204.977 52.704 205.157 53.016 ;
     RECT  202.504 55.008 205.436 56.232 ;
     RECT  205.157 52.752 205.477 53.016 ;
     RECT  205.436 54.336 205.477 56.232 ;
     RECT  202.504 2.832 205.481 2.856 ;
     RECT  202.504 64.32 205.481 64.344 ;
     RECT  205.477 52.752 205.523 56.232 ;
     RECT  205.157 48.672 205.841 49.848 ;
     RECT  205.841 48.672 206.057 49.224 ;
     RECT  206.057 48.768 206.129 49.224 ;
     RECT  202.504 67.008 206.129 67.032 ;
     RECT  202.504 26.496 206.377 26.52 ;
     RECT  206.377 26.496 206.417 26.616 ;
     RECT  205.513 51.6 206.417 51.624 ;
     RECT  205.157 24.672 206.597 24.696 ;
     RECT  205.523 52.752 206.809 53.592 ;
     RECT  206.129 48.96 206.845 49.224 ;
     RECT  205.523 55.248 206.845 56.232 ;
     RECT  202.504 57.84 206.845 59.256 ;
     RECT  204.653 60.624 207.349 61.944 ;
     RECT  206.629 64.32 207.349 64.344 ;
     RECT  206.845 55.152 207.385 56.232 ;
     RECT  206.845 57.84 207.385 59.496 ;
     RECT  207.349 60.624 207.385 64.344 ;
     RECT  206.809 52.416 207.452 53.592 ;
     RECT  207.452 52.416 207.493 54.072 ;
     RECT  207.385 55.152 207.493 59.496 ;
     RECT  202.504 14.496 207.608 14.52 ;
     RECT  202.835 17.376 207.608 17.4 ;
     RECT  202.504 18.48 207.608 18.504 ;
     RECT  202.883 21.408 207.608 22.536 ;
     RECT  205.157 23.616 207.608 23.64 ;
     RECT  206.417 26.592 207.608 26.616 ;
     RECT  203.893 27.6 207.608 27.624 ;
     RECT  202.504 46.752 207.608 46.824 ;
     RECT  206.845 48.96 207.608 49.896 ;
     RECT  207.493 52.416 207.608 59.496 ;
     RECT  207.385 60.624 207.608 65.016 ;
     RECT  207.608 2.148 207.712 114.492 ;
     RECT  207.712 2.418 207.904 114.222 ;
     RECT  207.904 57.024 207.965 59.304 ;
     RECT  207.904 53.568 208.001 53.592 ;
     RECT  207.904 62.736 208.037 63.816 ;
     RECT  207.904 52.512 208.181 52.536 ;
     RECT  207.904 49.872 208.469 51.384 ;
     RECT  207.904 21.408 208.883 22.536 ;
     RECT  208.037 63.264 208.901 63.816 ;
     RECT  207.904 54.672 208.933 56.04 ;
     RECT  207.904 60.624 208.933 60.648 ;
     RECT  207.965 57.216 209.005 59.304 ;
     RECT  207.904 67.296 209.045 67.32 ;
     RECT  209.005 57.024 209.125 59.304 ;
     RECT  208.933 60.624 209.125 60.984 ;
     RECT  208.469 50.112 209.473 51.384 ;
     RECT  209.473 49.488 209.513 51.384 ;
     RECT  207.904 65.568 209.605 65.592 ;
     RECT  209.513 50.736 209.689 51.384 ;
     RECT  209.605 64.896 209.729 65.592 ;
     RECT  207.904 26.592 209.837 26.616 ;
     RECT  208.933 54.48 210.053 56.04 ;
     RECT  209.689 50.736 210.085 51.96 ;
     RECT  208.901 63.264 210.121 63.768 ;
     RECT  210.053 55.056 210.265 56.04 ;
     RECT  209.125 57.024 210.265 60.984 ;
     RECT  210.121 62.88 210.265 63.768 ;
     RECT  210.265 55.056 210.301 60.984 ;
     RECT  210.265 61.968 210.301 63.768 ;
     RECT  210.301 55.056 210.341 63.768 ;
     RECT  209.513 49.488 210.481 49.512 ;
     RECT  210.085 50.736 210.481 52.824 ;
     RECT  210.481 49.488 210.589 52.824 ;
     RECT  207.904 48.336 210.593 48.36 ;
     RECT  210.589 49.488 210.668 53.496 ;
     RECT  210.668 48.72 210.697 53.496 ;
     RECT  210.697 48.72 210.755 53.544 ;
     RECT  209.729 65.568 210.913 65.592 ;
     RECT  207.904 27.6 210.995 27.624 ;
     RECT  210.341 60.144 211.057 63.768 ;
     RECT  210.913 65.568 211.057 65.688 ;
     RECT  211.057 60.144 211.093 63.816 ;
     RECT  211.057 65.52 211.093 65.688 ;
     RECT  210.755 49.488 211.097 53.544 ;
     RECT  207.904 14.496 211.139 14.52 ;
     RECT  211.093 65.424 211.165 65.688 ;
     RECT  210.341 55.056 211.189 58.776 ;
     RECT  207.904 17.376 211.235 17.4 ;
     RECT  211.097 52.8 211.277 53.544 ;
     RECT  211.093 60.144 211.345 63.864 ;
     RECT  209.653 67.248 211.381 67.272 ;
     RECT  211.165 65.424 211.417 65.784 ;
     RECT  211.381 66.864 211.417 67.272 ;
     RECT  211.189 54.72 211.633 58.776 ;
     RECT  211.633 54.72 211.745 58.92 ;
     RECT  208.883 21.504 211.763 22.536 ;
     RECT  207.904 23.616 211.859 23.64 ;
     RECT  211.745 58.176 211.885 58.92 ;
     RECT  211.345 60.144 211.885 64.056 ;
     RECT  211.885 58.176 212.173 64.392 ;
     RECT  211.417 65.424 212.173 67.272 ;
     RECT  211.669 46.752 212.281 46.776 ;
     RECT  212.173 58.176 212.317 67.272 ;
     RECT  211.097 49.488 212.425 51.72 ;
     RECT  212.425 49.44 212.497 51.72 ;
     RECT  211.277 52.944 212.497 53.544 ;
     RECT  212.497 49.44 212.569 53.544 ;
     RECT  211.745 54.72 212.569 57.048 ;
     RECT  212.317 58.176 212.569 67.752 ;
     RECT  212.245 48.432 212.893 48.456 ;
     RECT  212.569 49.44 212.893 57.048 ;
     RECT  212.569 58.176 212.893 67.848 ;
     RECT  212.893 48.432 212.965 67.848 ;
     RECT  212.353 68.88 212.965 68.904 ;
     RECT  207.904 18.48 213.008 18.504 ;
     RECT  211.763 22.464 213.008 22.536 ;
     RECT  212.281 46.752 213.008 46.824 ;
     RECT  212.965 48.432 213.008 68.904 ;
     RECT  213.008 2.148 213.112 114.492 ;
     RECT  213.112 2.418 213.304 114.222 ;
     RECT  213.304 91.776 213.797 91.8 ;
     RECT  213.304 48.384 214.477 69.336 ;
     RECT  213.304 46.128 214.873 46.152 ;
     RECT  214.477 48.192 214.981 69.336 ;
     RECT  214.981 47.856 215.089 69.336 ;
     RECT  214.981 70.32 215.089 70.344 ;
     RECT  214.873 46.128 215.125 46.872 ;
     RECT  215.089 47.856 215.125 70.344 ;
     RECT  215.125 46.128 215.413 70.344 ;
     RECT  213.304 74.928 215.489 74.952 ;
     RECT  215.413 46.128 215.516 71.304 ;
     RECT  215.516 45.6 215.549 71.304 ;
     RECT  215.549 45.6 216.035 71.352 ;
     RECT  213.304 22.512 216.131 22.536 ;
     RECT  215.221 87.216 216.389 87.24 ;
     RECT  216.524 44.976 216.673 45 ;
     RECT  216.035 46.08 216.853 71.352 ;
     RECT  216.853 46.08 216.857 71.88 ;
     RECT  216.857 46.08 216.965 54.648 ;
     RECT  216.965 46.176 217.181 54.648 ;
     RECT  216.673 44.88 217.249 45 ;
     RECT  217.181 48.96 217.253 54.648 ;
     RECT  216.857 55.68 217.289 71.88 ;
     RECT  217.181 46.176 217.475 47.88 ;
     RECT  217.253 49.344 217.505 54.648 ;
     RECT  217.475 46.176 217.516 47.736 ;
     RECT  217.505 49.344 217.523 50.808 ;
     RECT  217.523 49.632 217.549 50.808 ;
     RECT  217.289 69.888 217.549 71.88 ;
     RECT  217.549 69.888 217.613 70.824 ;
     RECT  217.549 49.776 217.649 50.808 ;
     RECT  217.613 70.656 217.715 70.824 ;
     RECT  217.289 55.68 217.721 68.904 ;
     RECT  217.249 44.88 217.793 45.144 ;
     RECT  217.516 46.8 217.829 47.736 ;
     RECT  217.829 46.8 217.865 47.64 ;
     RECT  217.721 55.68 217.865 68.568 ;
     RECT  217.865 68.544 217.937 68.568 ;
     RECT  217.865 47.616 218.009 47.64 ;
     RECT  217.505 51.792 218.041 54.648 ;
     RECT  218.041 51.792 218.077 54.696 ;
     RECT  217.865 55.68 218.077 67.272 ;
     RECT  217.793 44.88 218.153 44.904 ;
     RECT  217.549 71.856 218.153 71.88 ;
     RECT  217.649 49.776 218.617 50.472 ;
     RECT  218.077 51.792 218.617 67.272 ;
     RECT  217.715 70.656 218.657 70.728 ;
     RECT  218.657 70.704 219.197 70.728 ;
     RECT  218.617 49.776 219.265 67.272 ;
     RECT  219.265 49.392 220.236 49.416 ;
     RECT  219.265 49.416 220.284 49.488 ;
     RECT  219.265 49.488 220.236 49.512 ;
     RECT  219.265 49.512 220.284 49.584 ;
     RECT  219.265 49.584 220.236 49.608 ;
     RECT  219.265 49.608 220.284 49.68 ;
     RECT  219.265 49.68 220.236 49.704 ;
     RECT  219.265 49.704 220.284 49.776 ;
     RECT  219.265 49.776 220.236 49.8 ;
     RECT  219.265 49.8 220.284 49.872 ;
     RECT  219.265 49.872 220.236 49.896 ;
     RECT  219.265 49.896 220.284 49.968 ;
     RECT  219.265 49.968 220.236 49.992 ;
     RECT  219.265 49.992 220.284 50.064 ;
     RECT  219.265 50.064 220.236 50.088 ;
     RECT  219.265 50.088 220.284 50.16 ;
     RECT  219.265 50.16 220.236 50.184 ;
     RECT  219.265 50.184 220.284 50.256 ;
     RECT  219.265 50.256 220.236 50.28 ;
     RECT  219.265 50.28 220.284 50.352 ;
     RECT  219.265 50.352 220.236 50.376 ;
     RECT  219.265 50.376 220.284 50.448 ;
     RECT  219.265 50.448 220.236 50.472 ;
     RECT  219.265 50.472 220.284 50.544 ;
     RECT  219.265 50.544 220.236 50.568 ;
     RECT  219.265 50.568 220.284 50.64 ;
     RECT  219.265 50.64 220.236 50.664 ;
     RECT  219.265 50.664 220.284 50.736 ;
     RECT  219.265 50.736 220.236 50.76 ;
     RECT  219.265 50.76 220.284 50.832 ;
     RECT  219.265 50.832 220.236 50.856 ;
     RECT  219.265 50.856 220.284 50.928 ;
     RECT  219.265 50.928 220.236 50.952 ;
     RECT  219.265 50.952 220.284 51.024 ;
     RECT  219.265 51.024 220.236 51.048 ;
     RECT  219.265 51.048 220.284 51.12 ;
     RECT  219.265 51.12 220.236 51.144 ;
     RECT  219.265 51.144 220.284 51.216 ;
     RECT  219.265 51.216 220.236 51.24 ;
     RECT  219.265 51.24 220.284 51.312 ;
     RECT  219.265 51.312 220.236 51.336 ;
     RECT  219.265 51.336 220.284 51.408 ;
     RECT  219.265 51.408 220.236 51.432 ;
     RECT  219.265 51.432 220.284 51.504 ;
     RECT  219.265 51.504 220.236 51.528 ;
     RECT  219.265 51.528 220.284 51.6 ;
     RECT  219.265 51.6 220.236 51.624 ;
     RECT  219.265 51.624 220.284 51.696 ;
     RECT  219.265 51.696 220.236 51.72 ;
     RECT  219.265 51.72 220.284 51.792 ;
     RECT  219.265 51.792 220.236 51.816 ;
     RECT  219.265 51.816 220.284 51.888 ;
     RECT  219.265 51.888 220.236 51.912 ;
     RECT  219.265 51.912 220.284 51.984 ;
     RECT  219.265 51.984 220.236 52.008 ;
     RECT  219.265 52.008 220.284 52.08 ;
     RECT  219.265 52.08 220.236 52.104 ;
     RECT  219.265 52.104 220.284 52.176 ;
     RECT  219.265 52.176 220.236 52.2 ;
     RECT  219.265 52.2 220.284 52.272 ;
     RECT  219.265 52.272 220.236 52.296 ;
     RECT  219.265 52.296 220.284 52.368 ;
     RECT  219.265 52.368 220.236 52.392 ;
     RECT  219.265 52.392 220.284 52.464 ;
     RECT  219.265 52.464 220.236 52.488 ;
     RECT  219.265 52.488 220.284 52.56 ;
     RECT  219.265 52.56 220.236 52.584 ;
     RECT  219.265 52.584 220.284 52.656 ;
     RECT  219.265 52.656 220.236 52.68 ;
     RECT  219.265 52.68 220.284 52.752 ;
     RECT  219.265 52.752 220.236 52.776 ;
     RECT  219.265 52.776 220.284 52.848 ;
     RECT  219.265 52.848 220.236 52.872 ;
     RECT  219.265 52.872 220.284 52.944 ;
     RECT  219.265 52.944 220.236 52.968 ;
     RECT  219.265 52.968 220.284 53.04 ;
     RECT  219.265 53.04 220.236 53.064 ;
     RECT  219.265 53.064 220.284 53.136 ;
     RECT  219.265 53.136 220.236 53.16 ;
     RECT  219.265 53.16 220.284 53.232 ;
     RECT  219.265 53.232 220.236 53.256 ;
     RECT  219.265 53.256 220.284 53.328 ;
     RECT  219.265 53.328 220.236 53.352 ;
     RECT  219.265 53.352 220.284 53.424 ;
     RECT  219.265 53.424 220.236 53.448 ;
     RECT  219.265 53.448 220.284 53.52 ;
     RECT  219.265 53.52 220.236 53.544 ;
     RECT  219.265 53.544 220.284 53.616 ;
     RECT  219.265 53.616 220.236 53.64 ;
     RECT  219.265 53.64 220.284 53.712 ;
     RECT  219.265 53.712 220.236 53.736 ;
     RECT  219.265 53.736 220.284 53.808 ;
     RECT  219.265 53.808 220.236 53.832 ;
     RECT  219.265 53.832 220.284 53.904 ;
     RECT  219.265 53.904 220.236 53.928 ;
     RECT  219.265 53.928 220.284 54 ;
     RECT  219.265 54 220.236 54.024 ;
     RECT  219.265 54.024 220.284 54.096 ;
     RECT  219.265 54.096 220.236 54.12 ;
     RECT  219.265 54.12 220.284 54.192 ;
     RECT  219.265 54.192 220.236 54.216 ;
     RECT  219.265 54.216 220.284 54.288 ;
     RECT  219.265 54.288 220.236 54.312 ;
     RECT  219.265 54.312 220.284 54.384 ;
     RECT  219.265 54.384 220.236 54.408 ;
     RECT  219.265 54.408 220.284 54.48 ;
     RECT  219.265 54.48 220.236 54.504 ;
     RECT  219.265 54.504 220.284 54.576 ;
     RECT  219.265 54.576 220.236 54.6 ;
     RECT  219.265 54.6 220.284 54.672 ;
     RECT  219.265 54.672 220.236 54.696 ;
     RECT  219.265 54.696 220.284 54.768 ;
     RECT  219.265 54.768 220.236 54.792 ;
     RECT  219.265 54.792 220.284 54.864 ;
     RECT  219.265 54.864 220.236 54.888 ;
     RECT  219.265 54.888 220.284 54.96 ;
     RECT  219.265 54.96 220.236 54.984 ;
     RECT  219.265 54.984 220.284 55.056 ;
     RECT  219.265 55.056 220.236 55.08 ;
     RECT  219.265 55.08 220.284 55.152 ;
     RECT  219.265 55.152 220.236 55.176 ;
     RECT  219.265 55.176 220.284 55.248 ;
     RECT  219.265 55.248 220.236 55.272 ;
     RECT  219.265 55.272 220.284 55.344 ;
     RECT  219.265 55.344 220.236 55.368 ;
     RECT  219.265 55.368 220.284 55.44 ;
     RECT  219.265 55.44 220.236 55.464 ;
     RECT  219.265 55.464 220.284 55.536 ;
     RECT  219.265 55.536 220.236 55.56 ;
     RECT  219.265 55.56 220.284 55.632 ;
     RECT  219.265 55.632 220.236 55.656 ;
     RECT  219.265 55.656 220.284 55.728 ;
     RECT  219.265 55.728 220.236 55.752 ;
     RECT  219.265 55.752 220.284 55.824 ;
     RECT  219.265 55.824 220.236 55.848 ;
     RECT  219.265 55.848 220.284 55.92 ;
     RECT  219.265 55.92 220.236 55.944 ;
     RECT  219.265 55.944 220.284 56.016 ;
     RECT  219.265 56.016 220.236 56.04 ;
     RECT  219.265 56.04 220.284 56.112 ;
     RECT  219.265 56.112 220.236 56.136 ;
     RECT  219.265 56.136 220.284 56.208 ;
     RECT  219.265 56.208 220.236 56.232 ;
     RECT  219.265 56.232 220.284 56.304 ;
     RECT  219.265 56.304 220.236 56.328 ;
     RECT  219.265 56.328 220.284 56.4 ;
     RECT  219.265 56.4 220.236 56.424 ;
     RECT  219.265 56.424 220.284 56.496 ;
     RECT  219.265 56.496 220.236 56.52 ;
     RECT  219.265 56.52 220.284 56.592 ;
     RECT  219.265 56.592 220.236 56.616 ;
     RECT  219.265 56.616 220.284 56.688 ;
     RECT  219.265 56.688 220.236 56.712 ;
     RECT  219.265 56.712 220.284 56.784 ;
     RECT  219.265 56.784 220.236 56.808 ;
     RECT  219.265 56.808 220.284 56.88 ;
     RECT  219.265 56.88 220.236 56.904 ;
     RECT  219.265 56.904 220.284 56.976 ;
     RECT  219.265 56.976 220.236 57 ;
     RECT  219.265 57 220.284 57.072 ;
     RECT  219.265 57.072 220.236 57.096 ;
     RECT  219.265 57.096 220.284 57.168 ;
     RECT  219.265 57.168 220.236 57.192 ;
     RECT  219.265 57.192 220.284 57.264 ;
     RECT  219.265 57.264 220.236 57.288 ;
     RECT  219.265 57.288 220.284 57.36 ;
     RECT  219.265 57.36 220.236 57.384 ;
     RECT  219.265 57.384 220.284 57.456 ;
     RECT  219.265 57.456 220.236 57.48 ;
     RECT  219.265 57.48 220.284 57.552 ;
     RECT  219.265 57.552 220.236 57.576 ;
     RECT  219.265 57.576 220.284 57.648 ;
     RECT  219.265 57.648 220.236 57.672 ;
     RECT  219.265 57.672 220.284 57.744 ;
     RECT  219.265 57.744 220.236 57.768 ;
     RECT  219.265 57.768 220.284 57.84 ;
     RECT  219.265 57.84 220.236 57.864 ;
     RECT  219.265 57.864 220.284 57.936 ;
     RECT  219.265 57.936 220.236 57.96 ;
     RECT  219.265 57.96 220.284 58.032 ;
     RECT  219.265 58.032 220.236 58.056 ;
     RECT  219.265 58.056 220.284 58.128 ;
     RECT  219.265 58.128 220.236 58.152 ;
     RECT  219.265 58.152 220.284 58.224 ;
     RECT  219.265 58.224 220.236 58.248 ;
     RECT  219.265 58.248 220.284 58.32 ;
     RECT  219.265 58.32 220.236 58.344 ;
     RECT  219.265 58.344 220.284 58.416 ;
     RECT  219.265 58.416 220.236 58.44 ;
     RECT  219.265 58.44 220.284 58.512 ;
     RECT  219.265 58.512 220.236 58.536 ;
     RECT  219.265 58.536 220.284 58.608 ;
     RECT  219.265 58.608 220.236 58.632 ;
     RECT  219.265 58.632 220.284 58.704 ;
     RECT  219.265 58.704 220.236 58.728 ;
     RECT  219.265 58.728 220.284 58.8 ;
     RECT  219.265 58.8 220.236 58.824 ;
     RECT  219.265 58.824 220.284 58.896 ;
     RECT  219.265 58.896 220.236 58.92 ;
     RECT  219.265 58.92 220.284 58.992 ;
     RECT  219.265 58.992 220.236 59.016 ;
     RECT  219.265 59.016 220.284 59.088 ;
     RECT  219.265 59.088 220.236 59.112 ;
     RECT  219.265 59.112 220.284 59.184 ;
     RECT  219.265 59.184 220.236 59.208 ;
     RECT  219.265 59.208 220.284 59.28 ;
     RECT  219.265 59.28 220.236 59.304 ;
     RECT  219.265 59.304 220.284 59.376 ;
     RECT  219.265 59.376 220.236 59.4 ;
     RECT  219.265 59.4 220.284 59.472 ;
     RECT  219.265 59.472 220.236 59.496 ;
     RECT  219.265 59.496 220.284 59.568 ;
     RECT  219.265 59.568 220.236 59.592 ;
     RECT  219.265 59.592 220.284 59.664 ;
     RECT  219.265 59.664 220.236 59.688 ;
     RECT  219.265 59.688 220.284 59.76 ;
     RECT  219.265 59.76 220.236 59.784 ;
     RECT  219.265 59.784 220.284 59.856 ;
     RECT  219.265 59.856 220.236 59.88 ;
     RECT  219.265 59.88 220.284 59.952 ;
     RECT  219.265 59.952 220.236 59.976 ;
     RECT  219.265 59.976 220.284 60.048 ;
     RECT  219.265 60.048 220.236 60.072 ;
     RECT  219.265 60.072 220.284 60.144 ;
     RECT  219.265 60.144 220.236 60.168 ;
     RECT  219.265 60.168 220.284 60.24 ;
     RECT  219.265 60.24 220.236 60.264 ;
     RECT  219.265 60.264 220.284 60.336 ;
     RECT  219.265 60.336 220.236 60.36 ;
     RECT  219.265 60.36 220.284 60.432 ;
     RECT  219.265 60.432 220.236 60.456 ;
     RECT  219.265 60.456 220.284 60.528 ;
     RECT  219.265 60.528 220.236 60.552 ;
     RECT  219.265 60.552 220.284 60.624 ;
     RECT  219.265 60.624 220.236 60.648 ;
     RECT  219.265 60.648 220.284 60.72 ;
     RECT  219.265 60.72 220.236 60.744 ;
     RECT  219.265 60.744 220.284 60.816 ;
     RECT  219.265 60.816 220.236 60.84 ;
     RECT  219.265 60.84 220.284 60.912 ;
     RECT  219.265 60.912 220.236 60.936 ;
     RECT  219.265 60.936 220.284 61.008 ;
     RECT  219.265 61.008 220.236 61.032 ;
     RECT  219.265 61.032 220.284 61.104 ;
     RECT  219.265 61.104 220.236 61.128 ;
     RECT  219.265 61.128 220.284 61.2 ;
     RECT  219.265 61.2 220.236 61.224 ;
     RECT  219.265 61.224 220.284 61.296 ;
     RECT  219.265 61.296 220.236 61.32 ;
     RECT  219.265 61.32 220.284 61.392 ;
     RECT  219.265 61.392 220.236 61.416 ;
     RECT  219.265 61.416 220.284 61.488 ;
     RECT  219.265 61.488 220.236 61.512 ;
     RECT  219.265 61.512 220.284 61.584 ;
     RECT  219.265 61.584 220.236 61.608 ;
     RECT  219.265 61.608 220.284 61.68 ;
     RECT  219.265 61.68 220.236 61.704 ;
     RECT  219.265 61.704 220.284 61.776 ;
     RECT  219.265 61.776 220.236 61.8 ;
     RECT  219.265 61.8 220.284 61.872 ;
     RECT  219.265 61.872 220.236 61.896 ;
     RECT  219.265 61.896 220.284 61.968 ;
     RECT  219.265 61.968 220.236 61.992 ;
     RECT  219.265 61.992 220.284 62.064 ;
     RECT  219.265 62.064 220.236 62.088 ;
     RECT  219.265 62.088 220.284 62.16 ;
     RECT  219.265 62.16 220.236 62.184 ;
     RECT  219.265 62.184 220.284 62.256 ;
     RECT  219.265 62.256 220.236 62.28 ;
     RECT  219.265 62.28 220.284 62.352 ;
     RECT  219.265 62.352 220.236 62.376 ;
     RECT  219.265 62.376 220.284 62.448 ;
     RECT  219.265 62.448 220.236 62.472 ;
     RECT  219.265 62.472 220.284 62.544 ;
     RECT  219.265 62.544 220.236 62.568 ;
     RECT  219.265 62.568 220.284 62.64 ;
     RECT  219.265 62.64 220.236 62.664 ;
     RECT  219.265 62.664 220.284 62.736 ;
     RECT  219.265 62.736 220.236 62.76 ;
     RECT  219.265 62.76 220.284 62.832 ;
     RECT  219.265 62.832 220.236 62.856 ;
     RECT  219.265 62.856 220.284 62.928 ;
     RECT  219.265 62.928 220.236 62.952 ;
     RECT  219.265 62.952 220.284 63.024 ;
     RECT  219.265 63.024 220.236 63.048 ;
     RECT  219.265 63.048 220.284 63.12 ;
     RECT  219.265 63.12 220.236 63.144 ;
     RECT  219.265 63.144 220.284 63.216 ;
     RECT  219.265 63.216 220.236 63.24 ;
     RECT  219.265 63.24 220.284 63.312 ;
     RECT  219.265 63.312 220.236 63.336 ;
     RECT  219.265 63.336 220.284 63.408 ;
     RECT  219.265 63.408 220.236 63.432 ;
     RECT  219.265 63.432 220.284 63.504 ;
     RECT  219.265 63.504 220.236 63.528 ;
     RECT  219.265 63.528 220.284 63.6 ;
     RECT  219.265 63.6 220.236 63.624 ;
     RECT  219.265 63.624 220.284 63.696 ;
     RECT  219.265 63.696 220.236 63.72 ;
     RECT  219.265 63.72 220.284 63.792 ;
     RECT  219.265 63.792 220.236 63.816 ;
     RECT  219.265 63.816 220.284 63.888 ;
     RECT  219.265 63.888 220.236 63.912 ;
     RECT  219.265 63.912 220.284 63.984 ;
     RECT  219.265 63.984 220.236 64.008 ;
     RECT  219.265 64.008 220.284 64.08 ;
     RECT  219.265 64.08 220.236 64.104 ;
     RECT  219.265 64.104 220.284 64.176 ;
     RECT  219.265 64.176 220.236 64.2 ;
     RECT  219.265 64.2 220.284 64.272 ;
     RECT  219.265 64.272 220.236 64.296 ;
     RECT  219.265 64.296 220.284 64.368 ;
     RECT  219.265 64.368 220.236 64.392 ;
     RECT  219.265 64.392 220.284 64.464 ;
     RECT  219.265 64.464 220.236 64.488 ;
     RECT  219.265 64.488 220.284 64.56 ;
     RECT  219.265 64.56 220.236 64.584 ;
     RECT  219.265 64.584 220.284 64.656 ;
     RECT  219.265 64.656 220.236 64.68 ;
     RECT  219.265 64.68 220.284 64.752 ;
     RECT  219.265 64.752 220.236 64.776 ;
     RECT  219.265 64.776 220.284 64.848 ;
     RECT  219.265 64.848 220.236 64.872 ;
     RECT  219.265 64.872 220.284 64.944 ;
     RECT  219.265 64.944 220.236 64.968 ;
     RECT  219.265 64.968 220.284 65.04 ;
     RECT  219.265 65.04 220.236 65.064 ;
     RECT  219.265 65.064 220.284 65.136 ;
     RECT  219.265 65.136 220.236 65.16 ;
     RECT  219.265 65.16 220.284 65.232 ;
     RECT  219.265 65.232 220.236 65.256 ;
     RECT  219.265 65.256 220.284 65.328 ;
     RECT  219.265 65.328 220.236 65.352 ;
     RECT  219.265 65.352 220.284 65.424 ;
     RECT  219.265 65.424 220.236 65.448 ;
     RECT  219.265 65.448 220.284 65.52 ;
     RECT  219.265 65.52 220.236 65.544 ;
     RECT  219.265 65.544 220.284 65.616 ;
     RECT  219.265 65.616 220.236 65.64 ;
     RECT  219.265 65.64 220.284 65.712 ;
     RECT  219.265 65.712 220.236 65.736 ;
     RECT  219.265 65.736 220.284 65.808 ;
     RECT  219.265 65.808 220.236 65.832 ;
     RECT  219.265 65.832 220.284 65.904 ;
     RECT  219.265 65.904 220.236 65.928 ;
     RECT  219.265 65.928 220.284 66 ;
     RECT  219.265 66 220.236 66.024 ;
     RECT  219.265 66.024 220.284 66.096 ;
     RECT  219.265 66.096 220.236 66.12 ;
     RECT  219.265 66.12 220.284 66.192 ;
     RECT  219.265 66.192 220.236 66.216 ;
     RECT  219.265 66.216 220.284 66.288 ;
     RECT  219.265 66.288 220.236 66.312 ;
     RECT  219.265 66.312 220.284 66.384 ;
     RECT  219.265 66.384 220.236 66.408 ;
     RECT  219.265 66.408 220.284 66.48 ;
     RECT  219.265 66.48 220.236 66.504 ;
     RECT  219.265 66.504 220.284 66.576 ;
     RECT  219.265 66.576 220.236 66.6 ;
     RECT  219.265 66.6 220.284 66.672 ;
     RECT  219.265 66.672 220.236 66.696 ;
     RECT  219.265 66.696 220.284 66.768 ;
     RECT  219.265 66.768 220.236 66.792 ;
     RECT  219.265 66.792 220.284 66.864 ;
     RECT  219.265 66.864 220.236 66.888 ;
     RECT  219.265 66.888 220.284 66.96 ;
     RECT  219.265 66.96 220.236 66.984 ;
     RECT  219.265 66.984 220.284 67.056 ;
     RECT  219.265 67.056 220.236 67.08 ;
     RECT  219.265 67.08 220.284 67.152 ;
     RECT  219.265 67.152 220.236 67.176 ;
     RECT  219.265 67.176 220.284 67.248 ;
     RECT  219.265 67.248 220.236 67.272 ;
    LAYER M5 ;
     RECT  19.68 1.573 19.704 1.669 ;
     RECT  19.2 1.669 19.704 2.137 ;
     RECT  2.4 2.137 2.52 2.151 ;
     RECT  7.8 2.137 7.92 2.151 ;
     RECT  13.2 2.137 13.32 2.151 ;
     RECT  24 2.137 24.12 2.151 ;
     RECT  29.4 2.137 29.52 2.151 ;
     RECT  34.8 2.137 34.92 2.151 ;
     RECT  40.2 2.137 40.32 2.151 ;
     RECT  45.6 2.137 45.72 2.151 ;
     RECT  51 2.137 51.12 2.151 ;
     RECT  56.4 2.137 56.52 2.151 ;
     RECT  61.8 2.137 61.92 2.151 ;
     RECT  67.2 2.137 67.32 2.151 ;
     RECT  72.6 2.137 72.72 2.151 ;
     RECT  78 2.137 78.12 2.151 ;
     RECT  83.4 2.137 83.52 2.151 ;
     RECT  88.8 2.137 88.92 2.151 ;
     RECT  94.2 2.137 94.32 2.151 ;
     RECT  99.6 2.137 99.72 2.151 ;
     RECT  105 2.137 105.12 2.151 ;
     RECT  115.8 2.137 115.92 2.151 ;
     RECT  121.2 2.137 121.32 2.151 ;
     RECT  126.6 2.137 126.72 2.151 ;
     RECT  132 2.137 132.12 2.151 ;
     RECT  137.4 2.137 137.52 2.151 ;
     RECT  142.8 2.137 142.92 2.151 ;
     RECT  148.2 2.137 148.32 2.151 ;
     RECT  153.6 2.137 153.72 2.151 ;
     RECT  159 2.137 159.12 2.151 ;
     RECT  164.4 2.137 164.52 2.151 ;
     RECT  169.8 2.137 169.92 2.151 ;
     RECT  175.2 2.137 175.32 2.151 ;
     RECT  180.6 2.137 180.72 2.151 ;
     RECT  186 2.137 186.12 2.151 ;
     RECT  191.4 2.137 191.52 2.151 ;
     RECT  196.8 2.137 196.92 2.151 ;
     RECT  202.2 2.137 202.32 2.151 ;
     RECT  207.6 2.137 207.72 2.151 ;
     RECT  213 2.137 213.12 2.151 ;
     RECT  18.6 2.137 19.704 2.821 ;
     RECT  20.736 2.245 20.76 2.821 ;
     RECT  108.504 0.016 108.576 0.084 ;
     RECT  108.6 0.016 108.672 0.084 ;
     RECT  108.696 0.016 108.768 0.084 ;
     RECT  108.792 0.016 108.864 0.084 ;
     RECT  108.888 0.016 108.96 0.084 ;
     RECT  108.984 0.016 109.056 0.084 ;
     RECT  109.08 0.016 109.152 0.084 ;
     RECT  109.176 0.016 109.248 0.084 ;
     RECT  109.272 0.016 109.344 0.084 ;
     RECT  109.368 0.016 109.44 0.084 ;
     RECT  109.464 0.016 109.536 0.084 ;
     RECT  109.56 0.016 109.632 0.084 ;
     RECT  109.656 0.016 109.728 0.084 ;
     RECT  109.752 0.016 109.824 0.084 ;
     RECT  109.848 0.016 109.92 0.084 ;
     RECT  109.944 0.016 110.016 0.084 ;
     RECT  110.04 0.016 110.112 0.084 ;
     RECT  110.136 0.016 110.208 0.084 ;
     RECT  110.232 0.016 110.304 0.084 ;
     RECT  110.328 0.016 110.4 0.084 ;
     RECT  110.424 0.016 110.496 0.084 ;
     RECT  110.52 0.016 110.592 0.084 ;
     RECT  110.616 0.016 110.688 0.084 ;
     RECT  110.712 0.016 110.784 0.084 ;
     RECT  110.808 0.016 110.88 0.084 ;
     RECT  110.904 0.016 110.976 0.084 ;
     RECT  111 0.016 111.072 0.084 ;
     RECT  111.096 0.016 111.168 0.084 ;
     RECT  111.192 0.016 111.264 0.084 ;
     RECT  111.288 0.016 111.36 0.084 ;
     RECT  111.384 0.016 111.456 0.084 ;
     RECT  111.48 0.016 111.552 0.084 ;
     RECT  111.576 0.016 111.648 0.084 ;
     RECT  111.672 0.016 111.744 0.084 ;
     RECT  111.768 0.016 111.84 0.084 ;
     RECT  108.48 0.084 111.864 2.915 ;
     RECT  108.864 2.915 111.384 2.963 ;
     RECT  109.728 2.963 111.384 4.019 ;
     RECT  21.888 1.621 21.912 4.165 ;
     RECT  17.568 3.829 17.592 4.453 ;
     RECT  18.6 2.821 20.76 4.453 ;
     RECT  17.568 4.453 20.76 4.501 ;
     RECT  105 2.151 105.312 4.645 ;
     RECT  34.8 2.151 35.112 5.077 ;
     RECT  104.064 4.645 105.312 5.459 ;
     RECT  115.8 2.151 116.112 5.605 ;
     RECT  112.272 4.501 112.296 5.653 ;
     RECT  104.784 5.459 105.312 5.795 ;
     RECT  110.4 4.019 110.808 5.893 ;
     RECT  115.488 5.605 116.112 6.035 ;
     RECT  106.56 5.317 106.584 6.323 ;
     RECT  109.632 5.893 110.808 6.371 ;
     RECT  99.6 2.151 99.912 6.517 ;
     RECT  100.944 6.373 100.968 6.517 ;
     RECT  17.568 4.501 20.808 6.565 ;
     RECT  21.888 4.165 22.152 6.565 ;
     RECT  41.568 3.877 41.592 6.805 ;
     RECT  112.272 5.653 112.824 6.851 ;
     RECT  109.632 6.371 110.712 6.899 ;
     RECT  112.272 6.851 112.536 7.189 ;
     RECT  115.584 6.035 116.112 7.285 ;
     RECT  115.248 7.285 116.112 7.381 ;
     RECT  99.6 6.517 100.968 7.475 ;
     RECT  115.152 7.381 116.112 7.669 ;
     RECT  110.064 6.899 110.712 7.909 ;
     RECT  112.224 7.189 112.536 7.909 ;
     RECT  112.224 7.909 112.776 7.957 ;
     RECT  37.68 4.453 37.704 8.437 ;
     RECT  105 5.795 105.312 8.437 ;
     RECT  110.016 7.909 110.712 8.677 ;
     RECT  112.224 7.957 113.016 8.677 ;
     RECT  115.152 7.669 116.664 8.723 ;
     RECT  33.024 2.197 33.048 8.819 ;
     RECT  110.016 8.677 113.016 8.819 ;
     RECT  115.8 8.723 116.664 8.821 ;
     RECT  108.864 8.005 108.888 9.011 ;
     RECT  115.8 8.821 116.856 9.011 ;
     RECT  105 8.437 105.672 9.107 ;
     RECT  99.6 7.475 100.104 9.443 ;
     RECT  114.672 9.493 114.696 9.635 ;
     RECT  112.128 8.819 113.016 9.923 ;
     RECT  110.016 8.819 110.712 10.213 ;
     RECT  112.512 9.923 113.016 10.355 ;
     RECT  105 9.107 105.312 10.357 ;
     RECT  34.8 5.077 35.736 10.499 ;
     RECT  105 10.357 105.432 10.499 ;
     RECT  106.656 8.725 106.68 10.883 ;
     RECT  109.632 10.213 110.712 10.979 ;
     RECT  103.872 9.253 103.896 11.027 ;
     RECT  99.6 9.443 100.008 11.509 ;
     RECT  101.472 9.925 101.496 11.555 ;
     RECT  17.568 6.565 22.152 11.701 ;
     RECT  41.568 6.805 42.12 12.083 ;
     RECT  37.152 8.437 37.704 12.227 ;
     RECT  99.6 11.509 100.296 12.563 ;
     RECT  99.6 12.563 100.008 12.995 ;
     RECT  202.2 2.151 202.512 12.997 ;
     RECT  42.096 12.083 42.12 13.427 ;
     RECT  51 2.151 51.312 13.573 ;
     RECT  105 10.499 105.312 13.813 ;
     RECT  83.4 2.151 83.712 14.197 ;
     RECT  37.152 12.227 37.176 14.435 ;
     RECT  200.064 13.717 200.088 14.821 ;
     RECT  201.648 12.997 202.512 15.205 ;
     RECT  201.6 15.205 202.512 15.685 ;
     RECT  94.2 2.151 94.512 15.877 ;
     RECT  199.2 14.821 200.088 15.973 ;
     RECT  112.512 10.355 112.536 16.019 ;
     RECT  126.6 2.151 126.912 16.165 ;
     RECT  74.784 15.877 74.808 16.307 ;
     RECT  91.056 13.093 91.08 16.501 ;
     RECT  83.28 14.197 83.712 16.691 ;
     RECT  201.408 15.685 202.512 16.837 ;
     RECT  16.272 11.941 16.296 17.077 ;
     RECT  17.568 11.701 22.632 17.077 ;
     RECT  24 2.151 24.312 17.077 ;
     RECT  25.488 17.029 25.512 17.077 ;
     RECT  24 17.077 25.512 17.219 ;
     RECT  45.6 2.151 45.912 17.317 ;
     RECT  46.944 17.077 46.968 17.317 ;
     RECT  50.88 13.573 51.312 17.365 ;
     RECT  211.104 14.485 211.128 17.365 ;
     RECT  13.2 2.151 13.512 17.413 ;
     RECT  50.832 17.365 51.312 17.413 ;
     RECT  198.768 15.973 200.088 17.413 ;
     RECT  52.848 17.125 52.872 17.461 ;
     RECT  198.384 17.413 200.088 17.555 ;
     RECT  6.576 16.837 6.6 17.605 ;
     RECT  198.528 17.555 200.088 17.653 ;
     RECT  201.408 16.837 202.824 17.653 ;
     RECT  61.8 2.151 62.112 17.701 ;
     RECT  10.272 17.653 10.296 17.845 ;
     RECT  45.6 17.317 46.968 17.845 ;
     RECT  10.176 17.845 10.296 17.893 ;
     RECT  52.848 17.461 53.304 17.893 ;
     RECT  54.384 17.173 54.408 17.893 ;
     RECT  61.344 17.701 62.112 17.893 ;
     RECT  50.832 17.413 51.576 17.941 ;
     RECT  10.176 17.893 11.064 17.989 ;
     RECT  56.4 2.151 56.712 17.989 ;
     RECT  25.488 17.219 25.512 18.131 ;
     RECT  15.12 17.701 15.144 18.133 ;
     RECT  72.6 2.151 72.912 18.133 ;
     RECT  6.528 17.605 6.6 18.229 ;
     RECT  7.8 2.151 8.112 18.229 ;
     RECT  15.12 18.133 15.288 18.277 ;
     RECT  12.624 17.413 13.512 18.421 ;
     RECT  44.976 17.845 46.968 18.421 ;
     RECT  56.4 17.989 56.808 18.469 ;
     RECT  211.104 17.365 211.224 18.469 ;
     RECT  213 2.151 213.312 18.469 ;
     RECT  56.4 18.469 57.144 18.517 ;
     RECT  72.6 18.133 73.224 18.661 ;
     RECT  14.928 18.277 15.288 18.709 ;
     RECT  80.784 16.501 80.808 18.709 ;
     RECT  83.4 16.691 83.712 18.757 ;
     RECT  72.6 18.661 73.32 18.805 ;
     RECT  74.64 18.421 74.664 18.805 ;
     RECT  198.528 17.653 202.824 18.805 ;
     RECT  25.536 18.181 25.56 18.851 ;
     RECT  14.544 18.709 15.288 18.949 ;
     RECT  16.272 17.077 22.632 18.949 ;
     RECT  196.8 2.151 197.112 18.949 ;
     RECT  48.72 17.605 48.744 19.045 ;
     RECT  6.528 18.229 8.112 19.093 ;
     RECT  9.456 17.989 11.064 19.093 ;
     RECT  6.528 19.093 11.064 19.285 ;
     RECT  12.096 18.421 13.512 19.285 ;
     RECT  50.832 17.941 51.816 19.285 ;
     RECT  52.848 17.893 54.408 19.285 ;
     RECT  70.512 17.653 70.536 19.285 ;
     RECT  6.528 19.285 13.512 19.333 ;
     RECT  90.528 16.501 91.08 19.379 ;
     RECT  196.704 18.949 197.112 19.427 ;
     RECT  6.336 19.333 13.512 19.573 ;
     RECT  14.544 18.949 22.632 19.573 ;
     RECT  50.832 19.285 54.408 19.573 ;
     RECT  78 2.151 78.312 19.621 ;
     RECT  50.832 19.573 54.744 19.859 ;
     RECT  6.336 19.573 22.632 19.909 ;
     RECT  24 17.219 24.312 19.909 ;
     RECT  72.6 18.805 74.664 19.909 ;
     RECT  44.976 18.421 47.592 20.003 ;
     RECT  48.72 19.045 49.656 20.003 ;
     RECT  50.832 19.859 54.648 20.003 ;
     RECT  78 19.621 79.224 20.005 ;
     RECT  80.784 18.709 81.192 20.005 ;
     RECT  6.336 19.909 24.312 20.053 ;
     RECT  50.88 20.003 54.648 20.147 ;
     RECT  45.6 20.003 47.592 20.579 ;
     RECT  48.72 20.003 49.608 20.579 ;
     RECT  50.88 20.147 54.408 20.579 ;
     RECT  56.4 18.517 57.288 20.579 ;
     RECT  90.528 19.379 90.696 20.579 ;
     RECT  90.528 20.579 90.552 20.867 ;
     RECT  43.776 18.613 43.8 20.869 ;
     RECT  38.784 20.677 38.808 20.915 ;
     RECT  78 20.005 81.192 20.963 ;
     RECT  42.768 20.725 42.792 20.965 ;
     RECT  43.776 20.869 43.848 20.965 ;
     RECT  94.08 15.877 94.512 21.011 ;
     RECT  117.312 20.917 117.336 21.059 ;
     RECT  42.768 20.965 43.896 21.061 ;
     RECT  196.8 19.427 197.112 21.109 ;
     RECT  198.144 18.805 202.824 21.109 ;
     RECT  45.6 20.579 47.352 21.155 ;
     RECT  49.584 20.579 49.608 21.155 ;
     RECT  50.88 20.579 51.912 21.155 ;
     RECT  53.28 20.579 54.408 21.155 ;
     RECT  126.6 16.165 127.464 21.155 ;
     RECT  6.336 20.053 24.6 21.253 ;
     RECT  54.528 21.157 54.552 21.299 ;
     RECT  69.6 19.285 70.536 21.299 ;
     RECT  72.336 19.909 74.664 21.299 ;
     RECT  67.2 2.151 67.512 21.301 ;
     RECT  86.064 19.333 86.088 21.301 ;
     RECT  61.344 17.893 62.424 21.347 ;
     RECT  70.512 21.299 70.536 21.347 ;
     RECT  72.6 21.299 74.664 21.347 ;
     RECT  78 20.963 79.848 21.347 ;
     RECT  81.168 20.963 81.192 21.347 ;
     RECT  83.4 18.757 84.36 21.347 ;
     RECT  29.4 2.151 29.712 21.349 ;
     RECT  50.88 21.155 51.432 21.349 ;
     RECT  79.824 21.347 79.848 21.395 ;
     RECT  105 13.813 105.72 21.395 ;
     RECT  207.6 2.151 207.912 21.397 ;
     RECT  85.488 21.301 86.088 21.443 ;
     RECT  98.592 14.773 98.616 21.443 ;
     RECT  29.4 21.349 29.832 21.491 ;
     RECT  40.2 2.151 40.512 21.493 ;
     RECT  78 21.347 78.312 21.493 ;
     RECT  30.864 21.397 30.888 21.539 ;
     RECT  45.6 21.155 46.872 21.539 ;
     RECT  49.92 21.349 51.432 21.539 ;
     RECT  56.4 20.579 56.808 21.541 ;
     RECT  65.328 21.301 67.512 21.541 ;
     RECT  68.496 21.301 68.52 21.541 ;
     RECT  115.8 9.011 116.112 21.541 ;
     RECT  61.8 21.347 62.424 21.589 ;
     RECT  63.84 21.301 63.864 21.589 ;
     RECT  26.784 21.493 26.808 21.635 ;
     RECT  40.2 21.493 41.16 21.635 ;
     RECT  45.6 21.539 46.776 21.635 ;
     RECT  49.92 21.539 49.944 21.635 ;
     RECT  77.28 21.493 78.312 21.635 ;
     RECT  42.432 21.061 43.896 21.731 ;
     RECT  72.6 21.347 73.224 21.731 ;
     RECT  43.344 21.731 43.896 21.779 ;
     RECT  51 21.539 51.432 21.779 ;
     RECT  43.872 21.779 43.896 21.875 ;
     RECT  83.4 21.347 83.832 21.923 ;
     RECT  2.4 2.151 2.712 22.021 ;
     RECT  85.488 21.443 85.512 22.163 ;
     RECT  119.088 21.637 119.112 22.211 ;
     RECT  61.8 21.589 63.864 22.259 ;
     RECT  69.504 21.301 69.528 22.307 ;
     RECT  65.328 21.541 68.52 22.355 ;
     RECT  48.624 21.541 48.648 22.403 ;
     RECT  65.328 22.355 67.512 22.643 ;
     RECT  60.336 21.301 60.36 22.691 ;
     RECT  115.8 21.541 116.28 22.691 ;
     RECT  56.4 21.541 57.048 22.739 ;
     RECT  63.648 22.259 63.864 22.835 ;
     RECT  63.84 22.835 63.864 22.883 ;
     RECT  72.6 21.731 73.128 23.123 ;
     RECT  68.496 22.355 68.52 23.219 ;
     RECT  45.6 21.635 46.2 23.267 ;
     RECT  196.8 21.109 202.824 23.269 ;
     RECT  106.56 21.637 106.584 23.315 ;
     RECT  65.328 22.643 65.352 23.363 ;
     RECT  6.336 21.253 25.08 23.507 ;
     RECT  6.336 23.507 22.92 23.555 ;
     RECT  24 23.507 25.08 23.555 ;
     RECT  196.8 23.269 202.872 23.653 ;
     RECT  6.336 23.555 22.872 23.699 ;
     RECT  6.336 23.699 22.824 23.843 ;
     RECT  6.336 23.843 22.776 24.563 ;
     RECT  6.336 24.563 22.728 26.195 ;
     RECT  6.336 26.195 22.632 27.349 ;
     RECT  6.336 27.349 22.68 27.539 ;
     RECT  211.104 18.469 213.312 27.589 ;
     RECT  196.8 23.653 203.208 35.219 ;
     RECT  198.096 35.219 203.208 35.315 ;
     RECT  198.672 35.315 203.208 35.699 ;
     RECT  199.536 35.699 203.208 35.891 ;
     RECT  6.336 27.539 22.632 36.997 ;
     RECT  5.664 36.997 22.632 38.819 ;
     RECT  2.4 22.021 2.856 39.301 ;
     RECT  2.4 39.301 3.432 40.741 ;
     RECT  2.4 40.741 3.912 40.789 ;
     RECT  2.4 40.789 4.776 40.885 ;
     RECT  6.336 38.819 22.632 40.933 ;
     RECT  2.4 40.885 5.16 41.269 ;
     RECT  6.192 40.933 22.632 41.269 ;
     RECT  2.4 41.269 22.632 41.365 ;
     RECT  0.144 41.221 0.168 41.509 ;
     RECT  2.304 41.365 22.632 41.509 ;
     RECT  0.144 41.509 0.312 41.749 ;
     RECT  2.304 41.509 22.776 41.893 ;
     RECT  0.144 41.749 0.936 41.989 ;
     RECT  2.112 41.893 22.776 44.149 ;
     RECT  0.144 41.989 1.032 44.869 ;
     RECT  2.064 44.149 22.776 44.869 ;
     RECT  216.096 22.501 216.12 44.965 ;
     RECT  216.096 44.965 216.888 45.589 ;
     RECT  215.568 45.589 216.888 46.069 ;
     RECT  210.96 27.589 213.312 46.117 ;
     RECT  215.568 46.069 216.936 46.117 ;
     RECT  215.136 46.117 216.936 46.165 ;
     RECT  199.728 35.891 203.208 46.787 ;
     RECT  0.144 44.869 22.776 47.555 ;
     RECT  215.136 46.165 217.464 47.891 ;
     RECT  210.96 46.117 213.72 48.709 ;
     RECT  210.72 48.709 213.72 48.901 ;
     RECT  215.136 47.891 216.936 48.901 ;
     RECT  199.728 46.787 202.872 49.043 ;
     RECT  210.72 48.901 216.936 49.333 ;
     RECT  210.72 49.333 217.512 49.427 ;
     RECT  0.192 47.555 22.776 49.475 ;
     RECT  215.136 49.427 217.512 49.667 ;
     RECT  215.136 49.667 216.936 50.099 ;
     RECT  210.72 49.427 213.72 50.101 ;
     RECT  0.192 49.475 22.632 50.581 ;
     RECT  207.6 21.397 208.872 51.061 ;
     RECT  210.672 50.101 213.72 51.299 ;
     RECT  210.96 51.299 213.72 51.347 ;
     RECT  207.6 51.061 208.968 51.395 ;
     RECT  215.28 50.099 216.936 52.211 ;
     RECT  0.144 50.581 22.632 52.403 ;
     RECT  215.28 52.211 216.6 52.403 ;
     RECT  207.6 51.395 207.912 52.405 ;
     RECT  215.28 52.403 216.504 52.645 ;
     RECT  214.416 52.645 216.504 53.123 ;
     RECT  215.664 53.123 216.504 53.315 ;
     RECT  216.048 53.315 216.504 53.363 ;
     RECT  206.928 52.405 207.912 53.507 ;
     RECT  0.192 52.403 22.632 53.557 ;
     RECT  216.096 53.363 216.504 53.557 ;
     RECT  0.144 53.557 22.632 53.603 ;
     RECT  216.096 53.557 217.368 53.795 ;
     RECT  205.488 53.557 205.512 54.371 ;
     RECT  216.096 53.795 216.888 54.467 ;
     RECT  216.096 54.467 216.12 54.565 ;
     RECT  207.504 53.507 207.912 54.661 ;
     RECT  208.944 51.395 208.968 54.661 ;
     RECT  0.144 53.603 22.536 54.899 ;
     RECT  207.504 54.661 208.968 54.899 ;
     RECT  215.472 54.565 216.12 54.899 ;
     RECT  0.144 54.899 0.936 55.667 ;
     RECT  0.144 55.667 0.648 55.859 ;
     RECT  2.304 54.899 22.536 55.909 ;
     RECT  207.6 54.899 208.968 55.957 ;
     RECT  0.144 55.859 0.552 56.003 ;
     RECT  207.504 55.957 208.968 56.003 ;
     RECT  2.304 55.909 22.824 56.099 ;
     RECT  0.192 56.003 0.552 56.339 ;
     RECT  210.96 51.347 213.432 56.531 ;
     RECT  0.192 56.339 0.504 56.915 ;
     RECT  207.504 56.003 207.912 56.963 ;
     RECT  0.24 56.915 0.504 57.397 ;
     RECT  210.96 56.531 210.984 57.635 ;
     RECT  0.24 57.397 0.552 57.973 ;
     RECT  212.112 56.531 213.432 57.973 ;
     RECT  199.728 49.043 202.728 58.019 ;
     RECT  211.344 57.973 213.432 58.163 ;
     RECT  211.344 58.163 213.312 58.739 ;
     RECT  0.192 57.973 0.552 58.789 ;
     RECT  0.144 58.789 0.552 58.885 ;
     RECT  220.128 58.789 220.152 58.979 ;
     RECT  199.728 58.019 202.512 59.267 ;
     RECT  208.944 56.003 208.968 59.269 ;
     RECT  0.144 58.885 0.6 59.653 ;
     RECT  215.088 60.325 215.112 60.421 ;
     RECT  216.096 54.899 216.12 60.421 ;
     RECT  215.088 60.421 216.12 60.517 ;
     RECT  214.32 60.517 216.12 60.707 ;
     RECT  215.424 60.707 216.12 60.851 ;
     RECT  200.88 59.267 202.512 60.899 ;
     RECT  208.944 59.269 209.16 60.949 ;
     RECT  208.944 60.949 209.688 60.995 ;
     RECT  200.88 60.899 200.904 61.187 ;
     RECT  214.32 60.707 214.344 61.379 ;
     RECT  212.304 58.739 213.312 61.765 ;
     RECT  199.728 59.267 199.752 61.955 ;
     RECT  212.304 61.765 214.008 62.677 ;
     RECT  216.096 60.851 216.12 62.677 ;
     RECT  212.304 62.677 216.12 62.723 ;
     RECT  217.968 62.773 217.992 62.915 ;
     RECT  211.104 62.005 211.128 63.875 ;
     RECT  2.304 56.099 22.056 64.067 ;
     RECT  0.144 59.653 0.648 64.069 ;
     RECT  196.8 35.219 197.112 64.309 ;
     RECT  212.304 62.723 215.304 64.357 ;
     RECT  216.576 63.205 216.6 64.357 ;
     RECT  0.144 64.069 1.032 64.645 ;
     RECT  0.144 64.645 1.176 64.837 ;
     RECT  2.304 64.067 21.96 64.837 ;
     RECT  209.664 60.995 209.688 64.885 ;
     RECT  212.304 64.357 216.6 64.981 ;
     RECT  212.304 64.981 217.272 65.173 ;
     RECT  212.304 65.173 217.464 65.413 ;
     RECT  212.016 65.413 217.464 65.557 ;
     RECT  209.616 64.885 209.688 65.603 ;
     RECT  0.144 64.837 21.96 66.515 ;
     RECT  212.016 65.557 217.56 66.661 ;
     RECT  211.584 66.661 217.56 66.899 ;
     RECT  196.8 64.309 197.736 66.997 ;
     RECT  212.016 66.899 217.56 67.043 ;
     RECT  209.664 65.603 209.688 67.283 ;
     RECT  213 67.043 217.56 68.483 ;
     RECT  213 68.483 217.512 69.011 ;
     RECT  215.136 69.011 217.512 69.587 ;
     RECT  21.936 66.515 21.96 70.403 ;
     RECT  215.232 69.587 217.512 70.645 ;
     RECT  215.232 70.645 217.704 70.835 ;
     RECT  215.232 70.835 217.512 70.931 ;
     RECT  215.232 70.931 216.456 70.979 ;
     RECT  0.144 66.515 20.904 71.267 ;
     RECT  215.232 70.979 216.408 71.315 ;
     RECT  217.488 70.931 217.512 71.315 ;
     RECT  215.232 71.315 216.072 71.363 ;
     RECT  12.72 71.267 20.904 71.507 ;
     RECT  12.72 71.507 17.544 72.227 ;
     RECT  0.144 71.267 11.4 73.333 ;
     RECT  12.816 72.227 17.544 73.379 ;
     RECT  0.048 73.333 11.4 73.667 ;
     RECT  0.048 73.667 10.296 73.907 ;
     RECT  12.816 73.379 15.096 74.435 ;
     RECT  213 69.011 214.008 74.963 ;
     RECT  16.224 73.379 17.544 75.011 ;
     RECT  16.224 75.011 16.248 75.443 ;
     RECT  14.496 74.435 15.096 75.491 ;
     RECT  17.52 75.011 17.544 75.683 ;
     RECT  15.072 75.491 15.096 76.787 ;
     RECT  12.816 74.435 13.512 77.315 ;
     RECT  11.376 73.667 11.4 77.603 ;
     RECT  0.048 73.907 10.152 77.651 ;
     RECT  0.048 77.651 9.816 78.179 ;
     RECT  0.048 78.179 9.144 78.659 ;
     RECT  1.392 78.659 9.144 78.707 ;
     RECT  1.392 78.707 6.36 78.755 ;
     RECT  0.048 78.659 0.168 78.995 ;
     RECT  1.392 78.755 5.976 78.995 ;
     RECT  7.392 78.707 9.144 79.283 ;
     RECT  7.8 79.283 9.144 79.331 ;
     RECT  7.8 79.331 8.424 79.475 ;
     RECT  0.048 78.995 0.072 79.571 ;
     RECT  5.952 78.995 5.976 79.859 ;
     RECT  1.392 78.995 4.872 79.907 ;
     RECT  4.272 79.907 4.776 79.955 ;
     RECT  4.272 79.955 4.344 80.003 ;
     RECT  1.392 79.907 3 80.051 ;
     RECT  2.4 80.051 3 80.099 ;
     RECT  4.272 80.003 4.296 80.099 ;
     RECT  1.392 80.051 1.416 80.147 ;
     RECT  215.232 71.363 215.256 87.251 ;
     RECT  213 74.963 213.768 91.811 ;
     RECT  18.6 71.507 20.904 96.371 ;
     RECT  196.8 66.997 197.784 96.755 ;
     RECT  18.6 96.371 20.856 99.203 ;
     RECT  22.896 96.853 22.92 99.685 ;
     RECT  18.6 99.203 19.896 100.261 ;
     RECT  196.8 96.755 197.736 104.579 ;
     RECT  18.6 100.261 20.52 104.915 ;
     RECT  22.752 99.685 22.92 105.683 ;
     RECT  92.976 96.709 93 106.067 ;
     RECT  22.752 105.683 22.776 107.315 ;
     RECT  20.4 104.915 20.52 107.555 ;
     RECT  20.4 107.555 20.424 107.603 ;
     RECT  18.6 104.915 19.032 107.795 ;
     RECT  2.4 80.099 2.712 114.489 ;
     RECT  7.8 79.475 8.112 114.489 ;
     RECT  13.2 77.315 13.512 114.489 ;
     RECT  18.6 107.795 18.912 114.489 ;
     RECT  24 23.555 24.312 114.489 ;
     RECT  29.4 21.491 29.712 114.489 ;
     RECT  34.8 10.499 35.112 114.489 ;
     RECT  40.2 21.635 40.512 114.489 ;
     RECT  45.6 23.267 45.912 114.489 ;
     RECT  51 21.779 51.312 114.489 ;
     RECT  56.4 22.739 56.712 114.489 ;
     RECT  61.8 22.259 62.112 114.489 ;
     RECT  67.2 22.643 67.512 114.489 ;
     RECT  72.6 23.123 72.912 114.489 ;
     RECT  78 21.635 78.312 114.489 ;
     RECT  83.4 21.923 83.712 114.489 ;
     RECT  88.8 2.151 89.112 114.489 ;
     RECT  94.2 21.011 94.512 114.489 ;
     RECT  99.6 12.995 99.912 114.489 ;
     RECT  105 21.395 105.312 114.489 ;
     RECT  110.4 10.979 110.712 114.489 ;
     RECT  115.8 22.691 116.112 114.489 ;
     RECT  121.2 2.151 121.512 114.489 ;
     RECT  126.6 21.155 126.912 114.489 ;
     RECT  132 2.151 132.312 114.489 ;
     RECT  137.4 2.151 137.712 114.489 ;
     RECT  142.8 2.151 143.112 114.489 ;
     RECT  148.2 2.151 148.512 114.489 ;
     RECT  153.6 2.151 153.912 114.489 ;
     RECT  159 2.151 159.312 114.489 ;
     RECT  164.4 2.151 164.712 114.489 ;
     RECT  169.8 2.151 170.112 114.489 ;
     RECT  175.2 2.151 175.512 114.489 ;
     RECT  180.6 2.151 180.912 114.489 ;
     RECT  186 2.151 186.312 114.489 ;
     RECT  191.4 2.151 191.712 114.489 ;
     RECT  196.8 104.579 197.112 114.489 ;
     RECT  202.2 60.899 202.512 114.489 ;
     RECT  207.6 56.963 207.912 114.489 ;
     RECT  213 91.811 213.312 114.489 ;
     RECT  2.4 114.489 2.52 114.503 ;
     RECT  7.8 114.489 7.92 114.503 ;
     RECT  13.2 114.489 13.32 114.503 ;
     RECT  18.6 114.489 18.72 114.503 ;
     RECT  24 114.489 24.12 114.503 ;
     RECT  29.4 114.489 29.52 114.503 ;
     RECT  34.8 114.489 34.92 114.503 ;
     RECT  40.2 114.489 40.32 114.503 ;
     RECT  45.6 114.489 45.72 114.503 ;
     RECT  51 114.489 51.12 114.503 ;
     RECT  56.4 114.489 56.52 114.503 ;
     RECT  61.8 114.489 61.92 114.503 ;
     RECT  67.2 114.489 67.32 114.503 ;
     RECT  72.6 114.489 72.72 114.503 ;
     RECT  78 114.489 78.12 114.503 ;
     RECT  83.4 114.489 83.52 114.503 ;
     RECT  88.8 114.489 88.92 114.503 ;
     RECT  94.2 114.489 94.32 114.503 ;
     RECT  99.6 114.489 99.72 114.503 ;
     RECT  105 114.489 105.12 114.503 ;
     RECT  110.4 114.489 110.52 114.503 ;
     RECT  115.8 114.489 115.92 114.503 ;
     RECT  121.2 114.489 121.32 114.503 ;
     RECT  126.6 114.489 126.72 114.503 ;
     RECT  132 114.489 132.12 114.503 ;
     RECT  137.4 114.489 137.52 114.503 ;
     RECT  142.8 114.489 142.92 114.503 ;
     RECT  148.2 114.489 148.32 114.503 ;
     RECT  153.6 114.489 153.72 114.503 ;
     RECT  159 114.489 159.12 114.503 ;
     RECT  164.4 114.489 164.52 114.503 ;
     RECT  169.8 114.489 169.92 114.503 ;
     RECT  175.2 114.489 175.32 114.503 ;
     RECT  180.6 114.489 180.72 114.503 ;
     RECT  186 114.489 186.12 114.503 ;
     RECT  191.4 114.489 191.52 114.503 ;
     RECT  196.8 114.489 196.92 114.503 ;
     RECT  202.2 114.489 202.32 114.503 ;
     RECT  207.6 114.489 207.72 114.503 ;
     RECT  213 114.489 213.12 114.503 ;
     RECT  19.704 2.245 20.736 2.821 ;
     RECT  20.76 2.245 21.888 4.501 ;
     RECT  17.592 3.829 18.6 4.453 ;
     RECT  40.512 3.877 41.568 12.083 ;
     RECT  110.808 4.019 111.384 4.501 ;
     RECT  20.808 4.501 21.888 6.565 ;
     RECT  110.808 4.501 112.272 6.371 ;
     RECT  105.312 5.317 106.56 6.323 ;
     RECT  115.488 6.035 115.584 7.285 ;
     RECT  110.712 6.371 112.272 7.189 ;
     RECT  99.912 6.373 100.944 6.517 ;
     RECT  112.536 6.851 112.824 7.909 ;
     RECT  109.632 6.899 110.064 7.909 ;
     RECT  110.712 7.189 112.224 8.677 ;
     RECT  109.632 7.909 110.016 8.005 ;
     RECT  112.776 7.909 112.824 7.957 ;
     RECT  108.888 8.005 110.016 9.011 ;
     RECT  35.736 8.437 37.152 10.499 ;
     RECT  115.152 8.723 115.8 9.493 ;
     RECT  105.672 8.725 106.656 9.107 ;
     RECT  110.712 8.819 112.128 9.923 ;
     RECT  109.632 9.011 110.016 10.213 ;
     RECT  105.312 9.107 106.656 10.357 ;
     RECT  103.896 9.253 105 11.027 ;
     RECT  100.008 9.443 100.104 9.925 ;
     RECT  114.696 9.493 115.8 9.635 ;
     RECT  100.008 9.925 101.472 11.509 ;
     RECT  105.432 10.357 106.656 10.499 ;
     RECT  105.312 10.499 106.656 10.883 ;
     RECT  100.296 11.509 101.472 11.555 ;
     RECT  22.632 11.701 24 19.909 ;
     RECT  16.296 11.941 17.568 17.077 ;
     RECT  98.616 14.773 99.6 21.443 ;
     RECT  200.088 15.205 201.6 15.685 ;
     RECT  200.088 15.685 201.408 17.653 ;
     RECT  89.112 16.501 90.528 20.867 ;
     RECT  6.6 16.837 7.8 18.229 ;
     RECT  24.312 17.029 25.488 17.077 ;
     RECT  45.912 17.077 46.944 17.317 ;
     RECT  52.872 17.173 54.384 17.461 ;
     RECT  24.312 17.219 25.488 18.131 ;
     RECT  51.576 17.413 52.848 17.941 ;
     RECT  197.112 17.413 198.384 17.555 ;
     RECT  53.304 17.461 54.384 17.893 ;
     RECT  197.112 17.555 198.528 18.805 ;
     RECT  15.144 17.701 16.272 18.133 ;
     RECT  51.816 17.941 52.848 19.285 ;
     RECT  8.112 17.989 9.456 19.093 ;
     RECT  24.312 18.131 25.512 18.181 ;
     RECT  15.288 18.133 16.272 18.949 ;
     RECT  24.312 18.181 25.536 18.851 ;
     RECT  13.512 18.277 14.928 18.709 ;
     RECT  11.064 18.421 12.096 19.285 ;
     RECT  47.592 18.421 48.72 20.579 ;
     RECT  73.224 18.421 74.64 18.661 ;
     RECT  43.8 18.613 44.976 20.003 ;
     RECT  73.32 18.661 74.64 18.805 ;
     RECT  13.512 18.709 14.544 19.573 ;
     RECT  197.112 18.805 198.144 21.109 ;
     RECT  24.312 18.851 24.6 20.053 ;
     RECT  49.656 19.045 50.832 20.003 ;
     RECT  43.8 20.003 43.896 20.869 ;
     RECT  49.608 20.003 50.88 21.155 ;
     RECT  54.408 20.147 54.552 21.155 ;
     RECT  47.352 20.579 49.584 21.155 ;
     RECT  51.912 20.579 53.28 21.155 ;
     RECT  56.808 20.579 57.048 21.541 ;
     RECT  38.808 20.677 40.2 20.915 ;
     RECT  42.792 20.725 43.776 20.965 ;
     RECT  43.848 20.869 43.896 20.965 ;
     RECT  116.112 20.917 117.312 21.059 ;
     RECT  79.848 20.963 81.168 21.347 ;
     RECT  116.112 21.059 116.28 21.541 ;
     RECT  48.624 21.155 50.88 21.349 ;
     RECT  54.528 21.155 54.552 21.157 ;
     RECT  69.6 21.299 70.512 21.301 ;
     RECT  60.36 21.301 61.344 21.347 ;
     RECT  62.424 21.301 63.84 21.589 ;
     RECT  63.864 21.301 65.328 22.883 ;
     RECT  67.512 21.301 68.496 21.541 ;
     RECT  68.52 21.301 69.504 22.307 ;
     RECT  69.528 21.301 70.512 21.347 ;
     RECT  84.36 21.301 85.488 21.347 ;
     RECT  60.36 21.347 61.8 22.691 ;
     RECT  78.312 21.347 79.824 21.395 ;
     RECT  48.624 21.349 49.92 21.541 ;
     RECT  105.312 21.395 105.72 21.637 ;
     RECT  29.832 21.397 30.864 21.491 ;
     RECT  29.712 21.491 30.864 21.539 ;
     RECT  41.16 21.493 42.432 21.635 ;
     RECT  49.944 21.539 51 21.635 ;
     RECT  48.648 21.541 49.92 21.635 ;
     RECT  105.312 21.637 106.56 23.315 ;
     RECT  67.512 22.355 68.496 23.219 ;
     RECT  22.92 23.507 24 23.555 ;
     RECT  22.872 23.555 24 23.699 ;
     RECT  22.824 23.699 24 23.843 ;
     RECT  22.776 23.843 24 24.563 ;
     RECT  22.728 24.563 24 26.195 ;
     RECT  22.632 26.195 24 27.349 ;
     RECT  22.68 27.349 24 27.539 ;
     RECT  22.632 27.539 24 41.509 ;
     RECT  197.112 35.219 198.096 35.315 ;
     RECT  5.16 40.885 6.336 40.933 ;
     RECT  5.16 40.933 6.192 41.269 ;
     RECT  22.776 41.509 24 49.475 ;
     RECT  0.936 41.749 2.304 41.893 ;
     RECT  0.936 41.893 2.112 41.989 ;
     RECT  1.032 41.989 2.112 44.149 ;
     RECT  1.032 44.149 2.064 44.869 ;
     RECT  213.72 46.117 215.136 48.901 ;
     RECT  216.936 47.891 217.464 49.333 ;
     RECT  213.72 49.427 215.136 50.099 ;
     RECT  22.632 49.475 24 53.603 ;
     RECT  213.432 51.347 213.72 52.645 ;
     RECT  207.912 51.395 208.944 54.661 ;
     RECT  216.6 52.211 216.936 52.403 ;
     RECT  0.144 52.403 0.192 53.557 ;
     RECT  216.504 52.403 216.936 53.557 ;
     RECT  213.432 52.645 214.416 53.123 ;
     RECT  215.472 53.123 215.664 53.315 ;
     RECT  215.472 53.315 216.048 53.363 ;
     RECT  215.472 53.363 216.096 54.565 ;
     RECT  22.536 53.603 24 55.909 ;
     RECT  0.936 54.899 2.304 55.667 ;
     RECT  207.504 54.899 207.6 55.957 ;
     RECT  22.824 55.909 24 56.099 ;
     RECT  207.912 56.003 208.944 60.995 ;
     RECT  0.504 56.339 0.552 57.397 ;
     RECT  210.984 56.531 212.112 57.635 ;
     RECT  0.192 56.915 0.24 57.973 ;
     RECT  211.344 57.635 212.112 57.973 ;
     RECT  199.752 59.267 200.88 61.187 ;
     RECT  215.112 60.325 216.096 60.421 ;
     RECT  213.312 60.517 214.32 61.379 ;
     RECT  214.344 60.707 215.424 60.851 ;
     RECT  200.904 60.899 202.2 61.187 ;
     RECT  213.312 61.379 214.344 61.765 ;
     RECT  214.008 61.765 214.344 62.677 ;
     RECT  209.688 62.005 211.104 63.875 ;
     RECT  211.128 62.005 212.304 63.875 ;
     RECT  215.304 62.723 216.12 63.205 ;
     RECT  215.304 63.205 216.576 64.357 ;
     RECT  1.032 64.069 2.304 64.645 ;
     RECT  1.176 64.645 2.304 64.837 ;
     RECT  20.904 66.515 21.936 70.403 ;
     RECT  214.008 69.011 215.136 69.587 ;
     RECT  214.008 69.587 215.232 74.963 ;
     RECT  216.456 70.931 217.488 70.979 ;
     RECT  216.408 70.979 217.488 71.315 ;
     RECT  11.4 71.267 12.72 72.227 ;
     RECT  17.544 71.507 18.6 75.683 ;
     RECT  11.4 72.227 12.816 77.315 ;
     RECT  15.096 73.379 16.224 75.443 ;
     RECT  10.296 73.667 11.376 73.907 ;
     RECT  10.152 73.907 11.376 77.603 ;
     RECT  13.512 74.435 14.496 75.491 ;
     RECT  213.768 74.963 215.232 87.251 ;
     RECT  16.248 75.011 17.52 75.443 ;
     RECT  0.168 78.659 1.392 78.995 ;
     RECT  6.36 78.707 7.392 78.755 ;
     RECT  5.976 78.755 7.392 79.283 ;
     RECT  0.072 78.995 1.392 79.571 ;
     RECT  4.872 78.995 5.952 79.859 ;
     RECT  3 79.907 4.272 80.099 ;
     RECT  1.416 80.051 2.4 80.147 ;
     RECT  93 96.709 94.2 106.067 ;
     RECT  22.92 96.853 24 105.683 ;
     RECT  19.896 99.203 20.52 100.261 ;
     RECT  19.032 104.915 20.4 107.603 ;
     RECT  22.776 105.683 24 107.315 ;
  END
END hfd_hgi_vm_calendar
END LIBRARY
